VERSION 5.8 ;
BUSBITCHARS "[]" ;
DIVIDERCHAR "/" ;
UNITS
    DATABASE MICRONS 1000 ;
END UNITS

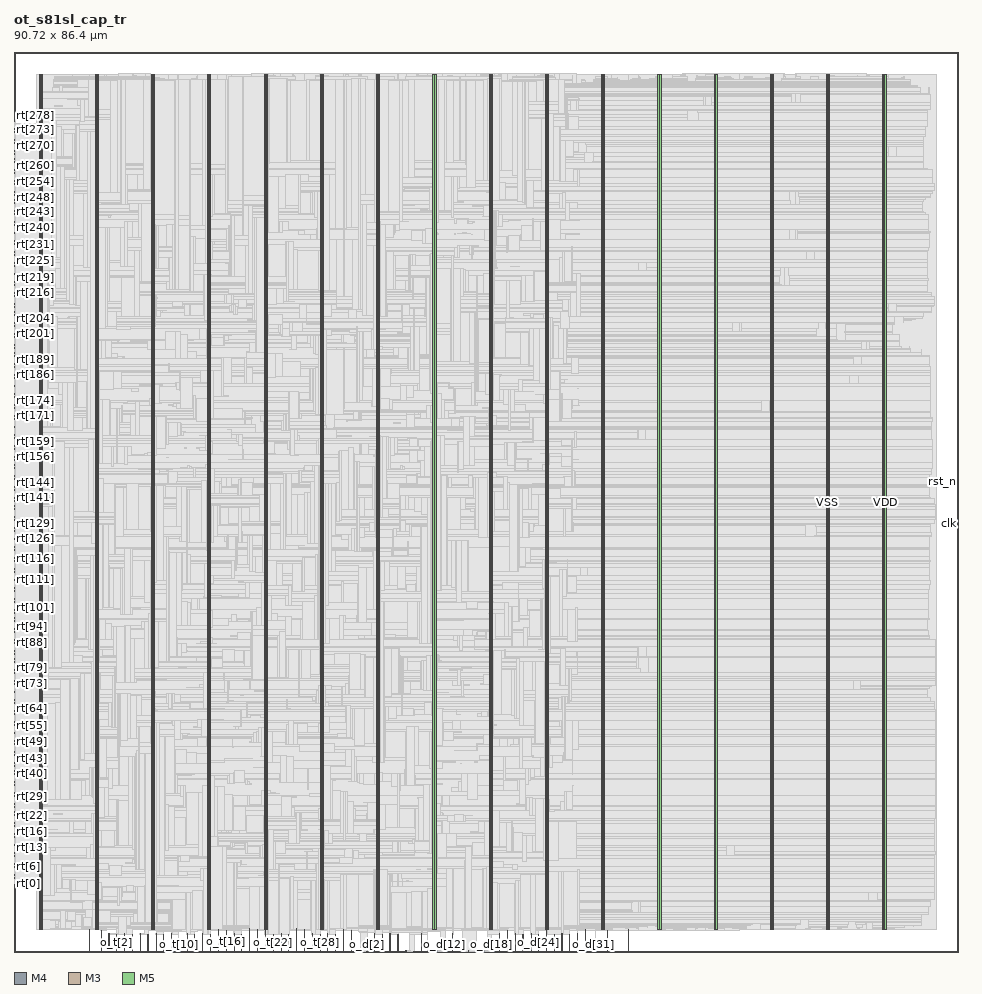
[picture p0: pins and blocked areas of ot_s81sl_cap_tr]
MACRO ot_s81sl_cap_tr
  FOREIGN ot_s81sl_cap_tr 0 0 ;
  CLASS BLOCK ;
  SIZE 90.72 BY 86.4 ;
  PIN clk
    DIRECTION INPUT ;
    USE SIGNAL ;
    PORT
      LAYER M4 ;
        RECT  90.636 41.04 90.72 41.064 ;
    END
    PORT
      LAYER M4 ;
        RECT  90.601 41.04 90.641 41.16 ;
    END
    PORT
      LAYER M4 ;
        RECT  90.641 41.04 90.684 41.064 ;
    END
  END clk
  PIN fault
    DIRECTION OUTPUT ;
    USE SIGNAL ;
    PORT
      LAYER M3 ;
        RECT  59.004 0 59.022 0.038 ;
    END
    PORT
      LAYER M3 ;
        RECT  59.004 0.012 59.022 2.191 ;
    END
  END fault
  PIN o_d[0]
    DIRECTION OUTPUT ;
    USE SIGNAL ;
    PORT
      LAYER M3 ;
        RECT  32.364 0 32.382 0.038 ;
    END
    PORT
      LAYER M3 ;
        RECT  32.364 0.012 32.382 2.029 ;
    END
  END o_d[0]
  PIN o_d[10]
    DIRECTION OUTPUT ;
    USE SIGNAL ;
    PORT
      LAYER M3 ;
        RECT  39.852 0 39.87 0.038 ;
    END
    PORT
      LAYER M3 ;
        RECT  39.852 0.012 39.87 0.031 ;
    END
    PORT
      LAYER M3 ;
        RECT  39.708 0.031 39.87 0.059 ;
    END
  END o_d[10]
  PIN o_d[11]
    DIRECTION OUTPUT ;
    USE SIGNAL ;
    PORT
      LAYER M5 ;
        RECT  40.608 0 40.632 0.084 ;
    END
    PORT
      LAYER M5 ;
        RECT  40.608 0.016 40.632 0.131 ;
    END
  END o_d[11]
  PIN o_d[12]
    DIRECTION OUTPUT ;
    USE SIGNAL ;
    PORT
      LAYER M3 ;
        RECT  41.364 0 41.382 0.038 ;
    END
    PORT
      LAYER M3 ;
        RECT  41.364 0.012 41.382 0.091 ;
    END
  END o_d[12]
  PIN o_d[13]
    DIRECTION OUTPUT ;
    USE SIGNAL ;
    PORT
      LAYER M5 ;
        RECT  42.096 0 42.12 0.084 ;
    END
    PORT
      LAYER M5 ;
        RECT  42.096 0.016 42.12 1.763 ;
    END
  END o_d[13]
  PIN o_d[14]
    DIRECTION OUTPUT ;
    USE SIGNAL ;
    PORT
      LAYER M3 ;
        RECT  42.876 0 42.894 0.038 ;
    END
    PORT
      LAYER M3 ;
        RECT  42.876 0.012 42.894 0.031 ;
    END
    PORT
      LAYER M3 ;
        RECT  42.876 0.031 43.11 0.059 ;
    END
  END o_d[14]
  PIN o_d[15]
    DIRECTION OUTPUT ;
    USE SIGNAL ;
    PORT
      LAYER M5 ;
        RECT  43.632 0 43.656 0.084 ;
    END
    PORT
      LAYER M5 ;
        RECT  43.632 0.016 43.656 0.131 ;
    END
  END o_d[15]
  PIN o_d[16]
    DIRECTION OUTPUT ;
    USE SIGNAL ;
    PORT
      LAYER M3 ;
        RECT  44.352 0 44.37 0.038 ;
    END
    PORT
      LAYER M3 ;
        RECT  44.352 0.012 44.37 0.091 ;
    END
  END o_d[16]
  PIN o_d[17]
    DIRECTION OUTPUT ;
    USE SIGNAL ;
    PORT
      LAYER M5 ;
        RECT  45.12 0 45.144 0.084 ;
    END
    PORT
      LAYER M5 ;
        RECT  45.12 0.016 45.144 0.131 ;
    END
  END o_d[17]
  PIN o_d[18]
    DIRECTION OUTPUT ;
    USE SIGNAL ;
    PORT
      LAYER M3 ;
        RECT  45.864 0 45.882 0.038 ;
    END
    PORT
      LAYER M3 ;
        RECT  45.864 0.012 45.882 0.091 ;
    END
  END o_d[18]
  PIN o_d[19]
    DIRECTION OUTPUT ;
    USE SIGNAL ;
    PORT
      LAYER M5 ;
        RECT  46.608 0 46.632 0.084 ;
    END
    PORT
      LAYER M5 ;
        RECT  46.608 0.016 46.632 1.763 ;
    END
  END o_d[19]
  PIN o_d[1]
    DIRECTION OUTPUT ;
    USE SIGNAL ;
    PORT
      LAYER M5 ;
        RECT  33.12 0 33.144 0.084 ;
    END
    PORT
      LAYER M5 ;
        RECT  33.12 0.016 33.144 0.131 ;
    END
  END o_d[1]
  PIN o_d[20]
    DIRECTION OUTPUT ;
    USE SIGNAL ;
    PORT
      LAYER M3 ;
        RECT  47.376 0 47.394 0.038 ;
    END
    PORT
      LAYER M3 ;
        RECT  47.376 0.012 47.394 2.029 ;
    END
  END o_d[20]
  PIN o_d[21]
    DIRECTION OUTPUT ;
    USE SIGNAL ;
    PORT
      LAYER M5 ;
        RECT  48.096 0 48.12 0.084 ;
    END
    PORT
      LAYER M5 ;
        RECT  48.096 0.016 48.12 1.763 ;
    END
  END o_d[21]
  PIN o_d[22]
    DIRECTION OUTPUT ;
    USE SIGNAL ;
    PORT
      LAYER M3 ;
        RECT  48.852 0 48.87 0.038 ;
    END
    PORT
      LAYER M3 ;
        RECT  48.852 0.012 48.87 1.723 ;
    END
  END o_d[22]
  PIN o_d[23]
    DIRECTION OUTPUT ;
    USE SIGNAL ;
    PORT
      LAYER M5 ;
        RECT  49.632 0 49.656 0.084 ;
    END
    PORT
      LAYER M5 ;
        RECT  49.632 0.016 49.656 1.763 ;
    END
  END o_d[23]
  PIN o_d[24]
    DIRECTION OUTPUT ;
    USE SIGNAL ;
    PORT
      LAYER M3 ;
        RECT  50.364 0 50.382 0.038 ;
    END
    PORT
      LAYER M3 ;
        RECT  50.364 0.012 50.382 1.723 ;
    END
  END o_d[24]
  PIN o_d[25]
    DIRECTION OUTPUT ;
    USE SIGNAL ;
    PORT
      LAYER M5 ;
        RECT  51.12 0 51.144 0.084 ;
    END
    PORT
      LAYER M5 ;
        RECT  51.12 0.016 51.144 2.137 ;
    END
  END o_d[25]
  PIN o_d[26]
    DIRECTION OUTPUT ;
    USE SIGNAL ;
    PORT
      LAYER M3 ;
        RECT  51.876 0 51.894 0.038 ;
    END
    PORT
      LAYER M3 ;
        RECT  51.876 0.012 51.894 1.723 ;
    END
  END o_d[26]
  PIN o_d[27]
    DIRECTION OUTPUT ;
    USE SIGNAL ;
    PORT
      LAYER M5 ;
        RECT  52.608 0 52.632 0.084 ;
    END
    PORT
      LAYER M5 ;
        RECT  52.608 0.016 52.632 1.763 ;
    END
  END o_d[27]
  PIN o_d[28]
    DIRECTION OUTPUT ;
    USE SIGNAL ;
    PORT
      LAYER M3 ;
        RECT  53.352 0 53.37 0.038 ;
    END
    PORT
      LAYER M3 ;
        RECT  53.352 0.012 53.37 1.723 ;
    END
  END o_d[28]
  PIN o_d[29]
    DIRECTION OUTPUT ;
    USE SIGNAL ;
    PORT
      LAYER M5 ;
        RECT  54.096 0 54.12 0.084 ;
    END
    PORT
      LAYER M5 ;
        RECT  54.096 0.016 54.12 1.763 ;
    END
  END o_d[29]
  PIN o_d[2]
    DIRECTION OUTPUT ;
    USE SIGNAL ;
    PORT
      LAYER M3 ;
        RECT  33.876 0 33.894 0.038 ;
    END
    PORT
      LAYER M3 ;
        RECT  33.876 0.012 33.894 0.091 ;
    END
  END o_d[2]
  PIN o_d[30]
    DIRECTION OUTPUT ;
    USE SIGNAL ;
    PORT
      LAYER M3 ;
        RECT  54.864 0 54.882 0.038 ;
    END
    PORT
      LAYER M3 ;
        RECT  54.864 0.012 54.882 2.191 ;
    END
  END o_d[30]
  PIN o_d[31]
    DIRECTION OUTPUT ;
    USE SIGNAL ;
    PORT
      LAYER M5 ;
        RECT  55.632 0 55.656 0.084 ;
    END
    PORT
      LAYER M5 ;
        RECT  55.632 0.016 55.656 0.611 ;
    END
  END o_d[31]
  PIN o_d[3]
    DIRECTION OUTPUT ;
    USE SIGNAL ;
    PORT
      LAYER M5 ;
        RECT  34.608 0 34.632 0.084 ;
    END
    PORT
      LAYER M5 ;
        RECT  34.608 0.016 34.632 1.763 ;
    END
  END o_d[3]
  PIN o_d[4]
    DIRECTION OUTPUT ;
    USE SIGNAL ;
    PORT
      LAYER M3 ;
        RECT  35.352 0 35.37 0.038 ;
    END
    PORT
      LAYER M3 ;
        RECT  35.352 0.012 35.37 1.723 ;
    END
  END o_d[4]
  PIN o_d[5]
    DIRECTION OUTPUT ;
    USE SIGNAL ;
    PORT
      LAYER M5 ;
        RECT  36.096 0 36.12 0.084 ;
    END
    PORT
      LAYER M5 ;
        RECT  36.096 0.016 36.12 1.763 ;
    END
  END o_d[5]
  PIN o_d[6]
    DIRECTION OUTPUT ;
    USE SIGNAL ;
    PORT
      LAYER M3 ;
        RECT  36.864 0 36.882 0.038 ;
    END
    PORT
      LAYER M3 ;
        RECT  36.864 0.012 36.882 1.723 ;
    END
  END o_d[6]
  PIN o_d[7]
    DIRECTION OUTPUT ;
    USE SIGNAL ;
    PORT
      LAYER M5 ;
        RECT  37.632 0 37.656 0.084 ;
    END
    PORT
      LAYER M5 ;
        RECT  37.632 0.016 37.656 0.131 ;
    END
  END o_d[7]
  PIN o_d[8]
    DIRECTION OUTPUT ;
    USE SIGNAL ;
    PORT
      LAYER M3 ;
        RECT  38.376 0 38.394 0.038 ;
    END
    PORT
      LAYER M3 ;
        RECT  38.376 0.012 38.394 0.031 ;
    END
    PORT
      LAYER M3 ;
        RECT  38.376 0.031 38.466 0.091 ;
    END
  END o_d[8]
  PIN o_d[9]
    DIRECTION OUTPUT ;
    USE SIGNAL ;
    PORT
      LAYER M5 ;
        RECT  39.12 0 39.144 0.084 ;
    END
    PORT
      LAYER M5 ;
        RECT  39.12 0.016 39.144 1.763 ;
    END
  END o_d[9]
  PIN o_e
    DIRECTION OUTPUT ;
    USE SIGNAL ;
    PORT
      LAYER M3 ;
        RECT  56.988 0 57.006 0.038 ;
    END
    PORT
      LAYER M3 ;
        RECT  56.988 0.012 57.006 2.029 ;
    END
  END o_e
  PIN o_t[0]
    DIRECTION OUTPUT ;
    USE SIGNAL ;
    PORT
      LAYER M3 ;
        RECT  8.352 0 8.37 0.038 ;
    END
    PORT
      LAYER M3 ;
        RECT  8.352 0.012 8.37 2.101 ;
    END
  END o_t[0]
  PIN o_t[10]
    DIRECTION OUTPUT ;
    USE SIGNAL ;
    PORT
      LAYER M3 ;
        RECT  15.876 0 15.894 0.038 ;
    END
    PORT
      LAYER M3 ;
        RECT  15.876 0.012 15.894 0.031 ;
    END
    PORT
      LAYER M3 ;
        RECT  15.804 0.031 15.894 0.059 ;
    END
  END o_t[10]
  PIN o_t[11]
    DIRECTION OUTPUT ;
    USE SIGNAL ;
    PORT
      LAYER M5 ;
        RECT  16.608 0 16.632 0.084 ;
    END
    PORT
      LAYER M5 ;
        RECT  16.608 0.016 16.632 1.763 ;
    END
  END o_t[11]
  PIN o_t[12]
    DIRECTION OUTPUT ;
    USE SIGNAL ;
    PORT
      LAYER M3 ;
        RECT  17.352 0 17.37 0.038 ;
    END
    PORT
      LAYER M3 ;
        RECT  17.352 0.012 17.37 1.723 ;
    END
  END o_t[12]
  PIN o_t[13]
    DIRECTION OUTPUT ;
    USE SIGNAL ;
    PORT
      LAYER M5 ;
        RECT  18.096 0 18.12 0.084 ;
    END
    PORT
      LAYER M5 ;
        RECT  18.096 0.016 18.12 1.763 ;
    END
  END o_t[13]
  PIN o_t[14]
    DIRECTION OUTPUT ;
    USE SIGNAL ;
    PORT
      LAYER M3 ;
        RECT  18.864 0 18.882 0.038 ;
    END
    PORT
      LAYER M3 ;
        RECT  18.864 0.012 18.882 1.723 ;
    END
  END o_t[14]
  PIN o_t[15]
    DIRECTION OUTPUT ;
    USE SIGNAL ;
    PORT
      LAYER M5 ;
        RECT  19.632 0 19.656 0.084 ;
    END
    PORT
      LAYER M5 ;
        RECT  19.632 0.016 19.656 2.137 ;
    END
  END o_t[15]
  PIN o_t[16]
    DIRECTION OUTPUT ;
    USE SIGNAL ;
    PORT
      LAYER M3 ;
        RECT  20.376 0 20.394 0.038 ;
    END
    PORT
      LAYER M3 ;
        RECT  20.376 0.012 20.394 2.029 ;
    END
  END o_t[16]
  PIN o_t[17]
    DIRECTION OUTPUT ;
    USE SIGNAL ;
    PORT
      LAYER M5 ;
        RECT  21.12 0 21.144 0.084 ;
    END
    PORT
      LAYER M5 ;
        RECT  21.12 0.016 21.144 1.763 ;
    END
  END o_t[17]
  PIN o_t[18]
    DIRECTION OUTPUT ;
    USE SIGNAL ;
    PORT
      LAYER M3 ;
        RECT  21.852 0 21.87 0.038 ;
    END
    PORT
      LAYER M3 ;
        RECT  21.852 0.012 21.87 1.723 ;
    END
  END o_t[18]
  PIN o_t[19]
    DIRECTION OUTPUT ;
    USE SIGNAL ;
    PORT
      LAYER M5 ;
        RECT  22.608 0 22.632 0.084 ;
    END
    PORT
      LAYER M5 ;
        RECT  22.608 0.016 22.632 2.243 ;
    END
  END o_t[19]
  PIN o_t[1]
    DIRECTION OUTPUT ;
    USE SIGNAL ;
    PORT
      LAYER M5 ;
        RECT  9.12 0 9.144 0.084 ;
    END
    PORT
      LAYER M5 ;
        RECT  9.12 0.016 9.144 1.763 ;
    END
  END o_t[1]
  PIN o_t[20]
    DIRECTION OUTPUT ;
    USE SIGNAL ;
    PORT
      LAYER M3 ;
        RECT  23.364 0 23.382 0.038 ;
    END
    PORT
      LAYER M3 ;
        RECT  23.364 0.012 23.382 2.143 ;
    END
  END o_t[20]
  PIN o_t[21]
    DIRECTION OUTPUT ;
    USE SIGNAL ;
    PORT
      LAYER M5 ;
        RECT  24.096 0 24.12 0.084 ;
    END
    PORT
      LAYER M5 ;
        RECT  24.096 0.016 24.12 2.137 ;
    END
  END o_t[21]
  PIN o_t[22]
    DIRECTION OUTPUT ;
    USE SIGNAL ;
    PORT
      LAYER M3 ;
        RECT  24.876 0 24.894 0.038 ;
    END
    PORT
      LAYER M3 ;
        RECT  24.876 0.012 24.894 1.723 ;
    END
  END o_t[22]
  PIN o_t[23]
    DIRECTION OUTPUT ;
    USE SIGNAL ;
    PORT
      LAYER M5 ;
        RECT  25.632 0 25.656 0.084 ;
    END
    PORT
      LAYER M5 ;
        RECT  25.632 0.016 25.656 1.763 ;
    END
  END o_t[23]
  PIN o_t[24]
    DIRECTION OUTPUT ;
    USE SIGNAL ;
    PORT
      LAYER M3 ;
        RECT  26.352 0 26.37 0.038 ;
    END
    PORT
      LAYER M3 ;
        RECT  26.352 0.012 26.37 1.723 ;
    END
  END o_t[24]
  PIN o_t[25]
    DIRECTION OUTPUT ;
    USE SIGNAL ;
    PORT
      LAYER M5 ;
        RECT  27.12 0 27.144 0.084 ;
    END
    PORT
      LAYER M5 ;
        RECT  27.12 0.016 27.144 2.243 ;
    END
  END o_t[25]
  PIN o_t[26]
    DIRECTION OUTPUT ;
    USE SIGNAL ;
    PORT
      LAYER M3 ;
        RECT  27.864 0 27.882 0.038 ;
    END
    PORT
      LAYER M3 ;
        RECT  27.864 0.012 27.882 2.203 ;
    END
  END o_t[26]
  PIN o_t[27]
    DIRECTION OUTPUT ;
    USE SIGNAL ;
    PORT
      LAYER M5 ;
        RECT  28.608 0 28.632 0.084 ;
    END
    PORT
      LAYER M5 ;
        RECT  28.608 0.016 28.632 1.763 ;
    END
  END o_t[27]
  PIN o_t[28]
    DIRECTION OUTPUT ;
    USE SIGNAL ;
    PORT
      LAYER M3 ;
        RECT  29.376 0 29.394 0.038 ;
    END
    PORT
      LAYER M3 ;
        RECT  29.376 0.012 29.394 1.723 ;
    END
  END o_t[28]
  PIN o_t[29]
    DIRECTION OUTPUT ;
    USE SIGNAL ;
    PORT
      LAYER M5 ;
        RECT  30.096 0 30.12 0.084 ;
    END
    PORT
      LAYER M5 ;
        RECT  30.096 0.016 30.12 1.763 ;
    END
  END o_t[29]
  PIN o_t[2]
    DIRECTION OUTPUT ;
    USE SIGNAL ;
    PORT
      LAYER M3 ;
        RECT  9.864 0 9.882 0.038 ;
    END
    PORT
      LAYER M3 ;
        RECT  9.864 0.012 9.882 1.723 ;
    END
  END o_t[2]
  PIN o_t[30]
    DIRECTION OUTPUT ;
    USE SIGNAL ;
    PORT
      LAYER M3 ;
        RECT  30.852 0 30.87 0.038 ;
    END
    PORT
      LAYER M3 ;
        RECT  30.852 0.012 30.87 1.723 ;
    END
  END o_t[30]
  PIN o_t[31]
    DIRECTION OUTPUT ;
    USE SIGNAL ;
    PORT
      LAYER M5 ;
        RECT  31.632 0 31.656 0.084 ;
    END
    PORT
      LAYER M5 ;
        RECT  31.632 0.016 31.656 2.195 ;
    END
  END o_t[31]
  PIN o_t[3]
    DIRECTION OUTPUT ;
    USE SIGNAL ;
    PORT
      LAYER M5 ;
        RECT  10.608 0 10.632 0.084 ;
    END
    PORT
      LAYER M5 ;
        RECT  10.608 0.016 10.632 1.763 ;
    END
  END o_t[3]
  PIN o_t[4]
    DIRECTION OUTPUT ;
    USE SIGNAL ;
    PORT
      LAYER M3 ;
        RECT  11.376 0 11.394 0.038 ;
    END
    PORT
      LAYER M3 ;
        RECT  11.376 0.012 11.394 1.723 ;
    END
  END o_t[4]
  PIN o_t[5]
    DIRECTION OUTPUT ;
    USE SIGNAL ;
    PORT
      LAYER M5 ;
        RECT  12.096 0 12.12 0.084 ;
    END
    PORT
      LAYER M5 ;
        RECT  12.096 0.016 12.12 1.763 ;
    END
  END o_t[5]
  PIN o_t[6]
    DIRECTION OUTPUT ;
    USE SIGNAL ;
    PORT
      LAYER M3 ;
        RECT  12.852 0 12.87 0.038 ;
    END
    PORT
      LAYER M3 ;
        RECT  12.852 0.012 12.87 1.723 ;
    END
  END o_t[6]
  PIN o_t[7]
    DIRECTION OUTPUT ;
    USE SIGNAL ;
    PORT
      LAYER M5 ;
        RECT  13.632 0 13.656 0.084 ;
    END
    PORT
      LAYER M5 ;
        RECT  13.632 0.016 13.656 1.763 ;
    END
  END o_t[7]
  PIN o_t[8]
    DIRECTION OUTPUT ;
    USE SIGNAL ;
    PORT
      LAYER M3 ;
        RECT  14.364 0 14.382 0.038 ;
    END
    PORT
      LAYER M3 ;
        RECT  14.364 0.012 14.382 1.723 ;
    END
  END o_t[8]
  PIN o_t[9]
    DIRECTION OUTPUT ;
    USE SIGNAL ;
    PORT
      LAYER M5 ;
        RECT  15.12 0 15.144 0.084 ;
    END
    PORT
      LAYER M5 ;
        RECT  15.12 0.016 15.144 1.763 ;
    END
  END o_t[9]
  PIN o_v
    DIRECTION OUTPUT ;
    USE SIGNAL ;
    PORT
      LAYER M3 ;
        RECT  7.236 0 7.254 0.038 ;
    END
    PORT
      LAYER M3 ;
        RECT  7.236 0.012 7.254 2.143 ;
    END
  END o_v
  PIN rst_n
    DIRECTION INPUT ;
    USE SIGNAL ;
    PORT
      LAYER M4 ;
        RECT  90.636 45.36 90.72 45.384 ;
    END
    PORT
      LAYER M4 ;
        RECT  90.601 45.024 90.641 45.384 ;
    END
    PORT
      LAYER M4 ;
        RECT  90.641 45.36 90.684 45.384 ;
    END
  END rst_n
  PIN rt[0]
    DIRECTION INPUT ;
    USE SIGNAL ;
    PORT
      LAYER M4 ;
        RECT  0 6.576 0.084 6.6 ;
    END
  END rt[0]
  PIN rt[100]
    DIRECTION INPUT ;
    USE SIGNAL ;
    PORT
      LAYER M4 ;
        RECT  0 32.832 0.084 32.856 ;
    END
  END rt[100]
  PIN rt[101]
    DIRECTION INPUT ;
    USE SIGNAL ;
    PORT
      LAYER M4 ;
        RECT  0 33.072 0.084 33.096 ;
    END
  END rt[101]
  PIN rt[102]
    DIRECTION INPUT ;
    USE SIGNAL ;
    PORT
      LAYER M4 ;
        RECT  0 33.36 0.084 33.384 ;
    END
  END rt[102]
  PIN rt[103]
    DIRECTION INPUT ;
    USE SIGNAL ;
    PORT
      LAYER M4 ;
        RECT  0 33.6 0.084 33.624 ;
    END
  END rt[103]
  PIN rt[104]
    DIRECTION INPUT ;
    USE SIGNAL ;
    PORT
      LAYER M4 ;
        RECT  0 33.888 0.084 33.912 ;
    END
  END rt[104]
  PIN rt[105]
    DIRECTION INPUT ;
    USE SIGNAL ;
    PORT
      LAYER M4 ;
        RECT  0 34.128 0.084 34.152 ;
    END
  END rt[105]
  PIN rt[106]
    DIRECTION INPUT ;
    USE SIGNAL ;
    PORT
      LAYER M4 ;
        RECT  0 34.416 0.084 34.44 ;
    END
  END rt[106]
  PIN rt[107]
    DIRECTION INPUT ;
    USE SIGNAL ;
    PORT
      LAYER M4 ;
        RECT  0 34.656 0.084 34.68 ;
    END
  END rt[107]
  PIN rt[108]
    DIRECTION INPUT ;
    USE SIGNAL ;
    PORT
      LAYER M4 ;
        RECT  0 34.944 0.084 34.968 ;
    END
  END rt[108]
  PIN rt[109]
    DIRECTION INPUT ;
    USE SIGNAL ;
    PORT
      LAYER M4 ;
        RECT  0 35.184 0.084 35.208 ;
    END
  END rt[109]
  PIN rt[10]
    DIRECTION INPUT ;
    USE SIGNAL ;
    PORT
      LAYER M4 ;
        RECT  0 9.216 0.084 9.24 ;
    END
  END rt[10]
  PIN rt[110]
    DIRECTION INPUT ;
    USE SIGNAL ;
    PORT
      LAYER M4 ;
        RECT  0 35.472 0.084 35.496 ;
    END
  END rt[110]
  PIN rt[111]
    DIRECTION INPUT ;
    USE SIGNAL ;
    PORT
      LAYER M4 ;
        RECT  0 35.712 0.084 35.736 ;
    END
  END rt[111]
  PIN rt[112]
    DIRECTION INPUT ;
    USE SIGNAL ;
    PORT
      LAYER M4 ;
        RECT  0 35.952 0.084 35.976 ;
    END
  END rt[112]
  PIN rt[113]
    DIRECTION INPUT ;
    USE SIGNAL ;
    PORT
      LAYER M4 ;
        RECT  0 36.24 0.084 36.264 ;
    END
  END rt[113]
  PIN rt[114]
    DIRECTION INPUT ;
    USE SIGNAL ;
    PORT
      LAYER M4 ;
        RECT  0 36.48 0.084 36.504 ;
    END
  END rt[114]
  PIN rt[115]
    DIRECTION INPUT ;
    USE SIGNAL ;
    PORT
      LAYER M4 ;
        RECT  0 36.768 0.084 36.792 ;
    END
  END rt[115]
  PIN rt[116]
    DIRECTION INPUT ;
    USE SIGNAL ;
    PORT
      LAYER M4 ;
        RECT  0 37.008 0.084 37.032 ;
    END
  END rt[116]
  PIN rt[117]
    DIRECTION INPUT ;
    USE SIGNAL ;
    PORT
      LAYER M4 ;
        RECT  0 37.296 0.084 37.32 ;
    END
  END rt[117]
  PIN rt[118]
    DIRECTION INPUT ;
    USE SIGNAL ;
    PORT
      LAYER M4 ;
        RECT  0 37.536 0.084 37.56 ;
    END
  END rt[118]
  PIN rt[119]
    DIRECTION INPUT ;
    USE SIGNAL ;
    PORT
      LAYER M4 ;
        RECT  0 37.824 0.084 37.848 ;
    END
  END rt[119]
  PIN rt[11]
    DIRECTION INPUT ;
    USE SIGNAL ;
    PORT
      LAYER M4 ;
        RECT  0 9.504 0.084 9.528 ;
    END
  END rt[11]
  PIN rt[120]
    DIRECTION INPUT ;
    USE SIGNAL ;
    PORT
      LAYER M4 ;
        RECT  0 38.064 0.084 38.088 ;
    END
  END rt[120]
  PIN rt[121]
    DIRECTION INPUT ;
    USE SIGNAL ;
    PORT
      LAYER M4 ;
        RECT  0 38.352 0.084 38.376 ;
    END
  END rt[121]
  PIN rt[122]
    DIRECTION INPUT ;
    USE SIGNAL ;
    PORT
      LAYER M4 ;
        RECT  0 38.592 0.084 38.616 ;
    END
  END rt[122]
  PIN rt[123]
    DIRECTION INPUT ;
    USE SIGNAL ;
    PORT
      LAYER M4 ;
        RECT  0 38.88 0.084 38.904 ;
    END
  END rt[123]
  PIN rt[124]
    DIRECTION INPUT ;
    USE SIGNAL ;
    PORT
      LAYER M4 ;
        RECT  0 39.12 0.084 39.144 ;
    END
  END rt[124]
  PIN rt[125]
    DIRECTION INPUT ;
    USE SIGNAL ;
    PORT
      LAYER M4 ;
        RECT  0 39.408 0.084 39.432 ;
    END
  END rt[125]
  PIN rt[126]
    DIRECTION INPUT ;
    USE SIGNAL ;
    PORT
      LAYER M4 ;
        RECT  0 39.648 0.084 39.672 ;
    END
  END rt[126]
  PIN rt[127]
    DIRECTION INPUT ;
    USE SIGNAL ;
    PORT
      LAYER M4 ;
        RECT  0 39.888 0.084 39.912 ;
    END
  END rt[127]
  PIN rt[128]
    DIRECTION INPUT ;
    USE SIGNAL ;
    PORT
      LAYER M4 ;
        RECT  0 40.176 0.084 40.2 ;
    END
  END rt[128]
  PIN rt[129]
    DIRECTION INPUT ;
    USE SIGNAL ;
    PORT
      LAYER M4 ;
        RECT  0 40.416 0.084 40.44 ;
    END
  END rt[129]
  PIN rt[12]
    DIRECTION INPUT ;
    USE SIGNAL ;
    PORT
      LAYER M4 ;
        RECT  0 9.744 0.084 9.768 ;
    END
  END rt[12]
  PIN rt[130]
    DIRECTION INPUT ;
    USE SIGNAL ;
    PORT
      LAYER M4 ;
        RECT  0 40.704 0.084 40.728 ;
    END
  END rt[130]
  PIN rt[131]
    DIRECTION INPUT ;
    USE SIGNAL ;
    PORT
      LAYER M4 ;
        RECT  0 40.944 0.084 40.968 ;
    END
  END rt[131]
  PIN rt[132]
    DIRECTION INPUT ;
    USE SIGNAL ;
    PORT
      LAYER M4 ;
        RECT  0 41.232 0.084 41.256 ;
    END
  END rt[132]
  PIN rt[133]
    DIRECTION INPUT ;
    USE SIGNAL ;
    PORT
      LAYER M4 ;
        RECT  0 41.472 0.084 41.496 ;
    END
  END rt[133]
  PIN rt[134]
    DIRECTION INPUT ;
    USE SIGNAL ;
    PORT
      LAYER M4 ;
        RECT  0 41.76 0.084 41.784 ;
    END
  END rt[134]
  PIN rt[135]
    DIRECTION INPUT ;
    USE SIGNAL ;
    PORT
      LAYER M4 ;
        RECT  0 42 0.084 42.024 ;
    END
  END rt[135]
  PIN rt[136]
    DIRECTION INPUT ;
    USE SIGNAL ;
    PORT
      LAYER M4 ;
        RECT  0 42.288 0.084 42.312 ;
    END
  END rt[136]
  PIN rt[137]
    DIRECTION INPUT ;
    USE SIGNAL ;
    PORT
      LAYER M4 ;
        RECT  0 42.528 0.084 42.552 ;
    END
  END rt[137]
  PIN rt[138]
    DIRECTION INPUT ;
    USE SIGNAL ;
    PORT
      LAYER M4 ;
        RECT  0 42.816 0.084 42.84 ;
    END
  END rt[138]
  PIN rt[139]
    DIRECTION INPUT ;
    USE SIGNAL ;
    PORT
      LAYER M4 ;
        RECT  0 43.056 0.084 43.08 ;
    END
  END rt[139]
  PIN rt[13]
    DIRECTION INPUT ;
    USE SIGNAL ;
    PORT
      LAYER M4 ;
        RECT  0 10.032 0.084 10.056 ;
    END
  END rt[13]
  PIN rt[140]
    DIRECTION INPUT ;
    USE SIGNAL ;
    PORT
      LAYER M4 ;
        RECT  0 43.296 0.084 43.32 ;
    END
  END rt[140]
  PIN rt[141]
    DIRECTION INPUT ;
    USE SIGNAL ;
    PORT
      LAYER M4 ;
        RECT  0 43.584 0.084 43.608 ;
    END
  END rt[141]
  PIN rt[142]
    DIRECTION INPUT ;
    USE SIGNAL ;
    PORT
      LAYER M4 ;
        RECT  0 43.824 0.084 43.848 ;
    END
  END rt[142]
  PIN rt[143]
    DIRECTION INPUT ;
    USE SIGNAL ;
    PORT
      LAYER M4 ;
        RECT  0 44.112 0.084 44.136 ;
    END
  END rt[143]
  PIN rt[144]
    DIRECTION INPUT ;
    USE SIGNAL ;
    PORT
      LAYER M4 ;
        RECT  0 44.352 0.084 44.376 ;
    END
  END rt[144]
  PIN rt[145]
    DIRECTION INPUT ;
    USE SIGNAL ;
    PORT
      LAYER M4 ;
        RECT  0 44.64 0.084 44.664 ;
    END
  END rt[145]
  PIN rt[146]
    DIRECTION INPUT ;
    USE SIGNAL ;
    PORT
      LAYER M4 ;
        RECT  0 44.88 0.084 44.904 ;
    END
  END rt[146]
  PIN rt[147]
    DIRECTION INPUT ;
    USE SIGNAL ;
    PORT
      LAYER M4 ;
        RECT  0 45.168 0.084 45.192 ;
    END
  END rt[147]
  PIN rt[148]
    DIRECTION INPUT ;
    USE SIGNAL ;
    PORT
      LAYER M4 ;
        RECT  0 45.408 0.084 45.432 ;
    END
  END rt[148]
  PIN rt[149]
    DIRECTION INPUT ;
    USE SIGNAL ;
    PORT
      LAYER M4 ;
        RECT  0 45.696 0.084 45.72 ;
    END
  END rt[149]
  PIN rt[14]
    DIRECTION INPUT ;
    USE SIGNAL ;
    PORT
      LAYER M4 ;
        RECT  0 10.272 0.084 10.296 ;
    END
  END rt[14]
  PIN rt[150]
    DIRECTION INPUT ;
    USE SIGNAL ;
    PORT
      LAYER M4 ;
        RECT  0 45.936 0.084 45.96 ;
    END
  END rt[150]
  PIN rt[151]
    DIRECTION INPUT ;
    USE SIGNAL ;
    PORT
      LAYER M4 ;
        RECT  0 46.224 0.084 46.248 ;
    END
  END rt[151]
  PIN rt[152]
    DIRECTION INPUT ;
    USE SIGNAL ;
    PORT
      LAYER M4 ;
        RECT  0 46.464 0.084 46.488 ;
    END
  END rt[152]
  PIN rt[153]
    DIRECTION INPUT ;
    USE SIGNAL ;
    PORT
      LAYER M4 ;
        RECT  0 46.752 0.084 46.776 ;
    END
  END rt[153]
  PIN rt[154]
    DIRECTION INPUT ;
    USE SIGNAL ;
    PORT
      LAYER M4 ;
        RECT  0 46.992 0.084 47.016 ;
    END
  END rt[154]
  PIN rt[155]
    DIRECTION INPUT ;
    USE SIGNAL ;
    PORT
      LAYER M4 ;
        RECT  0 47.232 0.084 47.256 ;
    END
  END rt[155]
  PIN rt[156]
    DIRECTION INPUT ;
    USE SIGNAL ;
    PORT
      LAYER M4 ;
        RECT  0 47.52 0.084 47.544 ;
    END
  END rt[156]
  PIN rt[157]
    DIRECTION INPUT ;
    USE SIGNAL ;
    PORT
      LAYER M4 ;
        RECT  0 47.76 0.084 47.784 ;
    END
  END rt[157]
  PIN rt[158]
    DIRECTION INPUT ;
    USE SIGNAL ;
    PORT
      LAYER M4 ;
        RECT  0 48.048 0.084 48.072 ;
    END
  END rt[158]
  PIN rt[159]
    DIRECTION INPUT ;
    USE SIGNAL ;
    PORT
      LAYER M4 ;
        RECT  0 48.288 0.084 48.312 ;
    END
  END rt[159]
  PIN rt[15]
    DIRECTION INPUT ;
    USE SIGNAL ;
    PORT
      LAYER M4 ;
        RECT  0 10.512 0.084 10.536 ;
    END
  END rt[15]
  PIN rt[160]
    DIRECTION INPUT ;
    USE SIGNAL ;
    PORT
      LAYER M4 ;
        RECT  0 48.576 0.084 48.6 ;
    END
  END rt[160]
  PIN rt[161]
    DIRECTION INPUT ;
    USE SIGNAL ;
    PORT
      LAYER M4 ;
        RECT  0 48.816 0.084 48.84 ;
    END
  END rt[161]
  PIN rt[162]
    DIRECTION INPUT ;
    USE SIGNAL ;
    PORT
      LAYER M4 ;
        RECT  0 49.104 0.084 49.128 ;
    END
  END rt[162]
  PIN rt[163]
    DIRECTION INPUT ;
    USE SIGNAL ;
    PORT
      LAYER M4 ;
        RECT  0 49.344 0.084 49.368 ;
    END
  END rt[163]
  PIN rt[164]
    DIRECTION INPUT ;
    USE SIGNAL ;
    PORT
      LAYER M4 ;
        RECT  0 49.632 0.084 49.656 ;
    END
  END rt[164]
  PIN rt[165]
    DIRECTION INPUT ;
    USE SIGNAL ;
    PORT
      LAYER M4 ;
        RECT  0 49.872 0.084 49.896 ;
    END
  END rt[165]
  PIN rt[166]
    DIRECTION INPUT ;
    USE SIGNAL ;
    PORT
      LAYER M4 ;
        RECT  0 50.16 0.084 50.184 ;
    END
  END rt[166]
  PIN rt[167]
    DIRECTION INPUT ;
    USE SIGNAL ;
    PORT
      LAYER M4 ;
        RECT  0 50.4 0.084 50.424 ;
    END
  END rt[167]
  PIN rt[168]
    DIRECTION INPUT ;
    USE SIGNAL ;
    PORT
      LAYER M4 ;
        RECT  0 50.64 0.084 50.664 ;
    END
  END rt[168]
  PIN rt[169]
    DIRECTION INPUT ;
    USE SIGNAL ;
    PORT
      LAYER M4 ;
        RECT  0 50.928 0.084 50.952 ;
    END
  END rt[169]
  PIN rt[16]
    DIRECTION INPUT ;
    USE SIGNAL ;
    PORT
      LAYER M4 ;
        RECT  0 10.8 0.084 10.824 ;
    END
  END rt[16]
  PIN rt[170]
    DIRECTION INPUT ;
    USE SIGNAL ;
    PORT
      LAYER M4 ;
        RECT  0 51.168 0.084 51.192 ;
    END
  END rt[170]
  PIN rt[171]
    DIRECTION INPUT ;
    USE SIGNAL ;
    PORT
      LAYER M4 ;
        RECT  0 51.456 0.084 51.48 ;
    END
  END rt[171]
  PIN rt[172]
    DIRECTION INPUT ;
    USE SIGNAL ;
    PORT
      LAYER M4 ;
        RECT  0 51.696 0.084 51.72 ;
    END
  END rt[172]
  PIN rt[173]
    DIRECTION INPUT ;
    USE SIGNAL ;
    PORT
      LAYER M4 ;
        RECT  0 51.984 0.084 52.008 ;
    END
  END rt[173]
  PIN rt[174]
    DIRECTION INPUT ;
    USE SIGNAL ;
    PORT
      LAYER M4 ;
        RECT  0 52.224 0.084 52.248 ;
    END
  END rt[174]
  PIN rt[175]
    DIRECTION INPUT ;
    USE SIGNAL ;
    PORT
      LAYER M4 ;
        RECT  0 52.512 0.084 52.536 ;
    END
  END rt[175]
  PIN rt[176]
    DIRECTION INPUT ;
    USE SIGNAL ;
    PORT
      LAYER M4 ;
        RECT  0 52.752 0.084 52.776 ;
    END
  END rt[176]
  PIN rt[177]
    DIRECTION INPUT ;
    USE SIGNAL ;
    PORT
      LAYER M4 ;
        RECT  0 53.04 0.084 53.064 ;
    END
  END rt[177]
  PIN rt[178]
    DIRECTION INPUT ;
    USE SIGNAL ;
    PORT
      LAYER M4 ;
        RECT  0 53.28 0.084 53.304 ;
    END
  END rt[178]
  PIN rt[179]
    DIRECTION INPUT ;
    USE SIGNAL ;
    PORT
      LAYER M4 ;
        RECT  0 53.568 0.084 53.592 ;
    END
  END rt[179]
  PIN rt[17]
    DIRECTION INPUT ;
    USE SIGNAL ;
    PORT
      LAYER M4 ;
        RECT  0 11.04 0.084 11.064 ;
    END
  END rt[17]
  PIN rt[180]
    DIRECTION INPUT ;
    USE SIGNAL ;
    PORT
      LAYER M4 ;
        RECT  0 53.808 0.084 53.832 ;
    END
  END rt[180]
  PIN rt[181]
    DIRECTION INPUT ;
    USE SIGNAL ;
    PORT
      LAYER M4 ;
        RECT  0 54.096 0.084 54.12 ;
    END
  END rt[181]
  PIN rt[182]
    DIRECTION INPUT ;
    USE SIGNAL ;
    PORT
      LAYER M4 ;
        RECT  0 54.336 0.084 54.36 ;
    END
  END rt[182]
  PIN rt[183]
    DIRECTION INPUT ;
    USE SIGNAL ;
    PORT
      LAYER M4 ;
        RECT  0 54.576 0.084 54.6 ;
    END
  END rt[183]
  PIN rt[184]
    DIRECTION INPUT ;
    USE SIGNAL ;
    PORT
      LAYER M4 ;
        RECT  0 54.864 0.084 54.888 ;
    END
  END rt[184]
  PIN rt[185]
    DIRECTION INPUT ;
    USE SIGNAL ;
    PORT
      LAYER M4 ;
        RECT  0 55.104 0.084 55.128 ;
    END
  END rt[185]
  PIN rt[186]
    DIRECTION INPUT ;
    USE SIGNAL ;
    PORT
      LAYER M4 ;
        RECT  0 55.392 0.084 55.416 ;
    END
  END rt[186]
  PIN rt[187]
    DIRECTION INPUT ;
    USE SIGNAL ;
    PORT
      LAYER M4 ;
        RECT  0 55.632 0.084 55.656 ;
    END
  END rt[187]
  PIN rt[188]
    DIRECTION INPUT ;
    USE SIGNAL ;
    PORT
      LAYER M4 ;
        RECT  0 55.92 0.084 55.944 ;
    END
  END rt[188]
  PIN rt[189]
    DIRECTION INPUT ;
    USE SIGNAL ;
    PORT
      LAYER M4 ;
        RECT  0 56.16 0.084 56.184 ;
    END
  END rt[189]
  PIN rt[18]
    DIRECTION INPUT ;
    USE SIGNAL ;
    PORT
      LAYER M4 ;
        RECT  0 11.328 0.084 11.352 ;
    END
  END rt[18]
  PIN rt[190]
    DIRECTION INPUT ;
    USE SIGNAL ;
    PORT
      LAYER M4 ;
        RECT  0 56.448 0.084 56.472 ;
    END
  END rt[190]
  PIN rt[191]
    DIRECTION INPUT ;
    USE SIGNAL ;
    PORT
      LAYER M4 ;
        RECT  0 56.688 0.084 56.712 ;
    END
  END rt[191]
  PIN rt[192]
    DIRECTION INPUT ;
    USE SIGNAL ;
    PORT
      LAYER M4 ;
        RECT  0 56.976 0.084 57 ;
    END
  END rt[192]
  PIN rt[193]
    DIRECTION INPUT ;
    USE SIGNAL ;
    PORT
      LAYER M4 ;
        RECT  0 57.216 0.084 57.24 ;
    END
  END rt[193]
  PIN rt[194]
    DIRECTION INPUT ;
    USE SIGNAL ;
    PORT
      LAYER M4 ;
        RECT  0 57.504 0.084 57.528 ;
    END
  END rt[194]
  PIN rt[195]
    DIRECTION INPUT ;
    USE SIGNAL ;
    PORT
      LAYER M4 ;
        RECT  0 57.744 0.084 57.768 ;
    END
  END rt[195]
  PIN rt[196]
    DIRECTION INPUT ;
    USE SIGNAL ;
    PORT
      LAYER M4 ;
        RECT  0 57.984 0.084 58.008 ;
    END
  END rt[196]
  PIN rt[197]
    DIRECTION INPUT ;
    USE SIGNAL ;
    PORT
      LAYER M4 ;
        RECT  0 58.272 0.084 58.296 ;
    END
  END rt[197]
  PIN rt[198]
    DIRECTION INPUT ;
    USE SIGNAL ;
    PORT
      LAYER M4 ;
        RECT  0 58.512 0.084 58.536 ;
    END
  END rt[198]
  PIN rt[199]
    DIRECTION INPUT ;
    USE SIGNAL ;
    PORT
      LAYER M4 ;
        RECT  0 58.8 0.084 58.824 ;
    END
  END rt[199]
  PIN rt[19]
    DIRECTION INPUT ;
    USE SIGNAL ;
    PORT
      LAYER M4 ;
        RECT  0 11.568 0.084 11.592 ;
    END
  END rt[19]
  PIN rt[1]
    DIRECTION INPUT ;
    USE SIGNAL ;
    PORT
      LAYER M4 ;
        RECT  0 6.864 0.084 6.888 ;
    END
  END rt[1]
  PIN rt[200]
    DIRECTION INPUT ;
    USE SIGNAL ;
    PORT
      LAYER M4 ;
        RECT  0 59.04 0.084 59.064 ;
    END
  END rt[200]
  PIN rt[201]
    DIRECTION INPUT ;
    USE SIGNAL ;
    PORT
      LAYER M4 ;
        RECT  0 59.328 0.084 59.352 ;
    END
  END rt[201]
  PIN rt[202]
    DIRECTION INPUT ;
    USE SIGNAL ;
    PORT
      LAYER M4 ;
        RECT  0 59.568 0.084 59.592 ;
    END
  END rt[202]
  PIN rt[203]
    DIRECTION INPUT ;
    USE SIGNAL ;
    PORT
      LAYER M4 ;
        RECT  0 59.856 0.084 59.88 ;
    END
  END rt[203]
  PIN rt[204]
    DIRECTION INPUT ;
    USE SIGNAL ;
    PORT
      LAYER M4 ;
        RECT  0 60.096 0.084 60.12 ;
    END
  END rt[204]
  PIN rt[205]
    DIRECTION INPUT ;
    USE SIGNAL ;
    PORT
      LAYER M4 ;
        RECT  0 60.384 0.084 60.408 ;
    END
  END rt[205]
  PIN rt[206]
    DIRECTION INPUT ;
    USE SIGNAL ;
    PORT
      LAYER M4 ;
        RECT  0 60.624 0.084 60.648 ;
    END
  END rt[206]
  PIN rt[207]
    DIRECTION INPUT ;
    USE SIGNAL ;
    PORT
      LAYER M4 ;
        RECT  0 60.912 0.084 60.936 ;
    END
  END rt[207]
  PIN rt[208]
    DIRECTION INPUT ;
    USE SIGNAL ;
    PORT
      LAYER M4 ;
        RECT  0 61.152 0.084 61.176 ;
    END
  END rt[208]
  PIN rt[209]
    DIRECTION INPUT ;
    USE SIGNAL ;
    PORT
      LAYER M4 ;
        RECT  0 61.44 0.084 61.464 ;
    END
  END rt[209]
  PIN rt[20]
    DIRECTION INPUT ;
    USE SIGNAL ;
    PORT
      LAYER M4 ;
        RECT  0 11.856 0.084 11.88 ;
    END
  END rt[20]
  PIN rt[210]
    DIRECTION INPUT ;
    USE SIGNAL ;
    PORT
      LAYER M4 ;
        RECT  0 61.68 0.084 61.704 ;
    END
  END rt[210]
  PIN rt[211]
    DIRECTION INPUT ;
    USE SIGNAL ;
    PORT
      LAYER M4 ;
        RECT  0 61.92 0.084 61.944 ;
    END
  END rt[211]
  PIN rt[212]
    DIRECTION INPUT ;
    USE SIGNAL ;
    PORT
      LAYER M4 ;
        RECT  0 62.208 0.084 62.232 ;
    END
  END rt[212]
  PIN rt[213]
    DIRECTION INPUT ;
    USE SIGNAL ;
    PORT
      LAYER M4 ;
        RECT  0 62.448 0.084 62.472 ;
    END
  END rt[213]
  PIN rt[214]
    DIRECTION INPUT ;
    USE SIGNAL ;
    PORT
      LAYER M4 ;
        RECT  0 62.736 0.084 62.76 ;
    END
  END rt[214]
  PIN rt[215]
    DIRECTION INPUT ;
    USE SIGNAL ;
    PORT
      LAYER M4 ;
        RECT  0 62.976 0.084 63 ;
    END
  END rt[215]
  PIN rt[216]
    DIRECTION INPUT ;
    USE SIGNAL ;
    PORT
      LAYER M4 ;
        RECT  0 63.264 0.084 63.288 ;
    END
  END rt[216]
  PIN rt[217]
    DIRECTION INPUT ;
    USE SIGNAL ;
    PORT
      LAYER M4 ;
        RECT  0 63.504 0.084 63.528 ;
    END
  END rt[217]
  PIN rt[218]
    DIRECTION INPUT ;
    USE SIGNAL ;
    PORT
      LAYER M4 ;
        RECT  0 63.792 0.084 63.816 ;
    END
  END rt[218]
  PIN rt[219]
    DIRECTION INPUT ;
    USE SIGNAL ;
    PORT
      LAYER M4 ;
        RECT  0 64.032 0.084 64.056 ;
    END
  END rt[219]
  PIN rt[21]
    DIRECTION INPUT ;
    USE SIGNAL ;
    PORT
      LAYER M4 ;
        RECT  0 12.096 0.084 12.12 ;
    END
  END rt[21]
  PIN rt[220]
    DIRECTION INPUT ;
    USE SIGNAL ;
    PORT
      LAYER M4 ;
        RECT  0 64.32 0.084 64.344 ;
    END
  END rt[220]
  PIN rt[221]
    DIRECTION INPUT ;
    USE SIGNAL ;
    PORT
      LAYER M4 ;
        RECT  0 64.56 0.084 64.584 ;
    END
  END rt[221]
  PIN rt[222]
    DIRECTION INPUT ;
    USE SIGNAL ;
    PORT
      LAYER M4 ;
        RECT  0 64.848 0.084 64.872 ;
    END
  END rt[222]
  PIN rt[223]
    DIRECTION INPUT ;
    USE SIGNAL ;
    PORT
      LAYER M4 ;
        RECT  0 65.088 0.084 65.112 ;
    END
  END rt[223]
  PIN rt[224]
    DIRECTION INPUT ;
    USE SIGNAL ;
    PORT
      LAYER M4 ;
        RECT  0 65.328 0.084 65.352 ;
    END
  END rt[224]
  PIN rt[225]
    DIRECTION INPUT ;
    USE SIGNAL ;
    PORT
      LAYER M4 ;
        RECT  0 65.616 0.084 65.64 ;
    END
  END rt[225]
  PIN rt[226]
    DIRECTION INPUT ;
    USE SIGNAL ;
    PORT
      LAYER M4 ;
        RECT  0 65.856 0.084 65.88 ;
    END
  END rt[226]
  PIN rt[227]
    DIRECTION INPUT ;
    USE SIGNAL ;
    PORT
      LAYER M4 ;
        RECT  0 66.144 0.084 66.168 ;
    END
  END rt[227]
  PIN rt[228]
    DIRECTION INPUT ;
    USE SIGNAL ;
    PORT
      LAYER M4 ;
        RECT  0 66.384 0.084 66.408 ;
    END
  END rt[228]
  PIN rt[229]
    DIRECTION INPUT ;
    USE SIGNAL ;
    PORT
      LAYER M4 ;
        RECT  0 66.672 0.084 66.696 ;
    END
  END rt[229]
  PIN rt[22]
    DIRECTION INPUT ;
    USE SIGNAL ;
    PORT
      LAYER M4 ;
        RECT  0 12.384 0.084 12.408 ;
    END
  END rt[22]
  PIN rt[230]
    DIRECTION INPUT ;
    USE SIGNAL ;
    PORT
      LAYER M4 ;
        RECT  0 66.912 0.084 66.936 ;
    END
  END rt[230]
  PIN rt[231]
    DIRECTION INPUT ;
    USE SIGNAL ;
    PORT
      LAYER M4 ;
        RECT  0 67.2 0.084 67.224 ;
    END
  END rt[231]
  PIN rt[232]
    DIRECTION INPUT ;
    USE SIGNAL ;
    PORT
      LAYER M4 ;
        RECT  0 67.44 0.084 67.464 ;
    END
  END rt[232]
  PIN rt[233]
    DIRECTION INPUT ;
    USE SIGNAL ;
    PORT
      LAYER M4 ;
        RECT  0 67.728 0.084 67.752 ;
    END
  END rt[233]
  PIN rt[234]
    DIRECTION INPUT ;
    USE SIGNAL ;
    PORT
      LAYER M4 ;
        RECT  0 67.968 0.084 67.992 ;
    END
  END rt[234]
  PIN rt[235]
    DIRECTION INPUT ;
    USE SIGNAL ;
    PORT
      LAYER M4 ;
        RECT  0 68.256 0.084 68.28 ;
    END
  END rt[235]
  PIN rt[236]
    DIRECTION INPUT ;
    USE SIGNAL ;
    PORT
      LAYER M4 ;
        RECT  0 68.496 0.084 68.52 ;
    END
  END rt[236]
  PIN rt[237]
    DIRECTION INPUT ;
    USE SIGNAL ;
    PORT
      LAYER M4 ;
        RECT  0 68.784 0.084 68.808 ;
    END
  END rt[237]
  PIN rt[238]
    DIRECTION INPUT ;
    USE SIGNAL ;
    PORT
      LAYER M4 ;
        RECT  0 69.024 0.084 69.048 ;
    END
  END rt[238]
  PIN rt[239]
    DIRECTION INPUT ;
    USE SIGNAL ;
    PORT
      LAYER M4 ;
        RECT  0 69.264 0.084 69.288 ;
    END
  END rt[239]
  PIN rt[23]
    DIRECTION INPUT ;
    USE SIGNAL ;
    PORT
      LAYER M4 ;
        RECT  0 12.624 0.084 12.648 ;
    END
  END rt[23]
  PIN rt[240]
    DIRECTION INPUT ;
    USE SIGNAL ;
    PORT
      LAYER M4 ;
        RECT  0 69.552 0.084 69.576 ;
    END
  END rt[240]
  PIN rt[241]
    DIRECTION INPUT ;
    USE SIGNAL ;
    PORT
      LAYER M4 ;
        RECT  0 69.792 0.084 69.816 ;
    END
  END rt[241]
  PIN rt[242]
    DIRECTION INPUT ;
    USE SIGNAL ;
    PORT
      LAYER M4 ;
        RECT  0 70.08 0.084 70.104 ;
    END
  END rt[242]
  PIN rt[243]
    DIRECTION INPUT ;
    USE SIGNAL ;
    PORT
      LAYER M4 ;
        RECT  0 70.32 0.084 70.344 ;
    END
  END rt[243]
  PIN rt[244]
    DIRECTION INPUT ;
    USE SIGNAL ;
    PORT
      LAYER M4 ;
        RECT  0 70.608 0.084 70.632 ;
    END
  END rt[244]
  PIN rt[245]
    DIRECTION INPUT ;
    USE SIGNAL ;
    PORT
      LAYER M4 ;
        RECT  0 70.848 0.084 70.872 ;
    END
  END rt[245]
  PIN rt[246]
    DIRECTION INPUT ;
    USE SIGNAL ;
    PORT
      LAYER M4 ;
        RECT  0 71.136 0.084 71.16 ;
    END
  END rt[246]
  PIN rt[247]
    DIRECTION INPUT ;
    USE SIGNAL ;
    PORT
      LAYER M4 ;
        RECT  0 71.376 0.084 71.4 ;
    END
  END rt[247]
  PIN rt[248]
    DIRECTION INPUT ;
    USE SIGNAL ;
    PORT
      LAYER M4 ;
        RECT  0 71.664 0.084 71.688 ;
    END
  END rt[248]
  PIN rt[249]
    DIRECTION INPUT ;
    USE SIGNAL ;
    PORT
      LAYER M4 ;
        RECT  0 71.904 0.084 71.928 ;
    END
  END rt[249]
  PIN rt[24]
    DIRECTION INPUT ;
    USE SIGNAL ;
    PORT
      LAYER M4 ;
        RECT  0 12.912 0.084 12.936 ;
    END
  END rt[24]
  PIN rt[250]
    DIRECTION INPUT ;
    USE SIGNAL ;
    PORT
      LAYER M4 ;
        RECT  0 72.192 0.084 72.216 ;
    END
  END rt[250]
  PIN rt[251]
    DIRECTION INPUT ;
    USE SIGNAL ;
    PORT
      LAYER M4 ;
        RECT  0 72.432 0.084 72.456 ;
    END
  END rt[251]
  PIN rt[252]
    DIRECTION INPUT ;
    USE SIGNAL ;
    PORT
      LAYER M4 ;
        RECT  0 72.672 0.084 72.696 ;
    END
  END rt[252]
  PIN rt[253]
    DIRECTION INPUT ;
    USE SIGNAL ;
    PORT
      LAYER M4 ;
        RECT  0 72.96 0.084 72.984 ;
    END
  END rt[253]
  PIN rt[254]
    DIRECTION INPUT ;
    USE SIGNAL ;
    PORT
      LAYER M4 ;
        RECT  0 73.2 0.084 73.224 ;
    END
  END rt[254]
  PIN rt[255]
    DIRECTION INPUT ;
    USE SIGNAL ;
    PORT
      LAYER M4 ;
        RECT  0 73.488 0.084 73.512 ;
    END
  END rt[255]
  PIN rt[256]
    DIRECTION INPUT ;
    USE SIGNAL ;
    PORT
      LAYER M4 ;
        RECT  0 73.728 0.084 73.752 ;
    END
  END rt[256]
  PIN rt[257]
    DIRECTION INPUT ;
    USE SIGNAL ;
    PORT
      LAYER M4 ;
        RECT  0 74.016 0.084 74.04 ;
    END
  END rt[257]
  PIN rt[258]
    DIRECTION INPUT ;
    USE SIGNAL ;
    PORT
      LAYER M4 ;
        RECT  0 74.256 0.084 74.28 ;
    END
  END rt[258]
  PIN rt[259]
    DIRECTION INPUT ;
    USE SIGNAL ;
    PORT
      LAYER M4 ;
        RECT  0 74.544 0.084 74.568 ;
    END
  END rt[259]
  PIN rt[25]
    DIRECTION INPUT ;
    USE SIGNAL ;
    PORT
      LAYER M4 ;
        RECT  0 13.152 0.084 13.176 ;
    END
  END rt[25]
  PIN rt[260]
    DIRECTION INPUT ;
    USE SIGNAL ;
    PORT
      LAYER M4 ;
        RECT  0 74.784 0.084 74.808 ;
    END
  END rt[260]
  PIN rt[261]
    DIRECTION INPUT ;
    USE SIGNAL ;
    PORT
      LAYER M4 ;
        RECT  0 75.072 0.084 75.096 ;
    END
  END rt[261]
  PIN rt[262]
    DIRECTION INPUT ;
    USE SIGNAL ;
    PORT
      LAYER M4 ;
        RECT  0 75.312 0.084 75.336 ;
    END
  END rt[262]
  PIN rt[263]
    DIRECTION INPUT ;
    USE SIGNAL ;
    PORT
      LAYER M4 ;
        RECT  0 75.6 0.084 75.624 ;
    END
  END rt[263]
  PIN rt[264]
    DIRECTION INPUT ;
    USE SIGNAL ;
    PORT
      LAYER M4 ;
        RECT  0 75.84 0.084 75.864 ;
    END
  END rt[264]
  PIN rt[265]
    DIRECTION INPUT ;
    USE SIGNAL ;
    PORT
      LAYER M4 ;
        RECT  0 76.128 0.084 76.152 ;
    END
  END rt[265]
  PIN rt[266]
    DIRECTION INPUT ;
    USE SIGNAL ;
    PORT
      LAYER M4 ;
        RECT  0 76.368 0.084 76.392 ;
    END
  END rt[266]
  PIN rt[267]
    DIRECTION INPUT ;
    USE SIGNAL ;
    PORT
      LAYER M4 ;
        RECT  0 76.608 0.084 76.632 ;
    END
  END rt[267]
  PIN rt[268]
    DIRECTION INPUT ;
    USE SIGNAL ;
    PORT
      LAYER M4 ;
        RECT  0 76.896 0.084 76.92 ;
    END
  END rt[268]
  PIN rt[269]
    DIRECTION INPUT ;
    USE SIGNAL ;
    PORT
      LAYER M4 ;
        RECT  0 77.136 0.084 77.16 ;
    END
  END rt[269]
  PIN rt[26]
    DIRECTION INPUT ;
    USE SIGNAL ;
    PORT
      LAYER M4 ;
        RECT  0 13.44 0.084 13.464 ;
    END
  END rt[26]
  PIN rt[270]
    DIRECTION INPUT ;
    USE SIGNAL ;
    PORT
      LAYER M4 ;
        RECT  0 77.424 0.084 77.448 ;
    END
  END rt[270]
  PIN rt[271]
    DIRECTION INPUT ;
    USE SIGNAL ;
    PORT
      LAYER M4 ;
        RECT  0 77.664 0.084 77.688 ;
    END
  END rt[271]
  PIN rt[272]
    DIRECTION INPUT ;
    USE SIGNAL ;
    PORT
      LAYER M4 ;
        RECT  0 77.952 0.084 77.976 ;
    END
  END rt[272]
  PIN rt[273]
    DIRECTION INPUT ;
    USE SIGNAL ;
    PORT
      LAYER M4 ;
        RECT  0 78.192 0.084 78.216 ;
    END
  END rt[273]
  PIN rt[274]
    DIRECTION INPUT ;
    USE SIGNAL ;
    PORT
      LAYER M4 ;
        RECT  0 78.48 0.084 78.504 ;
    END
  END rt[274]
  PIN rt[275]
    DIRECTION INPUT ;
    USE SIGNAL ;
    PORT
      LAYER M4 ;
        RECT  0 78.72 0.084 78.744 ;
    END
  END rt[275]
  PIN rt[276]
    DIRECTION INPUT ;
    USE SIGNAL ;
    PORT
      LAYER M4 ;
        RECT  0 79.008 0.084 79.032 ;
    END
  END rt[276]
  PIN rt[277]
    DIRECTION INPUT ;
    USE SIGNAL ;
    PORT
      LAYER M4 ;
        RECT  0 79.248 0.084 79.272 ;
    END
  END rt[277]
  PIN rt[278]
    DIRECTION INPUT ;
    USE SIGNAL ;
    PORT
      LAYER M4 ;
        RECT  0 79.536 0.084 79.56 ;
    END
  END rt[278]
  PIN rt[279]
    DIRECTION INPUT ;
    USE SIGNAL ;
    PORT
      LAYER M4 ;
        RECT  0 79.776 0.084 79.8 ;
    END
  END rt[279]
  PIN rt[27]
    DIRECTION INPUT ;
    USE SIGNAL ;
    PORT
      LAYER M4 ;
        RECT  0 13.68 0.084 13.704 ;
    END
  END rt[27]
  PIN rt[28]
    DIRECTION INPUT ;
    USE SIGNAL ;
    PORT
      LAYER M4 ;
        RECT  0 13.92 0.084 13.944 ;
    END
  END rt[28]
  PIN rt[29]
    DIRECTION INPUT ;
    USE SIGNAL ;
    PORT
      LAYER M4 ;
        RECT  0 14.208 0.084 14.232 ;
    END
  END rt[29]
  PIN rt[2]
    DIRECTION INPUT ;
    USE SIGNAL ;
    PORT
      LAYER M4 ;
        RECT  0 7.104 0.084 7.128 ;
    END
  END rt[2]
  PIN rt[30]
    DIRECTION INPUT ;
    USE SIGNAL ;
    PORT
      LAYER M4 ;
        RECT  0 14.448 0.084 14.472 ;
    END
  END rt[30]
  PIN rt[31]
    DIRECTION INPUT ;
    USE SIGNAL ;
    PORT
      LAYER M4 ;
        RECT  0 14.736 0.084 14.76 ;
    END
  END rt[31]
  PIN rt[32]
    DIRECTION INPUT ;
    USE SIGNAL ;
    PORT
      LAYER M4 ;
        RECT  0 14.976 0.084 15 ;
    END
  END rt[32]
  PIN rt[33]
    DIRECTION INPUT ;
    USE SIGNAL ;
    PORT
      LAYER M4 ;
        RECT  0 15.264 0.084 15.288 ;
    END
  END rt[33]
  PIN rt[34]
    DIRECTION INPUT ;
    USE SIGNAL ;
    PORT
      LAYER M4 ;
        RECT  0 15.504 0.084 15.528 ;
    END
  END rt[34]
  PIN rt[35]
    DIRECTION INPUT ;
    USE SIGNAL ;
    PORT
      LAYER M4 ;
        RECT  0 15.792 0.084 15.816 ;
    END
  END rt[35]
  PIN rt[36]
    DIRECTION INPUT ;
    USE SIGNAL ;
    PORT
      LAYER M4 ;
        RECT  0 16.032 0.084 16.056 ;
    END
  END rt[36]
  PIN rt[37]
    DIRECTION INPUT ;
    USE SIGNAL ;
    PORT
      LAYER M4 ;
        RECT  0 16.32 0.084 16.344 ;
    END
  END rt[37]
  PIN rt[38]
    DIRECTION INPUT ;
    USE SIGNAL ;
    PORT
      LAYER M4 ;
        RECT  0 16.56 0.084 16.584 ;
    END
  END rt[38]
  PIN rt[39]
    DIRECTION INPUT ;
    USE SIGNAL ;
    PORT
      LAYER M4 ;
        RECT  0 16.848 0.084 16.872 ;
    END
  END rt[39]
  PIN rt[3]
    DIRECTION INPUT ;
    USE SIGNAL ;
    PORT
      LAYER M4 ;
        RECT  0 7.392 0.084 7.416 ;
    END
  END rt[3]
  PIN rt[40]
    DIRECTION INPUT ;
    USE SIGNAL ;
    PORT
      LAYER M4 ;
        RECT  0 17.088 0.084 17.112 ;
    END
  END rt[40]
  PIN rt[41]
    DIRECTION INPUT ;
    USE SIGNAL ;
    PORT
      LAYER M4 ;
        RECT  0 17.376 0.084 17.4 ;
    END
  END rt[41]
  PIN rt[42]
    DIRECTION INPUT ;
    USE SIGNAL ;
    PORT
      LAYER M4 ;
        RECT  0 17.616 0.084 17.64 ;
    END
  END rt[42]
  PIN rt[43]
    DIRECTION INPUT ;
    USE SIGNAL ;
    PORT
      LAYER M4 ;
        RECT  0 17.856 0.084 17.88 ;
    END
  END rt[43]
  PIN rt[44]
    DIRECTION INPUT ;
    USE SIGNAL ;
    PORT
      LAYER M4 ;
        RECT  0 18.144 0.084 18.168 ;
    END
  END rt[44]
  PIN rt[45]
    DIRECTION INPUT ;
    USE SIGNAL ;
    PORT
      LAYER M4 ;
        RECT  0 18.384 0.084 18.408 ;
    END
  END rt[45]
  PIN rt[46]
    DIRECTION INPUT ;
    USE SIGNAL ;
    PORT
      LAYER M4 ;
        RECT  0 18.672 0.084 18.696 ;
    END
  END rt[46]
  PIN rt[47]
    DIRECTION INPUT ;
    USE SIGNAL ;
    PORT
      LAYER M4 ;
        RECT  0 18.912 0.084 18.936 ;
    END
  END rt[47]
  PIN rt[48]
    DIRECTION INPUT ;
    USE SIGNAL ;
    PORT
      LAYER M4 ;
        RECT  0 19.2 0.084 19.224 ;
    END
  END rt[48]
  PIN rt[49]
    DIRECTION INPUT ;
    USE SIGNAL ;
    PORT
      LAYER M4 ;
        RECT  0 19.44 0.084 19.464 ;
    END
  END rt[49]
  PIN rt[4]
    DIRECTION INPUT ;
    USE SIGNAL ;
    PORT
      LAYER M4 ;
        RECT  0 7.632 0.084 7.656 ;
    END
  END rt[4]
  PIN rt[50]
    DIRECTION INPUT ;
    USE SIGNAL ;
    PORT
      LAYER M4 ;
        RECT  0 19.728 0.084 19.752 ;
    END
  END rt[50]
  PIN rt[51]
    DIRECTION INPUT ;
    USE SIGNAL ;
    PORT
      LAYER M4 ;
        RECT  0 19.968 0.084 19.992 ;
    END
  END rt[51]
  PIN rt[52]
    DIRECTION INPUT ;
    USE SIGNAL ;
    PORT
      LAYER M4 ;
        RECT  0 20.256 0.084 20.28 ;
    END
  END rt[52]
  PIN rt[53]
    DIRECTION INPUT ;
    USE SIGNAL ;
    PORT
      LAYER M4 ;
        RECT  0 20.496 0.084 20.52 ;
    END
  END rt[53]
  PIN rt[54]
    DIRECTION INPUT ;
    USE SIGNAL ;
    PORT
      LAYER M4 ;
        RECT  0 20.784 0.084 20.808 ;
    END
  END rt[54]
  PIN rt[55]
    DIRECTION INPUT ;
    USE SIGNAL ;
    PORT
      LAYER M4 ;
        RECT  0 21.024 0.084 21.048 ;
    END
  END rt[55]
  PIN rt[56]
    DIRECTION INPUT ;
    USE SIGNAL ;
    PORT
      LAYER M4 ;
        RECT  0 21.264 0.084 21.288 ;
    END
  END rt[56]
  PIN rt[57]
    DIRECTION INPUT ;
    USE SIGNAL ;
    PORT
      LAYER M4 ;
        RECT  0 21.552 0.084 21.576 ;
    END
  END rt[57]
  PIN rt[58]
    DIRECTION INPUT ;
    USE SIGNAL ;
    PORT
      LAYER M4 ;
        RECT  0 21.792 0.084 21.816 ;
    END
  END rt[58]
  PIN rt[59]
    DIRECTION INPUT ;
    USE SIGNAL ;
    PORT
      LAYER M4 ;
        RECT  0 22.08 0.084 22.104 ;
    END
  END rt[59]
  PIN rt[5]
    DIRECTION INPUT ;
    USE SIGNAL ;
    PORT
      LAYER M4 ;
        RECT  0 7.92 0.084 7.944 ;
    END
  END rt[5]
  PIN rt[60]
    DIRECTION INPUT ;
    USE SIGNAL ;
    PORT
      LAYER M4 ;
        RECT  0 22.32 0.084 22.344 ;
    END
  END rt[60]
  PIN rt[61]
    DIRECTION INPUT ;
    USE SIGNAL ;
    PORT
      LAYER M4 ;
        RECT  0 22.608 0.084 22.632 ;
    END
  END rt[61]
  PIN rt[62]
    DIRECTION INPUT ;
    USE SIGNAL ;
    PORT
      LAYER M4 ;
        RECT  0 22.848 0.084 22.872 ;
    END
  END rt[62]
  PIN rt[63]
    DIRECTION INPUT ;
    USE SIGNAL ;
    PORT
      LAYER M4 ;
        RECT  0 23.136 0.084 23.16 ;
    END
  END rt[63]
  PIN rt[64]
    DIRECTION INPUT ;
    USE SIGNAL ;
    PORT
      LAYER M4 ;
        RECT  0 23.376 0.084 23.4 ;
    END
  END rt[64]
  PIN rt[65]
    DIRECTION INPUT ;
    USE SIGNAL ;
    PORT
      LAYER M4 ;
        RECT  0 23.664 0.084 23.688 ;
    END
  END rt[65]
  PIN rt[66]
    DIRECTION INPUT ;
    USE SIGNAL ;
    PORT
      LAYER M4 ;
        RECT  0 23.904 0.084 23.928 ;
    END
  END rt[66]
  PIN rt[67]
    DIRECTION INPUT ;
    USE SIGNAL ;
    PORT
      LAYER M4 ;
        RECT  0 24.192 0.084 24.216 ;
    END
  END rt[67]
  PIN rt[68]
    DIRECTION INPUT ;
    USE SIGNAL ;
    PORT
      LAYER M4 ;
        RECT  0 24.432 0.084 24.456 ;
    END
  END rt[68]
  PIN rt[69]
    DIRECTION INPUT ;
    USE SIGNAL ;
    PORT
      LAYER M4 ;
        RECT  0 24.72 0.084 24.744 ;
    END
  END rt[69]
  PIN rt[6]
    DIRECTION INPUT ;
    USE SIGNAL ;
    PORT
      LAYER M4 ;
        RECT  0 8.16 0.084 8.184 ;
    END
  END rt[6]
  PIN rt[70]
    DIRECTION INPUT ;
    USE SIGNAL ;
    PORT
      LAYER M4 ;
        RECT  0 24.96 0.084 24.984 ;
    END
  END rt[70]
  PIN rt[71]
    DIRECTION INPUT ;
    USE SIGNAL ;
    PORT
      LAYER M4 ;
        RECT  0 25.2 0.084 25.224 ;
    END
  END rt[71]
  PIN rt[72]
    DIRECTION INPUT ;
    USE SIGNAL ;
    PORT
      LAYER M4 ;
        RECT  0 25.488 0.084 25.512 ;
    END
  END rt[72]
  PIN rt[73]
    DIRECTION INPUT ;
    USE SIGNAL ;
    PORT
      LAYER M4 ;
        RECT  0 25.728 0.084 25.752 ;
    END
  END rt[73]
  PIN rt[74]
    DIRECTION INPUT ;
    USE SIGNAL ;
    PORT
      LAYER M4 ;
        RECT  0 26.016 0.084 26.04 ;
    END
  END rt[74]
  PIN rt[75]
    DIRECTION INPUT ;
    USE SIGNAL ;
    PORT
      LAYER M4 ;
        RECT  0 26.256 0.084 26.28 ;
    END
  END rt[75]
  PIN rt[76]
    DIRECTION INPUT ;
    USE SIGNAL ;
    PORT
      LAYER M4 ;
        RECT  0 26.544 0.084 26.568 ;
    END
  END rt[76]
  PIN rt[77]
    DIRECTION INPUT ;
    USE SIGNAL ;
    PORT
      LAYER M4 ;
        RECT  0 26.784 0.084 26.808 ;
    END
  END rt[77]
  PIN rt[78]
    DIRECTION INPUT ;
    USE SIGNAL ;
    PORT
      LAYER M4 ;
        RECT  0 27.072 0.084 27.096 ;
    END
  END rt[78]
  PIN rt[79]
    DIRECTION INPUT ;
    USE SIGNAL ;
    PORT
      LAYER M4 ;
        RECT  0 27.312 0.084 27.336 ;
    END
  END rt[79]
  PIN rt[7]
    DIRECTION INPUT ;
    USE SIGNAL ;
    PORT
      LAYER M4 ;
        RECT  0 8.448 0.084 8.472 ;
    END
  END rt[7]
  PIN rt[80]
    DIRECTION INPUT ;
    USE SIGNAL ;
    PORT
      LAYER M4 ;
        RECT  0 27.6 0.084 27.624 ;
    END
  END rt[80]
  PIN rt[81]
    DIRECTION INPUT ;
    USE SIGNAL ;
    PORT
      LAYER M4 ;
        RECT  0 27.84 0.084 27.864 ;
    END
  END rt[81]
  PIN rt[82]
    DIRECTION INPUT ;
    USE SIGNAL ;
    PORT
      LAYER M4 ;
        RECT  0 28.128 0.084 28.152 ;
    END
  END rt[82]
  PIN rt[83]
    DIRECTION INPUT ;
    USE SIGNAL ;
    PORT
      LAYER M4 ;
        RECT  0 28.368 0.084 28.392 ;
    END
  END rt[83]
  PIN rt[84]
    DIRECTION INPUT ;
    USE SIGNAL ;
    PORT
      LAYER M4 ;
        RECT  0 28.608 0.084 28.632 ;
    END
  END rt[84]
  PIN rt[85]
    DIRECTION INPUT ;
    USE SIGNAL ;
    PORT
      LAYER M4 ;
        RECT  0 28.896 0.084 28.92 ;
    END
  END rt[85]
  PIN rt[86]
    DIRECTION INPUT ;
    USE SIGNAL ;
    PORT
      LAYER M4 ;
        RECT  0 29.136 0.084 29.16 ;
    END
  END rt[86]
  PIN rt[87]
    DIRECTION INPUT ;
    USE SIGNAL ;
    PORT
      LAYER M4 ;
        RECT  0 29.424 0.084 29.448 ;
    END
  END rt[87]
  PIN rt[88]
    DIRECTION INPUT ;
    USE SIGNAL ;
    PORT
      LAYER M4 ;
        RECT  0 29.664 0.084 29.688 ;
    END
  END rt[88]
  PIN rt[89]
    DIRECTION INPUT ;
    USE SIGNAL ;
    PORT
      LAYER M4 ;
        RECT  0 29.952 0.084 29.976 ;
    END
  END rt[89]
  PIN rt[8]
    DIRECTION INPUT ;
    USE SIGNAL ;
    PORT
      LAYER M4 ;
        RECT  0 8.688 0.084 8.712 ;
    END
  END rt[8]
  PIN rt[90]
    DIRECTION INPUT ;
    USE SIGNAL ;
    PORT
      LAYER M4 ;
        RECT  0 30.192 0.084 30.216 ;
    END
  END rt[90]
  PIN rt[91]
    DIRECTION INPUT ;
    USE SIGNAL ;
    PORT
      LAYER M4 ;
        RECT  0 30.48 0.084 30.504 ;
    END
  END rt[91]
  PIN rt[92]
    DIRECTION INPUT ;
    USE SIGNAL ;
    PORT
      LAYER M4 ;
        RECT  0 30.72 0.084 30.744 ;
    END
  END rt[92]
  PIN rt[93]
    DIRECTION INPUT ;
    USE SIGNAL ;
    PORT
      LAYER M4 ;
        RECT  0 31.008 0.084 31.032 ;
    END
  END rt[93]
  PIN rt[94]
    DIRECTION INPUT ;
    USE SIGNAL ;
    PORT
      LAYER M4 ;
        RECT  0 31.248 0.084 31.272 ;
    END
  END rt[94]
  PIN rt[95]
    DIRECTION INPUT ;
    USE SIGNAL ;
    PORT
      LAYER M4 ;
        RECT  0 31.536 0.084 31.56 ;
    END
  END rt[95]
  PIN rt[96]
    DIRECTION INPUT ;
    USE SIGNAL ;
    PORT
      LAYER M4 ;
        RECT  0 31.776 0.084 31.8 ;
    END
  END rt[96]
  PIN rt[97]
    DIRECTION INPUT ;
    USE SIGNAL ;
    PORT
      LAYER M4 ;
        RECT  0 32.064 0.084 32.088 ;
    END
  END rt[97]
  PIN rt[98]
    DIRECTION INPUT ;
    USE SIGNAL ;
    PORT
      LAYER M4 ;
        RECT  0 32.304 0.084 32.328 ;
    END
  END rt[98]
  PIN rt[99]
    DIRECTION INPUT ;
    USE SIGNAL ;
    PORT
      LAYER M4 ;
        RECT  0 32.544 0.084 32.568 ;
    END
  END rt[99]
  PIN rt[9]
    DIRECTION INPUT ;
    USE SIGNAL ;
    PORT
      LAYER M4 ;
        RECT  0 8.976 0.084 9 ;
    END
  END rt[9]
  PIN VDD
    DIRECTION INOUT ;
    USE POWER ;
    PORT
      LAYER M5 ;
        RECT  83.592 2.151 83.712 84.249 ;
        RECT  78.192 2.151 78.312 84.249 ;
        RECT  72.792 2.151 72.912 84.249 ;
        RECT  67.392 2.151 67.512 84.249 ;
        RECT  61.992 2.151 62.112 84.249 ;
        RECT  56.592 2.151 56.712 84.249 ;
        RECT  51.192 2.151 51.312 84.249 ;
        RECT  45.792 2.151 45.912 84.249 ;
        RECT  40.392 2.151 40.512 84.249 ;
        RECT  34.992 2.151 35.112 84.249 ;
        RECT  29.592 2.151 29.712 84.249 ;
        RECT  24.192 2.151 24.312 84.249 ;
        RECT  18.792 2.151 18.912 84.249 ;
        RECT  13.392 2.151 13.512 84.249 ;
        RECT  7.992 2.151 8.112 84.249 ;
        RECT  2.592 2.151 2.712 84.249 ;
    END
  END VDD
  PIN VSS
    DIRECTION INOUT ;
    USE GROUND ;
    PORT
      LAYER M5 ;
        RECT  83.4 2.137 83.52 84.263 ;
        RECT  78 2.137 78.12 84.263 ;
        RECT  72.6 2.137 72.72 84.263 ;
        RECT  67.2 2.137 67.32 84.263 ;
        RECT  61.8 2.137 61.92 84.263 ;
        RECT  56.4 2.137 56.52 84.263 ;
        RECT  51 2.137 51.12 84.263 ;
        RECT  45.6 2.137 45.72 84.263 ;
        RECT  40.2 2.137 40.32 84.263 ;
        RECT  34.8 2.137 34.92 84.263 ;
        RECT  29.4 2.137 29.52 84.263 ;
        RECT  24 2.137 24.12 84.263 ;
        RECT  18.6 2.137 18.72 84.263 ;
        RECT  13.2 2.137 13.32 84.263 ;
        RECT  7.8 2.137 7.92 84.263 ;
        RECT  2.4 2.137 2.52 84.263 ;
    END
  END VSS
  # OT_OBS_CLOSED layer=M5 d_um=1.536 added=629
  OBS
    LAYER RVTN ;
     RECT  2.16 2.16 88.56 2.295 ;
     RECT  2.16 2.565 88.56 2.835 ;
     RECT  2.16 3.105 88.56 3.375 ;
     RECT  2.16 3.645 88.56 3.915 ;
     RECT  2.16 4.185 88.56 4.455 ;
     RECT  2.16 4.725 88.56 4.995 ;
     RECT  2.16 5.265 88.56 5.535 ;
     RECT  2.16 5.805 88.56 6.075 ;
     RECT  2.16 6.345 88.56 6.615 ;
     RECT  2.16 6.885 88.56 7.155 ;
     RECT  2.16 7.425 88.56 7.695 ;
     RECT  2.16 7.965 88.56 8.235 ;
     RECT  2.16 8.505 88.56 8.775 ;
     RECT  2.16 9.045 88.56 9.315 ;
     RECT  2.16 9.585 88.56 9.855 ;
     RECT  2.16 10.125 88.56 10.395 ;
     RECT  2.16 10.665 88.56 10.935 ;
     RECT  2.16 11.205 88.56 11.475 ;
     RECT  2.16 11.745 88.56 12.015 ;
     RECT  2.16 12.285 88.56 12.555 ;
     RECT  2.16 12.825 88.56 13.095 ;
     RECT  2.16 13.365 88.56 13.635 ;
     RECT  2.16 13.905 88.56 14.175 ;
     RECT  2.16 14.445 88.56 14.715 ;
     RECT  2.16 14.985 88.56 15.255 ;
     RECT  2.16 15.525 88.56 15.795 ;
     RECT  2.16 16.065 88.56 16.335 ;
     RECT  2.16 16.605 88.56 16.875 ;
     RECT  2.16 17.145 88.56 17.415 ;
     RECT  2.16 17.685 88.56 17.955 ;
     RECT  2.16 18.225 88.56 18.495 ;
     RECT  2.16 18.765 88.56 19.035 ;
     RECT  2.16 19.305 88.56 19.575 ;
     RECT  2.16 19.845 88.56 20.115 ;
     RECT  2.16 20.385 88.56 20.655 ;
     RECT  2.16 20.925 88.56 21.195 ;
     RECT  2.16 21.465 88.56 21.735 ;
     RECT  2.16 22.005 88.56 22.275 ;
     RECT  2.16 22.545 88.56 22.815 ;
     RECT  2.16 23.085 88.56 23.355 ;
     RECT  2.16 23.625 88.56 23.895 ;
     RECT  2.16 24.165 88.56 24.435 ;
     RECT  2.16 24.705 88.56 24.975 ;
     RECT  2.16 25.245 88.56 25.515 ;
     RECT  2.16 25.785 88.56 26.055 ;
     RECT  2.16 26.325 88.56 26.595 ;
     RECT  2.16 26.865 88.56 27.135 ;
     RECT  2.16 27.405 88.56 27.675 ;
     RECT  2.16 27.945 88.56 28.215 ;
     RECT  2.16 28.485 88.56 28.755 ;
     RECT  2.16 29.025 88.56 29.295 ;
     RECT  2.16 29.565 88.56 29.835 ;
     RECT  2.16 30.105 88.56 30.375 ;
     RECT  2.16 30.645 88.56 30.915 ;
     RECT  2.16 31.185 88.56 31.455 ;
     RECT  2.16 31.725 88.56 31.995 ;
     RECT  2.16 32.265 88.56 32.535 ;
     RECT  2.16 32.805 88.56 33.075 ;
     RECT  2.16 33.345 88.56 33.615 ;
     RECT  2.16 33.885 88.56 34.155 ;
     RECT  2.16 34.425 88.56 34.695 ;
     RECT  2.16 34.965 88.56 35.235 ;
     RECT  2.16 35.505 88.56 35.775 ;
     RECT  2.16 36.045 88.56 36.315 ;
     RECT  2.16 36.585 88.56 36.855 ;
     RECT  2.16 37.125 88.56 37.395 ;
     RECT  2.16 37.665 88.56 37.935 ;
     RECT  2.16 38.205 88.56 38.475 ;
     RECT  2.16 38.745 88.56 39.015 ;
     RECT  2.16 39.285 88.56 39.555 ;
     RECT  2.16 39.825 88.56 40.095 ;
     RECT  2.16 40.365 88.56 40.635 ;
     RECT  2.16 40.905 88.56 41.175 ;
     RECT  2.16 41.445 88.56 41.715 ;
     RECT  2.16 41.985 88.56 42.255 ;
     RECT  2.16 42.525 88.56 42.795 ;
     RECT  2.16 43.065 88.56 43.335 ;
     RECT  2.16 43.605 88.56 43.875 ;
     RECT  2.16 44.145 88.56 44.415 ;
     RECT  2.16 44.685 88.56 44.955 ;
     RECT  2.16 45.225 88.56 45.495 ;
     RECT  2.16 45.765 88.56 46.035 ;
     RECT  2.16 46.305 88.56 46.575 ;
     RECT  2.16 46.845 88.56 47.115 ;
     RECT  2.16 47.385 88.56 47.655 ;
     RECT  2.16 47.925 88.56 48.195 ;
     RECT  2.16 48.465 88.56 48.735 ;
     RECT  2.16 49.005 88.56 49.275 ;
     RECT  2.16 49.545 88.56 49.815 ;
     RECT  2.16 50.085 88.56 50.355 ;
     RECT  2.16 50.625 88.56 50.895 ;
     RECT  2.16 51.165 88.56 51.435 ;
     RECT  2.16 51.705 88.56 51.975 ;
     RECT  2.16 52.245 88.56 52.515 ;
     RECT  2.16 52.785 88.56 53.055 ;
     RECT  2.16 53.325 88.56 53.595 ;
     RECT  2.16 53.865 88.56 54.135 ;
     RECT  2.16 54.405 88.56 54.675 ;
     RECT  2.16 54.945 88.56 55.215 ;
     RECT  2.16 55.485 88.56 55.755 ;
     RECT  2.16 56.025 88.56 56.295 ;
     RECT  2.16 56.565 88.56 56.835 ;
     RECT  2.16 57.105 88.56 57.375 ;
     RECT  2.16 57.645 88.56 57.915 ;
     RECT  2.16 58.185 88.56 58.455 ;
     RECT  2.16 58.725 88.56 58.995 ;
     RECT  2.16 59.265 88.56 59.535 ;
     RECT  2.16 59.805 88.56 60.075 ;
     RECT  2.16 60.345 88.56 60.615 ;
     RECT  2.16 60.885 88.56 61.155 ;
     RECT  2.16 61.425 88.56 61.695 ;
     RECT  2.16 61.965 88.56 62.235 ;
     RECT  2.16 62.505 88.56 62.775 ;
     RECT  2.16 63.045 88.56 63.315 ;
     RECT  2.16 63.585 88.56 63.855 ;
     RECT  2.16 64.125 88.56 64.395 ;
     RECT  2.16 64.665 88.56 64.935 ;
     RECT  2.16 65.205 88.56 65.475 ;
     RECT  2.16 65.745 88.56 66.015 ;
     RECT  2.16 66.285 88.56 66.555 ;
     RECT  2.16 66.825 88.56 67.095 ;
     RECT  2.16 67.365 88.56 67.635 ;
     RECT  2.16 67.905 88.56 68.175 ;
     RECT  2.16 68.445 88.56 68.715 ;
     RECT  2.16 68.985 88.56 69.255 ;
     RECT  2.16 69.525 88.56 69.795 ;
     RECT  2.16 70.065 88.56 70.335 ;
     RECT  2.16 70.605 88.56 70.875 ;
     RECT  2.16 71.145 88.56 71.415 ;
     RECT  2.16 71.685 88.56 71.955 ;
     RECT  2.16 72.225 88.56 72.495 ;
     RECT  2.16 72.765 88.56 73.035 ;
     RECT  2.16 73.305 88.56 73.575 ;
     RECT  2.16 73.845 88.56 74.115 ;
     RECT  2.16 74.385 88.56 74.655 ;
     RECT  2.16 74.925 88.56 75.195 ;
     RECT  2.16 75.465 88.56 75.735 ;
     RECT  2.16 76.005 88.56 76.275 ;
     RECT  2.16 76.545 88.56 76.815 ;
     RECT  2.16 77.085 88.56 77.355 ;
     RECT  2.16 77.625 88.56 77.895 ;
     RECT  2.16 78.165 88.56 78.435 ;
     RECT  2.16 78.705 88.56 78.975 ;
     RECT  2.16 79.245 88.56 79.515 ;
     RECT  2.16 79.785 88.56 80.055 ;
     RECT  2.16 80.325 88.56 80.595 ;
     RECT  2.16 80.865 88.56 81.135 ;
     RECT  2.16 81.405 88.56 81.675 ;
     RECT  2.16 81.945 88.56 82.215 ;
     RECT  2.16 82.485 88.56 82.755 ;
     RECT  2.16 83.025 88.56 83.295 ;
     RECT  2.16 83.565 88.56 83.835 ;
     RECT  2.16 84.105 88.56 84.24 ;
    LAYER RVTP ;
     RECT  2.16 2.295 88.56 2.565 ;
     RECT  2.16 2.835 88.56 3.105 ;
     RECT  2.16 3.375 88.56 3.645 ;
     RECT  2.16 3.915 88.56 4.185 ;
     RECT  2.16 4.455 88.56 4.725 ;
     RECT  2.16 4.995 88.56 5.265 ;
     RECT  2.16 5.535 88.56 5.805 ;
     RECT  2.16 6.075 88.56 6.345 ;
     RECT  2.16 6.615 88.56 6.885 ;
     RECT  2.16 7.155 88.56 7.425 ;
     RECT  2.16 7.695 88.56 7.965 ;
     RECT  2.16 8.235 88.56 8.505 ;
     RECT  2.16 8.775 88.56 9.045 ;
     RECT  2.16 9.315 88.56 9.585 ;
     RECT  2.16 9.855 88.56 10.125 ;
     RECT  2.16 10.395 88.56 10.665 ;
     RECT  2.16 10.935 88.56 11.205 ;
     RECT  2.16 11.475 88.56 11.745 ;
     RECT  2.16 12.015 88.56 12.285 ;
     RECT  2.16 12.555 88.56 12.825 ;
     RECT  2.16 13.095 88.56 13.365 ;
     RECT  2.16 13.635 88.56 13.905 ;
     RECT  2.16 14.175 88.56 14.445 ;
     RECT  2.16 14.715 88.56 14.985 ;
     RECT  2.16 15.255 88.56 15.525 ;
     RECT  2.16 15.795 88.56 16.065 ;
     RECT  2.16 16.335 88.56 16.605 ;
     RECT  2.16 16.875 88.56 17.145 ;
     RECT  2.16 17.415 88.56 17.685 ;
     RECT  2.16 17.955 88.56 18.225 ;
     RECT  2.16 18.495 88.56 18.765 ;
     RECT  2.16 19.035 88.56 19.305 ;
     RECT  2.16 19.575 88.56 19.845 ;
     RECT  2.16 20.115 88.56 20.385 ;
     RECT  2.16 20.655 88.56 20.925 ;
     RECT  2.16 21.195 88.56 21.465 ;
     RECT  2.16 21.735 88.56 22.005 ;
     RECT  2.16 22.275 88.56 22.545 ;
     RECT  2.16 22.815 88.56 23.085 ;
     RECT  2.16 23.355 88.56 23.625 ;
     RECT  2.16 23.895 88.56 24.165 ;
     RECT  2.16 24.435 88.56 24.705 ;
     RECT  2.16 24.975 88.56 25.245 ;
     RECT  2.16 25.515 88.56 25.785 ;
     RECT  2.16 26.055 88.56 26.325 ;
     RECT  2.16 26.595 88.56 26.865 ;
     RECT  2.16 27.135 88.56 27.405 ;
     RECT  2.16 27.675 88.56 27.945 ;
     RECT  2.16 28.215 88.56 28.485 ;
     RECT  2.16 28.755 88.56 29.025 ;
     RECT  2.16 29.295 88.56 29.565 ;
     RECT  2.16 29.835 88.56 30.105 ;
     RECT  2.16 30.375 88.56 30.645 ;
     RECT  2.16 30.915 88.56 31.185 ;
     RECT  2.16 31.455 88.56 31.725 ;
     RECT  2.16 31.995 88.56 32.265 ;
     RECT  2.16 32.535 88.56 32.805 ;
     RECT  2.16 33.075 88.56 33.345 ;
     RECT  2.16 33.615 88.56 33.885 ;
     RECT  2.16 34.155 88.56 34.425 ;
     RECT  2.16 34.695 88.56 34.965 ;
     RECT  2.16 35.235 88.56 35.505 ;
     RECT  2.16 35.775 88.56 36.045 ;
     RECT  2.16 36.315 88.56 36.585 ;
     RECT  2.16 36.855 88.56 37.125 ;
     RECT  2.16 37.395 88.56 37.665 ;
     RECT  2.16 37.935 88.56 38.205 ;
     RECT  2.16 38.475 88.56 38.745 ;
     RECT  2.16 39.015 88.56 39.285 ;
     RECT  2.16 39.555 88.56 39.825 ;
     RECT  2.16 40.095 88.56 40.365 ;
     RECT  2.16 40.635 88.56 40.905 ;
     RECT  2.16 41.175 88.56 41.445 ;
     RECT  2.16 41.715 88.56 41.985 ;
     RECT  2.16 42.255 88.56 42.525 ;
     RECT  2.16 42.795 88.56 43.065 ;
     RECT  2.16 43.335 88.56 43.605 ;
     RECT  2.16 43.875 88.56 44.145 ;
     RECT  2.16 44.415 88.56 44.685 ;
     RECT  2.16 44.955 88.56 45.225 ;
     RECT  2.16 45.495 88.56 45.765 ;
     RECT  2.16 46.035 88.56 46.305 ;
     RECT  2.16 46.575 88.56 46.845 ;
     RECT  2.16 47.115 88.56 47.385 ;
     RECT  2.16 47.655 88.56 47.925 ;
     RECT  2.16 48.195 88.56 48.465 ;
     RECT  2.16 48.735 88.56 49.005 ;
     RECT  2.16 49.275 88.56 49.545 ;
     RECT  2.16 49.815 88.56 50.085 ;
     RECT  2.16 50.355 88.56 50.625 ;
     RECT  2.16 50.895 88.56 51.165 ;
     RECT  2.16 51.435 88.56 51.705 ;
     RECT  2.16 51.975 88.56 52.245 ;
     RECT  2.16 52.515 88.56 52.785 ;
     RECT  2.16 53.055 88.56 53.325 ;
     RECT  2.16 53.595 88.56 53.865 ;
     RECT  2.16 54.135 88.56 54.405 ;
     RECT  2.16 54.675 88.56 54.945 ;
     RECT  2.16 55.215 88.56 55.485 ;
     RECT  2.16 55.755 88.56 56.025 ;
     RECT  2.16 56.295 88.56 56.565 ;
     RECT  2.16 56.835 88.56 57.105 ;
     RECT  2.16 57.375 88.56 57.645 ;
     RECT  2.16 57.915 88.56 58.185 ;
     RECT  2.16 58.455 88.56 58.725 ;
     RECT  2.16 58.995 88.56 59.265 ;
     RECT  2.16 59.535 88.56 59.805 ;
     RECT  2.16 60.075 88.56 60.345 ;
     RECT  2.16 60.615 88.56 60.885 ;
     RECT  2.16 61.155 88.56 61.425 ;
     RECT  2.16 61.695 88.56 61.965 ;
     RECT  2.16 62.235 88.56 62.505 ;
     RECT  2.16 62.775 88.56 63.045 ;
     RECT  2.16 63.315 88.56 63.585 ;
     RECT  2.16 63.855 88.56 64.125 ;
     RECT  2.16 64.395 88.56 64.665 ;
     RECT  2.16 64.935 88.56 65.205 ;
     RECT  2.16 65.475 88.56 65.745 ;
     RECT  2.16 66.015 88.56 66.285 ;
     RECT  2.16 66.555 88.56 66.825 ;
     RECT  2.16 67.095 88.56 67.365 ;
     RECT  2.16 67.635 88.56 67.905 ;
     RECT  2.16 68.175 88.56 68.445 ;
     RECT  2.16 68.715 88.56 68.985 ;
     RECT  2.16 69.255 88.56 69.525 ;
     RECT  2.16 69.795 88.56 70.065 ;
     RECT  2.16 70.335 88.56 70.605 ;
     RECT  2.16 70.875 88.56 71.145 ;
     RECT  2.16 71.415 88.56 71.685 ;
     RECT  2.16 71.955 88.56 72.225 ;
     RECT  2.16 72.495 88.56 72.765 ;
     RECT  2.16 73.035 88.56 73.305 ;
     RECT  2.16 73.575 88.56 73.845 ;
     RECT  2.16 74.115 88.56 74.385 ;
     RECT  2.16 74.655 88.56 74.925 ;
     RECT  2.16 75.195 88.56 75.465 ;
     RECT  2.16 75.735 88.56 76.005 ;
     RECT  2.16 76.275 88.56 76.545 ;
     RECT  2.16 76.815 88.56 77.085 ;
     RECT  2.16 77.355 88.56 77.625 ;
     RECT  2.16 77.895 88.56 78.165 ;
     RECT  2.16 78.435 88.56 78.705 ;
     RECT  2.16 78.975 88.56 79.245 ;
     RECT  2.16 79.515 88.56 79.785 ;
     RECT  2.16 80.055 88.56 80.325 ;
     RECT  2.16 80.595 88.56 80.865 ;
     RECT  2.16 81.135 88.56 81.405 ;
     RECT  2.16 81.675 88.56 81.945 ;
     RECT  2.16 82.215 88.56 82.485 ;
     RECT  2.16 82.755 88.56 83.025 ;
     RECT  2.16 83.295 88.56 83.565 ;
     RECT  2.16 83.835 88.56 84.105 ;
    LAYER M1 ;
     RECT  2.16 2.151 88.56 84.249 ;
    LAYER M2 ;
     RECT  0.103 9.09 0.535 9.108 ;
     RECT  0.103 65.412 0.535 65.43 ;
     RECT  0.103 6.822 2.16 6.84 ;
     RECT  0.535 8.442 2.16 9.612 ;
     RECT  0.103 13.032 2.16 13.05 ;
     RECT  0.103 17.622 2.16 17.64 ;
     RECT  0.139 19.89 2.16 19.908 ;
     RECT  0.103 20.7 2.16 20.718 ;
     RECT  0.103 23.832 2.16 23.85 ;
     RECT  0.103 25.56 2.16 25.578 ;
     RECT  0.535 27.918 2.16 27.936 ;
     RECT  0.535 28.692 2.16 28.71 ;
     RECT  0.535 35.28 2.16 35.298 ;
     RECT  0.535 37.872 2.16 37.89 ;
     RECT  0.535 40.644 2.16 40.662 ;
     RECT  0.103 45 2.16 45.018 ;
     RECT  0.103 52.992 2.16 53.55 ;
     RECT  0.103 56.34 2.16 56.358 ;
     RECT  0.103 62.514 2.16 62.532 ;
     RECT  0.535 64.746 2.16 65.43 ;
     RECT  0.103 68.922 2.16 68.94 ;
     RECT  0.535 74.052 2.16 74.07 ;
     RECT  2.16 2.151 8.347 84.249 ;
     RECT  8.347 2.106 8.879 84.249 ;
     RECT  8.879 2.151 10.003 84.249 ;
     RECT  10.003 2.151 12.631 84.294 ;
     RECT  12.631 2.106 13.091 84.294 ;
     RECT  13.091 2.106 14.863 84.249 ;
     RECT  15.799 0.036 15.899 0.054 ;
     RECT  14.863 1.998 17.591 84.249 ;
     RECT  17.591 2.07 18.859 84.249 ;
     RECT  18.859 2.034 19.499 84.249 ;
     RECT  19.499 2.07 20.371 84.249 ;
     RECT  20.371 2.034 20.903 84.249 ;
     RECT  20.903 2.07 22.819 84.249 ;
     RECT  22.819 2.07 24.871 84.294 ;
     RECT  24.871 2.034 25.619 84.294 ;
     RECT  25.619 2.07 26.779 84.294 ;
     RECT  26.779 2.07 27.859 84.366 ;
     RECT  27.859 2.034 29.291 84.366 ;
     RECT  29.291 2.07 31.675 84.366 ;
     RECT  31.675 2.034 33.115 84.366 ;
     RECT  33.115 1.926 33.151 84.366 ;
     RECT  33.151 1.881 33.295 84.366 ;
     RECT  33.295 1.152 33.395 84.366 ;
     RECT  33.395 1.881 34.727 84.366 ;
     RECT  34.727 1.881 36.859 84.294 ;
     RECT  36.859 1.728 36.959 84.294 ;
     RECT  36.959 1.881 37.679 84.294 ;
     RECT  38.371 0.036 38.471 0.054 ;
     RECT  37.679 1.962 38.767 84.294 ;
     RECT  39.703 0.036 39.875 0.054 ;
     RECT  38.767 1.962 41.171 84.366 ;
     RECT  42.871 0.036 43.115 0.054 ;
     RECT  41.171 2.034 44.447 84.366 ;
     RECT  44.447 2.07 45.859 84.366 ;
     RECT  45.859 1.728 46.175 84.366 ;
     RECT  46.175 2.07 47.335 84.366 ;
     RECT  47.335 2.034 49.955 84.366 ;
     RECT  49.955 2.07 50.639 84.366 ;
     RECT  50.639 2.07 51.871 84.294 ;
     RECT  51.871 1.728 52.403 84.294 ;
     RECT  52.403 2.07 53.987 84.294 ;
     RECT  53.987 2.07 57.343 84.249 ;
     RECT  57.343 2.034 59.027 84.249 ;
     RECT  59.027 2.07 59.971 84.249 ;
     RECT  59.971 2.034 64.219 84.249 ;
     RECT  64.219 2.034 66.415 84.294 ;
     RECT  66.415 2.034 69.683 84.33 ;
     RECT  69.683 2.151 73.931 84.33 ;
     RECT  73.931 2.151 75.055 84.249 ;
     RECT  75.055 2.151 81.815 84.294 ;
     RECT  81.815 2.151 88.56 84.249 ;
    LAYER M3 ;
     RECT  43.092 0.059 43.11 0.091 ;
     RECT  15.804 0.059 15.822 1.723 ;
     RECT  38.016 0.091 38.466 1.723 ;
     RECT  39.708 0.059 39.726 1.723 ;
     RECT  45.468 0.091 45.882 1.723 ;
     RECT  33.3 0.091 33.894 1.876 ;
     RECT  36.216 1.723 36.954 1.876 ;
     RECT  38.016 1.723 39.726 1.876 ;
     RECT  33.156 1.876 33.894 1.921 ;
     RECT  13.644 1.723 14.382 1.993 ;
     RECT  15.156 1.723 15.822 1.993 ;
     RECT  16.884 1.723 17.37 1.993 ;
     RECT  18.828 1.723 18.882 2.029 ;
     RECT  21.168 1.723 21.87 2.029 ;
     RECT  24.876 1.723 25.11 2.029 ;
     RECT  36.216 1.876 39.726 2.029 ;
     RECT  40.932 0.091 41.382 2.029 ;
     RECT  43.092 0.091 44.37 2.029 ;
     RECT  45.468 1.723 46.638 2.029 ;
     RECT  50.004 1.723 50.382 2.029 ;
     RECT  13.644 1.993 15.822 2.101 ;
     RECT  8.352 2.101 8.874 2.143 ;
     RECT  12.492 1.723 12.87 2.143 ;
     RECT  13.644 2.101 16.038 2.143 ;
     RECT  18.828 2.029 19.494 2.143 ;
     RECT  28.872 1.723 29.394 2.143 ;
     RECT  49.932 2.029 50.382 2.143 ;
     RECT  51.156 1.723 53.37 2.143 ;
     RECT  55.8 0.571 55.818 2.143 ;
     RECT  56.988 2.029 57.366 2.143 ;
     RECT  18.615 2.143 19.494 2.155 ;
     RECT  20.376 2.029 21.87 2.155 ;
     RECT  23.364 2.143 24.105 2.191 ;
     RECT  28.872 2.143 29.505 2.191 ;
     RECT  30.276 1.723 30.87 2.191 ;
     RECT  34.632 1.723 35.37 2.191 ;
     RECT  36.216 2.029 41.382 2.191 ;
     RECT  43.092 2.029 44.442 2.191 ;
     RECT  45.468 2.029 47.394 2.191 ;
     RECT  48.384 1.723 48.87 2.191 ;
     RECT  54.108 1.723 54.126 2.191 ;
     RECT  55.8 2.143 57.366 2.191 ;
     RECT  61.815 2.143 61.905 2.191 ;
     RECT  63.324 2.065 63.342 2.191 ;
     RECT  72.615 2.143 72.705 2.191 ;
     RECT  83.415 2.143 83.505 2.191 ;
     RECT  76.464 2.191 76.482 2.203 ;
     RECT  9.864 1.723 11.394 2.227 ;
     RECT  16.884 1.993 17.586 2.227 ;
     RECT  61.815 2.191 62.586 2.227 ;
     RECT  65.448 2.101 65.466 2.227 ;
     RECT  79.02 2.191 79.038 2.227 ;
     RECT  83.415 2.191 84.006 2.227 ;
     RECT  7.236 2.143 8.874 2.251 ;
     RECT  27.864 2.203 27.918 2.251 ;
     RECT  42.12 1.723 42.138 2.251 ;
     RECT  42.948 2.191 47.394 2.251 ;
     RECT  58.968 2.191 59.022 2.251 ;
     RECT  59.976 2.029 59.994 2.251 ;
     RECT  67.215 2.143 67.305 2.251 ;
     RECT  68.184 2.191 68.202 2.251 ;
     RECT  69.66 2.029 69.678 2.251 ;
     RECT  75.996 2.203 76.482 2.255 ;
     RECT  3.492 2.227 3.51 2.263 ;
     RECT  4.464 2.227 4.482 2.263 ;
     RECT  9.864 2.227 11.466 2.263 ;
     RECT  12.492 2.143 16.038 2.263 ;
     RECT  16.812 2.227 17.586 2.263 ;
     RECT  18.615 2.155 21.87 2.263 ;
     RECT  22.86 2.191 24.105 2.263 ;
     RECT  24.876 2.029 25.614 2.263 ;
     RECT  26.352 1.723 26.406 2.263 ;
     RECT  31.68 2.029 32.382 2.263 ;
     RECT  33.12 1.921 33.894 2.263 ;
     RECT  34.632 2.191 41.382 2.263 ;
     RECT  42.12 2.251 47.394 2.263 ;
     RECT  48.312 2.191 48.87 2.263 ;
     RECT  49.932 2.143 53.37 2.263 ;
     RECT  54.108 2.191 54.882 2.263 ;
     RECT  55.8 2.191 57.438 2.263 ;
     RECT  61.812 2.227 62.586 2.263 ;
     RECT  63.324 2.191 64.53 2.263 ;
     RECT  65.376 2.227 65.466 2.263 ;
     RECT  74.196 2.191 74.214 2.263 ;
     RECT  78.015 2.143 78.105 2.263 ;
     RECT  82.44 2.227 82.458 2.263 ;
     RECT  83.415 2.227 84.51 2.263 ;
     RECT  3.492 2.263 4.482 2.285 ;
     RECT  3.96 2.285 4.482 2.299 ;
     RECT  28.872 2.191 30.87 2.299 ;
     RECT  31.644 2.263 33.894 2.299 ;
     RECT  34.632 2.263 47.502 2.299 ;
     RECT  66.744 2.251 68.202 2.299 ;
     RECT  72.615 2.191 73.422 2.299 ;
     RECT  74.196 2.263 75.006 2.299 ;
     RECT  24.876 2.263 26.406 2.335 ;
     RECT  27.288 2.251 27.918 2.335 ;
     RECT  28.872 2.299 47.502 2.335 ;
     RECT  48.312 2.263 57.438 2.335 ;
     RECT  58.716 2.251 59.022 2.335 ;
     RECT  61.812 2.263 64.53 2.335 ;
     RECT  65.376 2.263 65.574 2.335 ;
     RECT  3.96 2.299 4.554 2.371 ;
     RECT  6.516 2.251 8.874 2.371 ;
     RECT  9.864 2.263 16.038 2.371 ;
     RECT  16.812 2.263 17.694 2.371 ;
     RECT  18.615 2.263 24.105 2.371 ;
     RECT  24.876 2.335 27.918 2.371 ;
     RECT  28.872 2.335 59.022 2.371 ;
     RECT  59.796 2.251 59.994 2.371 ;
     RECT  61.812 2.335 65.574 2.371 ;
     RECT  66.708 2.299 68.202 2.371 ;
     RECT  68.976 2.251 70.362 2.371 ;
     RECT  76.284 2.255 76.482 2.371 ;
     RECT  77.616 2.263 78.105 2.371 ;
     RECT  79.02 2.227 79.434 2.371 ;
     RECT  81 2.263 81.126 2.371 ;
     RECT  82.44 2.263 84.51 2.371 ;
     RECT  2.415 2.143 2.505 2.413 ;
     RECT  16.812 2.371 24.105 2.413 ;
     RECT  24.876 2.371 59.994 2.413 ;
     RECT  76.284 2.371 78.105 2.413 ;
     RECT  3.96 2.371 4.626 2.461 ;
     RECT  16.812 2.413 59.994 2.461 ;
     RECT  60.84 2.371 60.858 2.461 ;
     RECT  61.812 2.371 70.362 2.461 ;
     RECT  76.284 2.413 78.297 2.461 ;
     RECT  79.02 2.371 79.974 2.461 ;
     RECT  6.516 2.371 16.038 2.489 ;
     RECT  6.516 2.489 6.678 2.491 ;
     RECT  16.812 2.461 60.858 2.497 ;
     RECT  61.632 2.461 70.362 2.497 ;
     RECT  72.615 2.299 75.006 2.497 ;
     RECT  82.44 2.371 85.482 2.497 ;
     RECT  86.364 2.461 86.382 2.497 ;
     RECT  16.812 2.497 70.362 2.569 ;
     RECT  82.44 2.497 86.382 2.569 ;
     RECT  7.452 2.489 16.038 2.605 ;
     RECT  16.812 2.569 70.722 2.605 ;
     RECT  80.856 2.371 81.414 2.605 ;
     RECT  3.96 2.461 4.95 2.641 ;
     RECT  6.408 2.491 6.678 2.641 ;
     RECT  7.452 2.605 70.722 2.641 ;
     RECT  71.64 2.299 71.658 2.641 ;
     RECT  72.615 2.497 75.114 2.641 ;
     RECT  76.284 2.461 79.974 2.641 ;
     RECT  80.856 2.605 81.522 2.641 ;
     RECT  7.452 2.641 70.902 2.731 ;
     RECT  71.64 2.641 75.51 2.731 ;
     RECT  80.82 2.641 81.702 2.875 ;
     RECT  82.44 2.569 87.102 2.875 ;
     RECT  76.284 2.641 80.082 2.971 ;
     RECT  80.82 2.875 87.102 2.971 ;
     RECT  3.96 2.641 6.678 3.029 ;
     RECT  3.96 3.029 5.094 3.037 ;
     RECT  3.492 3.037 5.094 3.073 ;
     RECT  7.452 2.731 75.51 3.109 ;
     RECT  76.284 2.971 87.102 3.109 ;
     RECT  2.415 2.413 2.697 3.145 ;
     RECT  3.42 3.073 5.094 3.145 ;
     RECT  5.904 3.029 6.678 3.355 ;
     RECT  7.452 3.109 87.102 3.355 ;
     RECT  5.904 3.355 87.102 3.643 ;
     RECT  5.904 3.643 87.822 3.773 ;
     RECT  2.415 3.145 5.094 3.847 ;
     RECT  5.904 3.773 59.346 3.847 ;
     RECT  2.415 3.847 59.346 3.947 ;
     RECT  2.415 3.947 59.31 4.061 ;
     RECT  7.452 4.061 59.31 4.109 ;
     RECT  60.156 3.773 87.822 4.387 ;
     RECT  7.488 4.109 59.31 4.765 ;
     RECT  2.415 4.061 6.57 4.801 ;
     RECT  7.488 4.765 59.346 4.801 ;
     RECT  7.488 4.801 59.418 4.891 ;
     RECT  60.156 4.387 88.002 4.891 ;
     RECT  7.488 4.891 88.002 4.955 ;
     RECT  2.415 4.801 6.75 4.963 ;
     RECT  7.488 4.955 82.062 4.963 ;
     RECT  82.872 4.955 88.002 5.071 ;
     RECT  2.415 4.963 82.062 5.707 ;
     RECT  82.872 5.071 88.398 5.707 ;
     RECT  2.415 5.707 88.398 6.269 ;
     RECT  0.108 6.817 0.126 6.893 ;
     RECT  37.26 6.269 88.398 7.087 ;
     RECT  2.415 6.269 36.342 7.195 ;
     RECT  2.412 7.195 36.342 7.501 ;
     RECT  37.188 7.087 88.398 7.501 ;
     RECT  2.412 7.501 88.398 7.735 ;
     RECT  2.304 7.735 88.398 8.195 ;
     RECT  0.54 8.437 0.558 8.717 ;
     RECT  2.415 8.195 88.398 8.971 ;
     RECT  2.304 8.971 88.398 9.011 ;
     RECT  2.304 9.011 52.974 9.113 ;
     RECT  53.748 9.011 88.398 9.239 ;
     RECT  0.108 9.085 0.126 9.245 ;
     RECT  2.304 9.113 31.734 9.275 ;
     RECT  69.192 9.239 88.398 9.391 ;
     RECT  32.544 9.113 52.974 9.509 ;
     RECT  69.192 9.391 88.434 9.653 ;
     RECT  0.54 9.589 0.558 9.773 ;
     RECT  37.116 9.509 52.974 9.779 ;
     RECT  41.508 9.779 52.974 9.787 ;
     RECT  53.748 9.239 68.418 9.787 ;
     RECT  19.8 9.275 31.734 9.859 ;
     RECT  19.8 9.859 31.806 9.931 ;
     RECT  32.544 9.509 36.342 9.931 ;
     RECT  2.415 9.275 19.062 10.027 ;
     RECT  2.304 10.027 19.062 10.049 ;
     RECT  41.508 9.787 68.418 10.049 ;
     RECT  19.8 9.931 36.342 10.201 ;
     RECT  41.832 10.049 68.418 10.267 ;
     RECT  69.192 9.653 88.398 10.267 ;
     RECT  19.656 10.201 36.342 10.603 ;
     RECT  37.116 9.779 40.497 10.603 ;
     RECT  19.656 10.603 40.497 10.741 ;
     RECT  19.656 10.741 40.806 10.891 ;
     RECT  41.832 10.267 88.398 10.891 ;
     RECT  2.304 10.049 18.897 11.083 ;
     RECT  19.656 10.891 88.398 11.083 ;
     RECT  2.304 11.083 88.398 11.399 ;
     RECT  21.636 11.399 88.398 11.405 ;
     RECT  2.304 11.399 20.898 11.435 ;
     RECT  20.628 11.435 20.898 12.187 ;
     RECT  21.636 11.405 41.058 12.187 ;
     RECT  41.832 11.405 88.398 12.361 ;
     RECT  2.304 11.435 19.89 12.517 ;
     RECT  20.628 12.187 41.058 12.517 ;
     RECT  2.304 12.517 41.058 12.631 ;
     RECT  41.796 12.361 88.398 12.631 ;
     RECT  2.304 12.631 88.398 12.829 ;
     RECT  2.304 12.829 88.506 13.595 ;
     RECT  0.108 13.027 0.126 13.709 ;
     RECT  2.412 13.595 88.506 13.973 ;
     RECT  2.415 13.973 88.506 14.099 ;
     RECT  2.415 14.099 41.058 15.061 ;
     RECT  41.796 14.099 88.506 15.061 ;
     RECT  2.415 15.061 88.506 16.555 ;
     RECT  2.304 16.555 88.506 16.673 ;
     RECT  2.412 16.673 88.506 17.117 ;
     RECT  0.108 17.083 0.126 17.885 ;
     RECT  2.415 17.117 88.506 18.379 ;
     RECT  2.304 18.379 88.506 19.769 ;
     RECT  47.628 19.769 88.506 19.877 ;
     RECT  0.108 19.195 0.126 19.885 ;
     RECT  2.304 19.769 17.586 20.491 ;
     RECT  18.504 19.769 46.638 20.539 ;
     RECT  2.268 20.491 17.586 20.587 ;
     RECT  18.504 20.539 46.962 20.587 ;
     RECT  2.268 20.587 46.962 20.731 ;
     RECT  47.916 19.877 88.506 20.731 ;
     RECT  2.268 20.731 88.506 20.885 ;
     RECT  0.108 19.885 0.162 21.053 ;
     RECT  2.34 20.885 88.506 21.389 ;
     RECT  0.108 21.053 0.126 21.581 ;
     RECT  2.34 21.389 42.138 22.075 ;
     RECT  2.304 22.075 42.138 22.235 ;
     RECT  2.34 22.235 42.138 22.243 ;
     RECT  42.876 21.389 88.506 22.243 ;
     RECT  0.108 22.507 0.126 22.637 ;
     RECT  2.34 22.243 88.506 23.131 ;
     RECT  2.304 23.131 88.506 23.279 ;
     RECT  2.304 23.279 88.398 23.585 ;
     RECT  2.415 23.585 88.398 23.819 ;
     RECT  15.732 23.819 88.398 23.891 ;
     RECT  15.948 23.891 88.398 24.089 ;
     RECT  0.108 23.827 0.126 24.221 ;
     RECT  15.948 24.089 87.966 24.395 ;
     RECT  2.415 23.819 14.994 24.403 ;
     RECT  2.34 24.403 14.994 24.673 ;
     RECT  15.948 24.395 87.678 24.673 ;
     RECT  2.34 24.673 87.678 25.169 ;
     RECT  81.288 25.169 87.678 25.321 ;
     RECT  81.288 25.321 87.858 25.483 ;
     RECT  81.288 25.483 88.11 25.555 ;
     RECT  0.108 25.555 0.126 25.757 ;
     RECT  2.34 25.169 80.55 26.023 ;
     RECT  81.288 25.555 88.434 26.023 ;
     RECT  2.34 26.023 88.434 26.248 ;
     RECT  2.304 26.248 88.434 26.285 ;
     RECT  2.34 26.285 88.434 26.429 ;
     RECT  2.415 26.429 88.434 26.789 ;
     RECT  60.948 26.789 88.434 26.797 ;
     RECT  2.415 26.789 60.102 27.239 ;
     RECT  2.415 27.239 59.778 27.409 ;
     RECT  2.376 27.409 59.778 27.835 ;
     RECT  2.304 27.835 59.778 27.905 ;
     RECT  2.415 27.905 59.778 28.255 ;
     RECT  60.948 26.797 88.506 28.255 ;
     RECT  2.415 28.255 88.506 28.409 ;
     RECT  0.54 27.913 0.558 28.507 ;
     RECT  0.108 28.507 0.558 28.637 ;
     RECT  2.415 28.409 59.886 28.891 ;
     RECT  0.54 28.637 0.558 29.165 ;
     RECT  2.304 28.891 59.886 29.263 ;
     RECT  2.304 29.263 59.922 29.371 ;
     RECT  60.732 28.409 88.506 29.371 ;
     RECT  2.304 29.371 88.506 30.029 ;
     RECT  2.304 30.029 87.894 30.065 ;
     RECT  43.992 30.065 87.894 30.335 ;
     RECT  43.992 30.335 87.858 30.407 ;
     RECT  0.108 30.619 0.126 30.749 ;
     RECT  43.992 30.407 87.822 30.839 ;
     RECT  2.304 30.065 43.182 30.991 ;
     RECT  43.992 30.839 87.714 30.991 ;
     RECT  2.304 30.991 87.714 31.927 ;
     RECT  2.304 31.927 87.858 31.955 ;
     RECT  2.34 31.955 87.858 32.027 ;
     RECT  0.108 32.059 0.126 32.237 ;
     RECT  2.34 32.027 87.822 32.837 ;
     RECT  17.784 32.837 87.822 32.909 ;
     RECT  2.34 32.837 17.01 33.067 ;
     RECT  2.304 33.067 17.01 33.925 ;
     RECT  17.784 32.909 87.75 33.925 ;
     RECT  2.304 33.925 87.75 34.393 ;
     RECT  2.304 34.393 87.786 34.771 ;
     RECT  2.304 34.771 87.894 35.275 ;
     RECT  0.54 35.275 0.558 35.501 ;
     RECT  2.304 35.275 88.002 35.699 ;
     RECT  2.304 35.699 87.894 36.149 ;
     RECT  2.304 36.149 54.342 36.931 ;
     RECT  55.08 36.149 87.894 36.931 ;
     RECT  0.108 36.907 0.126 37.037 ;
     RECT  2.304 36.931 87.894 37.291 ;
     RECT  1.98 37.291 87.894 37.469 ;
     RECT  2.304 37.469 87.894 37.471 ;
     RECT  2.304 37.471 88.002 37.589 ;
     RECT  2.304 37.589 87.894 37.625 ;
     RECT  2.304 37.625 87.858 37.949 ;
     RECT  0.54 37.867 0.558 38.381 ;
     RECT  2.34 37.949 87.858 38.677 ;
     RECT  2.34 38.677 87.894 38.749 ;
     RECT  2.34 38.749 87.93 38.875 ;
     RECT  2.304 38.875 87.93 39.901 ;
     RECT  2.304 39.901 88.038 39.917 ;
     RECT  76.86 39.917 88.038 40.019 ;
     RECT  2.304 39.917 76.014 40.061 ;
     RECT  0.108 39.883 0.126 40.109 ;
     RECT  77.04 40.019 88.038 40.289 ;
     RECT  77.04 40.289 88.002 40.801 ;
     RECT  2.34 40.061 76.014 40.936 ;
     RECT  2.304 40.936 76.014 40.973 ;
     RECT  2.415 40.973 76.014 41.071 ;
     RECT  76.896 40.801 88.002 41.071 ;
     RECT  90.612 41.035 90.63 41.165 ;
     RECT  2.415 41.071 88.002 41.179 ;
     RECT  0.54 40.639 0.558 41.261 ;
     RECT  2.415 41.179 88.326 41.521 ;
     RECT  2.415 41.521 88.434 41.755 ;
     RECT  2.304 41.755 88.434 41.792 ;
     RECT  2.34 41.792 88.434 42.523 ;
     RECT  2.304 42.523 88.434 42.755 ;
     RECT  2.34 42.755 88.434 42.989 ;
     RECT  2.34 42.989 88.326 43.097 ;
     RECT  2.376 43.097 88.326 43.529 ;
     RECT  2.376 43.529 87.966 43.601 ;
     RECT  2.376 43.601 87.93 43.799 ;
     RECT  2.412 43.799 87.93 44.635 ;
     RECT  2.304 44.635 87.93 44.681 ;
     RECT  20.916 44.681 87.93 44.761 ;
     RECT  20.916 44.761 87.966 44.879 ;
     RECT  2.304 44.681 19.962 44.915 ;
     RECT  2.415 44.915 19.962 44.951 ;
     RECT  15.588 44.951 19.962 45.149 ;
     RECT  90.612 45.019 90.63 45.389 ;
     RECT  0.108 44.995 0.126 45.533 ;
     RECT  15.66 45.149 19.962 45.535 ;
     RECT  20.916 44.879 87.93 45.535 ;
     RECT  2.415 44.951 14.778 45.841 ;
     RECT  15.66 45.535 87.93 45.841 ;
     RECT  2.415 45.841 14.814 45.931 ;
     RECT  2.304 45.931 14.814 46.111 ;
     RECT  15.66 45.841 88.038 46.111 ;
     RECT  2.304 46.111 88.074 46.381 ;
     RECT  2.304 46.381 88.218 47.039 ;
     RECT  2.304 47.039 37.962 47.759 ;
     RECT  33.984 47.759 37.962 48.199 ;
     RECT  38.772 47.039 88.218 48.199 ;
     RECT  33.984 48.199 88.218 48.497 ;
     RECT  2.304 47.759 33.21 48.775 ;
     RECT  33.984 48.497 37.962 48.775 ;
     RECT  2.304 48.775 37.962 49.099 ;
     RECT  38.808 48.497 88.218 49.199 ;
     RECT  2.268 49.099 37.962 49.307 ;
     RECT  2.304 49.307 37.962 49.315 ;
     RECT  38.808 49.199 59.886 49.315 ;
     RECT  2.304 49.315 59.886 49.919 ;
     RECT  23.94 49.919 59.886 50.125 ;
     RECT  60.66 49.199 88.074 50.125 ;
     RECT  23.94 50.125 88.074 50.279 ;
     RECT  30.708 50.279 88.074 50.315 ;
     RECT  0.108 50.155 0.126 50.333 ;
     RECT  2.304 49.919 23.166 50.387 ;
     RECT  38.448 50.315 88.074 50.459 ;
     RECT  23.94 50.279 29.97 50.549 ;
     RECT  2.34 50.387 23.166 50.621 ;
     RECT  23.94 50.549 29.898 50.935 ;
     RECT  42.768 50.459 88.074 50.935 ;
     RECT  30.78 50.315 37.674 51.161 ;
     RECT  2.34 50.621 22.842 51.163 ;
     RECT  2.304 51.163 22.842 51.233 ;
     RECT  38.448 50.459 42.03 51.241 ;
     RECT  42.768 50.935 88.146 51.241 ;
     RECT  38.448 51.241 88.146 51.359 ;
     RECT  2.376 51.233 22.842 51.475 ;
     RECT  23.616 50.935 29.898 51.475 ;
     RECT  33.336 51.161 37.674 51.475 ;
     RECT  30.78 51.161 32.562 51.643 ;
     RECT  2.376 51.475 29.898 51.673 ;
     RECT  30.744 51.643 32.562 51.673 ;
     RECT  33.336 51.475 37.71 51.745 ;
     RECT  38.448 51.359 87.966 51.745 ;
     RECT  2.376 51.673 32.562 51.907 ;
     RECT  33.336 51.745 87.966 51.907 ;
     RECT  2.376 51.907 87.966 51.935 ;
     RECT  2.376 51.935 71.802 51.979 ;
     RECT  2.304 51.979 71.802 52.745 ;
     RECT  2.415 52.745 71.802 52.987 ;
     RECT  72.576 51.935 87.966 52.987 ;
     RECT  0.108 52.987 0.126 53.597 ;
     RECT  2.415 52.987 87.966 54.331 ;
     RECT  2.34 54.331 87.966 54.571 ;
     RECT  2.304 54.571 87.966 54.599 ;
     RECT  2.304 54.599 80.19 55.381 ;
     RECT  81.072 54.599 87.966 55.381 ;
     RECT  2.304 55.381 87.966 55.627 ;
     RECT  2.268 55.627 87.966 55.787 ;
     RECT  2.304 55.787 87.966 56.219 ;
     RECT  2.304 56.219 87.858 56.399 ;
     RECT  0.108 56.335 0.126 56.477 ;
     RECT  2.304 56.399 80.55 56.957 ;
     RECT  31.716 56.957 80.55 57.029 ;
     RECT  31.716 57.029 33.894 57.065 ;
     RECT  34.632 57.029 80.55 57.181 ;
     RECT  81.324 56.399 87.858 57.181 ;
     RECT  34.632 57.181 87.858 57.299 ;
     RECT  34.632 57.299 87.138 57.569 ;
     RECT  31.716 57.065 33.858 57.835 ;
     RECT  34.632 57.569 86.058 57.835 ;
     RECT  31.716 57.835 86.058 57.839 ;
     RECT  87.12 57.569 87.138 57.839 ;
     RECT  82.152 57.839 86.058 57.947 ;
     RECT  82.152 57.947 85.95 57.983 ;
     RECT  2.304 56.957 30.978 57.991 ;
     RECT  31.716 57.839 81.342 57.991 ;
     RECT  85.932 57.983 85.95 58.109 ;
     RECT  82.152 57.983 85.158 58.157 ;
     RECT  2.304 57.991 81.342 58.451 ;
     RECT  2.304 58.451 31.878 58.487 ;
     RECT  32.688 58.451 81.342 58.621 ;
     RECT  82.152 58.157 84.978 58.621 ;
     RECT  32.688 58.621 84.978 58.685 ;
     RECT  32.688 58.685 79.038 58.757 ;
     RECT  2.304 58.487 31.446 58.829 ;
     RECT  32.688 58.757 78.966 59.063 ;
     RECT  32.688 59.063 77.058 59.197 ;
     RECT  18.504 58.829 31.446 59.233 ;
     RECT  32.328 59.197 77.058 59.233 ;
     RECT  79.812 58.685 84.978 59.261 ;
     RECT  18.504 59.233 77.058 59.297 ;
     RECT  18.504 59.297 25.47 59.459 ;
     RECT  79.812 59.261 84.366 59.459 ;
     RECT  79.812 59.459 84.294 59.467 ;
     RECT  0.108 59.323 0.126 59.501 ;
     RECT  26.424 59.297 77.058 59.531 ;
     RECT  79.776 59.467 84.294 59.567 ;
     RECT  26.424 59.531 26.838 59.603 ;
     RECT  27.648 59.531 77.058 59.603 ;
     RECT  69.804 59.603 77.058 59.809 ;
     RECT  78.012 59.063 78.966 59.809 ;
     RECT  27.648 59.603 68.958 59.837 ;
     RECT  2.304 58.829 17.766 59.845 ;
     RECT  18.504 59.459 25.398 59.845 ;
     RECT  2.304 59.845 25.398 60.235 ;
     RECT  79.812 59.567 84.294 60.277 ;
     RECT  77.94 59.809 78.966 60.379 ;
     RECT  79.812 60.277 84.546 60.379 ;
     RECT  2.304 60.235 25.65 60.385 ;
     RECT  26.424 59.603 26.766 60.385 ;
     RECT  27.648 59.837 52.434 60.385 ;
     RECT  69.804 59.809 77.202 60.385 ;
     RECT  69.732 60.385 77.202 60.421 ;
     RECT  77.94 60.379 84.546 60.421 ;
     RECT  53.316 59.837 68.958 60.475 ;
     RECT  69.732 60.421 84.546 60.475 ;
     RECT  2.304 60.385 52.434 60.575 ;
     RECT  85.392 60.421 85.41 60.619 ;
     RECT  85.392 60.619 85.914 60.655 ;
     RECT  85.392 60.655 86.202 60.691 ;
     RECT  85.392 60.691 86.562 60.781 ;
     RECT  2.412 60.575 52.434 60.809 ;
     RECT  32.868 60.809 52.434 60.817 ;
     RECT  85.392 60.781 87.174 60.853 ;
     RECT  85.392 60.853 87.21 60.961 ;
     RECT  53.316 60.475 84.546 61.003 ;
     RECT  53.244 61.003 84.546 61.051 ;
     RECT  85.392 60.961 87.354 61.051 ;
     RECT  53.244 61.051 87.354 61.393 ;
     RECT  2.412 60.809 32.094 61.429 ;
     RECT  32.868 60.817 52.47 61.465 ;
     RECT  53.244 61.393 88.038 61.465 ;
     RECT  32.868 61.465 88.038 61.529 ;
     RECT  2.34 61.429 32.094 61.735 ;
     RECT  2.304 61.735 32.094 61.771 ;
     RECT  32.868 61.529 83.97 61.771 ;
     RECT  2.304 61.771 83.97 61.889 ;
     RECT  84.708 61.529 88.038 62.005 ;
     RECT  84.708 62.005 88.29 62.041 ;
     RECT  2.304 61.889 21.546 62.267 ;
     RECT  22.32 61.889 83.97 62.275 ;
     RECT  84.708 62.041 88.326 62.275 ;
     RECT  20.916 62.267 21.546 62.303 ;
     RECT  2.304 62.267 20.178 62.477 ;
     RECT  21.096 62.303 21.546 62.671 ;
     RECT  22.32 62.275 88.326 62.671 ;
     RECT  0.108 62.509 0.126 62.765 ;
     RECT  21.096 62.671 88.326 62.969 ;
     RECT  21.096 62.969 88.074 63.085 ;
     RECT  2.376 62.477 20.178 63.121 ;
     RECT  20.916 63.085 88.074 63.121 ;
     RECT  2.376 63.121 88.074 63.275 ;
     RECT  2.376 63.275 87.714 63.383 ;
     RECT  18.615 63.383 87.714 63.959 ;
     RECT  18.615 63.959 73.71 64.085 ;
     RECT  2.376 63.383 17.874 64.201 ;
     RECT  18.615 64.085 73.458 64.201 ;
     RECT  2.376 64.201 73.458 64.315 ;
     RECT  74.448 63.959 87.714 64.471 ;
     RECT  74.448 64.471 87.75 64.661 ;
     RECT  2.304 64.315 73.458 64.843 ;
     RECT  2.268 64.843 73.458 64.967 ;
     RECT  2.304 64.967 73.458 64.975 ;
     RECT  74.448 64.661 87.714 64.975 ;
     RECT  0.54 64.741 0.558 65.117 ;
     RECT  2.304 64.975 73.602 65.435 ;
     RECT  0.108 65.407 0.126 65.645 ;
     RECT  60.696 65.435 73.602 65.713 ;
     RECT  74.376 64.975 87.714 65.713 ;
     RECT  2.304 65.435 59.958 66.181 ;
     RECT  60.696 65.713 87.714 66.181 ;
     RECT  2.304 66.181 87.714 66.479 ;
     RECT  2.304 66.479 76.086 67.243 ;
     RECT  2.304 67.243 76.122 67.261 ;
     RECT  76.86 66.479 87.714 67.261 ;
     RECT  2.304 67.261 87.714 67.297 ;
     RECT  2.304 67.297 87.75 67.369 ;
     RECT  2.304 67.369 87.786 67.603 ;
     RECT  2.304 67.603 87.858 68.369 ;
     RECT  75.24 68.369 87.858 68.989 ;
     RECT  75.24 68.989 87.894 69.025 ;
     RECT  0.108 68.917 0.126 69.053 ;
     RECT  75.24 69.025 87.966 69.179 ;
     RECT  2.304 68.369 74.43 69.331 ;
     RECT  75.24 69.179 87.822 69.331 ;
     RECT  2.304 69.331 87.822 70.349 ;
     RECT  2.415 70.349 87.822 70.799 ;
     RECT  2.415 70.799 87.498 70.979 ;
     RECT  2.415 70.979 87.318 71.069 ;
     RECT  2.415 71.069 87.21 71.347 ;
     RECT  2.304 71.347 87.21 71.405 ;
     RECT  2.415 71.405 87.21 71.753 ;
     RECT  2.415 71.753 74.61 71.789 ;
     RECT  75.384 71.753 87.21 72.031 ;
     RECT  2.415 71.789 74.502 72.149 ;
     RECT  75.384 72.031 87.282 72.265 ;
     RECT  75.384 72.265 87.462 72.463 ;
     RECT  75.384 72.463 88.002 72.571 ;
     RECT  75.348 72.571 88.002 72.805 ;
     RECT  2.415 72.149 74.466 72.967 ;
     RECT  75.348 72.805 88.146 72.967 ;
     RECT  2.415 72.967 88.146 73.075 ;
     RECT  2.415 73.075 88.362 73.483 ;
     RECT  2.304 73.483 88.362 73.769 ;
     RECT  0.54 74.047 0.558 74.285 ;
     RECT  2.304 73.769 88.218 74.309 ;
     RECT  2.304 74.309 88.146 75.119 ;
     RECT  2.304 75.119 15.606 75.197 ;
     RECT  16.344 75.119 87.678 75.263 ;
     RECT  2.304 75.197 15.426 75.461 ;
     RECT  2.304 75.461 15.318 75.505 ;
     RECT  2.268 75.505 15.318 75.629 ;
     RECT  16.344 75.263 87.318 75.839 ;
     RECT  55.512 75.839 87.318 75.929 ;
     RECT  16.344 75.839 54.774 76.045 ;
     RECT  2.304 75.629 15.318 76.207 ;
     RECT  2.304 76.207 15.354 76.309 ;
     RECT  16.272 76.045 54.774 76.309 ;
     RECT  55.656 75.929 87.318 76.379 ;
     RECT  2.304 76.309 54.774 76.603 ;
     RECT  2.268 76.603 54.774 76.747 ;
     RECT  55.656 76.379 83.97 76.747 ;
     RECT  2.268 76.747 83.97 76.775 ;
     RECT  2.268 76.775 54.162 76.847 ;
     RECT  54.936 76.775 83.97 77.359 ;
     RECT  84.708 76.379 87.318 77.359 ;
     RECT  0.108 76.795 0.126 77.453 ;
     RECT  54.936 77.359 87.318 77.557 ;
     RECT  2.415 76.847 54.162 77.755 ;
     RECT  54.9 77.557 87.318 77.755 ;
     RECT  2.415 77.755 87.318 77.947 ;
     RECT  2.412 77.947 87.318 78.241 ;
     RECT  2.412 78.241 87.462 78.475 ;
     RECT  2.304 78.475 87.462 78.989 ;
     RECT  10.152 78.989 87.462 79.213 ;
     RECT  10.152 79.213 87.714 79.229 ;
     RECT  2.304 78.989 9.378 79.475 ;
     RECT  2.415 79.475 9.378 79.789 ;
     RECT  10.152 79.229 53.334 79.789 ;
     RECT  0.144 79.483 0.162 79.805 ;
     RECT  54.144 79.229 87.714 79.853 ;
     RECT  2.415 79.789 53.334 80.131 ;
     RECT  54.144 79.853 64.638 80.131 ;
     RECT  2.415 80.131 64.638 80.381 ;
     RECT  65.664 79.853 87.714 80.635 ;
     RECT  65.628 80.635 87.714 80.779 ;
     RECT  43.092 80.381 64.638 80.797 ;
     RECT  65.484 80.779 87.714 80.797 ;
     RECT  43.092 80.797 87.714 80.825 ;
     RECT  54.144 80.825 87.714 80.833 ;
     RECT  54.144 80.833 87.75 80.905 ;
     RECT  2.415 80.381 42.354 80.933 ;
     RECT  54.144 80.905 88.002 81.239 ;
     RECT  37.476 80.933 42.354 81.373 ;
     RECT  43.092 80.825 53.406 81.373 ;
     RECT  66.924 81.239 88.002 81.599 ;
     RECT  37.476 81.373 53.406 81.751 ;
     RECT  54.144 81.239 66.186 81.751 ;
     RECT  2.415 80.933 36.63 81.917 ;
     RECT  37.476 81.751 66.186 82.111 ;
     RECT  66.924 81.599 74.682 82.111 ;
     RECT  37.476 82.111 74.682 82.255 ;
     RECT  26.892 81.917 36.63 82.291 ;
     RECT  37.404 82.255 74.682 82.291 ;
     RECT  75.528 81.599 88.002 82.319 ;
     RECT  75.528 82.319 87.93 82.409 ;
     RECT  26.892 82.291 74.682 82.453 ;
     RECT  75.528 82.409 86.994 82.453 ;
     RECT  2.415 81.917 26.154 82.553 ;
     RECT  3.564 82.553 26.154 82.637 ;
     RECT  3.672 82.637 26.154 82.651 ;
     RECT  26.892 82.453 86.994 82.651 ;
     RECT  3.672 82.651 86.994 82.949 ;
     RECT  87.768 82.409 87.93 82.949 ;
     RECT  3.816 82.949 86.994 82.985 ;
     RECT  87.768 82.949 87.786 82.985 ;
     RECT  3.816 82.985 86.778 83.057 ;
     RECT  3.816 83.057 86.742 83.219 ;
     RECT  3.816 83.219 86.094 83.255 ;
     RECT  28.116 83.255 86.094 83.399 ;
     RECT  54.468 83.399 86.094 83.489 ;
     RECT  3.816 83.255 27.306 83.525 ;
     RECT  55.62 83.489 86.094 83.549 ;
     RECT  65.412 83.549 86.094 83.561 ;
     RECT  20.556 83.525 27.306 83.597 ;
     RECT  20.556 83.597 27.162 83.633 ;
     RECT  55.62 83.549 64.638 83.633 ;
     RECT  28.116 83.399 53.622 83.669 ;
     RECT  54.468 83.489 54.882 83.669 ;
     RECT  3.816 83.525 19.746 83.693 ;
     RECT  3.816 83.693 17.514 83.759 ;
     RECT  18.252 83.693 19.746 83.759 ;
     RECT  28.116 83.669 46.818 83.759 ;
     RECT  47.556 83.669 53.622 83.759 ;
     RECT  54.468 83.669 54.774 83.759 ;
     RECT  55.62 83.633 58.086 83.759 ;
     RECT  59.148 83.633 64.638 83.759 ;
     RECT  65.412 83.561 72.954 83.759 ;
     RECT  73.692 83.561 86.094 83.759 ;
     RECT  18.252 83.759 19.602 83.789 ;
     RECT  52.848 83.759 53.622 83.789 ;
     RECT  3.816 83.759 14.49 83.795 ;
     RECT  15.48 83.759 15.75 83.795 ;
     RECT  16.632 83.759 17.514 83.795 ;
     RECT  18.615 83.789 19.602 83.795 ;
     RECT  20.556 83.633 27.018 83.795 ;
     RECT  28.98 83.759 46.818 83.795 ;
     RECT  52.848 83.789 52.866 83.795 ;
     RECT  54.468 83.759 54.702 83.795 ;
     RECT  59.328 83.759 64.638 83.795 ;
     RECT  65.412 83.759 72.918 83.795 ;
     RECT  76.248 83.759 85.446 83.795 ;
     RECT  70.02 83.795 72.897 83.837 ;
     RECT  78.015 83.795 85.446 83.84 ;
     RECT  16.992 83.795 17.514 83.867 ;
     RECT  55.836 83.759 57.906 83.867 ;
     RECT  70.128 83.837 72.897 83.867 ;
     RECT  3.888 83.795 14.49 83.903 ;
     RECT  59.328 83.795 60.102 83.903 ;
     RECT  60.984 83.795 64.638 83.903 ;
     RECT  65.412 83.795 69.066 83.903 ;
     RECT  70.128 83.867 71.334 83.903 ;
     RECT  73.692 83.759 75.51 83.903 ;
     RECT  70.128 83.903 70.866 83.905 ;
     RECT  3.888 83.903 13.95 83.939 ;
     RECT  47.844 83.759 52.002 83.939 ;
     RECT  57.888 83.867 57.906 83.939 ;
     RECT  60.012 83.903 60.102 83.939 ;
     RECT  65.556 83.903 68.922 83.939 ;
     RECT  72.18 83.867 72.897 83.939 ;
     RECT  85.176 83.84 85.446 83.939 ;
     RECT  2.415 82.553 2.697 83.987 ;
     RECT  3.888 83.939 13.497 83.987 ;
     RECT  18.615 83.795 18.897 83.987 ;
     RECT  61.56 83.903 62.097 83.987 ;
     RECT  65.556 83.939 68.778 83.987 ;
     RECT  72.615 83.939 72.897 83.987 ;
     RECT  3.888 83.987 13.305 84.029 ;
     RECT  17.496 83.867 17.514 84.029 ;
     RECT  21.96 83.795 27.018 84.029 ;
     RECT  28.98 83.795 33.894 84.029 ;
     RECT  34.668 83.795 36.558 84.029 ;
     RECT  37.62 83.795 46.818 84.029 ;
     RECT  47.844 83.939 51.894 84.029 ;
     RECT  55.836 83.867 56.934 84.029 ;
     RECT  60.012 83.939 60.03 84.029 ;
     RECT  61.56 83.987 61.938 84.029 ;
     RECT  63.216 83.903 64.638 84.029 ;
     RECT  68.184 83.987 68.778 84.029 ;
     RECT  70.164 83.905 70.866 84.029 ;
     RECT  73.908 83.903 74.106 84.029 ;
     RECT  76.464 83.795 77.238 84.029 ;
     RECT  78.015 83.84 83.97 84.029 ;
     RECT  85.428 83.939 85.446 84.029 ;
     RECT  80.244 84.029 82.422 84.035 ;
     RECT  3.888 84.029 5.958 84.065 ;
     RECT  6.876 84.029 11.718 84.065 ;
     RECT  12.888 84.029 13.305 84.065 ;
     RECT  25.956 84.029 26.91 84.065 ;
     RECT  31.068 84.029 32.13 84.065 ;
     RECT  33.732 84.029 33.75 84.065 ;
     RECT  34.704 84.029 35.622 84.065 ;
     RECT  41.4 84.029 43.362 84.065 ;
     RECT  44.136 84.029 46.818 84.065 ;
     RECT  48.132 84.029 48.222 84.065 ;
     RECT  49.068 84.029 49.41 84.065 ;
     RECT  64.008 84.029 64.638 84.065 ;
     RECT  65.556 83.987 67.374 84.065 ;
     RECT  70.848 84.029 70.866 84.065 ;
     RECT  75.06 83.903 75.51 84.065 ;
     RECT  77.148 84.029 77.166 84.065 ;
     RECT  78.015 84.029 79.038 84.065 ;
     RECT  80.928 84.035 82.422 84.065 ;
     RECT  20.556 83.795 20.898 84.077 ;
     RECT  21.96 84.029 21.978 84.077 ;
     RECT  22.788 84.029 23.058 84.077 ;
     RECT  24.012 84.029 25.11 84.101 ;
     RECT  28.98 84.029 30.222 84.101 ;
     RECT  48.204 84.065 48.222 84.101 ;
     RECT  64.008 84.065 64.422 84.101 ;
     RECT  65.556 84.065 65.574 84.101 ;
     RECT  78.015 84.065 78.786 84.101 ;
     RECT  81 84.065 81.018 84.101 ;
     RECT  81.792 84.065 82.098 84.101 ;
     RECT  5.58 84.065 5.598 84.137 ;
     RECT  24.012 84.101 24.462 84.137 ;
     RECT  26.784 84.065 26.91 84.137 ;
     RECT  28.98 84.101 29.934 84.137 ;
     RECT  63.216 84.029 63.234 84.137 ;
     RECT  11.412 84.065 11.718 84.173 ;
     RECT  15.732 83.795 15.75 84.173 ;
     RECT  38.628 84.029 40.374 84.173 ;
     RECT  41.616 84.065 42.138 84.173 ;
     RECT  44.784 84.065 46.818 84.173 ;
     RECT  50.256 84.029 51.714 84.173 ;
     RECT  53.604 83.789 53.622 84.173 ;
     RECT  7.2 84.065 8.73 84.209 ;
     RECT  11.412 84.173 11.43 84.209 ;
     RECT  18.615 83.987 18.81 84.209 ;
     RECT  24.015 84.137 24.462 84.209 ;
     RECT  26.784 84.137 26.874 84.209 ;
     RECT  29.34 84.137 29.505 84.209 ;
     RECT  31.788 84.065 32.13 84.209 ;
     RECT  37.692 84.029 37.71 84.209 ;
     RECT  38.628 84.173 38.79 84.209 ;
     RECT  46.512 84.173 46.818 84.209 ;
     RECT  50.508 84.173 51.174 84.209 ;
     RECT  64.224 84.101 64.422 84.209 ;
     RECT  83.415 84.029 83.97 84.209 ;
     RECT  2.415 83.987 2.505 84.257 ;
     RECT  7.815 84.209 7.905 84.257 ;
     RECT  13.068 84.065 13.305 84.257 ;
     RECT  18.615 84.209 18.705 84.257 ;
     RECT  24.015 84.209 24.105 84.257 ;
     RECT  29.415 84.209 29.505 84.257 ;
     RECT  34.704 84.065 34.905 84.257 ;
     RECT  44.784 84.173 45.705 84.257 ;
     RECT  50.508 84.209 51.105 84.257 ;
     RECT  56.415 84.029 56.505 84.257 ;
     RECT  61.815 84.029 61.905 84.257 ;
     RECT  66.42 84.065 67.305 84.257 ;
     RECT  72.615 83.987 72.705 84.257 ;
     RECT  78.015 84.101 78.105 84.257 ;
     RECT  83.415 84.209 83.505 84.257 ;
     RECT  10.008 84.065 10.026 84.299 ;
     RECT  13.068 84.257 13.086 84.299 ;
     RECT  22.824 84.077 22.842 84.299 ;
     RECT  32.112 84.209 32.13 84.299 ;
     RECT  34.704 84.257 34.794 84.299 ;
     RECT  39.672 84.173 40.374 84.299 ;
     RECT  43.344 84.065 43.362 84.299 ;
     RECT  46.692 84.209 46.818 84.299 ;
     RECT  53.964 84.181 53.982 84.299 ;
     RECT  64.224 84.209 64.242 84.299 ;
     RECT  66.42 84.257 66.798 84.299 ;
     RECT  75.06 84.065 75.078 84.299 ;
     RECT  81.792 84.101 81.81 84.299 ;
     RECT  46.8 84.299 46.818 84.335 ;
     RECT  50.508 84.257 50.634 84.335 ;
     RECT  66.42 84.299 66.438 84.335 ;
     RECT  73.908 84.029 73.926 84.335 ;
     RECT  26.784 84.209 26.802 84.371 ;
     RECT  34.704 84.299 34.722 84.371 ;
     RECT  38.772 84.209 38.79 84.371 ;
     RECT  44.784 84.257 45.054 84.371 ;
     RECT  50.616 84.335 50.634 84.371 ;
    LAYER M4 ;
     RECT  0.084 6.576 0.173 6.6 ;
     RECT  0.06 6.6 0.173 6.864 ;
     RECT  0.084 6.864 0.173 6.888 ;
     RECT  0.06 6.888 0.173 7.104 ;
     RECT  0.084 7.104 0.173 7.128 ;
     RECT  0.06 7.128 0.173 7.392 ;
     RECT  0.084 7.392 0.173 7.416 ;
     RECT  0.06 7.416 0.173 7.632 ;
     RECT  0.084 7.632 0.173 7.656 ;
     RECT  0.06 7.656 0.173 7.92 ;
     RECT  0.084 7.92 0.173 7.944 ;
     RECT  0.06 7.944 0.173 8.16 ;
     RECT  0.084 8.16 0.173 8.184 ;
     RECT  0.06 8.184 0.173 8.448 ;
     RECT  0.084 8.448 0.173 8.472 ;
     RECT  0.06 8.472 0.173 8.688 ;
     RECT  0.084 8.688 0.173 8.712 ;
     RECT  0.06 8.712 0.173 8.976 ;
     RECT  0.084 8.976 0.173 9 ;
     RECT  0.06 9 0.173 9.216 ;
     RECT  0.084 9.216 0.173 9.24 ;
     RECT  0.06 9.24 0.173 9.504 ;
     RECT  0.084 9.504 0.173 9.528 ;
     RECT  0.06 9.528 0.173 9.744 ;
     RECT  0.084 9.744 0.173 9.768 ;
     RECT  0.06 9.768 0.173 10.032 ;
     RECT  0.084 10.032 0.173 10.056 ;
     RECT  0.06 10.056 0.173 10.272 ;
     RECT  0.084 10.272 0.173 10.296 ;
     RECT  0.06 10.296 0.173 10.512 ;
     RECT  0.084 10.512 0.173 10.536 ;
     RECT  0.06 10.536 0.173 10.8 ;
     RECT  0.084 10.8 0.173 10.824 ;
     RECT  0.06 10.824 0.173 11.04 ;
     RECT  0.084 11.04 0.173 11.064 ;
     RECT  0.06 11.064 0.173 11.328 ;
     RECT  0.084 11.328 0.173 11.352 ;
     RECT  0.06 11.352 0.173 11.568 ;
     RECT  0.084 11.568 0.173 11.592 ;
     RECT  0.06 11.592 0.173 11.856 ;
     RECT  0.084 11.856 0.173 11.88 ;
     RECT  0.06 11.88 0.173 12.096 ;
     RECT  0.084 12.096 0.173 12.12 ;
     RECT  0.06 12.12 0.173 12.384 ;
     RECT  0.084 12.384 0.173 12.408 ;
     RECT  0.06 12.408 0.173 12.624 ;
     RECT  0.084 12.624 0.173 12.648 ;
     RECT  0.06 12.648 0.173 12.912 ;
     RECT  0.084 12.912 0.173 12.936 ;
     RECT  0.06 12.936 0.173 13.152 ;
     RECT  0.084 13.152 0.173 13.176 ;
     RECT  0.06 13.176 0.173 13.44 ;
     RECT  0.084 13.44 0.173 13.464 ;
     RECT  0.06 13.464 0.173 13.68 ;
     RECT  0.084 13.68 0.173 13.704 ;
     RECT  0.06 13.704 0.173 13.92 ;
     RECT  0.084 13.92 0.173 13.944 ;
     RECT  0.06 13.944 0.173 14.208 ;
     RECT  0.084 14.208 0.173 14.232 ;
     RECT  0.06 14.232 0.173 14.448 ;
     RECT  0.084 14.448 0.173 14.472 ;
     RECT  0.06 14.472 0.173 14.736 ;
     RECT  0.084 14.736 0.173 14.76 ;
     RECT  0.06 14.76 0.173 14.976 ;
     RECT  0.084 14.976 0.173 15 ;
     RECT  0.06 15 0.173 15.264 ;
     RECT  0.084 15.264 0.173 15.288 ;
     RECT  0.06 15.288 0.173 15.504 ;
     RECT  0.084 15.504 0.173 15.528 ;
     RECT  0.06 15.528 0.173 15.792 ;
     RECT  0.084 15.792 0.173 15.816 ;
     RECT  0.06 15.816 0.173 16.032 ;
     RECT  0.084 16.032 0.173 16.056 ;
     RECT  0.06 16.056 0.173 16.32 ;
     RECT  0.084 16.32 0.173 16.344 ;
     RECT  0.06 16.344 0.173 16.56 ;
     RECT  0.084 16.56 0.173 16.584 ;
     RECT  0.06 16.584 0.173 16.848 ;
     RECT  0.084 16.848 0.173 16.872 ;
     RECT  0.06 16.872 0.173 17.088 ;
     RECT  0.084 17.088 0.173 17.112 ;
     RECT  0.06 17.112 0.173 17.376 ;
     RECT  0.084 17.376 0.173 17.4 ;
     RECT  0.06 17.4 0.173 17.616 ;
     RECT  0.084 17.616 0.173 17.64 ;
     RECT  0.06 17.64 0.173 17.856 ;
     RECT  0.084 17.856 0.173 17.88 ;
     RECT  0.06 17.88 0.173 18.144 ;
     RECT  0.084 18.144 0.173 18.168 ;
     RECT  0.06 18.168 0.173 18.384 ;
     RECT  0.084 18.384 0.173 18.408 ;
     RECT  0.06 18.408 0.173 18.672 ;
     RECT  0.084 18.672 0.173 18.696 ;
     RECT  0.06 18.696 0.173 18.912 ;
     RECT  0.084 18.912 0.173 18.936 ;
     RECT  0.06 18.936 0.173 19.2 ;
     RECT  0.084 19.2 0.173 19.224 ;
     RECT  0.06 19.224 0.173 19.44 ;
     RECT  0.084 19.44 0.173 19.464 ;
     RECT  0.06 19.464 0.173 19.728 ;
     RECT  0.084 19.728 0.173 19.752 ;
     RECT  0.06 19.752 0.173 19.968 ;
     RECT  0.084 19.968 0.173 19.992 ;
     RECT  0.06 19.992 0.173 20.256 ;
     RECT  0.084 20.256 0.173 20.28 ;
     RECT  0.06 20.28 0.173 20.496 ;
     RECT  0.084 20.496 0.173 20.52 ;
     RECT  0.06 20.52 0.173 20.784 ;
     RECT  0.084 20.784 0.173 20.808 ;
     RECT  0.06 20.808 0.173 21.024 ;
     RECT  0.084 21.024 0.173 21.048 ;
     RECT  0.06 21.048 0.173 21.264 ;
     RECT  0.084 21.264 0.173 21.288 ;
     RECT  0.06 21.288 0.173 21.552 ;
     RECT  0.084 21.552 0.173 21.576 ;
     RECT  0.06 21.576 0.173 21.792 ;
     RECT  0.084 21.792 0.173 21.816 ;
     RECT  0.06 21.816 0.173 22.08 ;
     RECT  0.084 22.08 0.173 22.104 ;
     RECT  0.06 22.104 0.173 22.32 ;
     RECT  0.084 22.32 0.173 22.344 ;
     RECT  0.06 22.344 0.173 22.608 ;
     RECT  0.084 22.608 0.173 22.632 ;
     RECT  0.06 22.632 0.173 22.848 ;
     RECT  0.084 22.848 0.173 22.872 ;
     RECT  0.06 22.872 0.173 23.136 ;
     RECT  0.084 23.136 0.173 23.16 ;
     RECT  0.06 23.16 0.173 23.376 ;
     RECT  0.084 23.376 0.173 23.4 ;
     RECT  0.06 23.4 0.173 23.664 ;
     RECT  0.084 23.664 0.173 23.688 ;
     RECT  0.06 23.688 0.173 23.904 ;
     RECT  0.084 23.904 0.173 23.928 ;
     RECT  0.06 23.928 0.173 24.192 ;
     RECT  0.084 24.192 0.173 24.216 ;
     RECT  0.06 24.216 0.173 24.432 ;
     RECT  0.084 24.432 0.173 24.456 ;
     RECT  0.06 24.456 0.173 24.72 ;
     RECT  0.084 24.72 0.173 24.744 ;
     RECT  0.06 24.744 0.173 24.96 ;
     RECT  0.084 24.96 0.173 24.984 ;
     RECT  0.06 24.984 0.173 25.2 ;
     RECT  0.084 25.2 0.173 25.224 ;
     RECT  0.06 25.224 0.173 25.488 ;
     RECT  0.084 25.488 0.173 25.512 ;
     RECT  0.06 25.512 0.173 25.728 ;
     RECT  0.084 25.728 0.173 25.752 ;
     RECT  0.06 25.752 0.173 26.016 ;
     RECT  0.084 26.016 0.173 26.04 ;
     RECT  0.06 26.04 0.173 26.256 ;
     RECT  0.084 26.256 0.173 26.28 ;
     RECT  0.06 26.28 0.173 26.544 ;
     RECT  0.084 26.544 0.173 26.568 ;
     RECT  0.06 26.568 0.173 26.784 ;
     RECT  0.084 26.784 0.173 26.808 ;
     RECT  0.06 26.808 0.173 27.072 ;
     RECT  0.084 27.072 0.173 27.096 ;
     RECT  0.06 27.096 0.173 27.312 ;
     RECT  0.084 27.312 0.173 27.336 ;
     RECT  0.06 27.336 0.173 27.6 ;
     RECT  0.084 27.6 0.173 27.624 ;
     RECT  0.06 27.624 0.173 27.84 ;
     RECT  0.084 27.84 0.173 27.864 ;
     RECT  0.06 27.864 0.173 28.128 ;
     RECT  0.084 28.128 0.173 28.152 ;
     RECT  0.06 28.152 0.173 28.368 ;
     RECT  0.084 28.368 0.173 28.392 ;
     RECT  0.06 28.392 0.173 28.608 ;
     RECT  0.084 28.608 0.173 28.632 ;
     RECT  0.06 28.632 0.173 28.896 ;
     RECT  0.084 28.896 0.173 28.92 ;
     RECT  0.06 28.92 0.173 29.136 ;
     RECT  0.084 29.136 0.173 29.16 ;
     RECT  0.06 29.16 0.173 29.424 ;
     RECT  0.084 29.424 0.173 29.448 ;
     RECT  0.06 29.448 0.173 29.664 ;
     RECT  0.084 29.664 0.173 29.688 ;
     RECT  0.06 29.688 0.173 29.952 ;
     RECT  0.084 29.952 0.173 29.976 ;
     RECT  0.06 29.976 0.173 30.192 ;
     RECT  0.084 30.192 0.173 30.216 ;
     RECT  0.06 30.216 0.173 30.48 ;
     RECT  0.084 30.48 0.173 30.504 ;
     RECT  0.06 30.504 0.173 30.72 ;
     RECT  0.084 30.72 0.173 30.744 ;
     RECT  0.06 30.744 0.173 31.008 ;
     RECT  0.084 31.008 0.173 31.032 ;
     RECT  0.06 31.032 0.173 31.248 ;
     RECT  0.084 31.248 0.173 31.272 ;
     RECT  0.06 31.272 0.173 31.536 ;
     RECT  0.084 31.536 0.173 31.56 ;
     RECT  0.06 31.56 0.173 31.776 ;
     RECT  0.084 31.776 0.173 31.8 ;
     RECT  0.06 31.8 0.173 32.064 ;
     RECT  0.084 32.064 0.173 32.088 ;
     RECT  0.06 32.088 0.173 32.304 ;
     RECT  0.084 32.304 0.173 32.328 ;
     RECT  0.06 32.328 0.173 32.544 ;
     RECT  0.084 32.544 0.173 32.568 ;
     RECT  0.06 32.568 0.173 32.832 ;
     RECT  0.084 32.832 0.173 32.856 ;
     RECT  0.06 32.856 0.173 33.072 ;
     RECT  0.084 33.072 0.173 33.096 ;
     RECT  0.06 33.096 0.173 33.36 ;
     RECT  0.084 33.36 0.173 33.384 ;
     RECT  0.06 33.384 0.173 33.6 ;
     RECT  0.084 33.6 0.173 33.624 ;
     RECT  0.06 33.624 0.173 33.888 ;
     RECT  0.084 33.888 0.173 33.912 ;
     RECT  0.06 33.912 0.173 34.128 ;
     RECT  0.084 34.128 0.173 34.152 ;
     RECT  0.06 34.152 0.173 34.416 ;
     RECT  0.084 34.416 0.173 34.44 ;
     RECT  0.06 34.44 0.173 34.656 ;
     RECT  0.084 34.656 0.173 34.68 ;
     RECT  0.06 34.68 0.173 34.944 ;
     RECT  0.084 34.944 0.173 34.968 ;
     RECT  0.06 34.968 0.173 35.184 ;
     RECT  0.084 35.184 0.173 35.208 ;
     RECT  0.06 35.208 0.173 35.472 ;
     RECT  0.084 35.472 0.173 35.496 ;
     RECT  0.06 35.496 0.173 35.712 ;
     RECT  0.084 35.712 0.173 35.736 ;
     RECT  0.06 35.736 0.173 35.952 ;
     RECT  0.084 35.952 0.173 35.976 ;
     RECT  0.06 35.976 0.173 36.24 ;
     RECT  0.084 36.24 0.173 36.264 ;
     RECT  0.06 36.264 0.173 36.48 ;
     RECT  0.084 36.48 0.173 36.504 ;
     RECT  0.06 36.504 0.173 36.768 ;
     RECT  0.084 36.768 0.173 36.792 ;
     RECT  0.06 36.792 0.173 37.008 ;
     RECT  0.084 37.008 0.173 37.032 ;
     RECT  0.06 37.032 0.173 37.296 ;
     RECT  0.084 37.296 0.173 37.32 ;
     RECT  0.06 37.32 0.173 37.536 ;
     RECT  0.084 37.536 0.173 37.56 ;
     RECT  0.06 37.56 0.173 37.824 ;
     RECT  0.084 37.824 0.173 37.848 ;
     RECT  0.06 37.848 0.173 38.064 ;
     RECT  0.084 38.064 0.173 38.088 ;
     RECT  0.06 38.088 0.173 38.352 ;
     RECT  0.084 38.352 0.173 38.376 ;
     RECT  0.06 38.376 0.173 38.592 ;
     RECT  0.084 38.592 0.173 38.616 ;
     RECT  0.06 38.616 0.173 38.88 ;
     RECT  0.084 38.88 0.173 38.904 ;
     RECT  0.06 38.904 0.173 39.12 ;
     RECT  0.084 39.12 0.173 39.144 ;
     RECT  0.06 39.144 0.173 39.408 ;
     RECT  0.084 39.408 0.173 39.432 ;
     RECT  0.06 39.432 0.173 39.648 ;
     RECT  0.084 39.648 0.173 39.672 ;
     RECT  0.06 39.672 0.173 39.888 ;
     RECT  0.084 39.888 0.173 39.912 ;
     RECT  0.06 39.912 0.173 40.176 ;
     RECT  0.084 40.176 0.173 40.2 ;
     RECT  0.06 40.2 0.173 40.416 ;
     RECT  0.084 40.416 0.173 40.44 ;
     RECT  0.06 40.44 0.173 40.704 ;
     RECT  0.084 40.704 0.173 40.728 ;
     RECT  0.06 40.728 0.173 40.944 ;
     RECT  0.084 40.944 0.173 40.968 ;
     RECT  0.06 40.968 0.173 41.232 ;
     RECT  0.084 41.232 0.173 41.256 ;
     RECT  0.06 41.256 0.173 41.472 ;
     RECT  0.084 41.472 0.173 41.496 ;
     RECT  0.06 41.496 0.173 41.76 ;
     RECT  0.084 41.76 0.173 41.784 ;
     RECT  0.06 41.784 0.173 42 ;
     RECT  0.084 42 0.173 42.024 ;
     RECT  0.06 42.024 0.173 42.288 ;
     RECT  0.084 42.288 0.173 42.312 ;
     RECT  0.06 42.312 0.173 42.528 ;
     RECT  0.084 42.528 0.173 42.552 ;
     RECT  0.06 42.552 0.173 42.816 ;
     RECT  0.084 42.816 0.173 42.84 ;
     RECT  0.06 42.84 0.173 43.056 ;
     RECT  0.084 43.056 0.173 43.08 ;
     RECT  0.06 43.08 0.173 43.296 ;
     RECT  0.084 43.296 0.173 43.32 ;
     RECT  0.06 43.32 0.173 43.584 ;
     RECT  0.084 43.584 0.173 43.608 ;
     RECT  0.06 43.608 0.173 43.824 ;
     RECT  0.084 43.824 0.173 43.848 ;
     RECT  0.06 43.848 0.173 44.112 ;
     RECT  0.084 44.112 0.173 44.136 ;
     RECT  0.06 44.136 0.173 44.352 ;
     RECT  0.084 44.352 0.173 44.376 ;
     RECT  0.06 44.376 0.173 44.64 ;
     RECT  0.084 44.64 0.173 44.664 ;
     RECT  0.06 44.664 0.173 44.88 ;
     RECT  0.084 44.88 0.173 44.904 ;
     RECT  0.06 44.904 0.173 45.168 ;
     RECT  0.084 45.168 0.173 45.192 ;
     RECT  0.06 45.192 0.173 45.408 ;
     RECT  0.084 45.408 0.173 45.432 ;
     RECT  0.06 45.432 0.173 45.696 ;
     RECT  0.084 45.696 0.173 45.72 ;
     RECT  0.06 45.72 0.173 45.936 ;
     RECT  0.084 45.936 0.173 45.96 ;
     RECT  0.06 45.96 0.173 46.224 ;
     RECT  0.084 46.224 0.173 46.248 ;
     RECT  0.06 46.248 0.173 46.464 ;
     RECT  0.084 46.464 0.173 46.488 ;
     RECT  0.06 46.488 0.173 46.752 ;
     RECT  0.084 46.752 0.173 46.776 ;
     RECT  0.06 46.776 0.173 46.992 ;
     RECT  0.084 46.992 0.173 47.016 ;
     RECT  0.06 47.016 0.173 47.232 ;
     RECT  0.084 47.232 0.173 47.256 ;
     RECT  0.06 47.256 0.173 47.52 ;
     RECT  0.084 47.52 0.173 47.544 ;
     RECT  0.06 47.544 0.173 47.76 ;
     RECT  0.084 47.76 0.173 47.784 ;
     RECT  0.06 47.784 0.173 48.048 ;
     RECT  0.084 48.048 0.173 48.072 ;
     RECT  0.06 48.072 0.173 48.288 ;
     RECT  0.084 48.288 0.173 48.312 ;
     RECT  0.06 48.312 0.173 48.576 ;
     RECT  0.084 48.576 0.173 48.6 ;
     RECT  0.06 48.6 0.173 48.816 ;
     RECT  0.084 48.816 0.173 48.84 ;
     RECT  0.06 48.84 0.173 49.104 ;
     RECT  0.084 49.104 0.173 49.128 ;
     RECT  0.06 49.128 0.173 49.344 ;
     RECT  0.084 49.344 0.173 49.368 ;
     RECT  0.06 49.368 0.173 49.632 ;
     RECT  0.084 49.632 0.173 49.656 ;
     RECT  0.06 49.656 0.173 49.872 ;
     RECT  0.084 49.872 0.173 49.896 ;
     RECT  0.06 49.896 0.173 50.16 ;
     RECT  0.084 50.16 0.173 50.184 ;
     RECT  0.06 50.184 0.173 50.4 ;
     RECT  0.084 50.4 0.173 50.424 ;
     RECT  0.06 50.424 0.173 50.64 ;
     RECT  0.084 50.64 0.173 50.664 ;
     RECT  0.06 50.664 0.173 50.928 ;
     RECT  0.084 50.928 0.173 50.952 ;
     RECT  0.06 50.952 0.173 51.168 ;
     RECT  0.084 51.168 0.173 51.192 ;
     RECT  0.06 51.192 0.173 51.456 ;
     RECT  0.084 51.456 0.173 51.48 ;
     RECT  0.06 51.48 0.173 51.696 ;
     RECT  0.084 51.696 0.173 51.72 ;
     RECT  0.06 51.72 0.173 51.984 ;
     RECT  0.084 51.984 0.173 52.008 ;
     RECT  0.06 52.008 0.173 52.224 ;
     RECT  0.084 52.224 0.173 52.248 ;
     RECT  0.06 52.248 0.173 52.512 ;
     RECT  0.084 52.512 0.173 52.536 ;
     RECT  0.06 52.536 0.173 52.752 ;
     RECT  0.084 52.752 0.173 52.776 ;
     RECT  0.06 52.776 0.173 53.04 ;
     RECT  0.084 53.04 0.173 53.064 ;
     RECT  0.06 53.064 0.173 53.28 ;
     RECT  0.084 53.28 0.173 53.304 ;
     RECT  0.06 53.304 0.173 53.568 ;
     RECT  0.084 53.568 0.173 53.592 ;
     RECT  0.06 53.592 0.173 53.808 ;
     RECT  0.084 53.808 0.173 53.832 ;
     RECT  0.06 53.832 0.173 54.096 ;
     RECT  0.084 54.096 0.173 54.12 ;
     RECT  0.06 54.12 0.173 54.336 ;
     RECT  0.084 54.336 0.173 54.36 ;
     RECT  0.06 54.36 0.173 54.576 ;
     RECT  0.084 54.576 0.173 54.6 ;
     RECT  0.06 54.6 0.173 54.864 ;
     RECT  0.084 54.864 0.173 54.888 ;
     RECT  0.06 54.888 0.173 55.104 ;
     RECT  0.084 55.104 0.173 55.128 ;
     RECT  0.06 55.128 0.173 55.392 ;
     RECT  0.084 55.392 0.173 55.416 ;
     RECT  0.06 55.416 0.173 55.632 ;
     RECT  0.084 55.632 0.173 55.656 ;
     RECT  0.06 55.656 0.173 55.92 ;
     RECT  0.084 55.92 0.173 55.944 ;
     RECT  0.06 55.944 0.173 56.16 ;
     RECT  0.084 56.16 0.173 56.184 ;
     RECT  0.06 56.184 0.173 56.448 ;
     RECT  0.084 56.448 0.173 56.472 ;
     RECT  0.06 56.472 0.173 56.688 ;
     RECT  0.084 56.688 0.173 56.712 ;
     RECT  0.06 56.712 0.173 56.976 ;
     RECT  0.084 56.976 0.173 57 ;
     RECT  0.06 57 0.173 57.216 ;
     RECT  0.084 57.216 0.173 57.24 ;
     RECT  0.06 57.24 0.173 57.504 ;
     RECT  0.084 57.504 0.173 57.528 ;
     RECT  0.06 57.528 0.173 57.744 ;
     RECT  0.084 57.744 0.173 57.768 ;
     RECT  0.06 57.768 0.173 57.984 ;
     RECT  0.084 57.984 0.173 58.008 ;
     RECT  0.06 58.008 0.173 58.272 ;
     RECT  0.084 58.272 0.173 58.296 ;
     RECT  0.06 58.296 0.173 58.512 ;
     RECT  0.084 58.512 0.173 58.536 ;
     RECT  0.06 58.536 0.173 58.8 ;
     RECT  0.084 58.8 0.173 58.824 ;
     RECT  0.06 58.824 0.173 59.04 ;
     RECT  0.084 59.04 0.173 59.064 ;
     RECT  0.06 59.064 0.173 59.328 ;
     RECT  0.084 59.328 0.173 59.352 ;
     RECT  0.06 59.352 0.173 59.568 ;
     RECT  0.084 59.568 0.173 59.592 ;
     RECT  0.06 59.592 0.173 59.856 ;
     RECT  0.084 59.856 0.173 59.88 ;
     RECT  0.06 59.88 0.173 60.096 ;
     RECT  0.084 60.096 0.173 60.12 ;
     RECT  0.06 60.12 0.173 60.384 ;
     RECT  0.084 60.384 0.173 60.408 ;
     RECT  0.06 60.408 0.173 60.624 ;
     RECT  0.084 60.624 0.173 60.648 ;
     RECT  0.06 60.648 0.173 60.912 ;
     RECT  0.084 60.912 0.173 60.936 ;
     RECT  0.06 60.936 0.173 61.152 ;
     RECT  0.084 61.152 0.173 61.176 ;
     RECT  0.06 61.176 0.173 61.44 ;
     RECT  0.084 61.44 0.173 61.464 ;
     RECT  0.06 61.464 0.173 61.68 ;
     RECT  0.084 61.68 0.173 61.704 ;
     RECT  0.06 61.704 0.173 61.92 ;
     RECT  0.084 61.92 0.173 61.944 ;
     RECT  0.06 61.944 0.173 62.208 ;
     RECT  0.084 62.208 0.173 62.232 ;
     RECT  0.06 62.232 0.173 62.448 ;
     RECT  0.084 62.448 0.173 62.472 ;
     RECT  0.06 62.472 0.173 62.736 ;
     RECT  0.084 62.736 0.173 62.76 ;
     RECT  0.06 62.76 0.173 62.976 ;
     RECT  0.084 62.976 0.173 63 ;
     RECT  0.06 63 0.173 63.264 ;
     RECT  0.084 63.264 0.173 63.288 ;
     RECT  0.06 63.288 0.173 63.504 ;
     RECT  0.084 63.504 0.173 63.528 ;
     RECT  0.06 63.528 0.173 63.792 ;
     RECT  0.084 63.792 0.173 63.816 ;
     RECT  0.06 63.816 0.173 64.032 ;
     RECT  0.084 64.032 0.173 64.056 ;
     RECT  0.06 64.056 0.173 64.32 ;
     RECT  0.084 64.32 0.173 64.344 ;
     RECT  0.06 64.344 0.173 64.56 ;
     RECT  0.084 64.56 0.173 64.584 ;
     RECT  0.06 64.584 0.173 64.848 ;
     RECT  0.084 64.848 0.173 64.872 ;
     RECT  0.06 64.872 0.173 65.088 ;
     RECT  0.084 65.088 0.173 65.112 ;
     RECT  0.06 65.112 0.173 65.328 ;
     RECT  0.084 65.328 0.173 65.352 ;
     RECT  0.06 65.352 0.173 65.616 ;
     RECT  0.084 65.616 0.173 65.64 ;
     RECT  0.06 65.64 0.173 65.856 ;
     RECT  0.084 65.856 0.173 65.88 ;
     RECT  0.06 65.88 0.173 66.144 ;
     RECT  0.084 66.144 0.173 66.168 ;
     RECT  0.06 66.168 0.173 66.384 ;
     RECT  0.084 66.384 0.173 66.408 ;
     RECT  0.06 66.408 0.173 66.672 ;
     RECT  0.084 66.672 0.173 66.696 ;
     RECT  0.06 66.696 0.173 66.912 ;
     RECT  0.084 66.912 0.173 66.936 ;
     RECT  0.06 66.936 0.173 67.2 ;
     RECT  0.084 67.2 0.173 67.224 ;
     RECT  0.06 67.224 0.173 67.44 ;
     RECT  0.084 67.44 0.173 67.464 ;
     RECT  0.06 67.464 0.173 67.728 ;
     RECT  0.084 67.728 0.173 67.752 ;
     RECT  0.06 67.752 0.173 67.968 ;
     RECT  0.084 67.968 0.173 67.992 ;
     RECT  0.06 67.992 0.173 68.256 ;
     RECT  0.084 68.256 0.173 68.28 ;
     RECT  0.06 68.28 0.173 68.496 ;
     RECT  0.084 68.496 0.173 68.52 ;
     RECT  0.06 68.52 0.173 68.784 ;
     RECT  0.084 68.784 0.173 68.808 ;
     RECT  0.06 68.808 0.173 69.024 ;
     RECT  0.084 69.024 0.173 69.048 ;
     RECT  0.06 69.048 0.173 69.264 ;
     RECT  0.084 69.264 0.173 69.288 ;
     RECT  0.06 69.288 0.173 69.552 ;
     RECT  0.084 69.552 0.173 69.576 ;
     RECT  0.06 69.576 0.173 69.792 ;
     RECT  0.084 69.792 0.173 69.816 ;
     RECT  0.06 69.816 0.173 70.08 ;
     RECT  0.084 70.08 0.173 70.104 ;
     RECT  0.06 70.104 0.173 70.32 ;
     RECT  0.084 70.32 0.173 70.344 ;
     RECT  0.06 70.344 0.173 70.608 ;
     RECT  0.084 70.608 0.173 70.632 ;
     RECT  0.06 70.632 0.173 70.848 ;
     RECT  0.084 70.848 0.173 70.872 ;
     RECT  0.06 70.872 0.173 71.136 ;
     RECT  0.084 71.136 0.173 71.16 ;
     RECT  0.06 71.16 0.173 71.376 ;
     RECT  0.084 71.376 0.173 71.4 ;
     RECT  0.06 71.4 0.173 71.664 ;
     RECT  0.084 71.664 0.173 71.688 ;
     RECT  0.06 71.688 0.173 71.904 ;
     RECT  0.084 71.904 0.173 71.928 ;
     RECT  0.06 71.928 0.173 72.192 ;
     RECT  0.084 72.192 0.173 72.216 ;
     RECT  0.06 72.216 0.173 72.432 ;
     RECT  0.084 72.432 0.173 72.456 ;
     RECT  0.06 72.456 0.173 72.672 ;
     RECT  0.084 72.672 0.173 72.696 ;
     RECT  0.06 72.696 0.173 72.96 ;
     RECT  0.084 72.96 0.173 72.984 ;
     RECT  0.06 72.984 0.173 73.2 ;
     RECT  0.084 73.2 0.173 73.224 ;
     RECT  0.06 73.224 0.173 73.488 ;
     RECT  0.084 73.488 0.173 73.512 ;
     RECT  0.06 73.512 0.173 73.728 ;
     RECT  0.084 73.728 0.173 73.752 ;
     RECT  0.06 73.752 0.173 74.016 ;
     RECT  0.084 74.016 0.173 74.04 ;
     RECT  0.06 74.04 0.173 74.256 ;
     RECT  0.084 74.256 0.173 74.28 ;
     RECT  0.06 74.28 0.173 74.544 ;
     RECT  0.084 74.544 0.173 74.568 ;
     RECT  0.06 74.568 0.173 74.784 ;
     RECT  0.084 74.784 0.173 74.808 ;
     RECT  0.06 74.808 0.173 75.072 ;
     RECT  0.084 75.072 0.173 75.096 ;
     RECT  0.06 75.096 0.173 75.312 ;
     RECT  0.084 75.312 0.173 75.336 ;
     RECT  0.06 75.336 0.173 75.6 ;
     RECT  0.084 75.6 0.173 75.624 ;
     RECT  0.06 75.624 0.173 75.84 ;
     RECT  0.084 75.84 0.173 75.864 ;
     RECT  0.06 75.864 0.173 76.128 ;
     RECT  0.084 76.128 0.173 76.152 ;
     RECT  0.06 76.152 0.173 76.368 ;
     RECT  0.084 76.368 0.173 76.392 ;
     RECT  0.06 76.392 0.173 76.608 ;
     RECT  0.084 76.608 0.173 76.632 ;
     RECT  0.06 76.632 0.173 76.896 ;
     RECT  0.084 76.896 0.173 76.92 ;
     RECT  0.06 76.92 0.173 77.136 ;
     RECT  0.084 77.136 0.173 77.16 ;
     RECT  0.06 77.16 0.173 77.424 ;
     RECT  0.084 77.424 0.173 77.448 ;
     RECT  0.06 77.448 0.173 77.664 ;
     RECT  0.084 77.664 0.173 77.688 ;
     RECT  0.06 77.688 0.173 77.952 ;
     RECT  0.084 77.952 0.173 77.976 ;
     RECT  0.06 77.976 0.173 78.192 ;
     RECT  0.084 78.192 0.173 78.216 ;
     RECT  0.06 78.216 0.173 78.48 ;
     RECT  0.084 78.48 0.173 78.504 ;
     RECT  0.06 78.504 0.173 78.72 ;
     RECT  0.084 78.72 0.173 78.744 ;
     RECT  0.06 78.744 0.173 79.008 ;
     RECT  0.084 79.008 0.173 79.032 ;
     RECT  0.06 79.032 0.173 79.248 ;
     RECT  0.084 79.248 0.173 79.272 ;
     RECT  0.06 79.272 0.173 79.536 ;
     RECT  0.084 79.536 0.173 79.56 ;
     RECT  0.06 79.56 0.173 79.776 ;
     RECT  0.084 79.776 0.173 79.8 ;
     RECT  0.173 6.576 2.408 79.512 ;
     RECT  2.408 2.148 2.512 84.252 ;
     RECT  2.512 2.418 2.704 83.982 ;
     RECT  2.704 13.152 2.801 13.176 ;
     RECT  2.704 11.76 3.089 11.976 ;
     RECT  2.704 14.208 3.197 23.88 ;
     RECT  2.704 50.496 3.197 65.4 ;
     RECT  3.197 50.496 3.233 54.888 ;
     RECT  3.233 54.144 3.269 54.888 ;
     RECT  2.704 25.296 3.305 42.792 ;
     RECT  3.197 55.968 3.305 65.4 ;
     RECT  3.305 56.112 3.413 65.4 ;
     RECT  2.704 5.424 3.521 10.056 ;
     RECT  3.233 50.496 3.539 53.064 ;
     RECT  2.704 66.672 3.593 79.992 ;
     RECT  3.305 27.312 3.697 42.792 ;
     RECT  2.704 44.448 3.697 48.984 ;
     RECT  3.539 50.496 3.697 52.536 ;
     RECT  3.413 62.112 3.809 65.4 ;
     RECT  3.521 5.424 3.845 8.376 ;
     RECT  3.697 27.312 3.881 48.984 ;
     RECT  3.521 9.792 3.953 10.056 ;
     RECT  3.197 14.64 3.985 23.88 ;
     RECT  3.809 62.544 4.021 65.4 ;
     RECT  4.021 62.544 4.025 65.592 ;
     RECT  3.845 5.76 4.097 8.376 ;
     RECT  3.593 66.672 4.097 79.8 ;
     RECT  4.097 66.672 4.105 79.272 ;
     RECT  3.413 56.112 4.141 60.984 ;
     RECT  3.089 11.76 4.169 11.784 ;
     RECT  4.141 60.96 4.205 60.984 ;
     RECT  3.269 54.144 4.268 54.696 ;
     RECT  3.481 2.256 4.309 2.28 ;
     RECT  2.704 82.608 4.381 82.632 ;
     RECT  4.309 2.256 4.417 2.952 ;
     RECT  2.704 3.936 4.417 4.008 ;
     RECT  3.985 14.64 4.417 23.928 ;
     RECT  3.305 25.296 4.417 26.136 ;
     RECT  3.697 50.448 4.453 52.536 ;
     RECT  4.025 63.744 4.453 65.592 ;
     RECT  4.105 66.672 4.453 75.384 ;
     RECT  4.105 76.368 4.529 79.272 ;
     RECT  3.881 27.312 4.565 39 ;
     RECT  4.097 6.144 4.601 8.376 ;
     RECT  4.453 50.352 4.633 52.536 ;
     RECT  4.268 53.52 4.633 54.696 ;
     RECT  3.877 81.216 4.637 81.24 ;
     RECT  4.381 82.608 4.637 83.208 ;
     RECT  4.601 6.144 4.673 7.08 ;
     RECT  3.769 13.248 4.673 13.272 ;
     RECT  4.529 76.368 4.781 78.936 ;
     RECT  3.881 40.032 4.817 48.984 ;
     RECT  4.453 63.744 4.817 75.384 ;
     RECT  4.417 2.256 4.925 4.008 ;
     RECT  4.025 62.544 4.993 62.76 ;
     RECT  4.817 63.744 4.993 74.136 ;
     RECT  4.633 50.352 5.101 54.696 ;
     RECT  5.137 60.864 5.245 60.888 ;
     RECT  4.849 12.528 5.281 12.552 ;
     RECT  4.417 14.64 5.281 26.136 ;
     RECT  4.565 27.792 5.281 39 ;
     RECT  4.817 40.032 5.281 48.456 ;
     RECT  4.673 6.144 5.317 6.984 ;
     RECT  5.281 11.808 5.317 12.552 ;
     RECT  4.993 62.544 5.321 74.136 ;
     RECT  5.245 60.864 5.329 61.032 ;
     RECT  5.321 62.544 5.353 67.8 ;
     RECT  5.281 14.64 5.393 26.232 ;
     RECT  5.389 4.8 5.42 4.824 ;
     RECT  5.317 5.952 5.42 6.984 ;
     RECT  4.925 2.256 5.507 2.952 ;
     RECT  5.42 4.8 5.507 6.984 ;
     RECT  4.817 75.36 5.653 75.384 ;
     RECT  4.781 76.368 5.653 78.552 ;
     RECT  5.281 27.792 5.681 48.456 ;
     RECT  5.101 50.064 5.681 54.696 ;
     RECT  5.353 62.16 5.681 67.8 ;
     RECT  5.681 29.568 5.699 48.456 ;
     RECT  5.321 68.784 5.717 74.136 ;
     RECT  5.699 40.032 5.725 48.456 ;
     RECT  5.317 11.376 5.753 12.552 ;
     RECT  5.653 75.36 5.804 78.552 ;
     RECT  4.141 56.112 5.821 59.88 ;
     RECT  5.699 29.568 5.825 38.664 ;
     RECT  5.681 62.16 5.857 64.872 ;
     RECT  5.804 75.12 5.857 78.552 ;
     RECT  5.507 5.952 5.861 6.984 ;
     RECT  5.825 29.712 5.861 38.664 ;
     RECT  5.507 2.496 5.893 2.952 ;
     RECT  5.681 52.272 5.897 54.696 ;
     RECT  4.601 8.352 5.933 8.376 ;
     RECT  5.821 55.92 5.965 59.88 ;
     RECT  5.329 60.864 5.965 60.984 ;
     RECT  5.717 74.112 5.965 74.136 ;
     RECT  5.857 75.12 5.965 79.32 ;
     RECT  5.897 52.32 5.996 54.696 ;
     RECT  5.965 55.92 5.996 60.984 ;
     RECT  5.861 30.144 6.005 38.664 ;
     RECT  5.857 62.112 6.005 64.872 ;
     RECT  5.101 83.76 6.037 83.784 ;
     RECT  5.996 52.32 6.083 60.984 ;
     RECT  5.101 81.84 6.109 81.864 ;
     RECT  6.037 83.616 6.109 83.784 ;
     RECT  6.005 30.144 6.113 38.088 ;
     RECT  5.725 40.032 6.113 41.256 ;
     RECT  5.393 17.52 6.179 26.232 ;
     RECT  6.179 17.568 6.257 26.232 ;
     RECT  5.965 74.112 6.289 79.32 ;
     RECT  6.289 74.112 6.293 79.848 ;
     RECT  6.257 18.528 6.361 26.232 ;
     RECT  6.083 55.92 6.397 60.984 ;
     RECT  6.005 62.112 6.397 64.392 ;
     RECT  6.293 79.776 6.397 79.848 ;
     RECT  6.109 81.264 6.397 81.864 ;
     RECT  5.393 14.64 6.437 16.44 ;
     RECT  5.893 2.496 6.505 3.624 ;
     RECT  6.505 2.256 6.545 3.624 ;
     RECT  5.681 50.064 6.545 51.288 ;
     RECT  5.507 4.8 6.581 4.824 ;
     RECT  5.681 27.792 6.581 28.488 ;
     RECT  5.681 65.952 6.649 67.8 ;
     RECT  5.717 68.784 6.649 72.792 ;
     RECT  6.361 18.528 6.725 26.76 ;
     RECT  6.725 18.768 6.761 26.76 ;
     RECT  6.397 79.776 6.803 81.864 ;
     RECT  6.113 30.144 6.829 35.88 ;
     RECT  5.753 11.808 6.901 12.552 ;
     RECT  6.437 15.072 6.901 16.44 ;
     RECT  6.545 3.36 6.908 3.624 ;
     RECT  6.685 8.976 6.973 9 ;
     RECT  3.953 10.032 6.973 10.056 ;
     RECT  6.829 30.096 6.973 35.88 ;
     RECT  6.545 50.304 7.004 51.288 ;
     RECT  6.083 52.32 7.004 54.744 ;
     RECT  5.861 5.952 7.009 6.888 ;
     RECT  7.004 50.304 7.081 54.744 ;
     RECT  6.397 55.92 7.081 64.392 ;
     RECT  6.649 65.76 7.081 72.792 ;
     RECT  6.293 74.112 7.081 78.792 ;
     RECT  6.973 30.048 7.117 35.88 ;
     RECT  5.725 42.288 7.117 48.456 ;
     RECT  6.803 80.256 7.153 81.864 ;
     RECT  6.109 83.04 7.153 83.784 ;
     RECT  6.901 15.072 7.225 16.536 ;
     RECT  7.117 29.088 7.333 35.88 ;
     RECT  6.113 37.584 7.333 38.088 ;
     RECT  7.081 50.304 7.34 64.392 ;
     RECT  7.081 65.76 7.34 78.792 ;
     RECT  6.581 27.792 7.361 27.912 ;
     RECT  6.973 8.976 7.369 10.056 ;
     RECT  7.225 15.072 7.405 17.688 ;
     RECT  6.761 19.104 7.405 26.76 ;
     RECT  7.361 27.744 7.405 27.912 ;
     RECT  6.113 40.032 7.441 41.208 ;
     RECT  6.901 11.424 7.477 12.552 ;
     RECT  7.405 14.976 7.513 17.688 ;
     RECT  6.545 2.256 7.549 2.28 ;
     RECT  6.908 3.36 7.549 4.056 ;
     RECT  7.117 42.288 7.621 49.224 ;
     RECT  7.369 8.976 7.657 10.344 ;
     RECT  7.477 11.424 7.657 13.32 ;
     RECT  7.513 14.832 7.669 17.688 ;
     RECT  7.405 19.104 7.669 27.912 ;
     RECT  7.333 29.088 7.669 38.088 ;
     RECT  7.549 2.256 7.808 4.056 ;
     RECT  7.009 5.568 7.808 6.888 ;
     RECT  7.657 8.976 7.808 13.32 ;
     RECT  7.669 14.304 7.808 17.688 ;
     RECT  7.669 19.104 7.808 38.088 ;
     RECT  7.441 39.264 7.808 41.208 ;
     RECT  7.621 42.192 7.808 49.224 ;
     RECT  7.34 50.304 7.808 78.792 ;
     RECT  7.153 80.256 7.808 83.784 ;
     RECT  7.808 2.148 7.912 84.252 ;
     RECT  7.912 2.418 8.104 83.982 ;
     RECT  8.104 16.8 8.201 22.344 ;
     RECT  8.104 23.856 8.201 26.76 ;
     RECT  8.104 27.888 8.201 31.944 ;
     RECT  8.104 46.896 8.201 55.704 ;
     RECT  8.201 27.888 8.243 29.064 ;
     RECT  8.201 25.248 8.345 26.76 ;
     RECT  8.104 5.088 8.381 6.696 ;
     RECT  8.104 71.808 8.381 71.928 ;
     RECT  8.381 5.088 8.387 6.312 ;
     RECT  8.104 10.128 8.417 11.688 ;
     RECT  8.104 56.976 8.435 58.728 ;
     RECT  8.387 5.088 8.489 6.168 ;
     RECT  8.243 28.416 8.489 29.064 ;
     RECT  8.104 32.928 8.489 41.064 ;
     RECT  8.201 46.896 8.489 53.064 ;
     RECT  8.489 33.072 8.561 41.064 ;
     RECT  8.104 42.192 8.561 45.48 ;
     RECT  8.104 12.96 8.723 15.768 ;
     RECT  8.435 56.976 8.741 58.68 ;
     RECT  8.104 59.856 8.771 69.576 ;
     RECT  8.201 30.048 8.785 31.944 ;
     RECT  8.201 16.8 8.921 20.472 ;
     RECT  8.771 60.048 8.993 69.576 ;
     RECT  8.723 13.008 9.065 15.768 ;
     RECT  9.065 15.744 9.097 15.768 ;
     RECT  8.921 16.8 9.097 17.64 ;
     RECT  8.201 21.648 9.097 22.344 ;
     RECT  8.201 23.856 9.097 23.976 ;
     RECT  8.104 70.704 9.097 70.728 ;
     RECT  8.104 7.92 9.101 8.52 ;
     RECT  8.561 33.12 9.107 41.064 ;
     RECT  9.107 33.12 9.137 37.08 ;
     RECT  8.489 49.632 9.173 53.064 ;
     RECT  9.101 7.92 9.205 8.328 ;
     RECT  8.993 62.496 9.209 69.576 ;
     RECT  8.104 72.96 9.241 79.896 ;
     RECT  8.104 2.88 9.245 3.96 ;
     RECT  9.173 49.632 9.245 52.872 ;
     RECT  9.241 72.912 9.277 79.896 ;
     RECT  8.104 80.928 9.277 83.64 ;
     RECT  9.097 70.56 9.281 70.728 ;
     RECT  9.281 70.704 9.317 70.728 ;
     RECT  8.741 57.12 9.353 58.68 ;
     RECT  9.097 21.648 9.385 23.976 ;
     RECT  8.489 46.896 9.385 48.552 ;
     RECT  8.785 30.048 9.389 31.56 ;
     RECT  9.385 21.552 9.445 23.976 ;
     RECT  8.345 25.248 9.445 26.52 ;
     RECT  9.097 15.744 9.497 17.64 ;
     RECT  8.489 28.512 9.529 29.064 ;
     RECT  9.389 30.048 9.529 31.272 ;
     RECT  9.137 33.12 9.529 36.84 ;
     RECT  9.385 46.656 9.569 48.552 ;
     RECT  8.201 54.048 9.569 55.704 ;
     RECT  9.445 21.552 9.637 26.52 ;
     RECT  9.107 38.208 9.637 41.064 ;
     RECT  8.561 42.192 9.637 45 ;
     RECT  8.417 10.176 9.677 11.688 ;
     RECT  9.637 21.552 9.713 27.336 ;
     RECT  9.637 38.208 9.749 45 ;
     RECT  9.749 38.208 9.785 44.616 ;
     RECT  9.713 25.872 9.817 27.336 ;
     RECT  9.529 28.512 9.817 31.272 ;
     RECT  9.677 10.224 9.829 11.688 ;
     RECT  9.065 13.008 9.829 14.616 ;
     RECT  8.993 60.048 9.853 61.512 ;
     RECT  9.853 59.76 9.857 61.512 ;
     RECT  9.569 46.896 9.877 48.552 ;
     RECT  9.245 49.632 9.877 52.2 ;
     RECT  8.489 5.328 9.96 6.168 ;
     RECT  8.921 18.672 9.961 20.472 ;
     RECT  9.713 21.552 9.961 24.792 ;
     RECT  9.353 57.12 9.961 57.48 ;
     RECT  9.353 58.512 9.961 58.68 ;
     RECT  9.277 72.912 9.961 83.64 ;
     RECT  9.877 46.896 9.964 52.2 ;
     RECT  9.829 10.224 9.965 14.616 ;
     RECT  9.961 57.024 9.965 57.48 ;
     RECT  9.965 10.272 10.001 14.616 ;
     RECT  9.497 15.984 10.033 17.64 ;
     RECT  9.961 18.672 10.033 24.792 ;
     RECT  9.109 1.728 10.069 1.752 ;
     RECT  9.245 2.88 10.069 3.432 ;
     RECT  9.961 58.512 10.073 58.728 ;
     RECT  10.073 58.704 10.109 58.728 ;
     RECT  9.96 4.512 10.145 6.168 ;
     RECT  10.033 15.984 10.145 24.792 ;
     RECT  9.964 49.632 10.145 52.2 ;
     RECT  10.145 19.872 10.181 24.792 ;
     RECT  9.529 32.976 10.213 36.84 ;
     RECT  9.209 66.384 10.213 69.576 ;
     RECT  8.381 71.904 10.213 71.928 ;
     RECT  9.961 72.912 10.213 83.784 ;
     RECT  9.205 7.392 10.289 8.328 ;
     RECT  9.569 54.096 10.289 55.704 ;
     RECT  10.145 50.832 10.309 52.2 ;
     RECT  9.857 61.056 10.321 61.512 ;
     RECT  9.209 62.496 10.321 64.728 ;
     RECT  10.145 4.848 10.348 6.168 ;
     RECT  10.213 71.904 10.357 83.784 ;
     RECT  10.348 5.328 10.393 6.168 ;
     RECT  10.309 50.832 10.396 52.488 ;
     RECT  10.393 5.328 10.397 6.264 ;
     RECT  10.289 8.304 10.397 8.328 ;
     RECT  9.965 57.024 10.397 57.144 ;
     RECT  10.213 32.4 10.429 36.84 ;
     RECT  9.785 39.888 10.505 44.616 ;
     RECT  9.817 25.872 10.609 31.272 ;
     RECT  9.964 46.896 10.609 48.552 ;
     RECT  10.213 65.808 10.609 69.576 ;
     RECT  10.397 57.12 10.613 57.144 ;
     RECT  10.429 32.4 10.645 36.936 ;
     RECT  9.785 38.208 10.645 38.76 ;
     RECT  10.609 25.872 10.717 31.32 ;
     RECT  10.357 71.808 10.721 83.784 ;
     RECT  10.069 1.728 10.757 3.432 ;
     RECT  10.505 40.608 10.789 44.616 ;
     RECT  10.397 5.808 10.825 6.264 ;
     RECT  10.537 52.704 10.861 52.728 ;
     RECT  10.609 65.808 10.865 70.104 ;
     RECT  10.721 71.808 10.865 74.664 ;
     RECT  10.181 20.304 10.937 24.792 ;
     RECT  10.609 46.8 10.937 48.552 ;
     RECT  10.001 10.272 10.969 14.568 ;
     RECT  10.969 10.272 11.005 14.712 ;
     RECT  10.145 15.984 11.005 18.744 ;
     RECT  10.865 71.808 11.077 71.88 ;
     RECT  10.145 49.632 11.149 49.656 ;
     RECT  10.396 50.832 11.149 51.576 ;
     RECT  10.717 25.872 11.153 31.368 ;
     RECT  10.757 2.592 11.189 3.432 ;
     RECT  10.937 20.496 11.189 24.792 ;
     RECT  10.645 32.4 11.225 38.76 ;
     RECT  9.857 59.76 11.225 60.072 ;
     RECT  10.289 54.096 11.293 54.12 ;
     RECT  10.937 47.712 11.297 48.552 ;
     RECT  10.717 8.544 11.329 8.568 ;
     RECT  11.005 10.272 11.329 18.744 ;
     RECT  11.329 9.84 11.365 18.744 ;
     RECT  11.225 34.128 11.365 38.76 ;
     RECT  10.865 68.592 11.365 70.104 ;
     RECT  11.225 32.4 11.405 33.048 ;
     RECT  11.365 34.128 11.411 38.808 ;
     RECT  10.825 5.808 11.441 6.408 ;
     RECT  11.189 2.88 11.473 3.432 ;
     RECT  10.321 61.056 11.545 64.728 ;
     RECT  10.865 65.808 11.545 67.32 ;
     RECT  11.329 8.544 11.581 8.856 ;
     RECT  11.365 9.84 11.581 18.792 ;
     RECT  11.153 25.872 11.585 30.072 ;
     RECT  11.581 8.544 11.617 18.792 ;
     RECT  11.149 49.632 11.617 51.576 ;
     RECT  10.861 52.704 11.617 52.824 ;
     RECT  11.441 5.808 11.653 6.264 ;
     RECT  11.617 8.544 11.689 19.032 ;
     RECT  11.689 7.968 11.725 19.032 ;
     RECT  11.585 25.872 11.765 26.232 ;
     RECT  11.189 20.496 11.801 24.6 ;
     RECT  10.865 73.2 11.837 74.664 ;
     RECT  11.473 2.88 11.869 3.72 ;
     RECT  11.653 4.896 11.869 6.264 ;
     RECT  11.411 38.784 11.909 38.808 ;
     RECT  11.293 53.856 11.909 54.12 ;
     RECT  11.725 7.968 11.941 19.368 ;
     RECT  11.801 20.496 11.941 21.672 ;
     RECT  11.365 68.592 11.941 70.152 ;
     RECT  11.077 71.232 11.941 71.88 ;
     RECT  10.789 40.608 11.945 45 ;
     RECT  11.941 7.968 12.053 21.672 ;
     RECT  11.617 49.632 12.053 52.824 ;
     RECT  11.545 61.056 12.053 67.32 ;
     RECT  11.405 33.024 12.161 33.048 ;
     RECT  11.801 22.752 12.197 24.6 ;
     RECT  11.153 31.104 12.265 31.368 ;
     RECT  12.053 64.368 12.265 67.32 ;
     RECT  12.265 64.368 12.284 67.608 ;
     RECT  11.941 68.592 12.284 71.88 ;
     RECT  11.837 73.248 12.421 74.664 ;
     RECT  10.721 75.696 12.421 83.784 ;
     RECT  11.411 34.128 12.481 37.608 ;
     RECT  12.053 7.968 12.517 19.08 ;
     RECT  11.585 27.216 12.517 30.072 ;
     RECT  12.265 31.104 12.517 31.752 ;
     RECT  11.297 47.712 12.517 47.736 ;
     RECT  12.085 1.728 12.521 1.752 ;
     RECT  11.869 2.88 12.553 6.264 ;
     RECT  12.553 2.88 12.581 6.36 ;
     RECT  12.517 7.776 12.581 19.08 ;
     RECT  11.185 58.656 12.769 58.68 ;
     RECT  12.517 47.712 12.805 47.88 ;
     RECT  12.517 27.216 12.877 31.752 ;
     RECT  12.053 52.464 13.021 52.824 ;
     RECT  11.945 40.608 13.057 44.664 ;
     RECT  12.053 20.112 13.093 21.672 ;
     RECT  12.421 73.248 13.093 83.784 ;
     RECT  12.877 27.216 13.129 32.52 ;
     RECT  12.481 33.6 13.129 37.608 ;
     RECT  12.197 22.752 13.165 24.216 ;
     RECT  13.165 22.752 13.201 24.504 ;
     RECT  13.129 27.216 13.201 37.608 ;
     RECT  12.581 2.88 13.208 19.08 ;
     RECT  13.093 20.064 13.208 21.672 ;
     RECT  13.201 22.752 13.208 25.032 ;
     RECT  11.765 26.208 13.208 26.232 ;
     RECT  13.201 27.216 13.208 37.896 ;
     RECT  13.057 40.416 13.208 44.664 ;
     RECT  11.977 46.32 13.208 46.344 ;
     RECT  12.805 47.712 13.208 47.928 ;
     RECT  12.053 49.632 13.208 51.384 ;
     RECT  13.021 52.464 13.208 53.112 ;
     RECT  12.049 54.432 13.208 54.456 ;
     RECT  10.289 55.68 13.208 55.704 ;
     RECT  12.769 57.888 13.208 58.68 ;
     RECT  11.225 60.048 13.208 60.072 ;
     RECT  12.053 61.056 13.208 63.048 ;
     RECT  12.284 64.368 13.208 71.88 ;
     RECT  13.093 73.152 13.208 83.784 ;
     RECT  13.208 2.148 13.312 84.252 ;
     RECT  13.312 2.148 13.504 83.982 ;
     RECT  13.504 65.664 13.529 83.64 ;
     RECT  13.529 65.664 13.601 69.816 ;
     RECT  13.504 23.136 13.619 23.352 ;
     RECT  13.504 24.48 13.619 25.032 ;
     RECT  13.504 60.048 13.619 63.048 ;
     RECT  13.504 47.712 13.637 51.384 ;
     RECT  13.504 2.88 13.667 22.008 ;
     RECT  13.619 61.008 13.667 63.048 ;
     RECT  13.601 65.664 13.667 69.768 ;
     RECT  13.589 1.728 13.673 1.752 ;
     RECT  13.667 6.336 13.673 22.008 ;
     RECT  13.504 35.52 13.709 44.76 ;
     RECT  13.667 62.784 13.709 63.048 ;
     RECT  13.619 23.136 13.781 23.16 ;
     RECT  13.709 62.784 13.781 62.808 ;
     RECT  13.667 2.88 13.817 5.064 ;
     RECT  13.504 27.312 13.859 31.752 ;
     RECT  13.667 65.664 13.889 69.72 ;
     RECT  13.504 45.984 13.925 46.344 ;
     RECT  13.673 7.392 13.997 22.008 ;
     RECT  13.504 52.704 13.997 54.456 ;
     RECT  13.667 61.008 14.033 61.608 ;
     RECT  13.997 52.704 14.141 52.728 ;
     RECT  13.997 54.432 14.249 54.456 ;
     RECT  14.033 61.392 14.285 61.608 ;
     RECT  13.709 35.712 14.321 44.76 ;
     RECT  13.997 7.392 14.429 20.712 ;
     RECT  14.429 9.792 14.501 20.712 ;
     RECT  13.504 57.888 14.533 58.68 ;
     RECT  13.637 48.384 14.537 51.384 ;
     RECT  14.321 43.68 14.573 44.76 ;
     RECT  13.619 24.48 14.605 24.504 ;
     RECT  13.504 26.208 14.645 26.232 ;
     RECT  14.537 48.72 14.645 51.384 ;
     RECT  14.285 61.584 14.675 61.608 ;
     RECT  14.605 24.48 14.677 24.84 ;
     RECT  13.859 27.888 14.677 31.752 ;
     RECT  13.504 33.024 14.677 34.392 ;
     RECT  14.321 35.712 14.677 39.912 ;
     RECT  13.504 64.176 14.677 64.392 ;
     RECT  13.889 67.776 14.677 69.72 ;
     RECT  13.925 46.176 14.684 46.344 ;
     RECT  14.684 46.176 14.753 46.392 ;
     RECT  13.817 2.88 14.785 3.72 ;
     RECT  13.504 55.68 14.785 56.328 ;
     RECT  14.677 47.472 14.789 47.496 ;
     RECT  14.753 46.272 14.809 46.392 ;
     RECT  14.677 23.856 14.821 24.84 ;
     RECT  13.889 65.664 14.821 66.648 ;
     RECT  14.677 27.888 14.825 39.912 ;
     RECT  14.645 48.72 14.825 50.808 ;
     RECT  14.501 9.792 14.861 14.136 ;
     RECT  14.861 10.224 14.867 14.136 ;
     RECT  14.785 2.832 14.929 3.72 ;
     RECT  14.677 63.648 14.929 64.392 ;
     RECT  14.821 65.52 14.929 66.648 ;
     RECT  14.785 55.68 14.933 56.472 ;
     RECT  14.825 27.888 14.969 38.424 ;
     RECT  14.929 2.736 15.037 3.72 ;
     RECT  13.817 4.992 15.037 5.064 ;
     RECT  15.037 2.736 15.073 5.064 ;
     RECT  15.073 2.592 15.101 5.064 ;
     RECT  13.997 21.984 15.145 22.008 ;
     RECT  14.821 23.376 15.164 24.84 ;
     RECT  14.929 63.648 15.181 66.648 ;
     RECT  14.677 67.776 15.181 69.816 ;
     RECT  15.101 1.728 15.185 5.064 ;
     RECT  15.145 21.984 15.217 22.248 ;
     RECT  14.809 46.32 15.221 46.344 ;
     RECT  15.164 23.328 15.251 24.84 ;
     RECT  14.785 52.512 15.253 52.536 ;
     RECT  15.253 52.416 15.289 52.536 ;
     RECT  13.673 6.336 15.361 6.36 ;
     RECT  15.181 63.648 15.361 69.816 ;
     RECT  13.529 70.8 15.361 83.64 ;
     RECT  14.501 15.264 15.433 20.712 ;
     RECT  15.217 21.744 15.433 22.248 ;
     RECT  14.867 10.224 15.437 13.944 ;
     RECT  15.433 15.264 15.437 22.248 ;
     RECT  15.251 23.856 15.437 24.84 ;
     RECT  15.361 63.648 15.469 83.64 ;
     RECT  15.437 15.264 15.509 19.416 ;
     RECT  14.533 57.888 15.541 59.592 ;
     RECT  14.321 40.896 15.613 42.6 ;
     RECT  14.573 43.68 15.613 44.664 ;
     RECT  14.969 28.368 15.635 38.376 ;
     RECT  15.289 52.416 15.637 52.632 ;
     RECT  15.541 54.432 15.637 54.696 ;
     RECT  14.429 7.392 15.649 8.808 ;
     RECT  15.635 28.368 15.653 30.168 ;
     RECT  14.825 49.536 15.683 50.808 ;
     RECT  15.509 15.264 15.725 17.016 ;
     RECT  15.649 7.392 15.761 9.192 ;
     RECT  15.437 23.856 15.761 23.928 ;
     RECT  15.361 6.288 15.797 6.36 ;
     RECT  15.469 63.648 15.797 83.784 ;
     RECT  15.637 54 15.865 54.696 ;
     RECT  14.825 39.744 15.901 39.912 ;
     RECT  15.865 53.952 15.925 54.696 ;
     RECT  14.933 55.68 15.925 55.704 ;
     RECT  15.637 52.176 15.937 52.632 ;
     RECT  15.925 53.952 15.937 55.704 ;
     RECT  15.437 20.448 15.941 22.248 ;
     RECT  15.937 52.176 15.971 55.704 ;
     RECT  15.761 8.736 15.973 9.192 ;
     RECT  15.725 15.264 15.973 16.008 ;
     RECT  15.683 49.632 15.977 50.808 ;
     RECT  15.541 57.024 15.977 59.592 ;
     RECT  15.941 20.448 16.013 21.768 ;
     RECT  15.901 39.456 16.045 39.912 ;
     RECT  15.613 40.896 16.045 44.664 ;
     RECT  15.977 49.632 16.085 50.712 ;
     RECT  15.653 28.368 16.115 29.64 ;
     RECT  15.635 31.392 16.121 38.376 ;
     RECT  15.217 62.016 16.157 62.472 ;
     RECT  16.013 20.448 16.193 21 ;
     RECT  16.121 34.752 16.193 38.376 ;
     RECT  15.437 13.92 16.225 13.944 ;
     RECT  15.973 14.976 16.225 16.008 ;
     RECT  16.085 49.632 16.265 49.992 ;
     RECT  16.157 62.016 16.333 62.136 ;
     RECT  15.185 2.208 16.441 5.064 ;
     RECT  16.225 13.92 16.445 16.008 ;
     RECT  16.265 49.872 16.445 49.992 ;
     RECT  15.437 10.224 16.481 12.888 ;
     RECT  16.193 35.424 16.513 38.376 ;
     RECT  16.045 39.456 16.513 44.664 ;
     RECT  16.115 28.752 16.517 29.64 ;
     RECT  16.481 10.368 16.549 12.888 ;
     RECT  16.445 13.92 16.549 15.336 ;
     RECT  15.509 18.144 16.553 19.416 ;
     RECT  16.513 35.424 16.553 44.664 ;
     RECT  16.333 48.384 16.553 48.408 ;
     RECT  15.829 27.36 16.589 27.384 ;
     RECT  16.441 2.208 16.597 5.688 ;
     RECT  15.937 46.464 16.621 46.488 ;
     RECT  16.193 20.784 16.625 21 ;
     RECT  16.517 28.944 16.625 28.968 ;
     RECT  16.121 31.392 16.625 33.672 ;
     RECT  15.977 57.024 16.625 59.256 ;
     RECT  16.553 35.424 16.661 44.424 ;
     RECT  16.445 49.872 16.661 49.896 ;
     RECT  16.621 46.464 16.693 46.632 ;
     RECT  15.761 7.392 16.697 7.752 ;
     RECT  16.625 58.704 16.697 59.256 ;
     RECT  15.797 63.648 16.801 69.72 ;
     RECT  15.797 70.704 16.801 83.784 ;
     RECT  16.333 61.152 16.837 62.136 ;
     RECT  15.973 8.736 16.841 9.24 ;
     RECT  16.693 46.464 16.841 46.728 ;
     RECT  15.761 23.904 16.844 23.928 ;
     RECT  16.801 63.648 16.873 83.784 ;
     RECT  16.625 20.976 16.877 21 ;
     RECT  16.661 39.312 16.877 44.424 ;
     RECT  16.597 1.728 16.913 5.688 ;
     RECT  16.625 31.392 16.913 33.576 ;
     RECT  16.661 35.424 16.913 38.136 ;
     RECT  16.844 23.328 16.931 23.928 ;
     RECT  16.913 31.392 16.949 32.664 ;
     RECT  16.873 63.456 16.949 83.784 ;
     RECT  16.949 69.744 16.979 83.784 ;
     RECT  16.837 61.104 16.985 62.136 ;
     RECT  16.841 46.464 17.021 46.632 ;
     RECT  15.725 16.992 17.029 17.016 ;
     RECT  17.029 16.992 17.085 17.112 ;
     RECT  16.913 2.208 17.089 5.688 ;
     RECT  15.971 52.176 17.165 55.176 ;
     RECT  17.085 17.04 17.171 17.112 ;
     RECT  17.165 52.176 17.197 53.448 ;
     RECT  16.697 58.704 17.201 58.728 ;
     RECT  16.949 63.456 17.201 68.712 ;
     RECT  17.021 46.464 17.233 46.488 ;
     RECT  17.201 66.048 17.237 68.712 ;
     RECT  17.171 17.088 17.363 17.112 ;
     RECT  17.197 51.264 17.381 53.448 ;
     RECT  17.237 66.144 17.381 68.712 ;
     RECT  17.233 45.552 17.453 46.488 ;
     RECT  17.381 51.264 17.485 53.112 ;
     RECT  16.553 18.144 17.489 19.176 ;
     RECT  16.625 57.024 17.525 57.624 ;
     RECT  17.377 27.888 17.557 27.912 ;
     RECT  17.197 21.552 17.629 21.672 ;
     RECT  16.841 9.168 17.737 9.24 ;
     RECT  16.549 10.368 17.737 15.336 ;
     RECT  17.521 48.384 17.773 48.408 ;
     RECT  16.513 25.392 17.845 25.416 ;
     RECT  17.557 29.616 17.881 29.64 ;
     RECT  16.697 7.44 17.917 7.752 ;
     RECT  17.165 54.672 17.917 55.176 ;
     RECT  17.629 21.552 17.953 22.296 ;
     RECT  16.877 39.312 17.953 44.376 ;
     RECT  17.737 9.168 18.061 15.336 ;
     RECT  17.089 2.208 18.085 5.88 ;
     RECT  16.979 69.744 18.133 74.664 ;
     RECT  16.979 75.696 18.133 83.784 ;
     RECT  18.085 1.728 18.169 5.88 ;
     RECT  17.917 6.864 18.169 7.992 ;
     RECT  16.985 61.152 18.169 62.136 ;
     RECT  17.201 63.456 18.169 65.016 ;
     RECT  17.845 25.392 18.205 25.704 ;
     RECT  16.931 23.376 18.229 23.928 ;
     RECT  18.205 25.392 18.229 26.088 ;
     RECT  18.169 34.08 18.241 34.104 ;
     RECT  16.913 35.424 18.241 37.32 ;
     RECT  18.169 61.152 18.277 65.016 ;
     RECT  17.453 46.464 18.385 46.488 ;
     RECT  17.381 66.144 18.385 68.52 ;
     RECT  18.133 69.744 18.385 83.784 ;
     RECT  17.773 48.192 18.421 48.408 ;
     RECT  17.773 49.584 18.421 49.608 ;
     RECT  17.953 39.312 18.469 45.288 ;
     RECT  17.525 57.024 18.493 57.288 ;
     RECT  18.457 58.752 18.493 58.776 ;
     RECT  18.469 38.544 18.529 45.288 ;
     RECT  18.385 46.464 18.529 46.776 ;
     RECT  18.229 23.376 18.601 26.808 ;
     RECT  17.557 27.888 18.601 28.296 ;
     RECT  18.169 1.728 18.608 7.992 ;
     RECT  18.061 9.168 18.608 16.008 ;
     RECT  17.489 18.144 18.608 19.032 ;
     RECT  17.953 20.688 18.608 22.296 ;
     RECT  18.601 23.376 18.608 28.296 ;
     RECT  17.881 29.616 18.608 29.832 ;
     RECT  16.949 31.392 18.608 32.52 ;
     RECT  18.241 34.08 18.608 37.32 ;
     RECT  18.529 38.544 18.608 46.776 ;
     RECT  18.421 48.192 18.608 49.608 ;
     RECT  17.485 50.928 18.608 53.112 ;
     RECT  17.917 54.672 18.608 55.8 ;
     RECT  18.493 57.024 18.608 58.776 ;
     RECT  18.277 60.624 18.608 65.016 ;
     RECT  18.385 66.144 18.608 83.784 ;
     RECT  18.608 1.728 18.712 84.252 ;
     RECT  18.712 1.728 18.857 83.982 ;
     RECT  18.857 2.16 18.904 83.982 ;
     RECT  18.904 27.312 18.965 28.296 ;
     RECT  18.904 39.312 18.965 43.032 ;
     RECT  18.904 64.944 18.965 65.016 ;
     RECT  18.904 58.224 19.001 59.256 ;
     RECT  18.904 47.856 19.037 49.032 ;
     RECT  18.904 66.48 19.037 68.232 ;
     RECT  18.904 70.656 19.037 74.664 ;
     RECT  18.904 29.616 19.043 30.216 ;
     RECT  18.904 31.2 19.043 32.76 ;
     RECT  19.043 31.2 19.073 32.04 ;
     RECT  19.037 48.384 19.073 48.408 ;
     RECT  19.037 67.248 19.073 68.232 ;
     RECT  18.904 35.424 19.109 36.168 ;
     RECT  18.904 51.216 19.145 55.8 ;
     RECT  18.965 39.312 19.181 42.84 ;
     RECT  18.904 44.064 19.217 46.44 ;
     RECT  19.073 67.92 19.217 68.232 ;
     RECT  18.904 11.088 19.253 16.968 ;
     RECT  19.037 70.8 19.253 74.664 ;
     RECT  19.043 29.616 19.397 29.64 ;
     RECT  19.217 46.416 19.469 46.44 ;
     RECT  19.181 39.888 19.505 42.84 ;
     RECT  19.253 11.088 19.571 15.864 ;
     RECT  19.505 40.944 19.685 42.84 ;
     RECT  19.217 44.064 19.721 45.192 ;
     RECT  19.685 41.04 19.793 42.84 ;
     RECT  18.904 34.08 19.901 34.2 ;
     RECT  19.721 44.064 19.901 44.952 ;
     RECT  19.145 53.376 19.933 55.8 ;
     RECT  18.904 57.024 19.933 57.048 ;
     RECT  18.965 27.312 19.969 28.2 ;
     RECT  18.904 2.16 20.009 10.104 ;
     RECT  19.969 27.312 20.045 29.064 ;
     RECT  18.904 26.064 20.101 26.088 ;
     RECT  19.001 58.224 20.113 59.016 ;
     RECT  18.904 22.32 20.153 22.344 ;
     RECT  19.933 53.376 20.153 57.048 ;
     RECT  18.904 18.192 20.185 18.216 ;
     RECT  19.505 39.888 20.185 39.912 ;
     RECT  19.571 11.712 20.188 15.864 ;
     RECT  20.101 26.064 20.188 26.76 ;
     RECT  18.904 23.376 20.189 23.4 ;
     RECT  20.113 58.224 20.189 59.208 ;
     RECT  18.904 24.912 20.221 24.936 ;
     RECT  20.188 26.064 20.221 26.088 ;
     RECT  20.185 18.192 20.225 18.6 ;
     RECT  19.253 70.896 20.293 74.664 ;
     RECT  18.904 75.648 20.293 83.736 ;
     RECT  20.185 39.456 20.401 39.912 ;
     RECT  19.217 67.968 20.401 68.232 ;
     RECT  18.904 69.456 20.401 69.48 ;
     RECT  20.401 67.968 20.437 69.48 ;
     RECT  20.009 2.544 20.441 10.104 ;
     RECT  20.401 38.784 20.492 39.912 ;
     RECT  19.253 16.944 20.509 16.968 ;
     RECT  20.437 23.904 20.509 23.928 ;
     RECT  20.221 24.912 20.509 26.088 ;
     RECT  20.492 38.784 20.509 40.056 ;
     RECT  20.293 70.896 20.541 83.736 ;
     RECT  18.965 64.944 20.545 64.968 ;
     RECT  20.329 66.144 20.545 66.168 ;
     RECT  20.437 67.344 20.545 69.48 ;
     RECT  20.541 72.144 20.545 83.736 ;
     RECT  20.509 23.904 20.549 26.088 ;
     RECT  20.509 38.736 20.579 40.056 ;
     RECT  19.793 41.04 20.579 42.648 ;
     RECT  20.545 64.944 20.581 66.168 ;
     RECT  20.549 25.2 20.585 26.088 ;
     RECT  20.189 58.752 20.585 59.208 ;
     RECT  20.579 38.736 20.617 39.912 ;
     RECT  18.904 63.648 20.617 63.672 ;
     RECT  19.073 31.392 20.621 32.04 ;
     RECT  20.153 53.376 20.621 53.4 ;
     RECT  18.904 61.968 20.653 61.992 ;
     RECT  20.581 64.896 20.684 66.168 ;
     RECT  20.545 67.344 20.684 69.768 ;
     RECT  20.509 16.224 20.689 16.968 ;
     RECT  20.653 61.536 20.725 61.992 ;
     RECT  20.585 25.2 20.729 25.992 ;
     RECT  20.441 10.08 20.761 10.104 ;
     RECT  18.904 37.44 20.761 37.464 ;
     RECT  20.541 70.896 20.765 70.92 ;
     RECT  20.684 64.896 20.789 69.768 ;
     RECT  20.761 30.336 20.833 30.36 ;
     RECT  20.473 50.16 20.833 50.184 ;
     RECT  20.725 61.536 20.869 62.04 ;
     RECT  20.833 49.344 20.873 50.184 ;
     RECT  20.153 54.576 20.873 57.048 ;
     RECT  20.789 64.896 20.873 70.728 ;
     RECT  20.621 31.728 20.905 32.04 ;
     RECT  19.109 35.856 20.905 36.168 ;
     RECT  20.761 37.44 20.905 37.608 ;
     RECT  20.873 54.576 20.909 55.8 ;
     RECT  20.585 59.184 20.909 59.208 ;
     RECT  20.653 20.544 20.965 20.568 ;
     RECT  20.761 10.08 20.981 10.488 ;
     RECT  20.965 19.632 21.011 20.568 ;
     RECT  20.188 11.712 21.017 15.096 ;
     RECT  21.011 19.632 21.052 19.656 ;
     RECT  20.549 24.096 21.053 24.12 ;
     RECT  20.689 16.224 21.085 17.112 ;
     RECT  20.869 61.536 21.085 62.184 ;
     RECT  21.017 11.712 21.089 14.856 ;
     RECT  20.441 2.544 21.109 8.568 ;
     RECT  20.873 64.896 21.125 70.68 ;
     RECT  21.085 16.224 21.161 17.208 ;
     RECT  20.045 27.888 21.161 29.064 ;
     RECT  21.161 16.272 21.193 17.208 ;
     RECT  21.109 1.728 21.197 8.568 ;
     RECT  20.981 10.176 21.197 10.488 ;
     RECT  20.905 35.856 21.197 37.608 ;
     RECT  21.085 61.2 21.233 62.184 ;
     RECT  21.085 21.648 21.265 21.672 ;
     RECT  21.197 36.624 21.265 37.608 ;
     RECT  20.617 38.688 21.265 39.912 ;
     RECT  20.729 25.2 21.305 25.224 ;
     RECT  21.197 2.544 21.341 8.568 ;
     RECT  21.265 36.624 21.341 39.912 ;
     RECT  20.873 49.344 21.373 49.704 ;
     RECT  20.905 31.728 21.377 32.376 ;
     RECT  20.833 30.336 21.409 30.408 ;
     RECT  19.901 44.064 21.409 44.616 ;
     RECT  21.341 7.104 21.413 8.568 ;
     RECT  21.377 31.728 21.449 32.04 ;
     RECT  21.233 61.2 21.485 61.992 ;
     RECT  21.341 37.2 21.491 39.912 ;
     RECT  21.265 21.36 21.521 21.672 ;
     RECT  21.491 39.312 21.553 39.912 ;
     RECT  20.579 41.184 21.553 42.648 ;
     RECT  21.409 43.872 21.553 44.616 ;
     RECT  21.373 49.008 21.553 49.704 ;
     RECT  19.901 34.08 21.589 34.104 ;
     RECT  21.517 35.52 21.625 35.544 ;
     RECT  21.413 8.208 21.701 8.568 ;
     RECT  21.701 8.4 21.733 8.568 ;
     RECT  21.521 21.648 21.733 21.672 ;
     RECT  21.692 23.28 21.733 23.304 ;
     RECT  21.553 43.872 21.733 45.336 ;
     RECT  21.733 43.872 21.817 45.576 ;
     RECT  21.553 39.312 21.845 42.648 ;
     RECT  21.733 8.4 21.881 8.76 ;
     RECT  21.733 21.648 21.881 23.304 ;
     RECT  19.145 51.216 21.923 52.2 ;
     RECT  20.545 47.28 21.925 47.304 ;
     RECT  21.553 48.672 21.925 49.704 ;
     RECT  21.925 47.28 21.945 49.704 ;
     RECT  21.125 68.832 21.949 70.68 ;
     RECT  20.545 72.144 21.949 84.072 ;
     RECT  21.845 39.312 21.953 40.392 ;
     RECT  21.945 47.28 21.971 49.368 ;
     RECT  21.161 27.888 21.985 28.968 ;
     RECT  21.949 68.832 21.989 84.072 ;
     RECT  21.971 47.28 22.012 48.216 ;
     RECT  21.697 24.624 22.061 24.648 ;
     RECT  21.625 35.472 22.061 35.544 ;
     RECT  21.985 27.696 22.093 28.968 ;
     RECT  21.923 51.216 22.093 51.912 ;
     RECT  21.193 16.272 22.097 17.4 ;
     RECT  21.197 10.464 22.165 10.488 ;
     RECT  20.909 54.576 22.165 55.224 ;
     RECT  20.873 57.024 22.165 57.048 ;
     RECT  22.165 10.032 22.201 10.488 ;
     RECT  22.097 16.272 22.201 16.536 ;
     RECT  21.589 34.08 22.201 34.44 ;
     RECT  22.061 35.472 22.201 35.496 ;
     RECT  20.617 63.264 22.201 63.672 ;
     RECT  21.125 64.896 22.201 67.848 ;
     RECT  22.093 50.736 22.205 51.912 ;
     RECT  22.205 51.264 22.241 51.912 ;
     RECT  21.089 11.712 22.259 13.992 ;
     RECT  22.259 11.712 22.273 13.128 ;
     RECT  21.881 22.56 22.309 23.304 ;
     RECT  22.165 54.576 22.309 57.048 ;
     RECT  21.881 8.4 22.313 8.424 ;
     RECT  22.309 54.576 22.349 57.624 ;
     RECT  22.273 11.664 22.357 13.128 ;
     RECT  22.021 26.208 22.357 26.232 ;
     RECT  22.213 15.024 22.381 15.048 ;
     RECT  22.309 22.56 22.403 23.928 ;
     RECT  22.201 9.504 22.421 10.488 ;
     RECT  21.491 37.2 22.453 38.04 ;
     RECT  21.953 39.312 22.453 40.008 ;
     RECT  22.201 16.128 22.457 16.536 ;
     RECT  21.449 31.728 22.489 31.752 ;
     RECT  22.201 63.264 22.489 67.848 ;
     RECT  21.989 68.832 22.489 71.64 ;
     RECT  21.413 7.104 22.493 7.128 ;
     RECT  22.453 37.2 22.561 40.008 ;
     RECT  21.341 2.544 22.597 6.12 ;
     RECT  22.349 57.6 22.597 57.624 ;
     RECT  22.201 34.08 22.601 35.496 ;
     RECT  22.357 26.208 22.604 26.28 ;
     RECT  21.845 41.376 22.633 42.648 ;
     RECT  22.381 14.112 22.637 15.048 ;
     RECT  22.457 16.128 22.637 16.344 ;
     RECT  22.093 27.408 22.669 28.968 ;
     RECT  21.409 30 22.669 30.696 ;
     RECT  22.489 31.728 22.669 31.848 ;
     RECT  22.403 22.56 22.673 22.776 ;
     RECT  22.604 25.344 22.691 26.28 ;
     RECT  22.561 20.16 22.705 20.184 ;
     RECT  22.705 20.112 22.777 20.184 ;
     RECT  22.691 26.208 22.813 26.28 ;
     RECT  22.669 27.408 22.813 30.696 ;
     RECT  22.669 31.728 22.813 32.664 ;
     RECT  22.637 16.128 22.817 16.152 ;
     RECT  22.381 60.672 22.849 60.696 ;
     RECT  22.345 62.112 22.849 62.136 ;
     RECT  22.241 51.264 22.853 51.288 ;
     RECT  22.489 63.264 22.853 71.64 ;
     RECT  22.561 36.576 22.876 40.008 ;
     RECT  20.225 18.576 22.889 18.6 ;
     RECT  22.813 26.208 22.889 32.664 ;
     RECT  21.817 43.872 22.889 45.048 ;
     RECT  22.349 54.576 22.889 56.088 ;
     RECT  22.777 20.112 22.993 20.664 ;
     RECT  22.889 45.024 23.029 45.048 ;
     RECT  22.849 60.672 23.065 62.136 ;
     RECT  22.853 63.264 23.065 70.536 ;
     RECT  22.876 36.576 23.209 37.992 ;
     RECT  22.597 57.6 23.209 58.536 ;
     RECT  22.525 59.616 23.209 59.64 ;
     RECT  22.889 31.392 23.245 32.664 ;
     RECT  23.209 57.6 23.245 59.64 ;
     RECT  23.065 60.672 23.245 70.536 ;
     RECT  22.993 20.112 23.317 21.096 ;
     RECT  23.317 20.112 23.461 21.144 ;
     RECT  22.597 2.208 23.533 6.264 ;
     RECT  22.421 9.504 23.569 10.152 ;
     RECT  22.633 41.376 23.605 42.792 ;
     RECT  22.889 43.872 23.605 43.896 ;
     RECT  23.569 9.072 23.641 10.152 ;
     RECT  22.673 22.752 23.701 22.776 ;
     RECT  22.637 14.112 23.749 14.136 ;
     RECT  23.677 18.768 23.749 18.792 ;
     RECT  23.461 20.112 23.749 21.528 ;
     RECT  23.245 31.392 23.785 33.096 ;
     RECT  22.601 34.416 23.785 35.496 ;
     RECT  23.641 9.072 23.845 10.2 ;
     RECT  23.209 36.48 23.893 37.992 ;
     RECT  22.876 39.072 23.893 40.008 ;
     RECT  22.357 11.52 23.929 13.128 ;
     RECT  23.425 7.344 23.965 7.368 ;
     RECT  21.971 49.344 23.965 49.368 ;
     RECT  23.533 2.208 24.008 6.312 ;
     RECT  23.965 7.344 24.008 7.752 ;
     RECT  23.845 9.072 24.008 10.344 ;
     RECT  23.929 11.472 24.008 13.128 ;
     RECT  23.749 14.112 24.008 15.48 ;
     RECT  22.957 17.712 24.008 17.736 ;
     RECT  23.749 18.768 24.008 21.528 ;
     RECT  23.701 22.56 24.008 22.776 ;
     RECT  22.403 23.904 24.008 23.928 ;
     RECT  23.125 25.056 24.008 25.08 ;
     RECT  22.889 26.208 24.008 30.408 ;
     RECT  23.785 31.392 24.008 35.496 ;
     RECT  23.893 36.48 24.008 40.008 ;
     RECT  23.605 41.376 24.008 43.896 ;
     RECT  23.029 45.024 24.008 45.576 ;
     RECT  22.012 47.28 24.008 47.304 ;
     RECT  23.965 48.96 24.008 49.368 ;
     RECT  22.889 54.576 24.008 55.512 ;
     RECT  23.245 57.6 24.008 70.536 ;
     RECT  22.853 71.616 24.008 71.64 ;
     RECT  21.989 72.672 24.008 84.072 ;
     RECT  24.008 2.148 24.085 84.252 ;
     RECT  24.085 1.728 24.112 84.252 ;
     RECT  24.112 1.728 24.304 83.982 ;
     RECT  24.304 59.184 24.401 61.176 ;
     RECT  24.304 64.848 24.419 67.944 ;
     RECT  24.304 1.728 24.437 11.784 ;
     RECT  24.304 69.12 24.467 83.832 ;
     RECT  24.467 75.696 24.515 83.832 ;
     RECT  24.304 23.904 24.545 23.928 ;
     RECT  24.304 38.64 24.581 45 ;
     RECT  24.304 15.216 24.653 15.48 ;
     RECT  24.304 31.872 24.761 34.2 ;
     RECT  24.304 18.24 24.833 21.192 ;
     RECT  24.437 7.92 24.905 11.784 ;
     RECT  24.304 47.856 25.013 48.984 ;
     RECT  24.905 11.712 25.085 11.784 ;
     RECT  24.653 15.216 25.121 15.288 ;
     RECT  25.013 47.856 25.121 47.88 ;
     RECT  24.304 55.152 25.121 57.432 ;
     RECT  24.905 7.92 25.139 10.632 ;
     RECT  24.304 62.208 25.193 63.672 ;
     RECT  24.304 35.184 25.235 37.608 ;
     RECT  24.304 26.352 25.333 29.208 ;
     RECT  24.304 30.24 25.333 30.408 ;
     RECT  24.761 31.872 25.337 32.472 ;
     RECT  24.467 69.12 25.373 74.472 ;
     RECT  24.437 1.728 25.405 6.84 ;
     RECT  25.139 7.92 25.405 8.472 ;
     RECT  25.373 69.12 25.441 70.152 ;
     RECT  25.121 15.216 25.445 15.24 ;
     RECT  25.333 26.352 25.477 30.408 ;
     RECT  25.405 1.728 25.481 8.472 ;
     RECT  24.304 16.704 25.513 17.112 ;
     RECT  25.513 16.272 25.549 17.112 ;
     RECT  24.833 18.24 25.549 18.84 ;
     RECT  24.581 38.64 25.549 40.152 ;
     RECT  24.581 41.328 25.549 45 ;
     RECT  24.304 13.008 25.693 14.184 ;
     RECT  24.304 50.976 25.693 51.048 ;
     RECT  24.401 59.184 25.724 59.208 ;
     RECT  25.235 35.184 25.733 37.32 ;
     RECT  25.121 55.248 25.733 57.432 ;
     RECT  25.441 69.072 25.733 70.152 ;
     RECT  25.724 59.136 25.765 59.208 ;
     RECT  24.401 60.24 25.765 61.176 ;
     RECT  24.304 45.984 25.805 46.008 ;
     RECT  25.765 59.136 25.805 61.176 ;
     RECT  25.805 59.136 25.811 61.08 ;
     RECT  25.693 50.112 25.837 51.048 ;
     RECT  25.549 38.64 25.873 45 ;
     RECT  25.193 62.304 25.877 63.672 ;
     RECT  24.833 20.16 26.017 21.192 ;
     RECT  24.761 33.936 26.017 34.2 ;
     RECT  25.373 71.376 26.021 74.472 ;
     RECT  25.477 26.352 26.045 30.792 ;
     RECT  25.837 50.112 26.053 51.624 ;
     RECT  24.419 64.848 26.053 67.896 ;
     RECT  26.045 26.352 26.06 30.84 ;
     RECT  25.337 31.872 26.06 32.232 ;
     RECT  26.021 71.712 26.089 74.472 ;
     RECT  25.139 9.504 26.093 10.632 ;
     RECT  26.06 26.352 26.093 32.232 ;
     RECT  25.873 38.64 26.093 45.912 ;
     RECT  26.093 30.24 26.099 32.232 ;
     RECT  26.017 19.92 26.125 21.192 ;
     RECT  25.877 62.448 26.125 63.672 ;
     RECT  26.053 64.848 26.125 68.184 ;
     RECT  24.515 75.792 26.125 83.832 ;
     RECT  25.549 16.272 26.129 18.84 ;
     RECT  26.053 50.112 26.161 51.672 ;
     RECT  26.093 26.352 26.195 29.208 ;
     RECT  26.125 24.192 26.197 24.216 ;
     RECT  25.013 48.96 26.197 48.984 ;
     RECT  26.093 40.032 26.201 45.912 ;
     RECT  26.125 75.792 26.209 83.88 ;
     RECT  26.197 48.816 26.233 48.984 ;
     RECT  26.209 75.792 26.237 83.832 ;
     RECT  26.197 23.328 26.243 24.216 ;
     RECT  26.237 75.792 26.243 83.784 ;
     RECT  25.085 11.712 26.269 11.736 ;
     RECT  26.233 48.816 26.269 49.128 ;
     RECT  26.125 62.448 26.309 68.184 ;
     RECT  25.733 69.264 26.309 70.152 ;
     RECT  26.125 19.92 26.341 21.816 ;
     RECT  26.195 26.352 26.341 29.064 ;
     RECT  26.017 33.312 26.341 34.2 ;
     RECT  25.733 35.184 26.341 35.208 ;
     RECT  26.161 50.112 26.341 51.72 ;
     RECT  24.304 53.28 26.341 53.832 ;
     RECT  26.309 63.504 26.345 68.184 ;
     RECT  26.093 10.416 26.377 10.632 ;
     RECT  26.269 11.712 26.377 11.784 ;
     RECT  25.481 1.728 26.417 7.08 ;
     RECT  26.341 50.112 26.453 53.832 ;
     RECT  25.811 59.136 26.453 59.832 ;
     RECT  26.269 48.24 26.492 49.128 ;
     RECT  26.417 2.208 26.521 7.08 ;
     RECT  26.243 75.792 26.531 83.64 ;
     RECT  26.492 47.856 26.533 49.128 ;
     RECT  26.533 47.664 26.557 49.128 ;
     RECT  26.453 50.112 26.557 50.184 ;
     RECT  26.243 23.328 26.561 23.352 ;
     RECT  26.453 59.136 26.593 59.208 ;
     RECT  26.449 57.84 26.629 57.864 ;
     RECT  26.593 59.088 26.629 59.208 ;
     RECT  25.693 13.008 26.633 14.904 ;
     RECT  26.099 30.384 26.633 32.232 ;
     RECT  26.341 33.312 26.669 35.208 ;
     RECT  26.201 40.128 26.669 45.912 ;
     RECT  26.669 34.608 26.701 35.208 ;
     RECT  25.733 36.336 26.701 37.32 ;
     RECT  26.345 63.6 26.819 68.184 ;
     RECT  26.521 2.208 26.849 7.224 ;
     RECT  26.129 16.272 26.849 18.792 ;
     RECT  26.341 19.92 26.849 22.248 ;
     RECT  25.481 8.448 26.917 8.472 ;
     RECT  26.309 62.448 26.921 62.472 ;
     RECT  26.633 13.008 26.957 13.848 ;
     RECT  26.557 47.664 26.957 50.184 ;
     RECT  26.957 13.008 26.989 13.368 ;
     RECT  26.629 57.84 27.101 59.208 ;
     RECT  26.377 10.416 27.109 11.784 ;
     RECT  26.989 12.864 27.109 13.368 ;
     RECT  26.633 14.88 27.137 14.904 ;
     RECT  26.849 19.92 27.173 21.96 ;
     RECT  26.819 63.6 27.173 67.464 ;
     RECT  26.849 2.208 27.196 6.84 ;
     RECT  26.957 49.104 27.209 50.184 ;
     RECT  26.669 40.128 27.241 43.896 ;
     RECT  26.089 71.712 27.277 74.616 ;
     RECT  26.341 26.256 27.301 29.064 ;
     RECT  26.669 44.976 27.301 45.912 ;
     RECT  26.309 69.264 27.313 69.288 ;
     RECT  26.957 47.664 27.317 47.688 ;
     RECT  26.453 51.216 27.317 53.832 ;
     RECT  26.093 38.64 27.353 39.048 ;
     RECT  27.209 49.104 27.361 49.608 ;
     RECT  27.301 24.48 27.388 29.064 ;
     RECT  27.301 44.976 27.389 46.248 ;
     RECT  27.361 49.104 27.389 49.56 ;
     RECT  27.317 51.216 27.389 53.688 ;
     RECT  27.173 19.92 27.421 19.944 ;
     RECT  26.989 60.816 27.421 60.84 ;
     RECT  27.109 10.416 27.425 13.368 ;
     RECT  26.633 30.384 27.457 31.944 ;
     RECT  27.425 10.896 27.461 13.368 ;
     RECT  27.277 70.944 27.461 74.616 ;
     RECT  25.733 55.248 27.497 56.664 ;
     RECT  26.701 34.608 27.565 37.32 ;
     RECT  27.461 11.664 27.569 13.368 ;
     RECT  27.389 45.12 27.569 46.248 ;
     RECT  27.389 51.216 27.569 51.72 ;
     RECT  27.388 26.256 27.641 29.064 ;
     RECT  27.457 30.048 27.673 31.944 ;
     RECT  26.669 33.312 27.673 33.624 ;
     RECT  27.565 34.608 27.709 37.608 ;
     RECT  27.569 46.224 27.781 46.248 ;
     RECT  27.241 40.08 27.853 43.896 ;
     RECT  27.709 34.608 27.868 37.896 ;
     RECT  27.781 46.224 27.889 46.536 ;
     RECT  27.353 39.024 27.929 39.048 ;
     RECT  27.313 68.88 27.929 69.288 ;
     RECT  27.421 60.816 28.033 62.184 ;
     RECT  27.569 11.664 28.037 11.736 ;
     RECT  28.033 60.288 28.073 62.184 ;
     RECT  26.917 7.92 28.097 8.472 ;
     RECT  27.853 9.648 28.097 9.672 ;
     RECT  26.531 75.984 28.105 83.64 ;
     RECT  27.853 40.08 28.141 44.136 ;
     RECT  26.849 16.272 28.172 17.64 ;
     RECT  28.097 7.92 28.181 9.672 ;
     RECT  28.037 11.712 28.181 11.736 ;
     RECT  27.173 21.12 28.181 21.96 ;
     RECT  27.101 58.56 28.213 59.208 ;
     RECT  28.172 15.648 28.259 17.64 ;
     RECT  27.461 74.016 28.289 74.616 ;
     RECT  27.389 53.04 28.357 53.688 ;
     RECT  27.497 55.248 28.357 56.04 ;
     RECT  28.105 75.984 28.397 83.736 ;
     RECT  28.357 53.04 28.429 56.04 ;
     RECT  27.641 26.304 28.433 29.064 ;
     RECT  28.213 58.416 28.465 59.208 ;
     RECT  27.196 2.208 28.501 5.064 ;
     RECT  27.196 6.048 28.501 6.84 ;
     RECT  28.141 39.264 28.501 44.136 ;
     RECT  27.569 45.12 28.501 45.144 ;
     RECT  27.929 68.88 28.501 68.904 ;
     RECT  27.461 70.944 28.501 72.888 ;
     RECT  28.501 2.208 28.597 6.84 ;
     RECT  28.181 9.648 28.609 9.672 ;
     RECT  28.429 52.992 28.609 56.04 ;
     RECT  27.388 24.48 28.681 24.504 ;
     RECT  27.889 46.224 28.681 46.728 ;
     RECT  28.501 70.896 28.681 72.888 ;
     RECT  28.465 58.08 28.753 59.208 ;
     RECT  28.609 52.8 28.789 56.04 ;
     RECT  27.673 30.048 28.861 33.624 ;
     RECT  28.501 39.264 28.861 45.144 ;
     RECT  28.681 46.176 28.861 46.728 ;
     RECT  28.681 70.896 28.861 72.984 ;
     RECT  27.868 35.184 28.897 37.896 ;
     RECT  28.789 51.888 28.897 56.04 ;
     RECT  28.597 1.728 28.901 6.84 ;
     RECT  28.181 7.92 28.933 8.52 ;
     RECT  28.681 24.192 28.933 24.504 ;
     RECT  28.753 57.456 28.933 59.208 ;
     RECT  27.389 49.104 29.013 49.128 ;
     RECT  28.933 23.904 29.041 24.504 ;
     RECT  28.901 2.148 29.077 6.84 ;
     RECT  28.933 7.824 29.077 8.52 ;
     RECT  28.177 47.76 29.077 47.784 ;
     RECT  29.013 49.008 29.077 49.128 ;
     RECT  28.501 68.4 29.077 68.904 ;
     RECT  28.861 30.048 29.18 34.2 ;
     RECT  28.897 35.184 29.18 38.184 ;
     RECT  29.077 68.4 29.18 69.48 ;
     RECT  28.861 70.56 29.18 72.984 ;
     RECT  27.173 63.6 29.185 67.32 ;
     RECT  28.181 21.12 29.221 21.672 ;
     RECT  28.897 51.648 29.221 56.088 ;
     RECT  28.933 57.36 29.221 59.208 ;
     RECT  29.041 23.904 29.257 25.08 ;
     RECT  29.077 2.148 29.269 8.52 ;
     RECT  28.609 9.648 29.269 9.912 ;
     RECT  27.569 12.864 29.269 13.368 ;
     RECT  29.18 30.048 29.269 38.184 ;
     RECT  28.861 39.264 29.269 46.728 ;
     RECT  29.077 47.76 29.269 49.128 ;
     RECT  28.433 26.64 29.329 29.064 ;
     RECT  29.269 30.048 29.329 46.728 ;
     RECT  29.269 2.148 29.408 9.912 ;
     RECT  29.185 11.76 29.408 11.784 ;
     RECT  29.269 12.768 29.408 13.8 ;
     RECT  28.393 14.928 29.408 15.24 ;
     RECT  28.259 16.272 29.408 17.64 ;
     RECT  27.421 19.248 29.408 19.944 ;
     RECT  29.221 21.12 29.408 21.96 ;
     RECT  29.257 23.904 29.408 25.56 ;
     RECT  29.329 26.64 29.408 46.728 ;
     RECT  29.269 47.76 29.408 49.32 ;
     RECT  29.221 51.648 29.408 59.208 ;
     RECT  28.073 60.288 29.408 60.312 ;
     RECT  28.073 61.392 29.408 62.184 ;
     RECT  29.185 63.504 29.408 67.32 ;
     RECT  29.18 68.4 29.408 72.984 ;
     RECT  28.289 74.016 29.408 74.472 ;
     RECT  28.397 75.984 29.408 83.64 ;
     RECT  29.408 2.148 29.512 84.252 ;
     RECT  29.512 2.148 29.704 83.982 ;
     RECT  29.704 2.148 29.801 6.936 ;
     RECT  29.704 9.888 29.843 11.688 ;
     RECT  29.704 23.616 29.873 25.56 ;
     RECT  29.704 29.616 29.932 45 ;
     RECT  29.704 51.648 29.981 59.736 ;
     RECT  29.801 2.148 30.085 6.888 ;
     RECT  29.843 10.464 30.197 11.688 ;
     RECT  29.873 23.616 30.197 23.928 ;
     RECT  29.932 33.312 30.197 45 ;
     RECT  30.085 1.728 30.305 6.888 ;
     RECT  29.704 21.12 30.305 22.632 ;
     RECT  29.932 29.616 30.305 32.04 ;
     RECT  29.704 63.504 30.305 74.616 ;
     RECT  29.704 12.768 30.419 17.88 ;
     RECT  30.197 36.576 30.449 45 ;
     RECT  29.981 59.184 30.467 59.736 ;
     RECT  29.704 61.008 30.493 62.184 ;
     RECT  29.873 25.2 30.521 25.56 ;
     RECT  30.197 10.464 30.556 11.4 ;
     RECT  30.419 12.768 30.563 16.536 ;
     RECT  29.704 27.6 30.733 28.536 ;
     RECT  29.704 19.2 30.809 20.04 ;
     RECT  30.449 40.032 30.845 45 ;
     RECT  30.305 69.456 30.849 74.616 ;
     RECT  29.704 75.84 30.849 83.784 ;
     RECT  30.449 36.576 30.851 38.568 ;
     RECT  30.563 16.512 30.881 16.536 ;
     RECT  30.493 61.68 30.913 62.184 ;
     RECT  30.305 63.504 30.913 68.376 ;
     RECT  29.704 49.296 30.917 50.184 ;
     RECT  30.845 41.376 30.949 45 ;
     RECT  30.913 61.68 30.953 68.376 ;
     RECT  30.917 49.536 30.989 50.184 ;
     RECT  29.704 46.224 31.129 47.448 ;
     RECT  29.704 8.544 31.201 8.568 ;
     RECT  30.305 30.048 31.201 32.04 ;
     RECT  31.129 46.224 31.201 48.072 ;
     RECT  30.949 41.376 31.205 45.048 ;
     RECT  31.205 41.472 31.273 45.048 ;
     RECT  31.201 46.224 31.273 48.12 ;
     RECT  30.305 2.304 31.309 6.888 ;
     RECT  30.563 12.768 31.313 15.48 ;
     RECT  30.556 11.376 31.333 11.4 ;
     RECT  31.313 12.768 31.333 15.384 ;
     RECT  30.197 33.6 31.417 35.208 ;
     RECT  30.845 40.032 31.417 40.056 ;
     RECT  30.197 23.616 31.429 23.64 ;
     RECT  30.521 25.2 31.429 25.464 ;
     RECT  31.273 41.472 31.475 48.12 ;
     RECT  31.429 23.616 31.516 25.464 ;
     RECT  31.201 30.048 31.597 32.28 ;
     RECT  31.309 2.304 31.621 7.416 ;
     RECT  30.953 62.976 31.628 68.376 ;
     RECT  30.849 69.456 31.628 83.784 ;
     RECT  31.333 11.376 31.633 15.384 ;
     RECT  31.417 33.6 31.637 35.544 ;
     RECT  29.981 51.648 31.637 57.864 ;
     RECT  31.597 30.048 31.673 32.328 ;
     RECT  31.628 62.976 31.715 83.784 ;
     RECT  31.637 52.176 31.745 57.864 ;
     RECT  30.305 22.08 31.777 22.632 ;
     RECT  31.516 23.616 31.777 23.64 ;
     RECT  30.419 17.856 31.813 17.88 ;
     RECT  30.809 19.2 31.813 19.416 ;
     RECT  31.673 31.632 31.817 32.328 ;
     RECT  31.516 24.768 31.849 25.464 ;
     RECT  31.633 10.752 31.859 15.384 ;
     RECT  31.093 20.64 31.909 20.952 ;
     RECT  31.777 22.08 31.909 23.64 ;
     RECT  31.715 69.456 31.925 83.784 ;
     RECT  31.621 2.16 31.961 7.416 ;
     RECT  31.859 11.376 31.997 15.384 ;
     RECT  31.964 50.928 32.051 51.096 ;
     RECT  31.849 24.768 32.065 25.752 ;
     RECT  30.851 38.544 32.065 38.568 ;
     RECT  31.417 39.6 32.065 40.056 ;
     RECT  31.475 42.528 32.149 48.12 ;
     RECT  32.065 24.768 32.173 26.52 ;
     RECT  30.733 27.6 32.173 28.68 ;
     RECT  30.467 59.712 32.173 59.736 ;
     RECT  32.173 24.768 32.249 28.68 ;
     RECT  31.909 20.64 32.339 23.64 ;
     RECT  32.065 38.544 32.353 40.056 ;
     RECT  30.989 49.536 32.357 49.56 ;
     RECT  32.137 16.368 32.389 16.392 ;
     RECT  31.813 17.856 32.389 19.416 ;
     RECT  31.925 69.552 32.437 83.784 ;
     RECT  30.953 61.68 32.461 61.704 ;
     RECT  31.715 62.976 32.461 68.376 ;
     RECT  32.339 20.64 32.533 23.352 ;
     RECT  31.201 8.544 32.537 9.048 ;
     RECT  32.537 8.976 32.569 9.048 ;
     RECT  31.997 11.376 32.573 14.472 ;
     RECT  32.149 42.528 32.573 48.456 ;
     RECT  32.573 11.376 32.609 13.752 ;
     RECT  32.389 16.368 32.645 19.416 ;
     RECT  32.573 42.528 32.645 47.88 ;
     RECT  32.533 20.4 32.713 23.352 ;
     RECT  32.353 38.544 32.713 40.68 ;
     RECT  32.609 12.768 32.753 13.752 ;
     RECT  32.713 38.496 32.857 40.68 ;
     RECT  32.645 42.528 32.857 47.064 ;
     RECT  31.745 52.752 32.857 57.864 ;
     RECT  32.173 59.52 32.857 59.736 ;
     RECT  32.645 16.368 32.861 18.792 ;
     RECT  31.817 31.632 32.893 32.04 ;
     RECT  32.861 16.368 32.897 18.744 ;
     RECT  32.857 52.752 32.924 59.736 ;
     RECT  32.857 38.496 32.933 47.064 ;
     RECT  32.897 16.368 32.965 17.112 ;
     RECT  32.924 52.752 33.011 60.024 ;
     RECT  32.893 31.632 33.013 32.328 ;
     RECT  31.637 33.6 33.013 35.352 ;
     RECT  33.013 31.632 33.037 35.352 ;
     RECT  30.851 36.576 33.037 37.08 ;
     RECT  32.569 8.976 33.059 9.768 ;
     RECT  32.461 61.68 33.073 68.376 ;
     RECT  32.437 69.552 33.073 83.832 ;
     RECT  31.673 30.048 33.077 30.408 ;
     RECT  31.961 2.352 33.113 7.416 ;
     RECT  33.037 31.632 33.113 37.08 ;
     RECT  32.933 38.496 33.149 43.608 ;
     RECT  32.933 44.88 33.149 47.064 ;
     RECT  33.149 39.84 33.155 43.608 ;
     RECT  33.013 11.328 33.181 11.352 ;
     RECT  32.965 16.272 33.181 17.112 ;
     RECT  33.011 52.752 33.185 59.544 ;
     RECT  32.249 25.2 33.221 28.68 ;
     RECT  33.073 61.68 33.221 83.832 ;
     RECT  33.109 0.096 33.329 0.12 ;
     RECT  33.149 38.496 33.365 38.808 ;
     RECT  32.051 51.072 33.365 51.096 ;
     RECT  33.185 52.944 33.437 59.544 ;
     RECT  33.221 61.68 33.469 71.736 ;
     RECT  33.181 16.224 33.541 17.112 ;
     RECT  33.437 54.336 33.581 59.544 ;
     RECT  32.713 19.872 33.617 23.352 ;
     RECT  33.155 41.856 33.617 43.608 ;
     RECT  33.221 25.2 33.637 28.536 ;
     RECT  33.059 8.976 33.653 9.336 ;
     RECT  33.077 30.144 33.653 30.408 ;
     RECT  33.155 39.84 33.653 40.776 ;
     RECT  33.637 24.48 33.725 28.536 ;
     RECT  33.221 72.72 33.761 83.832 ;
     RECT  33.181 10.656 33.797 11.352 ;
     RECT  33.113 31.632 33.797 36.936 ;
     RECT  33.469 61.104 33.797 71.736 ;
     RECT  33.797 68.928 33.833 71.736 ;
     RECT  32.753 12.768 33.865 13.08 ;
     RECT  33.865 12.768 33.973 13.32 ;
     RECT  33.577 14.352 33.973 14.376 ;
     RECT  33.653 40.416 34.153 40.776 ;
     RECT  33.653 30.384 34.297 30.408 ;
     RECT  33.797 31.632 34.297 31.656 ;
     RECT  33.437 52.944 34.297 52.968 ;
     RECT  33.581 57.84 34.333 59.544 ;
     RECT  33.365 38.496 34.369 38.52 ;
     RECT  33.617 42.528 34.405 43.608 ;
     RECT  33.149 44.88 34.405 46.632 ;
     RECT  34.297 52.416 34.405 52.968 ;
     RECT  33.581 54.336 34.405 56.04 ;
     RECT  32.897 18.384 34.441 18.744 ;
     RECT  33.113 2.544 34.477 7.416 ;
     RECT  33.797 32.88 34.477 36.936 ;
     RECT  34.369 38.112 34.477 38.52 ;
     RECT  34.333 57.84 34.508 59.784 ;
     RECT  33.797 61.104 34.508 67.848 ;
     RECT  34.477 2.544 34.513 7.464 ;
     RECT  33.797 11.328 34.513 11.352 ;
     RECT  33.617 20.064 34.549 23.352 ;
     RECT  33.725 24.48 34.549 28.296 ;
     RECT  34.513 2.544 34.577 7.944 ;
     RECT  34.513 11.328 34.585 11.736 ;
     RECT  33.833 70.08 34.597 71.736 ;
     RECT  33.761 72.72 34.597 83.784 ;
     RECT  34.153 40.416 34.621 41.208 ;
     RECT  34.405 42.528 34.621 46.632 ;
     RECT  33.541 16.128 34.645 17.112 ;
     RECT  34.577 1.728 34.661 7.944 ;
     RECT  34.621 40.416 34.685 46.632 ;
     RECT  34.513 47.616 34.685 47.64 ;
     RECT  34.685 40.416 34.693 47.64 ;
     RECT  34.585 11.328 34.765 11.784 ;
     RECT  33.973 12.768 34.765 14.376 ;
     RECT  34.645 16.128 34.765 17.16 ;
     RECT  34.153 49.488 34.765 49.512 ;
     RECT  34.661 2.148 34.808 7.944 ;
     RECT  33.653 9.072 34.808 9.336 ;
     RECT  34.765 11.328 34.808 14.376 ;
     RECT  34.765 15.744 34.808 17.16 ;
     RECT  34.441 18.192 34.808 18.744 ;
     RECT  34.549 20.064 34.808 28.296 ;
     RECT  34.297 30.384 34.808 31.656 ;
     RECT  34.477 32.88 34.808 38.52 ;
     RECT  34.693 39.84 34.808 48.168 ;
     RECT  34.765 49.488 34.808 49.56 ;
     RECT  34.405 52.416 34.808 56.04 ;
     RECT  34.508 57.84 34.808 67.848 ;
     RECT  33.833 68.928 34.808 68.952 ;
     RECT  34.597 70.08 34.808 83.784 ;
     RECT  34.808 2.148 34.912 84.252 ;
     RECT  34.912 2.418 35.104 83.982 ;
     RECT  35.104 52.128 35.201 56.04 ;
     RECT  35.104 61.056 35.201 70.104 ;
     RECT  35.104 18.192 35.219 37.464 ;
     RECT  35.104 41.712 35.219 49.56 ;
     RECT  35.104 57.888 35.345 58.152 ;
     RECT  35.219 41.712 35.363 49.512 ;
     RECT  35.104 9.312 35.381 9.528 ;
     RECT  35.104 16.368 35.381 17.208 ;
     RECT  35.219 18.192 35.507 33.624 ;
     RECT  35.507 18.192 35.525 29.16 ;
     RECT  35.507 30.192 35.548 33.624 ;
     RECT  35.525 18.192 35.561 23.592 ;
     RECT  35.219 34.752 35.597 37.464 ;
     RECT  35.104 11.808 35.705 14.136 ;
     RECT  35.561 18.72 35.705 23.592 ;
     RECT  35.104 59.76 35.705 59.832 ;
     RECT  35.201 61.056 35.705 69.864 ;
     RECT  35.363 43.584 35.741 49.512 ;
     RECT  35.705 61.056 35.777 67.272 ;
     RECT  35.741 43.584 35.813 45.24 ;
     RECT  35.777 61.056 35.813 62.184 ;
     RECT  35.104 2.544 35.885 7.944 ;
     RECT  35.363 41.712 35.921 42.6 ;
     RECT  35.104 71.088 35.921 83.784 ;
     RECT  35.741 46.32 35.957 49.512 ;
     RECT  35.705 22.272 35.993 23.592 ;
     RECT  35.597 35.184 36.065 37.464 ;
     RECT  35.201 52.128 36.065 53.112 ;
     RECT  35.885 2.544 36.085 7.464 ;
     RECT  36.085 1.728 36.101 7.464 ;
     RECT  35.957 46.32 36.101 49.416 ;
     RECT  35.201 54.336 36.137 56.04 ;
     RECT  35.381 16.368 36.205 17.112 ;
     RECT  36.101 6.768 36.209 7.464 ;
     RECT  35.525 24.576 36.209 29.16 ;
     RECT  36.137 55.584 36.209 56.04 ;
     RECT  35.104 38.496 36.241 38.712 ;
     RECT  36.101 1.728 36.245 5.688 ;
     RECT  36.065 52.128 36.323 53.016 ;
     RECT  36.241 38.112 36.341 38.712 ;
     RECT  35.104 39.84 36.341 40.584 ;
     RECT  35.345 57.888 36.385 58.008 ;
     RECT  36.341 38.112 36.425 40.584 ;
     RECT  36.425 39.936 36.457 40.584 ;
     RECT  35.777 63.6 36.461 67.272 ;
     RECT  35.705 68.64 36.461 69.864 ;
     RECT  36.101 47.664 36.533 49.416 ;
     RECT  36.461 68.928 36.569 69.864 ;
     RECT  35.548 30.192 36.605 30.456 ;
     RECT  36.569 69.072 36.641 69.864 ;
     RECT  36.461 63.6 36.659 66.888 ;
     RECT  36.457 39.936 36.677 40.632 ;
     RECT  35.993 22.464 36.749 23.592 ;
     RECT  36.205 15.888 36.781 17.112 ;
     RECT  36.065 35.184 36.812 37.032 ;
     RECT  36.533 47.856 36.821 49.416 ;
     RECT  35.705 11.952 36.853 14.136 ;
     RECT  36.781 15.504 36.853 17.112 ;
     RECT  36.209 24.864 36.893 29.16 ;
     RECT  36.385 57.264 36.925 58.008 ;
     RECT  36.641 69.312 36.961 69.864 ;
     RECT  35.921 71.088 36.961 83.64 ;
     RECT  36.853 11.952 36.965 17.112 ;
     RECT  36.677 40.368 36.997 40.632 ;
     RECT  35.921 42.048 36.997 42.6 ;
     RECT  35.813 43.584 36.997 45 ;
     RECT  36.961 69.312 37.001 83.64 ;
     RECT  36.893 24.864 37.037 29.112 ;
     RECT  36.965 11.952 37.043 14.136 ;
     RECT  36.997 40.368 37.043 45 ;
     RECT  36.385 50.784 37.073 50.808 ;
     RECT  36.323 52.992 37.105 53.016 ;
     RECT  36.137 54.336 37.105 54.552 ;
     RECT  36.101 46.32 37.141 46.344 ;
     RECT  36.965 15.504 37.145 17.112 ;
     RECT  37.037 24.864 37.145 28.488 ;
     RECT  37.043 40.368 37.145 43.848 ;
     RECT  37.105 52.992 37.145 54.552 ;
     RECT  36.097 60.432 37.177 60.456 ;
     RECT  35.813 61.632 37.177 62.184 ;
     RECT  36.749 22.704 37.244 23.592 ;
     RECT  37.145 24.864 37.244 28.248 ;
     RECT  37.001 70.128 37.283 83.64 ;
     RECT  36.853 59.424 37.321 59.448 ;
     RECT  37.177 60.432 37.321 62.184 ;
     RECT  37.141 46.32 37.325 46.68 ;
     RECT  37.321 59.424 37.325 62.184 ;
     RECT  37.283 71.664 37.325 83.64 ;
     RECT  37.244 22.704 37.331 28.248 ;
     RECT  37.325 71.664 37.361 71.736 ;
     RECT  37.331 24.864 37.397 28.248 ;
     RECT  37.145 15.984 37.465 17.112 ;
     RECT  37.325 73.248 37.469 73.368 ;
     RECT  37.325 46.32 37.505 46.632 ;
     RECT  36.812 34.944 37.541 37.032 ;
     RECT  37.465 15.984 37.573 17.544 ;
     RECT  35.705 18.72 37.573 21.144 ;
     RECT  36.659 63.6 37.573 64.44 ;
     RECT  37.145 40.368 37.613 41.448 ;
     RECT  37.145 42.528 37.613 43.848 ;
     RECT  36.209 6.768 37.645 6.792 ;
     RECT  37.145 52.992 37.649 54.36 ;
     RECT  37.043 44.976 37.676 45 ;
     RECT  37.573 15.984 37.681 21.144 ;
     RECT  37.541 34.944 37.681 35.304 ;
     RECT  36.245 2.304 37.685 5.688 ;
     RECT  37.681 15.984 37.717 21.288 ;
     RECT  36.605 30.192 37.753 30.408 ;
     RECT  35.548 31.632 37.753 33.624 ;
     RECT  36.209 56.016 37.753 56.04 ;
     RECT  36.925 57.024 37.753 58.008 ;
     RECT  37.397 27.024 37.757 28.248 ;
     RECT  36.821 49.248 37.763 49.416 ;
     RECT  36.425 38.112 37.781 38.52 ;
     RECT  37.781 38.112 37.859 39.384 ;
     RECT  36.205 10.608 37.861 10.632 ;
     RECT  37.859 38.16 37.865 39.384 ;
     RECT  37.613 42.528 37.865 43.8 ;
     RECT  37.753 56.016 37.897 58.008 ;
     RECT  37.573 63.504 37.897 64.44 ;
     RECT  36.659 65.664 37.897 66.888 ;
     RECT  37.325 74.4 37.897 83.64 ;
     RECT  37.645 6.768 37.901 6.84 ;
     RECT  37.283 70.128 37.901 70.152 ;
     RECT  37.613 40.368 37.933 41.064 ;
     RECT  37.897 63.504 37.933 66.888 ;
     RECT  36.821 47.856 37.973 48.168 ;
     RECT  37.325 61.104 37.973 62.184 ;
     RECT  37.621 0.096 38.045 0.12 ;
     RECT  37.397 24.864 38.045 25.992 ;
     RECT  37.897 55.872 38.077 58.008 ;
     RECT  37.325 59.424 38.077 60.024 ;
     RECT  37.933 63.504 38.081 66.984 ;
     RECT  38.113 68.304 38.149 68.328 ;
     RECT  37.933 39.888 38.195 41.064 ;
     RECT  37.685 2.496 38.197 5.688 ;
     RECT  38.081 63.504 38.221 64.728 ;
     RECT  37.901 6.768 38.225 6.792 ;
     RECT  37.861 10.416 38.257 10.632 ;
     RECT  38.081 65.904 38.261 66.984 ;
     RECT  38.077 55.872 38.321 60.024 ;
     RECT  37.973 61.104 38.321 61.752 ;
     RECT  37.331 22.704 38.333 23.4 ;
     RECT  37.649 53.232 38.369 54.36 ;
     RECT  38.221 62.784 38.369 64.728 ;
     RECT  37.865 42.528 38.401 43.608 ;
     RECT  37.717 15.984 38.405 21.672 ;
     RECT  38.333 22.704 38.405 23.304 ;
     RECT  38.321 55.872 38.405 61.752 ;
     RECT  35.381 9.312 38.437 9.336 ;
     RECT  38.257 10.416 38.437 10.824 ;
     RECT  37.361 71.664 38.441 71.688 ;
     RECT  38.437 9.312 38.477 10.824 ;
     RECT  37.897 74.4 38.477 83.784 ;
     RECT  38.477 9.312 38.483 9.672 ;
     RECT  37.043 11.952 38.485 13.752 ;
     RECT  38.477 10.752 38.509 10.824 ;
     RECT  38.485 11.856 38.509 13.752 ;
     RECT  38.405 15.984 38.513 16.92 ;
     RECT  38.261 65.904 38.513 66.936 ;
     RECT  38.483 9.648 38.579 9.672 ;
     RECT  37.681 34.608 38.581 35.304 ;
     RECT  38.581 34.608 38.617 35.352 ;
     RECT  37.541 36.384 38.617 37.032 ;
     RECT  37.763 49.392 38.657 49.416 ;
     RECT  37.676 44.976 38.677 45.72 ;
     RECT  37.753 30.192 38.689 33.624 ;
     RECT  38.677 44.976 38.723 45.96 ;
     RECT  38.369 53.904 38.725 54.36 ;
     RECT  37.717 51.6 38.797 51.624 ;
     RECT  38.509 10.752 38.833 13.752 ;
     RECT  38.725 14.784 38.833 14.808 ;
     RECT  38.405 17.952 38.837 21.672 ;
     RECT  38.761 47.136 38.869 47.16 ;
     RECT  37.973 48.144 38.905 48.168 ;
     RECT  38.405 55.872 38.909 60.024 ;
     RECT  38.689 30.048 38.941 33.624 ;
     RECT  38.725 53.904 38.941 54.552 ;
     RECT  38.909 55.872 38.941 56.04 ;
     RECT  38.617 34.608 38.977 37.032 ;
     RECT  37.865 38.16 38.977 38.76 ;
     RECT  38.905 48.144 38.977 48.408 ;
     RECT  38.045 25.2 39.013 25.992 ;
     RECT  37.757 27.024 39.013 27.912 ;
     RECT  38.723 45.696 39.013 45.96 ;
     RECT  38.869 47.088 39.013 47.16 ;
     RECT  38.797 51.6 39.013 51.768 ;
     RECT  38.977 34.608 39.049 38.76 ;
     RECT  38.195 39.888 39.049 40.824 ;
     RECT  38.617 7.92 39.053 7.944 ;
     RECT  38.941 29.616 39.085 33.624 ;
     RECT  39.049 34.608 39.085 40.824 ;
     RECT  38.197 2.496 39.109 5.784 ;
     RECT  39.013 25.2 39.121 27.912 ;
     RECT  38.401 42.288 39.157 43.608 ;
     RECT  38.149 68.304 39.193 69.288 ;
     RECT  39.109 1.728 39.197 5.784 ;
     RECT  39.121 25.2 39.301 28.008 ;
     RECT  38.833 10.752 39.349 14.808 ;
     RECT  38.513 15.984 39.349 16.056 ;
     RECT  38.405 22.8 39.409 23.304 ;
     RECT  39.013 45.696 39.445 47.16 ;
     RECT  38.977 48.144 39.445 48.504 ;
     RECT  38.405 61.104 39.445 61.752 ;
     RECT  39.193 68.064 39.517 69.288 ;
     RECT  39.445 61.008 39.548 61.752 ;
     RECT  38.369 63.264 39.548 64.728 ;
     RECT  39.301 25.152 39.589 28.008 ;
     RECT  39.013 51.216 39.625 51.768 ;
     RECT  38.909 57.36 39.637 60.024 ;
     RECT  39.548 61.008 39.637 64.728 ;
     RECT  39.197 2.256 39.697 5.784 ;
     RECT  38.977 71.232 39.697 71.256 ;
     RECT  39.589 9.552 39.733 9.576 ;
     RECT  39.085 29.616 39.733 40.824 ;
     RECT  39.157 42 39.733 43.608 ;
     RECT  39.733 9.504 39.841 9.576 ;
     RECT  39.349 10.752 39.841 16.056 ;
     RECT  38.513 65.904 39.841 66.888 ;
     RECT  37.469 73.344 39.841 73.368 ;
     RECT  39.697 71.232 39.877 71.4 ;
     RECT  39.841 72.384 39.877 73.368 ;
     RECT  38.837 17.952 39.913 21.144 ;
     RECT  38.941 53.904 39.913 56.04 ;
     RECT  39.637 57.36 39.913 64.728 ;
     RECT  39.913 53.904 39.949 64.728 ;
     RECT  39.841 65.904 39.96 66.936 ;
     RECT  39.445 45.696 39.985 48.504 ;
     RECT  39.589 25.152 40.021 28.488 ;
     RECT  39.733 29.616 40.021 43.608 ;
     RECT  39.985 45.456 40.021 49.032 ;
     RECT  39.949 53.616 40.021 64.728 ;
     RECT  39.96 65.904 40.021 67.08 ;
     RECT  39.625 51.216 40.031 52.44 ;
     RECT  39.409 22.8 40.069 23.928 ;
     RECT  40.021 29.616 40.069 49.032 ;
     RECT  39.841 9.504 40.093 16.056 ;
     RECT  39.913 17.616 40.093 21.144 ;
     RECT  39.697 2.256 40.129 6.12 ;
     RECT  40.093 9.504 40.129 21.144 ;
     RECT  40.069 22.752 40.129 23.928 ;
     RECT  40.031 50.832 40.165 52.44 ;
     RECT  40.021 53.616 40.165 67.08 ;
     RECT  40.129 2.256 40.208 6.312 ;
     RECT  39.733 7.968 40.208 7.992 ;
     RECT  40.129 9.504 40.208 23.928 ;
     RECT  40.021 25.104 40.208 28.488 ;
     RECT  40.069 29.616 40.208 49.32 ;
     RECT  40.165 50.832 40.208 67.08 ;
     RECT  39.517 68.064 40.208 69.48 ;
     RECT  39.877 71.232 40.208 73.368 ;
     RECT  38.477 74.4 40.208 74.424 ;
     RECT  38.477 76.032 40.208 83.784 ;
     RECT  40.208 2.148 40.312 84.252 ;
     RECT  40.312 2.352 40.504 83.982 ;
     RECT  40.504 26.064 40.565 28.824 ;
     RECT  40.504 68.928 40.601 83.784 ;
     RECT  40.504 51.264 40.637 54.696 ;
     RECT  40.601 68.928 40.637 69.048 ;
     RECT  40.504 7.536 40.643 11.4 ;
     RECT  40.565 26.064 40.643 28.536 ;
     RECT  40.504 33.6 40.673 33.672 ;
     RECT  40.601 70.032 40.739 83.784 ;
     RECT  40.643 27.936 40.781 28.536 ;
     RECT  40.637 68.928 40.781 68.952 ;
     RECT  40.739 70.032 40.781 70.056 ;
     RECT  40.781 27.984 40.883 28.488 ;
     RECT  40.643 26.064 40.889 26.28 ;
     RECT  40.504 34.752 40.925 49.608 ;
     RECT  40.597 0.096 40.961 0.12 ;
     RECT  40.504 13.104 40.961 14.232 ;
     RECT  40.925 34.752 40.997 45.72 ;
     RECT  40.637 54.624 40.997 54.696 ;
     RECT  40.637 51.264 41.033 53.64 ;
     RECT  40.883 27.984 41.069 28.008 ;
     RECT  40.504 17.616 41.105 18.264 ;
     RECT  40.961 13.104 41.141 13.368 ;
     RECT  40.504 16.128 41.141 16.152 ;
     RECT  40.504 19.824 41.177 23.352 ;
     RECT  41.141 13.104 41.213 13.32 ;
     RECT  41.177 20.304 41.213 22.056 ;
     RECT  41.177 23.28 41.249 23.352 ;
     RECT  40.504 66.72 41.249 66.888 ;
     RECT  40.739 71.232 41.315 83.784 ;
     RECT  41.033 51.264 41.321 53.064 ;
     RECT  41.315 71.232 41.356 74.616 ;
     RECT  40.925 46.752 41.357 49.608 ;
     RECT  40.643 7.536 41.497 8.04 ;
     RECT  41.315 75.792 41.501 83.784 ;
     RECT  40.997 35.184 41.52 45.72 ;
     RECT  40.643 9.072 41.548 11.4 ;
     RECT  40.504 2.352 41.557 6.312 ;
     RECT  41.497 7.392 41.557 8.04 ;
     RECT  41.52 44.592 41.603 45.72 ;
     RECT  41.213 13.104 41.605 13.128 ;
     RECT  41.52 35.184 41.645 43.608 ;
     RECT  41.603 44.592 41.681 45.576 ;
     RECT  40.997 54.624 41.749 54.648 ;
     RECT  40.504 24.912 41.753 24.936 ;
     RECT  41.321 51.264 41.753 52.008 ;
     RECT  41.749 54.096 41.789 54.648 ;
     RECT  40.504 56.736 41.857 59.304 ;
     RECT  40.504 60.336 41.857 65.64 ;
     RECT  41.356 71.232 41.996 74.424 ;
     RECT  41.645 35.184 42.001 39.528 ;
     RECT  41.681 44.64 42.005 45.576 ;
     RECT  41.857 56.736 42.037 65.64 ;
     RECT  41.249 66.72 42.037 66.84 ;
     RECT  41.557 2.352 42.065 8.04 ;
     RECT  40.889 26.064 42.109 26.088 ;
     RECT  40.504 30 42.145 30.408 ;
     RECT  42.065 1.728 42.149 8.04 ;
     RECT  41.501 75.792 42.179 83.64 ;
     RECT  41.321 52.992 42.181 53.064 ;
     RECT  41.789 54.096 42.181 54.216 ;
     RECT  41.213 20.304 42.185 21.144 ;
     RECT  42.181 52.992 42.221 54.216 ;
     RECT  42.037 56.736 42.221 66.84 ;
     RECT  41.996 70.512 42.221 74.424 ;
     RECT  41.605 12.528 42.289 13.128 ;
     RECT  41.753 51.744 42.289 52.008 ;
     RECT  42.221 52.992 42.289 54.12 ;
     RECT  42.221 66.72 42.289 66.84 ;
     RECT  41.548 9.072 42.293 9.096 ;
     RECT  42.253 68.928 42.337 68.952 ;
     RECT  42.001 34.992 42.38 39.528 ;
     RECT  41.105 18.24 42.401 18.264 ;
     RECT  42.289 51.744 42.401 54.12 ;
     RECT  41.249 23.28 42.469 23.304 ;
     RECT  41.548 10.128 42.473 11.4 ;
     RECT  40.673 33.6 42.505 33.624 ;
     RECT  42.38 34.752 42.505 39.528 ;
     RECT  42.469 22.8 42.509 23.304 ;
     RECT  42.253 69.984 42.509 70.44 ;
     RECT  42.145 29.904 42.541 30.408 ;
     RECT  41.357 46.752 42.565 48.744 ;
     RECT  42.109 25.632 42.577 26.088 ;
     RECT  41.821 27.072 42.577 27.096 ;
     RECT  42.565 46.08 42.577 48.744 ;
     RECT  42.289 66.72 42.613 67.656 ;
     RECT  42.221 72 42.617 74.424 ;
     RECT  42.577 46.08 42.652 48.984 ;
     RECT  42.001 15.456 42.685 15.816 ;
     RECT  42.613 66.72 42.725 67.8 ;
     RECT  42.617 73.296 42.725 74.424 ;
     RECT  42.541 29.328 42.757 30.408 ;
     RECT  42.179 76.032 42.764 83.64 ;
     RECT  41.645 40.608 42.833 43.608 ;
     RECT  42.764 76.032 42.851 84.024 ;
     RECT  42.221 56.736 42.869 65.64 ;
     RECT  42.509 22.8 42.905 22.824 ;
     RECT  42.577 25.632 42.905 27.096 ;
     RECT  42.505 33.6 42.941 39.528 ;
     RECT  42.86 18.096 42.947 18.12 ;
     RECT  42.185 21.12 42.947 21.144 ;
     RECT  42.685 15.456 42.973 16.344 ;
     RECT  42.905 27.072 42.973 27.096 ;
     RECT  41.893 24.528 42.997 24.552 ;
     RECT  42.905 25.632 42.997 26.088 ;
     RECT  42.973 27.072 43.013 27.336 ;
     RECT  42.757 28.992 43.049 30.408 ;
     RECT  42.577 68.976 43.081 69 ;
     RECT  42.473 11.376 43.085 11.4 ;
     RECT  42.652 46.32 43.121 48.984 ;
     RECT  42.289 12.528 43.157 13.176 ;
     RECT  42.869 62.976 43.157 65.64 ;
     RECT  42.997 24.528 43.187 26.088 ;
     RECT  43.1 28.32 43.187 28.344 ;
     RECT  40.504 31.872 43.187 31.896 ;
     RECT  43.121 46.752 43.189 48.984 ;
     RECT  41.641 50.112 43.189 50.136 ;
     RECT  42.865 51.36 43.189 51.384 ;
     RECT  43.187 24.528 43.193 25.656 ;
     RECT  43.157 62.976 43.193 65.496 ;
     RECT  42.617 72 43.193 72.024 ;
     RECT  42.149 2.256 43.261 8.04 ;
     RECT  43.193 24.528 43.265 24.552 ;
     RECT  42.851 76.032 43.297 83.64 ;
     RECT  43.157 12.528 43.301 13.128 ;
     RECT  43.261 2.256 43.333 8.76 ;
     RECT  42.473 10.128 43.333 10.152 ;
     RECT  42.833 42.528 43.337 43.608 ;
     RECT  43.193 63.456 43.373 65.496 ;
     RECT  42.941 33.6 43.405 33.624 ;
     RECT  42.725 73.392 43.441 74.424 ;
     RECT  43.297 75.6 43.441 83.64 ;
     RECT  43.081 68.976 43.481 69.096 ;
     RECT  42.973 15.456 43.505 17.112 ;
     RECT  42.509 70.416 43.513 70.44 ;
     RECT  43.505 14.832 43.525 17.112 ;
     RECT  42.941 34.608 43.553 39.528 ;
     RECT  42.005 44.64 43.621 44.808 ;
     RECT  43.553 34.608 43.625 39.48 ;
     RECT  43.373 63.456 43.625 65.448 ;
     RECT  43.513 69.984 43.661 70.44 ;
     RECT  43.613 0.096 43.697 0.12 ;
     RECT  43.193 25.632 43.697 25.656 ;
     RECT  43.189 46.752 43.697 51.384 ;
     RECT  42.869 56.736 43.729 61.416 ;
     RECT  42.725 67.536 43.765 67.8 ;
     RECT  43.481 68.976 43.805 69 ;
     RECT  43.337 42.528 43.837 42.6 ;
     RECT  42.401 52.512 43.873 54.12 ;
     RECT  43.333 2.256 43.907 10.152 ;
     RECT  43.765 67.008 43.909 67.8 ;
     RECT  43.907 2.256 43.949 7.944 ;
     RECT  43.013 27.312 43.949 27.336 ;
     RECT  43.661 69.984 43.985 70.104 ;
     RECT  43.907 9.312 44.017 10.152 ;
     RECT  43.621 44.64 44.021 45.72 ;
     RECT  43.909 66.624 44.021 67.8 ;
     RECT  43.957 68.88 44.044 68.904 ;
     RECT  43.301 13.104 44.057 13.128 ;
     RECT  44.021 67.008 44.093 67.8 ;
     RECT  43.337 43.584 44.125 43.608 ;
     RECT  44.021 44.64 44.125 45.528 ;
     RECT  43.697 46.752 44.165 48.504 ;
     RECT  43.697 49.536 44.165 51.384 ;
     RECT  43.049 29.904 44.197 30.408 ;
     RECT  43.873 52.512 44.197 54.696 ;
     RECT  43.729 56.496 44.197 61.416 ;
     RECT  43.985 70.08 44.201 70.104 ;
     RECT  42.833 40.608 44.233 41.112 ;
     RECT  43.837 42.288 44.233 42.6 ;
     RECT  44.197 29.04 44.237 30.408 ;
     RECT  44.197 52.512 44.273 61.416 ;
     RECT  43.441 73.392 44.273 83.64 ;
     RECT  44.233 40.608 44.305 42.6 ;
     RECT  44.125 43.584 44.305 45.528 ;
     RECT  44.165 50.736 44.345 51.384 ;
     RECT  44.237 30.384 44.377 30.408 ;
     RECT  44.273 53.808 44.396 61.416 ;
     RECT  42.325 19.344 44.437 19.368 ;
     RECT  44.396 53.808 44.437 62.328 ;
     RECT  43.625 63.456 44.437 64.968 ;
     RECT  44.377 30.384 44.449 30.648 ;
     RECT  43.525 14.688 44.453 17.112 ;
     RECT  43.405 33.024 44.453 33.624 ;
     RECT  44.437 19.344 44.483 19.992 ;
     RECT  44.437 53.808 44.483 64.968 ;
     RECT  44.453 14.688 44.489 14.712 ;
     RECT  44.453 15.696 44.525 17.112 ;
     RECT  44.161 18.24 44.525 18.264 ;
     RECT  44.273 52.512 44.525 52.728 ;
     RECT  43.837 11.52 44.557 11.544 ;
     RECT  44.305 40.608 44.593 45.528 ;
     RECT  44.483 53.808 44.597 60.696 ;
     RECT  44.093 67.776 44.597 67.8 ;
     RECT  44.521 22.608 44.917 22.92 ;
     RECT  43.949 2.352 44.989 7.944 ;
     RECT  44.989 2.352 45.025 7.992 ;
     RECT  44.953 70.608 45.025 70.632 ;
     RECT  43.981 71.616 45.025 71.64 ;
     RECT  44.483 19.968 45.061 19.992 ;
     RECT  44.737 25.728 45.061 25.752 ;
     RECT  44.483 63.264 45.061 64.968 ;
     RECT  44.273 74.064 45.061 83.64 ;
     RECT  45.125 68.352 45.157 68.376 ;
     RECT  44.017 9.312 45.169 10.536 ;
     RECT  44.557 11.52 45.169 12.504 ;
     RECT  45.157 68.352 45.205 69 ;
     RECT  44.449 30.384 45.241 30.744 ;
     RECT  44.237 29.04 45.277 29.064 ;
     RECT  44.597 53.808 45.277 55.56 ;
     RECT  45.025 2.256 45.349 7.992 ;
     RECT  45.241 30.24 45.349 30.744 ;
     RECT  44.345 50.736 45.385 50.76 ;
     RECT  45.061 74.064 45.421 83.784 ;
     RECT  44.593 39.84 45.457 45.528 ;
     RECT  44.917 22.608 45.493 23.064 ;
     RECT  45.109 0.096 45.497 0.12 ;
     RECT  45.493 22.608 45.529 23.112 ;
     RECT  45.385 50.544 45.565 50.76 ;
     RECT  44.989 52.224 45.565 52.248 ;
     RECT  45.061 19.968 45.601 20.904 ;
     RECT  45.349 2.256 45.608 8.184 ;
     RECT  45.169 9.312 45.608 12.504 ;
     RECT  44.525 15.984 45.608 17.112 ;
     RECT  44.665 18.528 45.608 18.84 ;
     RECT  45.601 19.968 45.608 21.24 ;
     RECT  45.529 22.608 45.608 23.304 ;
     RECT  45.061 25.728 45.608 26.616 ;
     RECT  45.277 28.944 45.608 29.064 ;
     RECT  45.349 30.048 45.608 30.744 ;
     RECT  45.565 32.496 45.608 32.52 ;
     RECT  44.453 33.6 45.608 33.624 ;
     RECT  43.625 34.608 45.608 38.808 ;
     RECT  45.457 39.84 45.608 46.008 ;
     RECT  44.165 47.28 45.608 48.504 ;
     RECT  44.165 49.536 45.608 49.56 ;
     RECT  45.565 50.544 45.608 52.248 ;
     RECT  45.277 53.568 45.608 55.56 ;
     RECT  44.597 56.64 45.608 60.696 ;
     RECT  44.483 62.016 45.608 62.04 ;
     RECT  45.061 63.264 45.608 65.16 ;
     RECT  45.205 68.352 45.608 69.384 ;
     RECT  45.025 70.608 45.608 71.64 ;
     RECT  45.385 72.96 45.608 72.984 ;
     RECT  45.421 74.064 45.608 83.832 ;
     RECT  45.608 2.148 45.712 84.252 ;
     RECT  45.712 2.148 45.904 83.982 ;
     RECT  45.904 34.8 45.965 38.904 ;
     RECT  45.904 33.552 46.001 33.624 ;
     RECT  45.904 56.976 46.037 71.208 ;
     RECT  45.904 20.544 46.067 28.968 ;
     RECT  46.037 56.976 46.067 61.128 ;
     RECT  46.067 20.544 46.073 21.816 ;
     RECT  45.904 52.944 46.073 55.56 ;
     RECT  45.904 40.368 46.145 44.184 ;
     RECT  46.067 56.976 46.145 60.312 ;
     RECT  46.037 62.208 46.163 71.208 ;
     RECT  46.163 65.664 46.204 71.208 ;
     RECT  45.904 30.048 46.253 32.52 ;
     RECT  46.073 21.792 46.289 21.816 ;
     RECT  45.904 45.552 46.289 46.008 ;
     RECT  45.904 50.544 46.289 51.48 ;
     RECT  46.204 65.664 46.361 66.504 ;
     RECT  46.204 67.824 46.361 71.208 ;
     RECT  46.361 65.664 46.397 65.688 ;
     RECT  45.904 2.148 46.433 6.648 ;
     RECT  46.361 69.648 46.541 71.208 ;
     RECT  46.433 2.148 46.565 6.6 ;
     RECT  46.073 52.944 46.577 55.464 ;
     RECT  45.904 72.192 46.613 83.832 ;
     RECT  46.565 1.728 46.649 6.6 ;
     RECT  45.904 10.128 46.649 13.608 ;
     RECT  46.577 55.248 46.721 55.464 ;
     RECT  46.613 75.024 46.793 83.832 ;
     RECT  46.067 22.848 46.801 28.968 ;
     RECT  46.721 55.44 46.829 55.464 ;
     RECT  46.541 69.648 46.883 70.824 ;
     RECT  46.883 70.128 46.901 70.824 ;
     RECT  45.965 34.8 46.933 35.208 ;
     RECT  45.904 15.504 46.969 16.008 ;
     RECT  45.904 17.424 46.969 18.744 ;
     RECT  46.145 42.528 46.969 44.184 ;
     RECT  46.289 45.552 46.969 45.672 ;
     RECT  46.577 52.944 46.969 53.976 ;
     RECT  45.904 8.112 46.973 8.712 ;
     RECT  46.969 15.504 47.009 18.744 ;
     RECT  46.801 28.176 47.041 28.968 ;
     RECT  46.253 30.288 47.041 32.52 ;
     RECT  46.001 33.552 47.041 33.576 ;
     RECT  45.904 47.328 47.113 48.696 ;
     RECT  46.145 57.072 47.149 60.312 ;
     RECT  47.009 16.512 47.153 18.744 ;
     RECT  47.041 28.176 47.153 29.064 ;
     RECT  47.149 57.072 47.153 60.888 ;
     RECT  46.613 72.288 47.225 73.848 ;
     RECT  47.113 47.328 47.257 48.936 ;
     RECT  47.153 60.864 47.257 60.888 ;
     RECT  46.163 62.208 47.257 64.44 ;
     RECT  46.649 10.128 47.293 12.456 ;
     RECT  46.361 67.824 47.317 68.664 ;
     RECT  46.969 42.528 47.333 45.672 ;
     RECT  47.257 47.28 47.365 48.936 ;
     RECT  47.317 67.152 47.405 68.664 ;
     RECT  46.289 50.544 47.437 50.568 ;
     RECT  47.041 30.288 47.441 33.576 ;
     RECT  46.969 52.56 47.473 53.976 ;
     RECT  47.437 50.112 47.509 50.568 ;
     RECT  47.473 51.888 47.509 53.976 ;
     RECT  47.405 67.344 47.509 68.664 ;
     RECT  46.901 70.128 47.513 70.296 ;
     RECT  45.965 36.528 47.545 38.904 ;
     RECT  46.145 40.368 47.545 41.448 ;
     RECT  47.333 42.528 47.545 45.048 ;
     RECT  47.545 36.528 47.555 45.048 ;
     RECT  47.257 60.864 47.585 64.44 ;
     RECT  47.509 50.112 47.651 53.976 ;
     RECT  47.651 50.112 47.693 50.856 ;
     RECT  47.441 30.288 47.725 33.192 ;
     RECT  47.293 9.696 47.756 12.456 ;
     RECT  46.801 22.848 47.761 27.096 ;
     RECT  47.756 9.696 47.843 12.552 ;
     RECT  46.793 75.024 47.869 83.592 ;
     RECT  47.725 29.328 47.891 33.192 ;
     RECT  46.973 8.112 47.893 8.424 ;
     RECT  47.843 9.696 47.909 11.976 ;
     RECT  47.585 60.864 47.909 60.888 ;
     RECT  47.651 51.888 48.017 53.976 ;
     RECT  46.649 2.352 48.085 6.6 ;
     RECT  47.761 22.752 48.085 27.096 ;
     RECT  47.365 46.704 48.085 48.936 ;
     RECT  48.085 1.728 48.121 6.6 ;
     RECT  46.649 13.584 48.125 13.608 ;
     RECT  48.085 46.224 48.161 48.936 ;
     RECT  48.161 47.328 48.197 48.936 ;
     RECT  48.085 22.464 48.229 27.096 ;
     RECT  47.153 28.176 48.229 28.2 ;
     RECT  47.555 36.528 48.305 44.904 ;
     RECT  47.893 7.968 48.371 8.424 ;
     RECT  47.009 15.504 48.373 15.528 ;
     RECT  47.153 16.512 48.373 16.536 ;
     RECT  47.225 72.288 48.373 73.416 ;
     RECT  47.869 74.592 48.373 83.592 ;
     RECT  46.073 20.544 48.409 20.568 ;
     RECT  48.017 53.808 48.409 53.976 ;
     RECT  48.121 1.728 48.413 6.84 ;
     RECT  48.305 36.528 48.413 44.472 ;
     RECT  47.891 31.776 48.421 33.192 ;
     RECT  46.933 34.8 48.421 35.448 ;
     RECT  48.421 31.776 48.467 35.448 ;
     RECT  48.265 14.208 48.481 14.28 ;
     RECT  48.373 15.504 48.481 16.536 ;
     RECT  47.509 67.344 48.481 68.808 ;
     RECT  47.617 65.808 48.485 65.832 ;
     RECT  48.413 37.008 48.508 44.472 ;
     RECT  48.229 22.464 48.515 28.2 ;
     RECT  48.481 67.248 48.521 68.808 ;
     RECT  47.153 17.616 48.553 18.744 ;
     RECT  48.409 20.064 48.553 20.568 ;
     RECT  48.515 22.464 48.553 27.912 ;
     RECT  48.467 31.776 48.557 33.912 ;
     RECT  47.153 57.072 48.589 59.496 ;
     RECT  47.585 62.208 48.593 64.44 ;
     RECT  47.513 70.272 48.593 70.296 ;
     RECT  48.413 2.352 48.661 6.84 ;
     RECT  48.521 68.352 48.661 68.808 ;
     RECT  48.593 62.448 48.733 64.44 ;
     RECT  48.661 68.352 48.733 68.904 ;
     RECT  48.197 48.912 48.769 48.936 ;
     RECT  48.373 72.048 48.769 83.592 ;
     RECT  48.553 17.616 48.773 20.568 ;
     RECT  47.909 9.696 48.805 11.496 ;
     RECT  48.805 9.552 48.841 11.496 ;
     RECT  48.841 8.688 48.845 11.496 ;
     RECT  48.508 39.84 48.845 44.472 ;
     RECT  48.409 53.808 48.845 54.936 ;
     RECT  47.891 29.328 48.877 30.696 ;
     RECT  48.553 21.744 48.925 27.912 ;
     RECT  48.877 61.152 48.949 61.176 ;
     RECT  48.769 71.952 48.985 83.592 ;
     RECT  48.481 14.208 49.057 16.536 ;
     RECT  48.773 17.616 49.057 17.64 ;
     RECT  49.057 14.208 49.093 17.64 ;
     RECT  49.093 13.632 49.097 17.64 ;
     RECT  48.017 51.888 49.097 52.584 ;
     RECT  48.733 62.448 49.097 64.968 ;
     RECT  48.508 37.008 49.133 38.808 ;
     RECT  48.985 71.808 49.133 83.592 ;
     RECT  48.845 8.688 49.169 11.208 ;
     RECT  49.097 13.632 49.169 14.856 ;
     RECT  49.133 71.808 49.237 74.04 ;
     RECT  48.161 46.224 49.273 46.248 ;
     RECT  48.197 47.328 49.273 47.352 ;
     RECT  48.877 29.328 49.277 31.176 ;
     RECT  48.557 32.352 49.313 33.912 ;
     RECT  48.589 56.448 49.345 59.496 ;
     RECT  48.845 39.84 49.349 41.256 ;
     RECT  48.845 42.528 49.381 44.472 ;
     RECT  49.097 16.128 49.385 17.64 ;
     RECT  49.273 46.224 49.421 47.352 ;
     RECT  49.133 75.12 49.421 83.592 ;
     RECT  47.693 50.832 49.453 50.856 ;
     RECT  49.349 39.84 49.457 41.16 ;
     RECT  49.453 50.16 49.477 50.856 ;
     RECT  49.097 51.888 49.477 51.912 ;
     RECT  49.477 50.16 49.523 51.912 ;
     RECT  49.169 13.632 49.525 14.808 ;
     RECT  49.277 30.288 49.525 31.176 ;
     RECT  49.313 32.352 49.525 32.808 ;
     RECT  49.345 56.352 49.525 59.496 ;
     RECT  49.385 16.512 49.571 17.64 ;
     RECT  49.133 37.44 49.601 38.808 ;
     RECT  48.661 2.352 49.621 7.464 ;
     RECT  48.949 61.152 49.621 61.272 ;
     RECT  48.773 18.816 49.637 20.568 ;
     RECT  49.421 47.328 49.637 47.352 ;
     RECT  49.381 42.528 49.673 44.616 ;
     RECT  48.769 48.912 49.741 48.984 ;
     RECT  49.523 50.16 49.741 51.288 ;
     RECT  48.733 68.352 49.765 69.768 ;
     RECT  49.525 13.152 49.781 14.808 ;
     RECT  48.925 25.104 49.781 27.912 ;
     RECT  48.521 67.248 49.781 67.368 ;
     RECT  49.637 18.816 49.813 18.84 ;
     RECT  49.169 9.552 49.817 11.208 ;
     RECT  49.097 62.496 49.849 64.968 ;
     RECT  49.765 68.352 49.852 70.44 ;
     RECT  49.621 60.96 49.853 61.272 ;
     RECT  49.237 71.472 49.853 74.04 ;
     RECT  49.457 40.416 49.859 41.16 ;
     RECT  49.741 48.912 49.859 51.288 ;
     RECT  48.845 54.912 49.861 54.936 ;
     RECT  49.525 56.352 49.861 59.832 ;
     RECT  49.813 18.672 49.889 18.84 ;
     RECT  48.845 53.808 49.889 53.832 ;
     RECT  49.637 20.064 49.957 20.568 ;
     RECT  48.925 21.744 49.957 24.12 ;
     RECT  49.571 16.8 49.961 17.64 ;
     RECT  49.859 40.896 49.961 41.16 ;
     RECT  49.849 62.496 50.003 65.352 ;
     RECT  49.817 9.648 50.029 11.208 ;
     RECT  49.621 1.728 50.033 7.464 ;
     RECT  50.029 9.648 50.101 11.88 ;
     RECT  49.781 13.152 50.101 14.76 ;
     RECT  49.957 20.064 50.101 24.12 ;
     RECT  49.781 25.104 50.101 27.864 ;
     RECT  49.421 81.648 50.173 83.592 ;
     RECT  49.961 40.992 50.317 41.16 ;
     RECT  49.673 42.528 50.317 43.896 ;
     RECT  49.861 54.912 50.461 59.832 ;
     RECT  49.781 67.344 50.497 67.368 ;
     RECT  49.852 68.352 50.497 70.104 ;
     RECT  49.525 30.288 50.533 32.808 ;
     RECT  49.313 33.792 50.533 33.912 ;
     RECT  49.961 16.848 50.581 17.64 ;
     RECT  49.889 18.672 50.581 18.696 ;
     RECT  50.533 30.288 50.605 33.912 ;
     RECT  49.853 73.104 50.677 74.04 ;
     RECT  49.421 75.12 50.677 79.992 ;
     RECT  48.467 35.328 50.713 35.448 ;
     RECT  50.713 34.944 50.725 35.448 ;
     RECT  50.605 30.144 50.741 33.912 ;
     RECT  50.317 29.04 50.749 29.064 ;
     RECT  50.741 30.096 50.749 33.912 ;
     RECT  50.725 34.944 50.749 35.928 ;
     RECT  49.601 37.44 50.749 37.656 ;
     RECT  49.601 38.784 50.749 38.808 ;
     RECT  49.421 46.224 50.749 46.248 ;
     RECT  50.029 53.52 50.857 53.544 ;
     RECT  50.173 81.648 50.857 83.64 ;
     RECT  50.101 9.648 50.869 14.76 ;
     RECT  49.853 61.248 50.869 61.272 ;
     RECT  50.581 16.848 50.893 18.696 ;
     RECT  50.101 20.064 50.893 27.864 ;
     RECT  50.749 29.04 50.965 33.912 ;
     RECT  50.749 34.944 50.965 37.656 ;
     RECT  50.033 2.352 51.008 7.464 ;
     RECT  50.869 8.832 51.008 14.76 ;
     RECT  50.893 16.848 51.008 27.864 ;
     RECT  50.965 29.04 51.008 37.656 ;
     RECT  50.749 38.688 51.008 38.808 ;
     RECT  50.317 40.992 51.008 43.896 ;
     RECT  49.813 44.928 51.008 44.952 ;
     RECT  50.749 46.224 51.008 46.824 ;
     RECT  50.569 47.856 51.008 47.88 ;
     RECT  49.859 49.152 51.008 51.288 ;
     RECT  50.857 52.704 51.008 53.544 ;
     RECT  50.461 54.624 51.008 59.832 ;
     RECT  50.869 60.816 51.008 61.272 ;
     RECT  50.003 62.544 51.008 65.352 ;
     RECT  50.497 67.344 51.008 70.104 ;
     RECT  49.853 71.472 51.008 71.976 ;
     RECT  50.677 73.104 51.008 79.992 ;
     RECT  50.857 81.648 51.008 83.784 ;
     RECT  51.008 2.148 51.101 84.252 ;
     RECT  51.101 1.728 51.112 84.252 ;
     RECT  51.112 1.728 51.185 83.982 ;
     RECT  51.185 2.352 51.304 83.982 ;
     RECT  51.304 64.32 51.329 67.368 ;
     RECT  51.304 46.8 51.437 47.88 ;
     RECT  51.304 13.536 51.443 14.616 ;
     RECT  51.304 17.712 51.443 20.616 ;
     RECT  51.304 54.048 51.473 60.888 ;
     RECT  51.443 19.968 51.481 20.616 ;
     RECT  51.304 28.656 51.491 36.024 ;
     RECT  51.443 17.712 51.653 18.84 ;
     RECT  51.473 57.024 51.725 60.888 ;
     RECT  51.304 74.112 51.761 80.52 ;
     RECT  51.725 57.024 51.797 60.552 ;
     RECT  51.443 13.536 51.905 13.704 ;
     RECT  51.304 37.44 52.049 37.464 ;
     RECT  51.304 62.544 52.163 63.336 ;
     RECT  51.797 57.024 52.229 60.12 ;
     RECT  51.304 2.352 52.297 7.704 ;
     RECT  51.304 23.328 52.297 23.352 ;
     RECT  51.304 24.384 52.297 24.408 ;
     RECT  51.761 80.496 52.297 80.52 ;
     RECT  51.304 81.648 52.297 83.784 ;
     RECT  51.304 8.832 52.301 12.504 ;
     RECT  51.304 71.952 52.369 72.84 ;
     RECT  51.761 74.112 52.369 79.272 ;
     RECT  51.304 21.648 52.405 22.104 ;
     RECT  51.304 25.824 52.405 27.624 ;
     RECT  51.491 30.288 52.405 36.024 ;
     RECT  51.304 50.928 52.405 53.016 ;
     RECT  51.473 54.048 52.405 55.704 ;
     RECT  51.329 64.32 52.405 66.504 ;
     RECT  52.405 50.928 52.451 55.704 ;
     RECT  51.304 68.4 52.451 70.296 ;
     RECT  51.905 13.584 52.477 13.704 ;
     RECT  52.405 25.632 52.477 27.624 ;
     RECT  51.491 28.656 52.477 29.112 ;
     RECT  51.304 43.584 52.481 44.52 ;
     RECT  52.369 74.016 52.481 79.272 ;
     RECT  51.481 20.592 52.513 20.616 ;
     RECT  52.405 21.648 52.513 22.2 ;
     RECT  51.437 47.568 52.517 47.88 ;
     RECT  52.451 50.928 52.553 53.592 ;
     RECT  52.297 23.328 52.585 24.408 ;
     RECT  52.517 47.568 52.585 47.592 ;
     RECT  52.297 2.352 52.597 7.752 ;
     RECT  51.304 49.008 52.604 49.224 ;
     RECT  51.653 18.192 52.625 18.84 ;
     RECT  52.553 51.264 52.625 53.592 ;
     RECT  52.513 20.592 52.657 22.2 ;
     RECT  52.585 23.328 52.657 24.504 ;
     RECT  52.369 71.424 52.657 72.84 ;
     RECT  52.405 30.288 52.661 36.744 ;
     RECT  52.163 62.544 52.693 62.664 ;
     RECT  52.405 64.32 52.693 66.696 ;
     RECT  52.229 57.024 52.729 59.832 ;
     RECT  52.597 1.728 52.769 7.752 ;
     RECT  51.304 40.416 52.789 42.6 ;
     RECT  52.625 18.528 52.796 18.84 ;
     RECT  52.477 13.584 52.801 14.472 ;
     RECT  52.729 45.6 52.801 45.624 ;
     RECT  52.297 80.496 52.805 83.784 ;
     RECT  52.796 18.528 52.837 19.128 ;
     RECT  52.657 20.592 52.837 24.504 ;
     RECT  52.451 54.72 52.841 54.984 ;
     RECT  52.693 64.32 52.877 67.272 ;
     RECT  52.805 83.232 52.877 83.784 ;
     RECT  52.657 71.424 52.913 72.936 ;
     RECT  52.877 83.76 52.913 83.784 ;
     RECT  52.451 70.272 52.94 70.296 ;
     RECT  52.913 71.424 52.94 71.976 ;
     RECT  52.837 18.528 52.949 24.504 ;
     RECT  52.477 25.632 52.949 29.112 ;
     RECT  52.481 79.008 52.981 79.272 ;
     RECT  52.805 80.496 52.981 82.104 ;
     RECT  52.949 28.272 52.985 29.112 ;
     RECT  52.789 39.888 52.985 42.6 ;
     RECT  52.451 68.4 52.985 68.952 ;
     RECT  52.481 74.016 52.985 77.928 ;
     RECT  52.801 13.584 53.021 15.384 ;
     RECT  52.661 34.176 53.027 36.744 ;
     RECT  52.981 79.008 53.027 82.104 ;
     RECT  52.729 56.496 53.057 59.832 ;
     RECT  52.949 23.856 53.093 24.504 ;
     RECT  52.841 54.96 53.093 54.984 ;
     RECT  53.027 79.008 53.093 82.008 ;
     RECT  53.027 34.512 53.125 36.744 ;
     RECT  52.661 30.288 53.161 32.856 ;
     RECT  53.125 34.512 53.165 37.656 ;
     RECT  53.057 58.08 53.165 59.832 ;
     RECT  53.093 79.008 53.201 80.52 ;
     RECT  53.093 23.904 53.228 24.504 ;
     RECT  52.949 25.632 53.228 27.192 ;
     RECT  52.693 61.584 53.233 62.664 ;
     RECT  52.94 70.272 53.309 71.976 ;
     RECT  53.228 23.904 53.356 27.192 ;
     RECT  53.233 61.008 53.449 62.664 ;
     RECT  52.585 46.656 53.516 47.592 ;
     RECT  52.604 48.624 53.516 49.224 ;
     RECT  52.877 64.368 53.521 67.272 ;
     RECT  53.356 24.192 53.525 27.192 ;
     RECT  52.985 40.368 53.557 42.6 ;
     RECT  52.481 43.584 53.557 43.608 ;
     RECT  53.057 56.496 53.557 57.048 ;
     RECT  52.625 51.264 53.561 53.064 ;
     RECT  52.801 44.736 53.564 45.624 ;
     RECT  53.516 46.656 53.564 49.224 ;
     RECT  53.561 52.176 53.597 53.064 ;
     RECT  53.564 44.736 53.603 49.224 ;
     RECT  53.021 13.68 53.605 15.384 ;
     RECT  52.949 18.528 53.605 22.248 ;
     RECT  53.605 17.04 53.633 22.248 ;
     RECT  53.521 64.368 53.633 67.752 ;
     RECT  53.605 13.68 53.651 16.008 ;
     RECT  53.557 40.368 53.651 43.608 ;
     RECT  53.651 15.984 53.692 16.008 ;
     RECT  53.651 40.368 53.705 41.256 ;
     RECT  52.985 74.016 53.705 75.24 ;
     RECT  52.985 76.416 53.705 77.928 ;
     RECT  53.603 44.736 53.795 46.2 ;
     RECT  53.603 48.48 53.845 49.224 ;
     RECT  53.795 44.736 53.885 46.152 ;
     RECT  53.161 29.808 53.917 32.856 ;
     RECT  53.165 34.512 53.957 36.024 ;
     RECT  53.881 38.784 53.965 38.808 ;
     RECT  52.985 28.272 53.989 28.296 ;
     RECT  53.651 42.528 53.989 43.608 ;
     RECT  53.885 44.736 53.989 44.76 ;
     RECT  52.301 8.976 53.993 12.504 ;
     RECT  53.845 48.48 53.993 49.992 ;
     RECT  53.449 61.008 54.025 63.336 ;
     RECT  53.633 64.368 54.025 65.16 ;
     RECT  52.769 2.544 54.053 7.752 ;
     RECT  53.525 26.64 54.061 27.192 ;
     RECT  53.989 28.272 54.061 28.824 ;
     RECT  54.061 26.64 54.097 28.824 ;
     RECT  53.917 29.808 54.097 33.048 ;
     RECT  54.053 1.728 54.133 7.752 ;
     RECT  53.309 71.424 54.133 71.976 ;
     RECT  53.705 74.016 54.133 75.144 ;
     RECT  54.133 1.728 54.137 7.944 ;
     RECT  53.633 19.488 54.173 22.248 ;
     RECT  53.597 52.464 54.173 53.064 ;
     RECT  53.201 79.008 54.173 80.184 ;
     RECT  53.603 47.28 54.209 47.304 ;
     RECT  53.093 81.888 54.209 82.008 ;
     RECT  54.061 54.096 54.236 54.12 ;
     RECT  53.557 55.584 54.236 57.048 ;
     RECT  54.209 81.888 54.245 81.912 ;
     RECT  52.985 68.928 54.277 68.952 ;
     RECT  53.309 70.272 54.277 70.296 ;
     RECT  54.173 52.464 54.281 52.488 ;
     RECT  54.137 2.544 54.317 7.944 ;
     RECT  54.133 73.536 54.317 75.144 ;
     RECT  54.025 61.008 54.353 65.16 ;
     RECT  54.277 68.928 54.373 70.296 ;
     RECT  54.133 71.424 54.373 72.36 ;
     RECT  53.525 24.192 54.385 25.656 ;
     RECT  53.633 66.48 54.419 67.752 ;
     RECT  54.173 80.16 54.419 80.184 ;
     RECT  54.236 54.096 54.421 57.048 ;
     RECT  53.993 9.984 54.425 12.504 ;
     RECT  54.097 26.64 54.524 33.048 ;
     RECT  53.957 34.512 54.524 35.88 ;
     RECT  54.173 19.968 54.533 22.248 ;
     RECT  53.993 48.672 54.565 49.992 ;
     RECT  54.421 53.76 54.601 57.048 ;
     RECT  53.165 58.08 54.601 59.16 ;
     RECT  53.705 40.848 54.637 41.256 ;
     RECT  53.989 42.528 54.637 44.76 ;
     RECT  54.637 40.848 54.641 44.76 ;
     RECT  54.317 73.584 54.705 75.144 ;
     RECT  53.633 17.04 54.713 17.832 ;
     RECT  53.165 37.632 54.713 37.656 ;
     RECT  53.705 76.464 54.713 77.928 ;
     RECT  54.373 68.928 54.748 72.36 ;
     RECT  54.601 53.76 54.749 59.16 ;
     RECT  54.353 61.008 54.749 62.568 ;
     RECT  53.885 46.128 54.781 46.152 ;
     RECT  54.385 24.048 54.785 25.656 ;
     RECT  54.713 76.512 54.785 77.928 ;
     RECT  54.457 83.664 54.785 83.688 ;
     RECT  54.637 39.84 54.821 39.864 ;
     RECT  53.993 8.976 54.857 9 ;
     RECT  54.713 17.568 54.997 17.832 ;
     RECT  54.817 80.64 54.997 80.664 ;
     RECT  54.524 26.64 55.037 35.88 ;
     RECT  55.037 30.336 55.069 35.88 ;
     RECT  54.997 80.64 55.069 80.808 ;
     RECT  54.317 7.344 55.105 7.944 ;
     RECT  54.425 9.984 55.105 10.968 ;
     RECT  54.785 76.752 55.105 77.928 ;
     RECT  54.173 79.008 55.105 79.032 ;
     RECT  55.037 26.64 55.145 29.304 ;
     RECT  54.533 19.968 55.253 22.104 ;
     RECT  54.641 40.848 55.253 43.608 ;
     RECT  54.785 24.144 55.283 25.656 ;
     RECT  55.069 30.336 55.283 36.648 ;
     RECT  55.105 7.344 55.325 7.992 ;
     RECT  55.145 26.736 55.325 29.304 ;
     RECT  54.419 66.48 55.325 67.272 ;
     RECT  54.748 68.928 55.325 72.408 ;
     RECT  54.425 12.48 55.357 12.504 ;
     RECT  53.651 13.68 55.357 14.904 ;
     RECT  55.253 19.968 55.397 20.136 ;
     RECT  54.317 2.544 55.429 6.168 ;
     RECT  55.325 7.344 55.429 7.944 ;
     RECT  54.997 17.568 55.43 18.792 ;
     RECT  54.641 44.736 55.433 44.76 ;
     RECT  54.353 63.792 55.433 65.16 ;
     RECT  55.105 9.6 55.465 10.968 ;
     RECT  55.357 12.48 55.465 14.904 ;
     RECT  54.749 61.632 55.465 62.568 ;
     RECT  55.069 80.64 55.537 80.904 ;
     RECT  54.705 74.64 55.645 75.144 ;
     RECT  55.537 80.64 55.717 81.096 ;
     RECT  54.781 46.128 55.82 46.2 ;
     RECT  55.717 80.64 55.825 81.384 ;
     RECT  55.621 0.576 55.829 0.6 ;
     RECT  55.429 2.544 55.861 7.944 ;
     RECT  55.283 24.144 55.861 24.552 ;
     RECT  55.105 76.752 55.897 79.032 ;
     RECT  55.433 64.656 55.933 65.16 ;
     RECT  55.325 66.48 55.933 67.032 ;
     RECT  55.897 76.752 56.041 79.08 ;
     RECT  55.825 80.592 56.041 81.384 ;
     RECT  55.82 44.976 56.077 46.2 ;
     RECT  55.717 53.28 56.077 53.304 ;
     RECT  54.749 54.624 56.077 59.16 ;
     RECT  55.465 61.632 56.077 62.76 ;
     RECT  55.753 38.784 56.113 38.808 ;
     RECT  55.43 17.616 56.149 18.792 ;
     RECT  56.077 61.2 56.185 62.76 ;
     RECT  56.041 80.304 56.185 81.384 ;
     RECT  55.397 20.112 56.293 20.136 ;
     RECT  55.253 21.744 56.293 22.104 ;
     RECT  55.325 26.736 56.293 27.192 ;
     RECT  55.253 42.576 56.293 43.608 ;
     RECT  55.933 64.656 56.293 67.032 ;
     RECT  55.325 69.456 56.293 72.408 ;
     RECT  54.705 73.584 56.293 73.608 ;
     RECT  56.041 76.752 56.293 79.224 ;
     RECT  56.185 80.256 56.293 81.384 ;
     RECT  55.325 28.272 56.401 29.304 ;
     RECT  55.283 30.336 56.401 34.968 ;
     RECT  55.861 2.256 56.408 7.944 ;
     RECT  55.465 9.6 56.408 14.904 ;
     RECT  56.149 17.616 56.408 18.984 ;
     RECT  56.293 20.112 56.408 22.104 ;
     RECT  55.933 23.088 56.408 23.112 ;
     RECT  55.861 24.096 56.408 24.552 ;
     RECT  55.283 25.632 56.408 25.656 ;
     RECT  56.293 26.64 56.408 27.192 ;
     RECT  56.401 28.272 56.408 34.968 ;
     RECT  55.283 36.288 56.408 36.648 ;
     RECT  56.113 38.16 56.408 38.808 ;
     RECT  55.253 40.848 56.408 41.16 ;
     RECT  56.293 42.576 56.408 43.848 ;
     RECT  56.077 44.976 56.408 46.296 ;
     RECT  54.565 48.672 56.408 50.088 ;
     RECT  54.673 51.888 56.408 51.912 ;
     RECT  56.077 53.28 56.408 59.16 ;
     RECT  56.185 61.2 56.408 63.384 ;
     RECT  56.293 64.656 56.408 67.848 ;
     RECT  56.293 69.456 56.408 73.608 ;
     RECT  55.645 74.64 56.408 75.192 ;
     RECT  56.293 76.752 56.408 81.384 ;
     RECT  56.365 83.568 56.408 83.592 ;
     RECT  56.408 2.148 56.512 84.252 ;
     RECT  56.512 2.256 56.704 83.982 ;
     RECT  56.704 57.888 56.765 65.016 ;
     RECT  56.704 34.368 56.837 34.392 ;
     RECT  56.704 53.136 56.837 54.648 ;
     RECT  56.765 57.888 56.837 64.968 ;
     RECT  56.704 42.192 56.867 43.848 ;
     RECT  56.704 14.496 56.873 14.664 ;
     RECT  56.704 76.32 56.963 81.48 ;
     RECT  56.704 68.736 56.981 75.192 ;
     RECT  56.704 83.472 56.981 83.784 ;
     RECT  56.981 73.584 56.989 75.192 ;
     RECT  56.704 28.272 57.053 33 ;
     RECT  56.704 39.936 57.053 41.16 ;
     RECT  56.981 69.552 57.053 72.36 ;
     RECT  56.989 73.584 57.053 75.144 ;
     RECT  56.704 25.488 57.107 25.512 ;
     RECT  56.704 15.888 57.125 19.032 ;
     RECT  57.053 69.552 57.125 70.824 ;
     RECT  56.704 50.736 57.161 50.76 ;
     RECT  56.704 2.256 57.197 8.328 ;
     RECT  57.053 28.368 57.197 33 ;
     RECT  56.704 45.168 57.305 49.704 ;
     RECT  56.704 11.856 57.413 13.032 ;
     RECT  56.837 57.984 57.449 64.968 ;
     RECT  57.197 2.448 57.484 8.328 ;
     RECT  57.305 47.808 57.491 49.704 ;
     RECT  57.449 57.984 57.521 64.104 ;
     RECT  57.125 15.888 57.629 16.536 ;
     RECT  56.704 20.352 57.635 23.304 ;
     RECT  56.704 55.824 57.635 56.904 ;
     RECT  56.867 42.768 57.665 43.848 ;
     RECT  56.981 83.472 57.665 83.496 ;
     RECT  57.305 45.168 57.692 46.536 ;
     RECT  57.665 42.96 57.697 43.848 ;
     RECT  57.692 45.12 57.697 46.536 ;
     RECT  57.484 7.68 57.74 8.328 ;
     RECT  56.704 9.6 57.74 10.152 ;
     RECT  56.873 14.64 57.769 14.664 ;
     RECT  57.629 15.888 57.769 15.96 ;
     RECT  57.74 7.68 57.827 10.152 ;
     RECT  57.635 56.4 57.841 56.904 ;
     RECT  57.521 57.984 57.841 63.384 ;
     RECT  57.769 14.64 57.845 15.96 ;
     RECT  57.413 11.856 57.877 12.84 ;
     RECT  56.837 53.136 57.877 54.312 ;
     RECT  57.841 56.4 57.881 63.384 ;
     RECT  57.053 40.272 57.913 41.16 ;
     RECT  57.197 28.368 57.917 31.416 ;
     RECT  56.704 38.784 57.953 38.808 ;
     RECT  57.877 53.136 57.985 54.6 ;
     RECT  57.841 24.624 58.021 25.368 ;
     RECT  56.704 66.48 58.021 66.888 ;
     RECT  57.053 72.336 58.021 72.36 ;
     RECT  57.877 11.424 58.025 12.84 ;
     RECT  57.877 34.368 58.057 34.392 ;
     RECT  56.963 76.32 58.057 81.336 ;
     RECT  57.635 20.352 58.061 20.376 ;
     RECT  57.881 56.4 58.061 62.808 ;
     RECT  57.125 69.552 58.076 69.576 ;
     RECT  57.845 14.832 58.097 15.96 ;
     RECT  58.021 24.336 58.115 25.368 ;
     RECT  58.076 69.12 58.117 69.576 ;
     RECT  58.021 72.24 58.129 72.36 ;
     RECT  57.053 73.584 58.129 74.856 ;
     RECT  57.635 21.648 58.163 23.304 ;
     RECT  58.115 24.336 58.163 25.032 ;
     RECT  58.057 76.32 58.169 81.96 ;
     RECT  57.125 17.904 58.201 19.032 ;
     RECT  56.704 26.64 58.205 27.192 ;
     RECT  57.917 28.368 58.241 31.128 ;
     RECT  58.061 56.4 58.313 62.712 ;
     RECT  58.021 66.096 58.381 66.888 ;
     RECT  58.201 17.904 58.385 19.416 ;
     RECT  58.313 56.4 58.385 57.672 ;
     RECT  58.381 66.096 58.385 67.272 ;
     RECT  57.913 40.272 58.453 41.4 ;
     RECT  58.163 24.624 58.493 25.032 ;
     RECT  57.125 70.8 58.501 70.824 ;
     RECT  58.129 72.24 58.501 74.856 ;
     RECT  56.704 36.288 58.525 37.128 ;
     RECT  57.697 42.96 58.525 46.536 ;
     RECT  57.491 47.808 58.525 47.832 ;
     RECT  58.46 65.52 58.547 65.544 ;
     RECT  58.241 28.368 58.561 28.392 ;
     RECT  58.057 34.368 58.561 34.824 ;
     RECT  57.985 53.136 58.561 55.224 ;
     RECT  58.525 42.96 58.597 47.832 ;
     RECT  58.117 68.784 58.601 69.576 ;
     RECT  58.597 42.96 58.633 47.88 ;
     RECT  57.491 49.008 58.633 49.032 ;
     RECT  58.561 52.416 58.633 55.224 ;
     RECT  58.205 26.64 58.691 26.76 ;
     RECT  58.561 34.368 58.693 35.112 ;
     RECT  58.525 36.288 58.693 38.04 ;
     RECT  58.453 39.696 58.693 41.4 ;
     RECT  57.484 2.448 58.705 6.408 ;
     RECT  57.197 32.784 58.705 33 ;
     RECT  58.691 26.64 58.709 26.664 ;
     RECT  58.313 58.704 58.737 62.712 ;
     RECT  58.705 32.784 58.741 33.336 ;
     RECT  58.693 34.368 58.741 38.04 ;
     RECT  58.633 42.96 58.741 49.032 ;
     RECT  58.097 15.888 58.813 15.96 ;
     RECT  57.827 7.68 58.817 8.328 ;
     RECT  58.169 80.304 58.849 81.96 ;
     RECT  58.777 82.992 58.849 83.016 ;
     RECT  58.741 32.784 58.853 38.04 ;
     RECT  58.741 42.768 58.853 49.032 ;
     RECT  58.633 52.08 58.853 55.224 ;
     RECT  57.827 9.408 58.889 10.152 ;
     RECT  58.853 32.784 58.921 34.824 ;
     RECT  58.169 76.32 58.921 79.224 ;
     RECT  58.501 70.8 58.925 74.856 ;
     RECT  58.849 80.304 58.993 83.016 ;
     RECT  58.853 36.48 59.029 38.04 ;
     RECT  58.853 52.416 59.033 55.224 ;
     RECT  58.163 21.648 59.137 22.296 ;
     RECT  58.163 23.28 59.137 23.304 ;
     RECT  58.025 11.856 59.173 12.84 ;
     RECT  58.241 29.904 59.173 31.128 ;
     RECT  58.921 32.448 59.173 34.824 ;
     RECT  58.925 72.24 59.173 74.856 ;
     RECT  59.029 36.48 59.221 38.712 ;
     RECT  58.693 39.696 59.221 41.784 ;
     RECT  58.957 14.448 59.245 14.472 ;
     RECT  58.813 15.888 59.245 16.44 ;
     RECT  58.921 76.272 59.245 79.224 ;
     RECT  59.173 11.856 59.269 13.128 ;
     RECT  58.385 66.624 59.317 67.272 ;
     RECT  58.601 68.784 59.317 68.856 ;
     RECT  59.173 72.24 59.317 75.192 ;
     RECT  59.245 76.224 59.317 79.224 ;
     RECT  58.385 19.392 59.321 19.416 ;
     RECT  59.137 21.648 59.393 23.304 ;
     RECT  59.269 11.28 59.413 13.128 ;
     RECT  58.385 17.904 59.425 18.216 ;
     RECT  59.065 20.496 59.425 20.52 ;
     RECT  59.425 17.904 59.459 18.84 ;
     RECT  59.173 70.704 59.461 70.728 ;
     RECT  59.033 52.704 59.465 55.224 ;
     RECT  59.317 66.624 59.465 68.856 ;
     RECT  58.561 27.936 59.537 28.392 ;
     RECT  58.705 2.256 59.573 6.408 ;
     RECT  58.853 43.008 59.573 49.032 ;
     RECT  58.889 10.08 59.605 10.152 ;
     RECT  59.413 11.28 59.605 13.464 ;
     RECT  58.993 80.304 59.609 83.208 ;
     RECT  59.317 72.24 59.641 79.224 ;
     RECT  59.609 80.544 59.677 83.208 ;
     RECT  59.459 18.72 59.681 18.84 ;
     RECT  59.393 21.648 59.717 22.296 ;
     RECT  59.641 72.24 59.717 79.272 ;
     RECT  59.461 70.608 59.753 70.728 ;
     RECT  59.393 23.28 59.785 23.304 ;
     RECT  58.493 24.624 59.785 24.84 ;
     RECT  59.717 74.016 59.785 79.272 ;
     RECT  59.785 74.016 59.789 79.464 ;
     RECT  59.573 2.256 59.825 6.312 ;
     RECT  59.785 23.28 59.825 25.08 ;
     RECT  59.425 20.496 59.857 20.568 ;
     RECT  59.717 21.648 59.857 21.816 ;
     RECT  59.173 29.904 59.929 34.824 ;
     RECT  58.737 58.704 59.929 62.424 ;
     RECT  59.825 24.096 59.933 25.08 ;
     RECT  59.465 67.2 59.933 68.856 ;
     RECT  59.929 29.904 59.965 35.016 ;
     RECT  59.497 64.416 59.965 64.44 ;
     RECT  59.605 10.08 59.969 13.464 ;
     RECT  59.933 24.096 59.969 24.84 ;
     RECT  59.933 68.16 59.969 68.856 ;
     RECT  59.929 58.704 60.005 62.76 ;
     RECT  59.857 20.496 60.041 21.816 ;
     RECT  59.573 43.008 60.041 48.696 ;
     RECT  59.465 53.088 60.077 55.224 ;
     RECT  60.109 26.736 60.181 26.76 ;
     RECT  59.221 36.48 60.185 41.784 ;
     RECT  59.717 72.24 60.217 72.888 ;
     RECT  59.677 80.544 60.217 83.352 ;
     RECT  60.217 80.544 60.221 83.64 ;
     RECT  60.181 26.736 60.227 27.384 ;
     RECT  58.385 56.4 60.253 57.624 ;
     RECT  58.817 7.68 60.289 7.704 ;
     RECT  59.245 14.448 60.293 16.44 ;
     RECT  59.969 11.328 60.325 13.464 ;
     RECT  60.293 14.448 60.325 14.856 ;
     RECT  60.253 56.4 60.325 57.672 ;
     RECT  60.005 58.704 60.325 58.776 ;
     RECT  59.537 28.368 60.329 28.392 ;
     RECT  59.533 9.024 60.361 9.048 ;
     RECT  59.969 10.08 60.361 10.152 ;
     RECT  60.185 36.48 60.361 36.504 ;
     RECT  60.325 56.4 60.361 58.776 ;
     RECT  59.681 18.72 60.398 18.792 ;
     RECT  58.741 50.688 60.437 50.712 ;
     RECT  60.398 18.768 60.509 18.792 ;
     RECT  60.041 43.008 60.541 46.152 ;
     RECT  59.825 2.496 60.581 6.312 ;
     RECT  59.969 24.096 60.581 24.12 ;
     RECT  60.041 47.184 60.613 48.696 ;
     RECT  60.077 53.232 60.613 55.224 ;
     RECT  60.361 56.256 60.613 58.776 ;
     RECT  60.325 11.328 60.617 14.856 ;
     RECT  60.221 81.072 60.617 83.64 ;
     RECT  60.613 53.232 60.653 58.776 ;
     RECT  60.617 82.944 60.725 83.64 ;
     RECT  59.965 64.176 60.757 64.44 ;
     RECT  59.965 29.664 60.761 35.016 ;
     RECT  60.653 54.336 60.797 58.776 ;
     RECT  60.725 82.992 60.797 83.64 ;
     RECT  60.005 60 60.829 62.76 ;
     RECT  60.757 64.176 60.829 64.968 ;
     RECT  60.397 68.88 60.865 68.904 ;
     RECT  59.753 70.656 60.901 70.728 ;
     RECT  60.217 72.048 60.901 72.888 ;
     RECT  60.185 37.632 60.937 41.784 ;
     RECT  60.797 54.672 60.973 58.776 ;
     RECT  60.829 60 60.973 64.968 ;
     RECT  60.716 66.24 60.973 66.888 ;
     RECT  60.937 37.632 60.997 41.928 ;
     RECT  60.541 42.912 60.997 46.152 ;
     RECT  59.789 74.352 60.997 79.464 ;
     RECT  60.041 20.496 61.225 21.144 ;
     RECT  60.721 18.816 61.244 18.84 ;
     RECT  61.225 19.824 61.244 21.144 ;
     RECT  60.289 7.392 61.297 7.704 ;
     RECT  60.361 9.024 61.333 10.152 ;
     RECT  60.617 11.328 61.333 11.4 ;
     RECT  60.797 83.184 61.333 83.64 ;
     RECT  61.244 18.816 61.369 21.144 ;
     RECT  60.973 66.192 61.369 66.888 ;
     RECT  61.369 66.192 61.405 67.416 ;
     RECT  60.613 47.184 61.429 49.032 ;
     RECT  60.761 29.664 61.441 34.92 ;
     RECT  61.405 66.192 61.441 67.752 ;
     RECT  60.865 68.88 61.441 69.192 ;
     RECT  60.581 2.592 61.477 6.312 ;
     RECT  61.297 7.392 61.477 7.992 ;
     RECT  60.617 12.432 61.477 14.856 ;
     RECT  60.293 16.128 61.477 16.44 ;
     RECT  60.361 36.144 61.477 36.504 ;
     RECT  60.997 37.632 61.477 46.152 ;
     RECT  60.617 81.072 61.477 81.96 ;
     RECT  61.441 66.192 61.513 69.192 ;
     RECT  60.901 70.656 61.513 72.984 ;
     RECT  60.937 25.056 61.525 25.08 ;
     RECT  61.429 47.184 61.525 49.176 ;
     RECT  61.525 25.056 61.549 25.944 ;
     RECT  60.653 53.232 61.621 53.256 ;
     RECT  61.477 2.592 61.669 7.992 ;
     RECT  61.669 2.256 61.693 7.992 ;
     RECT  61.693 2.256 61.808 8.04 ;
     RECT  61.333 9.024 61.808 11.4 ;
     RECT  61.477 12.432 61.808 16.44 ;
     RECT  61.657 17.616 61.808 17.64 ;
     RECT  61.369 18.816 61.808 21.432 ;
     RECT  61.333 23.952 61.808 23.976 ;
     RECT  61.549 25.056 61.808 26.04 ;
     RECT  60.227 27.36 61.808 27.384 ;
     RECT  61.441 29.232 61.808 34.92 ;
     RECT  61.477 36.144 61.808 46.152 ;
     RECT  61.525 47.136 61.808 49.176 ;
     RECT  61.117 52.032 61.808 52.056 ;
     RECT  61.621 53.04 61.808 53.256 ;
     RECT  60.973 54.672 61.808 64.968 ;
     RECT  61.513 66.192 61.808 72.984 ;
     RECT  60.997 74.16 61.808 79.464 ;
     RECT  61.477 80.784 61.808 81.96 ;
     RECT  61.333 83.184 61.808 83.784 ;
     RECT  61.808 2.148 61.912 84.252 ;
     RECT  61.912 2.418 62.104 83.982 ;
     RECT  62.104 9.024 62.201 11.016 ;
     RECT  62.104 50.832 62.243 68.232 ;
     RECT  62.104 76.464 62.273 81.96 ;
     RECT  62.104 71.856 62.309 75.48 ;
     RECT  62.104 23.952 62.381 24.744 ;
     RECT  62.243 50.832 62.381 52.056 ;
     RECT  62.104 2.64 62.489 7.992 ;
     RECT  62.273 76.512 62.489 81.96 ;
     RECT  62.104 14.208 62.633 16.296 ;
     RECT  62.104 26.016 62.633 27.72 ;
     RECT  62.381 23.952 62.669 23.976 ;
     RECT  62.104 40.8 62.705 42.792 ;
     RECT  62.104 34.176 62.741 34.776 ;
     RECT  62.243 53.232 62.849 68.232 ;
     RECT  62.104 21.648 62.885 22.776 ;
     RECT  62.489 80.112 62.885 81.96 ;
     RECT  62.885 21.648 62.915 22.44 ;
     RECT  62.849 54.72 62.915 68.232 ;
     RECT  62.104 18.96 62.921 20.328 ;
     RECT  62.104 44.4 62.921 48.504 ;
     RECT  62.921 19.248 62.957 20.328 ;
     RECT  62.489 76.512 62.957 79.032 ;
     RECT  62.957 19.248 63.029 19.896 ;
     RECT  62.201 9.12 63.065 11.016 ;
     RECT  62.921 46.848 63.065 48.504 ;
     RECT  62.104 70.608 63.097 70.632 ;
     RECT  62.915 54.72 63.173 65.016 ;
     RECT  62.885 80.784 63.173 81.96 ;
     RECT  62.633 14.784 63.205 16.296 ;
     RECT  62.104 29.856 63.205 32.472 ;
     RECT  62.104 36.864 63.205 39.72 ;
     RECT  62.921 44.4 63.205 45.864 ;
     RECT  62.957 76.512 63.209 77.64 ;
     RECT  63.173 81.072 63.241 81.96 ;
     RECT  62.104 83.04 63.241 83.784 ;
     RECT  63.205 28.944 63.245 32.472 ;
     RECT  63.209 76.944 63.281 77.64 ;
     RECT  62.381 50.832 63.313 51.384 ;
     RECT  63.173 54.72 63.317 54.984 ;
     RECT  63.205 36.48 63.353 39.72 ;
     RECT  63.353 39.696 63.36 39.72 ;
     RECT  62.104 12.48 63.385 12.504 ;
     RECT  63.205 14.784 63.385 16.872 ;
     RECT  62.849 53.232 63.421 53.256 ;
     RECT  62.309 72.144 63.461 75.48 ;
     RECT  62.104 69.312 63.529 69.336 ;
     RECT  62.705 40.8 63.565 42.312 ;
     RECT  63.097 70.608 63.569 70.68 ;
     RECT  62.633 26.928 63.596 27.72 ;
     RECT  63.353 36.48 63.601 38.712 ;
     RECT  63.245 32.448 63.637 32.472 ;
     RECT  63.596 26.928 63.683 27.912 ;
     RECT  62.741 34.176 63.709 34.2 ;
     RECT  63.637 32.448 63.781 32.568 ;
     RECT  63.709 33.648 63.781 34.2 ;
     RECT  63.385 12.48 63.817 13.128 ;
     RECT  63.683 26.928 63.817 26.952 ;
     RECT  63.029 19.248 63.821 19.848 ;
     RECT  63.601 35.904 63.821 38.712 ;
     RECT  63.205 44.16 63.829 45.864 ;
     RECT  63.173 56.352 63.865 65.016 ;
     RECT  62.915 66.096 63.877 68.232 ;
     RECT  63.529 69.312 63.877 69.528 ;
     RECT  63.385 14.784 63.889 17.592 ;
     RECT  63.421 52.992 63.889 53.256 ;
     RECT  63.065 9.264 63.925 11.016 ;
     RECT  63.817 12 63.925 13.128 ;
     RECT  63.817 26.352 63.961 26.952 ;
     RECT  63.877 66.096 63.964 69.528 ;
     RECT  63.781 32.448 63.98 34.2 ;
     RECT  62.915 21.648 64.033 22.056 ;
     RECT  63.98 32.448 64.033 34.776 ;
     RECT  63.821 35.904 64.033 38.472 ;
     RECT  63.829 43.824 64.069 45.864 ;
     RECT  63.065 46.848 64.069 47.304 ;
     RECT  64.069 43.824 64.153 47.304 ;
     RECT  63.889 52.992 64.213 53.592 ;
     RECT  63.889 14.16 64.253 17.592 ;
     RECT  64.153 43.824 64.253 45.864 ;
     RECT  62.957 78.624 64.285 79.032 ;
     RECT  64.253 43.824 64.325 45.576 ;
     RECT  63.065 48.48 64.325 48.504 ;
     RECT  64.153 46.848 64.357 47.304 ;
     RECT  63.569 70.608 64.361 70.632 ;
     RECT  64.033 21.648 64.367 22.2 ;
     RECT  63.821 19.248 64.393 19.56 ;
     RECT  63.281 77.28 64.393 77.64 ;
     RECT  64.316 20.544 64.403 20.568 ;
     RECT  64.367 21.648 64.405 22.776 ;
     RECT  64.253 15.072 64.433 17.592 ;
     RECT  63.865 56.352 64.433 64.728 ;
     RECT  62.489 2.64 64.453 7.704 ;
     RECT  64.433 15.264 64.469 17.592 ;
     RECT  64.433 56.352 64.469 62.52 ;
     RECT  63.565 39.888 64.501 42.312 ;
     RECT  63.313 50.256 64.501 51.384 ;
     RECT  64.453 2.64 64.54 8.136 ;
     RECT  63.461 72.144 64.549 75 ;
     RECT  64.393 76.944 64.549 77.64 ;
     RECT  64.501 50.256 64.645 51.912 ;
     RECT  64.405 21.552 64.649 22.776 ;
     RECT  63.457 23.904 64.681 23.928 ;
     RECT  63.964 67.776 64.721 69.528 ;
     RECT  64.469 56.352 64.757 56.856 ;
     RECT  64.213 52.992 64.789 53.976 ;
     RECT  63.317 54.96 64.789 54.984 ;
     RECT  63.245 28.944 64.793 31.416 ;
     RECT  64.433 63.792 64.861 64.728 ;
     RECT  63.964 66.096 64.861 66.648 ;
     RECT  63.925 9.264 64.892 13.128 ;
     RECT  64.54 2.64 64.901 7.704 ;
     RECT  64.789 52.992 64.931 54.984 ;
     RECT  64.901 2.64 64.933 7.416 ;
     RECT  63.961 26.208 64.933 26.952 ;
     RECT  63.241 81.072 64.933 83.784 ;
     RECT  64.892 9.12 64.94 13.128 ;
     RECT  64.033 32.448 64.969 38.472 ;
     RECT  64.501 39.888 64.969 42.456 ;
     RECT  64.649 21.696 64.973 22.776 ;
     RECT  64.969 32.448 64.973 42.456 ;
     RECT  64.931 52.992 64.973 53.496 ;
     RECT  64.549 71.808 64.973 77.64 ;
     RECT  64.94 9.12 64.979 13.464 ;
     RECT  64.973 33.024 64.979 42.456 ;
     RECT  64.973 21.984 64.981 22.776 ;
     RECT  64.681 23.904 64.981 24.552 ;
     RECT  64.933 26.208 65.009 27.768 ;
     RECT  64.645 50.112 65.009 51.912 ;
     RECT  64.973 71.808 65.009 74.856 ;
     RECT  64.979 9.408 65.027 13.464 ;
     RECT  64.979 33.6 65.053 42.456 ;
     RECT  64.757 56.736 65.117 56.856 ;
     RECT  65.053 33.6 65.153 38.664 ;
     RECT  65.009 71.808 65.173 72.84 ;
     RECT  65.009 51.888 65.189 51.912 ;
     RECT  64.931 54.672 65.221 54.984 ;
     RECT  64.285 78.624 65.257 79.176 ;
     RECT  64.981 21.984 65.261 24.552 ;
     RECT  65.009 73.968 65.261 74.856 ;
     RECT  64.721 68.928 65.297 69.528 ;
     RECT  64.973 75.84 65.329 77.64 ;
     RECT  65.257 78.624 65.329 79.848 ;
     RECT  65.117 56.832 65.333 56.856 ;
     RECT  64.393 18.816 65.365 19.56 ;
     RECT  64.933 2.256 65.405 7.416 ;
     RECT  64.861 63.792 65.405 66.648 ;
     RECT  65.027 9.408 65.411 13.32 ;
     RECT  65.053 39.888 65.437 42.456 ;
     RECT  64.325 44.112 65.437 45.576 ;
     RECT  64.357 46.848 65.437 48.456 ;
     RECT  65.009 27.744 65.473 27.768 ;
     RECT  64.793 28.944 65.473 31.368 ;
     RECT  65.329 75.84 65.473 79.848 ;
     RECT  64.933 80.928 65.473 83.784 ;
     RECT  65.411 9.408 65.477 12.552 ;
     RECT  65.261 24.48 65.555 24.552 ;
     RECT  65.473 27.744 65.555 31.368 ;
     RECT  64.973 53.232 65.555 53.496 ;
     RECT  65.173 71.28 65.581 72.84 ;
     RECT  65.437 44.112 65.612 48.456 ;
     RECT  65.009 50.112 65.612 50.616 ;
     RECT  65.581 71.088 65.621 72.84 ;
     RECT  65.261 21.984 65.657 23.4 ;
     RECT  65.153 33.6 65.657 33.624 ;
     RECT  65.621 72.096 65.693 72.84 ;
     RECT  65.612 44.112 65.699 50.616 ;
     RECT  65.221 54.672 65.765 55.272 ;
     RECT  65.657 23.088 65.773 23.4 ;
     RECT  65.365 18.816 65.801 20.328 ;
     RECT  65.699 50.112 65.837 50.616 ;
     RECT  65.699 44.112 65.843 48.84 ;
     RECT  65.473 75.84 65.873 83.784 ;
     RECT  65.693 72.432 65.945 72.84 ;
     RECT  65.545 57.072 65.977 57.096 ;
     RECT  64.469 58.08 65.977 62.52 ;
     RECT  65.405 63.792 65.981 66.312 ;
     RECT  65.765 54.864 66.013 55.272 ;
     RECT  65.405 2.544 66.049 7.416 ;
     RECT  65.555 24.528 66.049 24.552 ;
     RECT  65.801 19.536 66.053 20.328 ;
     RECT  65.657 21.984 66.053 22.008 ;
     RECT  65.297 69.312 66.053 69.528 ;
     RECT  66.049 2.544 66.085 8.376 ;
     RECT  65.477 9.408 66.085 10.968 ;
     RECT  65.153 34.848 66.085 38.664 ;
     RECT  65.437 39.888 66.085 42.504 ;
     RECT  65.843 44.112 66.085 45.672 ;
     RECT  65.477 11.952 66.089 12.552 ;
     RECT  65.555 27.744 66.125 30.408 ;
     RECT  66.125 27.744 66.131 27.96 ;
     RECT  64.469 16.8 66.161 17.592 ;
     RECT  66.125 28.992 66.161 30.408 ;
     RECT  65.945 72.48 66.161 72.84 ;
     RECT  66.085 34.848 66.179 42.504 ;
     RECT  65.555 53.472 66.179 53.496 ;
     RECT  66.179 38.016 66.193 42.504 ;
     RECT  66.085 44.064 66.193 45.672 ;
     RECT  65.837 50.592 66.229 50.616 ;
     RECT  65.261 73.968 66.229 74.712 ;
     RECT  65.873 75.84 66.229 77.688 ;
     RECT  66.085 2.544 66.233 10.968 ;
     RECT  65.621 71.088 66.409 71.112 ;
     RECT  64.721 67.776 66.445 67.8 ;
     RECT  66.161 72.816 66.481 72.84 ;
     RECT  66.229 73.968 66.481 77.688 ;
     RECT  64.469 15.264 66.517 15.576 ;
     RECT  66.161 16.8 66.517 17.112 ;
     RECT  66.113 52.416 66.517 52.44 ;
     RECT  66.229 21.744 66.553 21.768 ;
     RECT  66.089 12.48 66.589 12.552 ;
     RECT  65.977 57.072 66.589 62.52 ;
     RECT  65.873 80.88 66.589 83.784 ;
     RECT  66.589 31.92 66.625 31.944 ;
     RECT  66.625 31.92 66.661 32.616 ;
     RECT  66.013 54.864 66.661 55.56 ;
     RECT  66.589 56.592 66.661 62.52 ;
     RECT  66.049 24.528 66.697 25.032 ;
     RECT  66.047 26.208 66.697 26.232 ;
     RECT  66.131 27.744 66.697 27.912 ;
     RECT  66.409 70.656 66.697 71.112 ;
     RECT  66.233 2.544 66.733 6.168 ;
     RECT  66.179 34.848 66.853 36.6 ;
     RECT  65.773 23.088 66.877 23.112 ;
     RECT  66.697 24.528 66.877 26.232 ;
     RECT  66.697 27.312 66.877 27.912 ;
     RECT  66.193 38.016 66.877 45.672 ;
     RECT  65.843 46.704 66.877 48.84 ;
     RECT  66.661 54.864 66.877 62.52 ;
     RECT  66.229 50.592 66.949 51.384 ;
     RECT  66.053 69.312 67.021 69.336 ;
     RECT  66.697 70.464 67.021 71.112 ;
     RECT  66.481 72.816 67.129 77.688 ;
     RECT  65.873 79.008 67.129 79.032 ;
     RECT  66.733 2.256 67.208 6.168 ;
     RECT  66.233 7.392 67.208 10.968 ;
     RECT  66.589 12.48 67.208 13.08 ;
     RECT  66.6 14.112 67.208 14.136 ;
     RECT  66.517 15.264 67.208 17.112 ;
     RECT  67.165 18.24 67.208 18.264 ;
     RECT  66.053 20.304 67.208 20.328 ;
     RECT  66.553 21.408 67.208 21.768 ;
     RECT  66.877 23.088 67.208 23.352 ;
     RECT  66.877 24.528 67.208 27.912 ;
     RECT  66.161 29.856 67.208 30.408 ;
     RECT  66.661 31.44 67.208 32.616 ;
     RECT  66.853 34.176 67.208 36.6 ;
     RECT  66.877 38.016 67.208 48.84 ;
     RECT  66.949 50.016 67.208 51.384 ;
     RECT  66.517 52.416 67.208 53.4 ;
     RECT  66.877 54.864 67.208 63.048 ;
     RECT  65.981 64.656 67.208 66.312 ;
     RECT  66.445 67.776 67.208 67.848 ;
     RECT  67.021 69.312 67.208 71.112 ;
     RECT  67.129 72.816 67.208 79.752 ;
     RECT  66.589 80.88 67.208 83.832 ;
     RECT  67.208 2.148 67.312 84.252 ;
     RECT  67.312 2.256 67.504 83.982 ;
     RECT  67.504 20.496 67.565 22.008 ;
     RECT  67.504 29.856 67.565 31.464 ;
     RECT  67.504 54.864 67.565 55.56 ;
     RECT  67.504 50.016 67.601 51.384 ;
     RECT  67.504 56.976 67.601 67.848 ;
     RECT  67.504 80.544 67.637 83.784 ;
     RECT  67.504 14.112 67.817 18.888 ;
     RECT  67.504 22.992 67.817 23.976 ;
     RECT  67.601 50.256 67.817 51.384 ;
     RECT  67.565 29.856 67.859 31.416 ;
     RECT  67.859 29.856 67.889 31.128 ;
     RECT  67.504 32.592 67.889 49.032 ;
     RECT  67.601 56.976 67.889 67.56 ;
     RECT  67.504 72.144 67.889 79.224 ;
     RECT  67.504 25.008 67.997 25.08 ;
     RECT  67.889 72.144 68.033 79.176 ;
     RECT  67.889 56.976 68.177 64.728 ;
     RECT  67.817 15.888 68.213 18.888 ;
     RECT  67.889 30.048 68.213 31.128 ;
     RECT  67.504 69.312 68.249 71.112 ;
     RECT  67.504 2.256 68.393 10.968 ;
     RECT  68.393 8.976 68.429 10.968 ;
     RECT  67.565 21.984 68.429 22.008 ;
     RECT  68.249 69.312 68.429 70.728 ;
     RECT  68.033 72.144 68.429 77.688 ;
     RECT  67.889 66.144 68.465 67.56 ;
     RECT  67.504 26.112 68.492 27.96 ;
     RECT  67.504 12.048 68.497 12.84 ;
     RECT  68.429 10.128 68.533 10.968 ;
     RECT  68.497 11.952 68.533 12.84 ;
     RECT  68.533 10.128 68.579 12.84 ;
     RECT  67.997 25.008 68.579 25.032 ;
     RECT  67.817 14.112 68.629 14.808 ;
     RECT  68.213 15.888 68.645 17.112 ;
     RECT  67.889 32.592 68.645 47.208 ;
     RECT  68.465 66.144 68.681 67.512 ;
     RECT  68.579 11.184 68.717 12.84 ;
     RECT  67.637 80.88 68.749 83.784 ;
     RECT  68.393 2.256 68.753 7.992 ;
     RECT  68.681 66.144 68.753 66.744 ;
     RECT  68.749 80.832 68.785 83.784 ;
     RECT  68.492 26.112 68.789 28.104 ;
     RECT  67.817 22.992 68.821 23.352 ;
     RECT  68.821 22.992 68.857 24.216 ;
     RECT  67.889 48.24 68.857 49.032 ;
     RECT  67.817 50.256 68.857 50.856 ;
     RECT  68.789 27.024 68.861 28.104 ;
     RECT  67.565 20.496 68.965 20.664 ;
     RECT  68.645 34.752 68.965 47.208 ;
     RECT  68.857 48.24 68.965 50.856 ;
     RECT  68.857 22.704 68.969 24.216 ;
     RECT  68.429 72.384 68.969 77.688 ;
     RECT  68.785 80.736 69.001 83.784 ;
     RECT  68.969 74.976 69.005 77.688 ;
     RECT  68.033 79.008 69.005 79.176 ;
     RECT  68.861 27.552 69.037 28.104 ;
     RECT  68.753 7.92 69.041 7.992 ;
     RECT  68.969 72.384 69.041 73.704 ;
     RECT  68.645 32.592 69.061 33.384 ;
     RECT  68.645 15.888 69.077 16.872 ;
     RECT  68.753 66.144 69.077 66.648 ;
     RECT  69.005 75.264 69.113 77.688 ;
     RECT  69.068 25.872 69.155 25.896 ;
     RECT  69.037 27.552 69.221 28.824 ;
     RECT  68.213 30.048 69.253 30.072 ;
     RECT  68.213 31.104 69.253 31.128 ;
     RECT  68.177 56.976 69.289 63.864 ;
     RECT  68.965 34.752 69.293 50.856 ;
     RECT  69.289 56.976 69.293 64.2 ;
     RECT  68.213 18.24 69.301 18.888 ;
     RECT  68.965 20.496 69.301 21.672 ;
     RECT  69.113 75.936 69.325 77.688 ;
     RECT  69.005 79.008 69.325 79.032 ;
     RECT  68.429 70.56 69.365 70.728 ;
     RECT  69.293 58.464 69.433 64.2 ;
     RECT  69.077 66.144 69.445 66.6 ;
     RECT  68.429 69.312 69.445 69.576 ;
     RECT  69.293 46.656 69.452 50.856 ;
     RECT  67.504 52.416 69.452 52.44 ;
     RECT  69.041 7.968 69.469 7.992 ;
     RECT  68.429 8.976 69.469 9.048 ;
     RECT  68.629 13.824 69.469 14.808 ;
     RECT  69.077 15.888 69.469 16.68 ;
     RECT  69.469 7.968 69.505 9.048 ;
     RECT  68.579 10.128 69.505 10.152 ;
     RECT  69.445 68.88 69.532 69.72 ;
     RECT  69.452 46.656 69.539 53.256 ;
     RECT  69.301 18.24 69.541 21.672 ;
     RECT  67.565 54.864 69.541 54.888 ;
     RECT  69.433 58.464 69.577 64.248 ;
     RECT  69.445 65.472 69.577 66.6 ;
     RECT  69.541 18.096 69.581 21.672 ;
     RECT  69.539 46.656 69.581 50.856 ;
     RECT  69.581 46.656 69.653 49.416 ;
     RECT  69.293 34.752 69.683 45.624 ;
     RECT  68.717 11.184 69.721 12.504 ;
     RECT  69.469 13.824 69.721 16.68 ;
     RECT  69.221 27.552 69.725 28.104 ;
     RECT  69.653 46.656 69.725 49.08 ;
     RECT  69.683 42.816 69.761 45.624 ;
     RECT  69.685 67.632 69.781 67.656 ;
     RECT  69.532 68.88 69.781 69.576 ;
     RECT  68.753 2.256 69.793 6.84 ;
     RECT  69.781 67.632 69.797 69.576 ;
     RECT  69.797 67.632 69.827 69.432 ;
     RECT  69.577 58.464 69.833 66.6 ;
     RECT  69.325 75.936 69.869 79.032 ;
     RECT  69.253 30.048 69.884 31.128 ;
     RECT  69.061 32.352 69.884 33.384 ;
     RECT  69.541 54.72 69.901 54.888 ;
     RECT  69.827 67.632 69.901 68.904 ;
     RECT  69.539 51.888 69.941 52.44 ;
     RECT  69.001 80.256 70.009 83.784 ;
     RECT  69.581 19.536 70.045 21.672 ;
     RECT  68.969 22.752 70.045 24.216 ;
     RECT  69.869 76.176 70.045 79.032 ;
     RECT  70.009 80.256 70.045 83.832 ;
     RECT  69.581 50.832 70.049 50.856 ;
     RECT  69.884 30.048 70.069 33.384 ;
     RECT  69.901 71.28 70.079 71.832 ;
     RECT  69.041 72.816 70.079 73.704 ;
     RECT  69.725 27.6 70.115 28.104 ;
     RECT  70.069 29.712 70.115 33.384 ;
     RECT  69.793 2.256 70.117 6.888 ;
     RECT  70.045 76.176 70.117 83.832 ;
     RECT  69.721 11.184 70.163 16.68 ;
     RECT  70.163 13.68 70.193 16.68 ;
     RECT  69.581 18.096 70.193 18.216 ;
     RECT  70.115 27.6 70.193 27.624 ;
     RECT  69.901 67.584 70.261 68.904 ;
     RECT  69.683 34.752 70.265 41.64 ;
     RECT  70.079 71.28 70.301 73.704 ;
     RECT  69.293 57.456 70.333 57.48 ;
     RECT  69.833 58.464 70.333 66.408 ;
     RECT  70.333 57.456 70.369 66.408 ;
     RECT  70.117 2.256 70.373 6.984 ;
     RECT  70.265 34.752 70.373 41.592 ;
     RECT  70.301 71.28 70.373 71.304 ;
     RECT  70.045 19.536 70.441 24.216 ;
     RECT  70.115 29.712 70.441 31.176 ;
     RECT  70.373 34.752 70.445 39.624 ;
     RECT  70.301 72.432 70.477 73.704 ;
     RECT  70.477 72.432 70.517 74.088 ;
     RECT  70.373 2.64 70.585 6.984 ;
     RECT  69.505 7.968 70.585 10.152 ;
     RECT  70.585 2.64 70.625 10.152 ;
     RECT  70.261 67.392 70.643 68.904 ;
     RECT  70.441 29.232 70.657 31.176 ;
     RECT  70.117 76.176 70.661 83.88 ;
     RECT  70.163 11.184 70.697 12.504 ;
     RECT  70.193 13.824 70.739 16.68 ;
     RECT  70.115 32.592 70.805 33.384 ;
     RECT  69.941 51.888 70.841 51.912 ;
     RECT  70.369 57.264 70.841 66.408 ;
     RECT  69.725 46.656 70.873 49.032 ;
     RECT  70.445 34.8 70.877 39.624 ;
     RECT  70.373 41.136 70.877 41.592 ;
     RECT  70.517 72.432 70.877 72.84 ;
     RECT  70.697 11.184 70.913 11.208 ;
     RECT  70.661 76.368 70.913 83.832 ;
     RECT  70.441 19.536 70.949 25.656 ;
     RECT  70.657 28.944 70.949 31.176 ;
     RECT  70.625 7.776 70.981 10.152 ;
     RECT  70.841 58.464 70.981 66.408 ;
     RECT  70.643 67.392 70.981 68.136 ;
     RECT  70.981 7.776 71.027 10.248 ;
     RECT  70.909 26.784 71.045 26.808 ;
     RECT  71.027 7.776 71.057 8.472 ;
     RECT  71.057 7.968 71.068 8.472 ;
     RECT  70.877 34.8 71.093 34.872 ;
     RECT  71.084 52.848 71.125 52.872 ;
     RECT  69.901 54.288 71.125 54.888 ;
     RECT  70.625 2.64 71.129 6.456 ;
     RECT  70.193 18.096 71.129 18.12 ;
     RECT  71.045 26.736 71.129 26.808 ;
     RECT  71.093 34.848 71.165 34.872 ;
     RECT  70.981 58.464 71.165 68.136 ;
     RECT  71.125 52.848 71.171 54.888 ;
     RECT  70.517 74.064 71.197 74.088 ;
     RECT  70.949 31.152 71.201 31.176 ;
     RECT  71.161 55.872 71.267 55.896 ;
     RECT  70.949 19.536 71.269 24.696 ;
     RECT  71.197 70.176 71.269 70.2 ;
     RECT  71.129 2.64 71.273 6.264 ;
     RECT  71.165 64.944 71.273 68.136 ;
     RECT  71.171 53.568 71.281 54.888 ;
     RECT  71.197 74.064 71.305 74.712 ;
     RECT  71.027 10.128 71.309 10.248 ;
     RECT  70.739 15.36 71.309 16.68 ;
     RECT  70.877 35.856 71.315 39.624 ;
     RECT  71.315 37.008 71.341 39.624 ;
     RECT  70.877 41.136 71.341 41.544 ;
     RECT  70.805 33.072 71.345 33.384 ;
     RECT  71.281 53.568 71.345 53.592 ;
     RECT  71.305 74.064 71.345 75.096 ;
     RECT  71.269 19.344 71.381 24.696 ;
     RECT  70.949 28.944 71.413 29.928 ;
     RECT  69.761 42.816 71.413 45.192 ;
     RECT  70.913 78.336 71.417 83.832 ;
     RECT  71.165 58.464 71.459 63.816 ;
     RECT  71.129 26.784 71.485 26.808 ;
     RECT  71.309 15.36 71.525 16.632 ;
     RECT  71.273 2.64 71.629 6.216 ;
     RECT  70.697 12.48 71.845 12.504 ;
     RECT  70.873 46.656 71.881 49.224 ;
     RECT  71.345 74.4 72.025 75.096 ;
     RECT  71.413 28.032 72.085 29.928 ;
     RECT  71.273 67.056 72.133 68.136 ;
     RECT  71.068 8.448 72.205 8.472 ;
     RECT  71.485 26.784 72.205 26.904 ;
     RECT  72.205 8.448 72.241 8.952 ;
     RECT  71.629 2.304 72.277 6.216 ;
     RECT  71.845 11.952 72.277 12.504 ;
     RECT  70.739 13.824 72.277 13.848 ;
     RECT  72.205 26.64 72.277 26.904 ;
     RECT  72.025 31.92 72.277 31.944 ;
     RECT  72.133 67.056 72.277 68.184 ;
     RECT  70.913 76.368 72.277 77.304 ;
     RECT  71.593 18.192 72.313 18.216 ;
     RECT  71.381 19.344 72.313 23.352 ;
     RECT  71.381 24.624 72.313 24.696 ;
     RECT  72.277 25.68 72.313 26.904 ;
     RECT  72.085 27.888 72.313 29.928 ;
     RECT  72.277 67.056 72.313 68.232 ;
     RECT  72.241 8.016 72.325 8.952 ;
     RECT  71.281 54.864 72.349 54.888 ;
     RECT  70.841 57.264 72.349 57.288 ;
     RECT  71.459 58.464 72.349 63.672 ;
     RECT  71.309 10.128 72.373 10.152 ;
     RECT  72.277 2.304 72.385 6.84 ;
     RECT  71.701 33.84 72.385 33.864 ;
     RECT  72.349 57.264 72.385 63.672 ;
     RECT  71.525 15.552 72.421 16.632 ;
     RECT  72.277 31.92 72.421 32.856 ;
     RECT  72.385 33.84 72.421 34.776 ;
     RECT  72.325 8.016 72.428 9.144 ;
     RECT  72.373 10.128 72.428 10.92 ;
     RECT  72.421 31.92 72.457 34.776 ;
     RECT  72.385 2.304 72.469 6.888 ;
     RECT  72.428 8.016 72.469 10.92 ;
     RECT  72.421 15.552 72.493 16.92 ;
     RECT  72.313 18.192 72.493 23.352 ;
     RECT  72.493 15.552 72.601 23.352 ;
     RECT  72.313 24.624 72.601 29.928 ;
     RECT  71.341 37.008 72.601 41.544 ;
     RECT  72.469 2.304 72.608 10.92 ;
     RECT  72.277 11.952 72.608 13.848 ;
     RECT  72.601 15.552 72.608 29.928 ;
     RECT  72.457 31.488 72.608 34.776 ;
     RECT  72.421 35.808 72.608 35.832 ;
     RECT  72.601 37.008 72.608 41.736 ;
     RECT  71.413 42.768 72.608 45.192 ;
     RECT  71.881 46.176 72.608 49.224 ;
     RECT  71.665 50.736 72.608 51.72 ;
     RECT  72.349 54.096 72.608 54.888 ;
     RECT  72.385 57.024 72.608 63.672 ;
     RECT  71.273 64.944 72.608 65.976 ;
     RECT  72.313 67.056 72.608 69 ;
     RECT  71.269 70.08 72.608 70.2 ;
     RECT  70.877 72.816 72.608 72.84 ;
     RECT  72.025 74.4 72.608 75.24 ;
     RECT  72.277 76.32 72.608 77.304 ;
     RECT  71.417 78.336 72.608 83.784 ;
     RECT  72.608 2.148 72.712 84.252 ;
     RECT  72.712 2.304 72.904 83.982 ;
     RECT  72.904 31.488 72.929 33.624 ;
     RECT  72.904 57.024 72.965 64.152 ;
     RECT  72.904 47.088 73.001 54.888 ;
     RECT  72.904 67.104 73.001 70.104 ;
     RECT  72.904 13.632 73.073 24.12 ;
     RECT  72.904 35.808 73.073 35.832 ;
     RECT  73.001 47.088 73.073 51.192 ;
     RECT  72.965 58.128 73.073 64.152 ;
     RECT  72.904 26.64 73.109 27.432 ;
     RECT  72.904 9.024 73.181 12.504 ;
     RECT  73.001 67.104 73.181 69.288 ;
     RECT  73.181 9.024 73.187 10.728 ;
     RECT  72.904 78.672 73.217 83.832 ;
     RECT  73.073 58.752 73.331 64.152 ;
     RECT  73.073 47.088 73.397 51.144 ;
     RECT  73.397 47.088 73.433 48.312 ;
     RECT  72.904 39.504 73.469 43.704 ;
     RECT  73.073 13.632 73.571 16.632 ;
     RECT  73.109 26.64 73.577 27.384 ;
     RECT  73.331 58.752 73.577 63.624 ;
     RECT  73.073 17.616 73.721 24.12 ;
     RECT  72.904 74.688 73.757 75.24 ;
     RECT  73.187 9.168 73.811 10.728 ;
     RECT  72.904 34.752 73.865 34.776 ;
     RECT  72.904 72.816 73.909 72.84 ;
     RECT  73.757 74.688 73.909 74.712 ;
     RECT  73.001 52.416 73.937 54.888 ;
     RECT  73.909 74.064 73.955 74.712 ;
     RECT  72.904 37.008 73.969 38.424 ;
     RECT  73.469 39.504 73.969 41.496 ;
     RECT  72.929 31.68 73.973 33.624 ;
     RECT  72.965 57.024 73.973 57.048 ;
     RECT  73.955 74.064 73.996 74.088 ;
     RECT  73.933 26.16 74.005 26.184 ;
     RECT  72.904 29.088 74.005 29.784 ;
     RECT  74.005 28.896 74.051 29.784 ;
     RECT  73.811 10.032 74.081 10.728 ;
     RECT  73.571 13.92 74.081 16.632 ;
     RECT  74.005 25.632 74.089 26.184 ;
     RECT  73.937 52.416 74.113 53.592 ;
     RECT  73.433 47.088 74.149 47.304 ;
     RECT  74.081 10.032 74.153 10.152 ;
     RECT  73.721 17.616 74.153 23.976 ;
     RECT  73.469 43.008 74.153 43.704 ;
     RECT  74.153 20.544 74.197 23.976 ;
     RECT  73.181 11.952 74.221 12.504 ;
     RECT  74.153 17.664 74.261 19.56 ;
     RECT  72.904 2.304 74.293 8.04 ;
     RECT  74.197 20.64 74.297 23.976 ;
     RECT  73.217 78.912 74.297 83.832 ;
     RECT  74.185 70.656 74.333 70.68 ;
     RECT  73.577 58.752 74.401 63.576 ;
     RECT  73.577 27.36 74.473 27.384 ;
     RECT  73.397 50.16 74.477 51.144 ;
     RECT  72.904 45.168 74.509 45.192 ;
     RECT  72.904 76.896 74.545 77.304 ;
     RECT  74.297 78.912 74.545 83.784 ;
     RECT  74.477 50.16 74.581 50.952 ;
     RECT  74.545 76.896 74.588 83.784 ;
     RECT  74.081 14.352 74.617 16.632 ;
     RECT  74.509 33.984 74.621 34.008 ;
     RECT  74.293 2.304 74.629 9 ;
     RECT  74.149 46.368 74.653 47.304 ;
     RECT  73.433 48.288 74.653 48.312 ;
     RECT  74.581 49.824 74.653 50.952 ;
     RECT  74.401 71.712 74.657 71.736 ;
     RECT  74.588 76.368 74.675 83.784 ;
     RECT  74.089 25.92 74.677 26.184 ;
     RECT  74.473 27.36 74.677 27.912 ;
     RECT  73.909 72.816 74.677 72.936 ;
     RECT  74.153 10.128 74.693 10.152 ;
     RECT  74.677 72.48 74.723 72.936 ;
     RECT  74.113 52.224 74.725 53.592 ;
     RECT  74.581 35.952 74.761 35.976 ;
     RECT  73.969 37.008 74.761 41.496 ;
     RECT  74.653 46.368 74.765 50.952 ;
     RECT  74.761 65.184 74.797 65.208 ;
     RECT  74.401 57.552 74.869 63.576 ;
     RECT  74.797 64.944 74.869 65.208 ;
     RECT  74.677 25.92 74.941 27.912 ;
     RECT  74.051 28.896 74.941 29.256 ;
     RECT  74.221 11.664 75.049 12.504 ;
     RECT  74.297 21.888 75.089 23.976 ;
     RECT  74.261 17.664 75.125 17.688 ;
     RECT  74.629 2.208 75.157 9 ;
     RECT  74.725 52.08 75.157 53.592 ;
     RECT  74.869 57.552 75.157 65.208 ;
     RECT  74.941 25.92 75.193 29.256 ;
     RECT  75.193 25.92 75.212 29.784 ;
     RECT  74.509 45.024 75.229 45.192 ;
     RECT  75.212 25.92 75.253 29.928 ;
     RECT  73.973 31.68 75.253 33 ;
     RECT  74.761 35.952 75.253 41.496 ;
     RECT  74.153 43.008 75.253 43.032 ;
     RECT  75.157 57.024 75.265 65.208 ;
     RECT  75.253 25.92 75.269 33 ;
     RECT  75.253 35.952 75.269 43.032 ;
     RECT  75.265 56.976 75.269 65.208 ;
     RECT  75.269 25.92 75.299 30.792 ;
     RECT  75.269 37.008 75.299 43.032 ;
     RECT  74.765 46.368 75.301 47.88 ;
     RECT  75.299 25.92 75.305 29.784 ;
     RECT  74.765 49.008 75.341 50.952 ;
     RECT  74.261 18.672 75.373 19.56 ;
     RECT  74.297 20.64 75.373 20.664 ;
     RECT  75.269 64.944 75.373 65.208 ;
     RECT  74.617 14.352 75.409 16.68 ;
     RECT  75.269 56.976 75.409 63.816 ;
     RECT  74.675 77.28 75.413 83.784 ;
     RECT  75.341 49.2 75.445 50.952 ;
     RECT  75.157 52.08 75.445 53.784 ;
     RECT  75.157 2.208 75.491 9.864 ;
     RECT  75.413 80.256 75.521 83.784 ;
     RECT  75.049 11.52 75.553 12.504 ;
     RECT  75.491 2.208 75.629 6.84 ;
     RECT  73.181 67.104 75.629 68.232 ;
     RECT  75.491 7.872 75.665 9.864 ;
     RECT  75.299 37.008 75.665 42.504 ;
     RECT  75.665 7.968 75.673 9.864 ;
     RECT  75.409 56.208 75.697 63.816 ;
     RECT  75.413 77.28 75.701 79.032 ;
     RECT  73.181 69.264 75.805 69.288 ;
     RECT  75.701 77.472 75.809 79.032 ;
     RECT  75.445 49.2 75.841 53.784 ;
     RECT  73.937 54.864 75.841 54.888 ;
     RECT  75.305 26.208 75.845 29.784 ;
     RECT  75.665 37.008 75.845 41.496 ;
     RECT  75.121 74.256 75.845 74.28 ;
     RECT  75.629 2.208 75.881 6.264 ;
     RECT  75.845 41.136 75.881 41.496 ;
     RECT  75.409 13.824 75.917 17.16 ;
     RECT  75.845 26.208 75.917 27.336 ;
     RECT  75.805 34.752 75.917 34.776 ;
     RECT  75.845 37.008 75.917 39.912 ;
     RECT  75.841 49.2 75.917 54.888 ;
     RECT  75.917 37.008 75.953 38.184 ;
     RECT  75.301 46.176 75.989 47.88 ;
     RECT  75.517 70.8 75.989 70.824 ;
     RECT  75.805 69.264 76.021 69.384 ;
     RECT  75.881 2.208 76.025 6.12 ;
     RECT  75.553 11.232 76.057 12.504 ;
     RECT  75.917 15.36 76.061 17.16 ;
     RECT  76.021 69.264 76.093 69.48 ;
     RECT  75.665 42.48 76.097 42.504 ;
     RECT  75.629 67.248 76.133 68.232 ;
     RECT  76.025 2.64 76.169 6.12 ;
     RECT  75.089 21.888 76.201 23.928 ;
     RECT  75.697 55.92 76.205 63.816 ;
     RECT  75.809 77.472 76.205 78.648 ;
     RECT  76.205 55.968 76.237 63.816 ;
     RECT  75.373 64.944 76.237 65.592 ;
     RECT  76.093 69.264 76.237 69.576 ;
     RECT  76.057 10.992 76.241 12.504 ;
     RECT  75.373 18.672 76.241 20.664 ;
     RECT  76.237 55.968 76.241 65.592 ;
     RECT  75.269 35.952 76.273 35.976 ;
     RECT  75.299 30.768 76.309 30.792 ;
     RECT  75.269 32.208 76.309 33 ;
     RECT  75.917 26.208 76.345 27.144 ;
     RECT  76.241 57.696 76.349 65.592 ;
     RECT  76.133 67.296 76.385 68.232 ;
     RECT  76.237 69.264 76.405 70.056 ;
     RECT  76.241 18.672 76.421 18.696 ;
     RECT  76.381 66.096 76.465 66.12 ;
     RECT  76.201 21.888 76.493 24.504 ;
     RECT  75.845 28.416 76.529 29.784 ;
     RECT  76.273 35.328 76.529 35.976 ;
     RECT  76.309 30.768 76.633 33 ;
     RECT  76.493 21.888 76.705 22.776 ;
     RECT  75.673 8.208 76.709 9.864 ;
     RECT  76.493 23.856 76.709 24.504 ;
     RECT  76.405 69.216 76.709 70.056 ;
     RECT  76.529 28.8 76.741 29.784 ;
     RECT  76.633 30.768 76.741 33.624 ;
     RECT  75.917 50.976 76.741 54.888 ;
     RECT  75.917 39.888 76.745 39.912 ;
     RECT  76.205 77.472 76.745 78.168 ;
     RECT  75.917 13.824 76.781 14.376 ;
     RECT  75.521 80.256 76.813 80.664 ;
     RECT  76.349 57.696 76.817 64.632 ;
     RECT  76.709 8.208 76.849 9.768 ;
     RECT  75.521 81.696 76.853 83.784 ;
     RECT  76.061 15.36 76.885 16.392 ;
     RECT  76.741 28.8 76.885 33.624 ;
     RECT  75.881 41.136 76.885 41.16 ;
     RECT  76.885 28.8 76.931 34.344 ;
     RECT  75.989 47.808 76.933 47.88 ;
     RECT  75.917 49.2 76.933 49.608 ;
     RECT  76.849 7.488 76.997 9.768 ;
     RECT  76.931 28.8 76.997 33 ;
     RECT  75.229 44.64 77.029 45.192 ;
     RECT  76.345 25.824 77.077 27.144 ;
     RECT  76.813 79.824 77.101 80.664 ;
     RECT  76.169 2.64 77.125 6.072 ;
     RECT  77.077 25.824 77.173 27.432 ;
     RECT  77.125 2.592 77.245 6.072 ;
     RECT  76.241 11.232 77.245 12.504 ;
     RECT  76.885 42.768 77.245 42.792 ;
     RECT  77.029 44.448 77.245 45.192 ;
     RECT  75.989 46.176 77.245 46.728 ;
     RECT  77.245 44.448 77.317 46.728 ;
     RECT  76.933 47.808 77.317 49.608 ;
     RECT  76.241 20.304 77.353 20.664 ;
     RECT  76.709 69.552 77.353 70.056 ;
     RECT  76.997 7.488 77.389 9.048 ;
     RECT  76.931 34.32 77.425 34.344 ;
     RECT  76.529 35.952 77.461 35.976 ;
     RECT  75.953 37.008 77.461 37.944 ;
     RECT  76.885 40.848 77.461 41.16 ;
     RECT  77.245 42.72 77.461 42.792 ;
     RECT  76.741 74.592 77.461 74.616 ;
     RECT  77.245 11.232 77.497 12.744 ;
     RECT  77.461 74.592 77.497 75.24 ;
     RECT  77.317 44.448 77.533 49.608 ;
     RECT  76.741 50.976 77.533 54.936 ;
     RECT  77.245 2.592 77.605 6.312 ;
     RECT  77.533 44.448 77.641 54.936 ;
     RECT  77.029 18 77.677 18.024 ;
     RECT  76.385 67.344 77.677 68.232 ;
     RECT  77.353 69.552 77.677 70.392 ;
     RECT  77.497 73.632 77.677 75.24 ;
     RECT  77.353 20.16 77.713 20.664 ;
     RECT  77.497 11.136 77.749 13.128 ;
     RECT  77.173 25.008 77.749 27.432 ;
     RECT  76.997 28.8 77.749 32.856 ;
     RECT  77.713 19.536 77.785 20.664 ;
     RECT  76.705 21.696 77.785 22.776 ;
     RECT  76.241 55.968 77.785 56.376 ;
     RECT  76.817 57.696 77.785 64.392 ;
     RECT  77.677 17.424 77.821 18.024 ;
     RECT  77.785 19.536 77.821 22.776 ;
     RECT  77.749 10.848 77.893 13.128 ;
     RECT  77.821 17.424 77.893 22.776 ;
     RECT  76.709 23.856 77.893 23.88 ;
     RECT  77.749 25.008 77.893 32.856 ;
     RECT  77.461 35.952 77.893 37.944 ;
     RECT  77.785 55.968 77.893 64.392 ;
     RECT  77.677 65.424 77.893 65.448 ;
     RECT  77.605 2.304 78.008 6.312 ;
     RECT  77.389 7.344 78.008 9.048 ;
     RECT  77.893 10.032 78.008 13.128 ;
     RECT  76.885 14.688 78.008 16.392 ;
     RECT  77.893 17.424 78.008 32.856 ;
     RECT  77.425 34.32 78.008 34.968 ;
     RECT  77.893 35.952 78.008 39.768 ;
     RECT  77.461 40.848 78.008 42.792 ;
     RECT  77.641 44.112 78.008 54.936 ;
     RECT  77.893 55.968 78.008 65.448 ;
     RECT  77.677 67.344 78.008 70.392 ;
     RECT  74.723 72.48 78.008 72.504 ;
     RECT  77.677 73.632 78.008 76.056 ;
     RECT  76.745 77.472 78.008 78.12 ;
     RECT  77.101 79.536 78.008 80.664 ;
     RECT  76.853 81.936 78.008 83.784 ;
     RECT  78.008 2.148 78.112 84.252 ;
     RECT  78.112 2.304 78.304 83.982 ;
     RECT  78.304 42.864 78.329 47.112 ;
     RECT  78.304 78.48 78.365 83.784 ;
     RECT  78.304 15.744 78.401 23.88 ;
     RECT  78.304 36.864 78.401 39.768 ;
     RECT  78.304 24.912 78.419 32.856 ;
     RECT  78.329 44.352 78.419 47.112 ;
     RECT  78.304 2.304 78.467 12.84 ;
     RECT  78.419 45.024 78.467 47.112 ;
     RECT  78.401 39.744 78.473 39.768 ;
     RECT  78.304 51.936 78.509 68.232 ;
     RECT  78.304 48.192 78.581 49.032 ;
     RECT  78.304 75.216 78.581 75.24 ;
     RECT  78.509 51.984 78.617 68.232 ;
     RECT  78.401 36.864 78.659 38.712 ;
     RECT  78.617 51.984 78.659 58.344 ;
     RECT  78.304 34.944 78.689 34.968 ;
     RECT  78.304 50.064 78.689 50.088 ;
     RECT  78.659 51.984 78.689 52.824 ;
     RECT  78.659 53.808 78.689 58.344 ;
     RECT  78.419 31.776 78.725 32.856 ;
     RECT  78.467 46.032 78.761 47.112 ;
     RECT  78.304 69.504 78.761 74.04 ;
     RECT  78.761 70.56 78.797 74.04 ;
     RECT  78.761 69.504 78.841 69.528 ;
     RECT  78.401 15.744 78.869 22.104 ;
     RECT  78.689 53.904 78.869 58.344 ;
     RECT  78.365 78.72 78.947 83.784 ;
     RECT  78.869 15.744 79.049 21 ;
     RECT  78.869 54.096 79.121 58.344 ;
     RECT  78.947 79.776 79.121 83.784 ;
     RECT  78.659 37.968 79.154 38.712 ;
     RECT  78.419 24.912 79.193 30.792 ;
     RECT  78.304 40.848 79.193 41.16 ;
     RECT  78.797 70.56 79.229 73.656 ;
     RECT  79.229 70.56 79.235 72.504 ;
     RECT  79.049 19.776 79.301 20.952 ;
     RECT  79.235 70.56 79.301 72.408 ;
     RECT  78.467 2.304 79.337 10.152 ;
     RECT  79.154 37.968 79.337 38.664 ;
     RECT  79.121 54.336 79.337 58.344 ;
     RECT  79.337 54.384 79.373 58.344 ;
     RECT  79.301 70.56 79.373 72.168 ;
     RECT  79.337 2.304 79.388 9.864 ;
     RECT  78.329 42.864 79.405 43.368 ;
     RECT  79.373 54.384 79.409 57.864 ;
     RECT  78.401 23.328 79.429 23.88 ;
     RECT  79.193 24.912 79.429 30.36 ;
     RECT  78.467 11.136 79.441 12.84 ;
     RECT  79.388 2.256 79.475 9.864 ;
     RECT  79.429 23.328 79.475 30.36 ;
     RECT  79.441 11.136 79.477 13.272 ;
     RECT  79.049 15.744 79.517 18.696 ;
     RECT  78.617 60.384 79.549 68.232 ;
     RECT  79.475 23.856 79.553 30.36 ;
     RECT  79.337 38.208 79.553 38.664 ;
     RECT  79.405 42.672 79.573 43.368 ;
     RECT  79.477 10.848 79.589 13.272 ;
     RECT  79.409 54.624 79.589 57.864 ;
     RECT  79.549 60.384 79.589 68.664 ;
     RECT  78.689 52.176 79.625 52.824 ;
     RECT  78.725 32.208 79.657 32.856 ;
     RECT  79.625 52.176 79.657 52.776 ;
     RECT  79.553 24.048 79.667 30.36 ;
     RECT  78.581 48.192 79.693 48.216 ;
     RECT  79.657 51.264 79.697 52.776 ;
     RECT  79.693 48.192 79.765 48.552 ;
     RECT  79.301 19.776 79.769 20.664 ;
     RECT  78.761 46.128 79.769 47.112 ;
     RECT  79.477 78.576 79.805 78.6 ;
     RECT  79.475 2.736 79.841 9.864 ;
     RECT  79.765 48.192 79.873 48.936 ;
     RECT  79.841 5.664 79.907 9.864 ;
     RECT  79.657 32.208 79.916 34.2 ;
     RECT  79.229 73.488 79.949 73.656 ;
     RECT  79.589 54.624 79.985 57.144 ;
     RECT  79.916 32.208 80.003 34.248 ;
     RECT  78.869 21.984 80.053 22.104 ;
     RECT  79.517 16.08 80.057 18.696 ;
     RECT  80.057 17.472 80.093 18.696 ;
     RECT  79.667 24.096 80.093 30.36 ;
     RECT  79.873 48.192 80.129 49.368 ;
     RECT  80.053 21.648 80.137 22.104 ;
     RECT  80.137 21.984 80.197 22.104 ;
     RECT  79.121 82.08 80.201 83.784 ;
     RECT  80.201 82.992 80.204 83.784 ;
     RECT  79.553 38.208 80.237 38.232 ;
     RECT  79.193 40.992 80.269 41.16 ;
     RECT  79.573 42.576 80.269 43.368 ;
     RECT  80.204 82.992 80.291 84.024 ;
     RECT  79.589 11.808 80.293 13.272 ;
     RECT  79.589 60.816 80.3 68.664 ;
     RECT  80.003 32.208 80.309 34.2 ;
     RECT  79.697 51.264 80.309 51.288 ;
     RECT  79.985 56.016 80.309 57.144 ;
     RECT  79.121 79.776 80.309 80.568 ;
     RECT  80.293 11.808 80.341 13.8 ;
     RECT  79.801 14.832 80.341 14.856 ;
     RECT  80.3 60.816 80.341 69.528 ;
     RECT  79.373 70.56 80.341 70.584 ;
     RECT  79.373 72.144 80.341 72.168 ;
     RECT  80.341 60.816 80.381 72.168 ;
     RECT  80.381 62.736 80.387 71.256 ;
     RECT  79.769 19.776 80.417 20.568 ;
     RECT  80.197 21.984 80.417 22.2 ;
     RECT  80.309 34.08 80.417 34.2 ;
     RECT  80.309 56.304 80.417 57.144 ;
     RECT  80.269 40.992 80.483 43.368 ;
     RECT  80.093 18.192 80.525 18.696 ;
     RECT  80.417 20.544 80.525 20.568 ;
     RECT  80.381 60.816 80.588 61.752 ;
     RECT  80.557 30.816 80.593 30.84 ;
     RECT  78.659 36.864 80.593 36.936 ;
     RECT  79.985 54.624 80.593 54.888 ;
     RECT  80.593 30.816 80.629 31.176 ;
     RECT  80.309 32.208 80.629 32.904 ;
     RECT  80.593 54.144 80.629 54.888 ;
     RECT  80.588 60.672 80.629 61.752 ;
     RECT  79.907 6.384 80.633 9.864 ;
     RECT  80.417 56.304 80.633 57.048 ;
     RECT  79.769 46.128 80.669 46.536 ;
     RECT  80.629 54.096 80.675 54.888 ;
     RECT  80.093 24.096 80.701 29.784 ;
     RECT  80.341 11.808 80.737 14.856 ;
     RECT  80.525 18.672 80.773 18.696 ;
     RECT  78.467 45.024 80.773 45.048 ;
     RECT  80.633 9.6 80.881 9.864 ;
     RECT  80.633 6.384 80.917 8.52 ;
     RECT  80.881 9.6 80.917 9.912 ;
     RECT  80.773 18.672 80.951 18.744 ;
     RECT  80.701 23.952 80.963 29.784 ;
     RECT  80.917 5.76 80.993 8.52 ;
     RECT  80.417 34.176 80.993 34.2 ;
     RECT  80.417 22.032 81.013 22.2 ;
     RECT  80.963 23.952 81.013 24.696 ;
     RECT  80.483 40.992 81.013 43.032 ;
     RECT  80.737 11.712 81.061 14.856 ;
     RECT  80.309 79.776 81.065 80.04 ;
     RECT  81.025 77.088 81.097 77.112 ;
     RECT  81.013 22.032 81.1 24.696 ;
     RECT  81.013 40.8 81.1 43.032 ;
     RECT  80.963 26.208 81.101 29.784 ;
     RECT  79.697 52.752 81.101 52.776 ;
     RECT  80.629 60.288 81.169 61.752 ;
     RECT  80.129 48.528 81.173 49.368 ;
     RECT  80.993 5.76 81.209 7.224 ;
     RECT  80.917 9.6 81.301 10.392 ;
     RECT  81.061 11.664 81.301 14.856 ;
     RECT  81.173 49.344 81.313 49.368 ;
     RECT  81.061 58.704 81.313 58.728 ;
     RECT  81.169 60 81.313 61.752 ;
     RECT  80.291 82.992 81.313 83.592 ;
     RECT  80.993 8.208 81.347 8.52 ;
     RECT  81.313 49.344 81.349 50.184 ;
     RECT  80.387 62.736 81.349 68.616 ;
     RECT  80.387 69.648 81.349 71.256 ;
     RECT  81.097 77.088 81.349 77.304 ;
     RECT  80.989 46.704 81.395 46.728 ;
     RECT  81.349 49.344 81.433 50.76 ;
     RECT  80.917 39.744 81.457 39.768 ;
     RECT  79.949 73.488 81.457 73.512 ;
     RECT  81.101 26.304 81.461 29.784 ;
     RECT  80.773 44.16 81.461 45.048 ;
     RECT  81.313 82.8 81.493 83.592 ;
     RECT  81.313 58.704 81.497 61.752 ;
     RECT  81.349 62.736 81.497 71.256 ;
     RECT  80.675 54.096 81.541 54.168 ;
     RECT  81.349 76.944 81.565 77.304 ;
     RECT  81.1 41.04 81.569 43.032 ;
     RECT  81.493 52.56 81.587 52.584 ;
     RECT  80.951 18.672 81.601 18.792 ;
     RECT  79.841 2.736 81.605 4.68 ;
     RECT  81.569 41.04 81.605 42.84 ;
     RECT  81.541 53.76 81.628 54.168 ;
     RECT  81.628 53.904 81.637 54.168 ;
     RECT  81.457 72.96 81.637 73.512 ;
     RECT  80.629 30.816 81.673 32.904 ;
     RECT  81.065 80.016 81.677 80.04 ;
     RECT  81.637 72 81.683 73.512 ;
     RECT  81.433 49.344 81.713 49.896 ;
     RECT  81.683 72 81.724 72.024 ;
     RECT  81.637 53.904 81.749 54.552 ;
     RECT  80.057 16.08 81.781 16.104 ;
     RECT  81.565 76.944 81.785 77.448 ;
     RECT  81.673 30.816 81.817 33 ;
     RECT  81.301 9.6 81.821 14.856 ;
     RECT  81.785 77.04 81.821 77.448 ;
     RECT  81.821 9.6 81.827 14.808 ;
     RECT  81.497 59.616 81.889 61.752 ;
     RECT  81.497 62.736 81.889 70.968 ;
     RECT  81.821 77.04 81.893 77.304 ;
     RECT  81.853 46.752 81.965 46.776 ;
     RECT  81.749 53.904 81.965 54.12 ;
     RECT  80.633 56.976 82.033 57.048 ;
     RECT  81.683 73.488 82.033 73.512 ;
     RECT  81.277 74.688 82.033 74.712 ;
     RECT  81.601 18.24 82.069 18.792 ;
     RECT  81.637 43.92 82.073 43.944 ;
     RECT  81.827 10.704 82.109 14.808 ;
     RECT  81.1 23.952 82.109 24.696 ;
     RECT  81.493 82.416 82.109 83.688 ;
     RECT  81.817 30.816 82.141 33.048 ;
     RECT  82.109 10.704 82.145 11.832 ;
     RECT  82.033 73.488 82.181 74.712 ;
     RECT  81.347 8.208 82.397 8.472 ;
     RECT  81.605 2.736 82.429 4.44 ;
     RECT  82.069 17.424 82.429 18.792 ;
     RECT  81.349 47.856 82.429 47.88 ;
     RECT  82.429 47.328 82.465 47.88 ;
     RECT  82.429 17.424 82.573 19.368 ;
     RECT  81.605 42.72 82.573 42.84 ;
     RECT  81.209 5.76 82.584 7.176 ;
     RECT  82.573 17.184 82.597 19.368 ;
     RECT  81.745 20.88 82.597 20.904 ;
     RECT  82.573 35.76 82.609 35.784 ;
     RECT  81.461 26.304 82.645 26.328 ;
     RECT  81.461 27.36 82.645 29.784 ;
     RECT  82.141 30.816 82.681 33.096 ;
     RECT  82.465 47.328 82.717 47.928 ;
     RECT  82.109 24.096 82.741 24.696 ;
     RECT  82.645 26.304 82.741 29.784 ;
     RECT  82.609 35.472 82.789 35.784 ;
     RECT  81.461 45.024 82.789 45.048 ;
     RECT  82.717 72.192 82.789 72.216 ;
     RECT  82.789 45.024 82.825 45.24 ;
     RECT  82.789 72.192 82.825 72.312 ;
     RECT  82.597 17.184 82.837 20.904 ;
     RECT  81.1 22.032 82.837 22.344 ;
     RECT  82.825 45.024 82.897 45.528 ;
     RECT  82.789 34.992 82.969 35.784 ;
     RECT  81.605 41.04 82.969 41.16 ;
     RECT  82.573 42.72 82.969 43.704 ;
     RECT  82.969 34.896 83.005 35.784 ;
     RECT  81.457 39.744 83.005 39.912 ;
     RECT  81.827 9.6 83.077 9.624 ;
     RECT  82.145 10.704 83.077 10.728 ;
     RECT  82.837 17.184 83.113 22.344 ;
     RECT  83.005 34.8 83.113 35.784 ;
     RECT  80.593 36.816 83.113 36.936 ;
     RECT  82.109 82.416 83.113 82.44 ;
     RECT  82.897 44.976 83.125 45.528 ;
     RECT  82.429 2.256 83.185 4.44 ;
     RECT  82.584 5.712 83.185 7.176 ;
     RECT  82.741 24.096 83.185 29.784 ;
     RECT  82.145 11.808 83.221 11.832 ;
     RECT  82.109 12.96 83.221 14.808 ;
     RECT  83.041 38.496 83.221 38.52 ;
     RECT  81.889 59.616 83.269 70.968 ;
     RECT  82.825 71.952 83.269 72.312 ;
     RECT  82.181 73.488 83.269 73.8 ;
     RECT  82.609 74.88 83.269 74.904 ;
     RECT  82.717 47.328 83.329 48.888 ;
     RECT  83.269 73.488 83.401 74.904 ;
     RECT  83.185 2.256 83.408 7.176 ;
     RECT  82.397 8.208 83.408 8.232 ;
     RECT  83.077 9.6 83.408 10.728 ;
     RECT  83.221 11.808 83.408 14.808 ;
     RECT  81.781 15.936 83.408 16.104 ;
     RECT  83.113 17.088 83.408 22.344 ;
     RECT  83.185 23.328 83.408 29.784 ;
     RECT  82.681 30.816 83.408 33.624 ;
     RECT  83.113 34.8 83.408 36.936 ;
     RECT  83.221 38.256 83.408 38.52 ;
     RECT  83.005 39.552 83.408 39.912 ;
     RECT  82.969 41.04 83.408 43.704 ;
     RECT  83.125 44.976 83.408 45.624 ;
     RECT  83.329 46.8 83.408 48.888 ;
     RECT  81.713 49.872 83.408 49.896 ;
     RECT  83.113 52.512 83.408 52.536 ;
     RECT  81.965 53.904 83.408 53.928 ;
     RECT  82.357 55.248 83.408 55.272 ;
     RECT  82.033 56.88 83.408 57.048 ;
     RECT  82.501 58.128 83.408 58.152 ;
     RECT  83.269 59.616 83.408 72.312 ;
     RECT  83.401 73.488 83.408 75.816 ;
     RECT  81.893 77.04 83.408 77.112 ;
     RECT  82.897 78.672 83.408 78.696 ;
     RECT  82.393 80.592 83.408 80.664 ;
     RECT  83.113 82.176 83.408 82.44 ;
     RECT  82.109 83.568 83.408 83.688 ;
     RECT  83.408 2.148 83.512 84.252 ;
     RECT  83.512 2.256 83.704 83.982 ;
     RECT  83.704 45.024 83.729 45.48 ;
     RECT  83.704 12.528 83.765 14.52 ;
     RECT  83.704 66.24 83.765 71.4 ;
     RECT  83.704 32.064 83.801 38.184 ;
     RECT  83.704 60.288 83.801 65.208 ;
     RECT  83.704 18.72 83.873 18.792 ;
     RECT  83.704 26.016 83.873 29.784 ;
     RECT  83.704 39.552 83.873 42.84 ;
     RECT  83.765 12.528 83.891 14.232 ;
     RECT  83.873 18.768 83.891 18.792 ;
     RECT  83.801 35.76 83.909 38.184 ;
     RECT  83.729 45.024 83.909 45.24 ;
     RECT  83.704 53.904 83.987 55.272 ;
     RECT  83.987 53.904 84.028 55.128 ;
     RECT  83.909 38.16 84.083 38.184 ;
     RECT  83.891 12.528 84.089 14.088 ;
     RECT  83.704 19.968 84.089 24.216 ;
     RECT  83.909 35.76 84.089 36.936 ;
     RECT  83.704 82.224 84.089 83.832 ;
     RECT  83.873 39.552 84.124 42.792 ;
     RECT  83.873 26.016 84.125 29.688 ;
     RECT  84.028 53.904 84.125 54.936 ;
     RECT  84.125 53.904 84.233 54.456 ;
     RECT  84.124 39.6 84.269 42.792 ;
     RECT  84.089 12.528 84.305 12.552 ;
     RECT  83.704 2.256 84.341 9.624 ;
     RECT  83.704 10.704 84.341 10.728 ;
     RECT  84.089 21.072 84.341 24.216 ;
     RECT  83.704 75.696 84.341 75.816 ;
     RECT  84.089 82.416 84.371 83.832 ;
     RECT  83.801 32.064 84.377 34.104 ;
     RECT  83.704 46.752 84.377 50.808 ;
     RECT  84.377 32.064 84.413 32.52 ;
     RECT  83.704 52.464 84.413 52.728 ;
     RECT  83.704 58.128 84.419 59.064 ;
     RECT  84.089 36.624 84.449 36.936 ;
     RECT  84.341 2.256 84.521 8.664 ;
     RECT  84.269 39.6 84.521 42.744 ;
     RECT  83.801 60.288 84.521 64.92 ;
     RECT  84.413 52.464 84.557 52.536 ;
     RECT  84.521 60.288 84.557 62.232 ;
     RECT  84.341 75.792 84.557 75.816 ;
     RECT  83.704 16.08 84.629 17.64 ;
     RECT  84.413 32.064 84.665 32.328 ;
     RECT  84.371 83.184 84.665 83.832 ;
     RECT  84.125 26.016 84.697 27.192 ;
     RECT  84.377 46.752 84.773 50.28 ;
     RECT  84.773 49.872 84.809 50.28 ;
     RECT  84.665 83.184 84.809 83.208 ;
     RECT  84.125 28.56 84.845 29.688 ;
     RECT  84.809 49.872 84.845 49.896 ;
     RECT  84.089 19.968 84.917 20.088 ;
     RECT  84.377 33.552 84.917 34.104 ;
     RECT  84.697 25.632 84.949 27.192 ;
     RECT  84.845 28.704 84.953 29.688 ;
     RECT  84.917 33.552 84.953 34.056 ;
     RECT  84.521 63.744 84.953 64.92 ;
     RECT  83.765 70.56 84.985 70.584 ;
     RECT  83.704 74.16 84.985 74.184 ;
     RECT  84.521 3.024 84.989 8.664 ;
     RECT  84.341 21.168 84.989 24.216 ;
     RECT  84.953 34.032 84.989 34.056 ;
     RECT  84.521 41.136 84.989 42.744 ;
     RECT  83.765 66.24 84.989 69.528 ;
     RECT  84.985 70.56 85.021 71.112 ;
     RECT  84.697 31.776 85.025 31.8 ;
     RECT  84.521 39.6 85.025 39.912 ;
     RECT  85.021 70.56 85.093 71.928 ;
     RECT  84.989 21.168 85.169 22.2 ;
     RECT  84.419 58.128 85.169 58.152 ;
     RECT  85.093 18.816 85.177 18.84 ;
     RECT  84.557 52.464 85.205 52.488 ;
     RECT  85.093 70.56 85.273 72.456 ;
     RECT  84.233 53.904 85.277 53.928 ;
     RECT  84.953 63.792 85.277 64.92 ;
     RECT  84.949 9.744 85.385 10.2 ;
     RECT  83.909 45.024 85.417 45.048 ;
     RECT  84.773 46.752 85.417 48.216 ;
     RECT  85.385 9.744 85.421 9.768 ;
     RECT  84.953 28.8 85.453 29.688 ;
     RECT  85.025 39.6 85.453 39.864 ;
     RECT  85.277 64.896 85.453 64.92 ;
     RECT  84.989 66.24 85.453 68.808 ;
     RECT  84.989 23.328 85.477 24.216 ;
     RECT  85.453 28.8 85.493 30.216 ;
     RECT  85.477 23.328 85.523 24.312 ;
     RECT  84.989 7.2 85.529 8.664 ;
     RECT  85.169 21.168 85.529 22.056 ;
     RECT  85.273 70.56 85.565 72.648 ;
     RECT  85.523 23.568 85.597 24.312 ;
     RECT  84.949 25.392 85.597 27.192 ;
     RECT  85.417 38.16 85.597 38.184 ;
     RECT  85.453 39.168 85.597 39.864 ;
     RECT  85.597 23.568 85.601 27.192 ;
     RECT  85.417 45.024 85.601 48.216 ;
     RECT  85.565 70.56 85.637 71.112 ;
     RECT  85.529 21.168 85.669 22.008 ;
     RECT  85.453 64.896 85.673 68.808 ;
     RECT  84.089 13.776 85.709 14.088 ;
     RECT  85.601 24.288 85.709 27.192 ;
     RECT  85.601 45.024 85.709 47.88 ;
     RECT  85.561 11.952 85.741 12.6 ;
     RECT  84.917 20.064 85.741 20.088 ;
     RECT  85.669 21.072 85.741 22.008 ;
     RECT  85.709 46.752 85.763 47.88 ;
     RECT  84.989 3.024 85.781 6.024 ;
     RECT  85.637 70.56 85.781 70.92 ;
     RECT  85.717 15.072 85.804 15.096 ;
     RECT  84.985 74.064 85.813 74.184 ;
     RECT  85.529 8.448 85.817 8.664 ;
     RECT  85.741 11.424 85.849 12.6 ;
     RECT  85.717 43.536 85.849 43.56 ;
     RECT  85.813 74.064 85.859 74.664 ;
     RECT  85.597 38.16 85.889 39.864 ;
     RECT  84.449 36.912 85.907 36.936 ;
     RECT  85.849 10.8 85.933 12.6 ;
     RECT  85.933 11.424 85.993 12.6 ;
     RECT  85.709 14.064 85.993 14.088 ;
     RECT  85.777 35.712 85.993 35.736 ;
     RECT  85.741 20.064 85.997 22.008 ;
     RECT  85.993 35.664 86.065 35.736 ;
     RECT  85.781 3.072 86.105 6.024 ;
     RECT  85.997 20.112 86.105 22.008 ;
     RECT  85.709 24.288 86.105 26.808 ;
     RECT  86.149 72.912 86.173 72.936 ;
     RECT  85.781 70.56 86.195 70.584 ;
     RECT  84.557 60.816 86.209 62.232 ;
     RECT  85.921 9.216 86.213 9.24 ;
     RECT  85.763 46.752 86.213 47.064 ;
     RECT  84.989 41.136 86.281 42.552 ;
     RECT  85.849 43.536 86.281 43.944 ;
     RECT  85.493 28.8 86.353 28.824 ;
     RECT  86.065 35.664 86.357 35.976 ;
     RECT  86.213 46.848 86.393 47.064 ;
     RECT  84.629 16.224 86.396 17.64 ;
     RECT  86.396 15.936 86.483 17.64 ;
     RECT  85.493 30.192 86.497 30.216 ;
     RECT  86.209 60.816 86.537 62.472 ;
     RECT  85.889 38.16 86.605 38.76 ;
     RECT  86.281 41.136 86.605 43.944 ;
     RECT  85.709 45.024 86.605 45.048 ;
     RECT  85.673 65.328 86.605 68.808 ;
     RECT  86.173 72.912 86.605 73.56 ;
     RECT  85.705 80.304 86.605 80.328 ;
     RECT  86.537 60.816 86.609 61.272 ;
     RECT  86.353 28.272 86.629 28.824 ;
     RECT  86.497 30.192 86.629 30.648 ;
     RECT  86.605 38.064 86.629 38.76 ;
     RECT  85.277 63.792 86.641 63.816 ;
     RECT  86.605 65.328 86.641 68.952 ;
     RECT  85.993 11.424 86.645 12.888 ;
     RECT  86.105 24.72 86.645 26.808 ;
     RECT  86.393 46.848 86.645 46.92 ;
     RECT  86.569 33.072 86.681 33.096 ;
     RECT  86.641 63.792 86.681 68.952 ;
     RECT  86.605 72.336 86.681 73.56 ;
     RECT  86.605 80.304 86.713 80.808 ;
     RECT  86.629 28.272 86.716 30.648 ;
     RECT  86.681 64.416 86.857 68.952 ;
     RECT  85.889 39.744 86.861 39.864 ;
     RECT  86.609 60.816 86.861 60.84 ;
     RECT  85.859 74.64 86.897 74.664 ;
     RECT  86.645 46.848 86.933 46.872 ;
     RECT  86.629 37.008 86.965 38.76 ;
     RECT  86.861 39.744 86.965 39.768 ;
     RECT  86.857 64.416 86.969 69.336 ;
     RECT  86.641 35.04 87.001 35.064 ;
     RECT  86.713 79.872 87.005 80.808 ;
     RECT  86.497 51.6 87.037 51.624 ;
     RECT  86.105 3.072 87.041 5.736 ;
     RECT  85.993 14.064 87.041 14.808 ;
     RECT  87.001 34.704 87.041 35.064 ;
     RECT  86.716 28.272 87.049 29.064 ;
     RECT  86.969 67.536 87.068 69.336 ;
     RECT  86.969 64.416 87.077 66.36 ;
     RECT  86.483 16.224 87.145 17.64 ;
     RECT  86.245 18.768 87.145 18.792 ;
     RECT  86.105 20.112 87.149 21.768 ;
     RECT  87.049 28.272 87.149 28.296 ;
     RECT  86.716 30.192 87.149 30.648 ;
     RECT  86.965 37.008 87.149 39.768 ;
     RECT  87.149 30.624 87.155 30.648 ;
     RECT  86.645 11.424 87.185 11.976 ;
     RECT  87.037 51.408 87.185 51.624 ;
     RECT  86.537 62.448 87.185 62.472 ;
     RECT  87.145 16.224 87.221 18.792 ;
     RECT  87.149 37.008 87.221 37.032 ;
     RECT  86.605 41.136 87.221 45.048 ;
     RECT  87.068 67.536 87.253 69.72 ;
     RECT  87.253 67.536 87.257 69.816 ;
     RECT  86.681 72.336 87.257 72.936 ;
     RECT  87.005 79.872 87.257 80.328 ;
     RECT  86.645 25.68 87.293 26.808 ;
     RECT  87.257 67.536 87.293 67.56 ;
     RECT  87.041 3.648 87.301 5.736 ;
     RECT  87.293 26.016 87.337 26.808 ;
     RECT  87.221 43.296 87.365 45.048 ;
     RECT  87.257 72.816 87.365 72.936 ;
     RECT  87.301 3.648 87.388 5.88 ;
     RECT  87.221 16.56 87.397 18.792 ;
     RECT  87.149 20.112 87.397 21 ;
     RECT  87.397 16.56 87.401 21 ;
     RECT  87.337 26.016 87.401 26.04 ;
     RECT  87.185 51.408 87.401 51.432 ;
     RECT  87.257 68.64 87.401 69.816 ;
     RECT  87.388 3.648 87.409 5.736 ;
     RECT  87.409 3.648 87.436 4.824 ;
     RECT  87.401 16.56 87.437 19.464 ;
     RECT  87.365 43.296 87.437 43.608 ;
     RECT  87.401 68.64 87.437 69.528 ;
     RECT  87.437 16.56 87.443 17.64 ;
     RECT  87.433 8.688 87.445 8.712 ;
     RECT  87.041 14.784 87.473 14.808 ;
     RECT  87.401 20.976 87.473 21 ;
     RECT  86.857 50.4 87.473 50.424 ;
     RECT  87.077 64.416 87.473 66.024 ;
     RECT  86.065 7.056 87.509 7.08 ;
     RECT  87.437 18.768 87.509 19.464 ;
     RECT  87.149 38.064 87.509 39.768 ;
     RECT  87.221 41.136 87.509 41.736 ;
     RECT  87.473 64.416 87.509 64.872 ;
     RECT  87.473 66 87.509 66.024 ;
     RECT  87.445 8.688 87.532 9.432 ;
     RECT  87.185 11.424 87.537 11.448 ;
     RECT  87.509 18.768 87.545 18.792 ;
     RECT  87.509 39.744 87.545 39.768 ;
     RECT  87.437 43.296 87.545 43.368 ;
     RECT  87.433 46.752 87.545 46.776 ;
     RECT  87.365 72.912 87.545 72.936 ;
     RECT  87.443 16.56 87.581 16.584 ;
     RECT  87.041 34.704 87.617 34.728 ;
     RECT  87.509 64.416 87.653 64.44 ;
     RECT  87.532 8.688 87.797 8.712 ;
     RECT  87.436 3.648 87.833 4.44 ;
     RECT  87.437 68.688 87.833 69.384 ;
     RECT  87.833 68.688 87.869 68.712 ;
     RECT  87.649 46.608 87.905 46.728 ;
     RECT  87.545 43.344 87.977 43.368 ;
     RECT  87.833 4.416 88.013 4.44 ;
     RECT  87.509 41.136 90.601 41.16 ;
     RECT  87.365 45.024 90.601 45.048 ;
    LAYER M5 ;
     RECT  2.4 2.137 2.52 2.151 ;
     RECT  7.8 2.137 7.92 2.151 ;
     RECT  24 2.137 24.12 2.151 ;
     RECT  34.8 2.137 34.92 2.151 ;
     RECT  40.2 2.137 40.32 2.151 ;
     RECT  51 2.137 51.144 2.151 ;
     RECT  56.4 2.137 56.52 2.151 ;
     RECT  61.8 2.137 61.92 2.151 ;
     RECT  67.2 2.137 67.32 2.151 ;
     RECT  72.6 2.137 72.72 2.151 ;
     RECT  78 2.137 78.12 2.151 ;
     RECT  83.4 2.137 83.52 2.151 ;
     RECT  18.6 2.137 19.656 2.195 ;
     RECT  40.2 2.151 40.512 2.245 ;
     RECT  45.6 2.137 45.912 2.245 ;
     RECT  56.4 2.151 56.712 2.245 ;
     RECT  61.8 2.151 62.112 2.245 ;
     RECT  83.4 2.151 83.712 2.245 ;
     RECT  74.64 2.197 74.664 2.339 ;
     RECT  78 2.151 78.312 2.581 ;
     RECT  82.512 2.245 84.504 2.725 ;
     RECT  45.216 2.245 45.912 2.773 ;
     RECT  77.136 2.581 78.312 2.773 ;
     RECT  34.8 2.151 35.112 2.821 ;
     RECT  61.68 2.245 62.112 2.821 ;
     RECT  72.6 2.151 72.912 2.821 ;
     RECT  79.44 2.245 79.464 2.867 ;
     RECT  81.6 2.725 84.504 2.867 ;
     RECT  69.936 2.821 69.96 2.917 ;
     RECT  29.28 2.137 29.712 2.965 ;
     RECT  72.6 2.821 73.848 3.109 ;
     RECT  13.2 2.137 13.512 3.301 ;
     RECT  29.28 2.965 29.832 3.301 ;
     RECT  49.152 2.677 49.176 3.301 ;
     RECT  49.008 3.301 49.176 3.347 ;
     RECT  55.872 2.245 56.856 3.347 ;
     RECT  22.8 2.917 22.824 3.395 ;
     RECT  40.08 2.245 40.512 3.443 ;
     RECT  77.136 2.773 78.408 3.443 ;
     RECT  82.416 2.867 84.504 3.443 ;
     RECT  34.8 2.821 35.496 3.587 ;
     RECT  28.608 3.301 29.832 3.683 ;
     RECT  61.248 2.821 62.112 3.685 ;
     RECT  83.4 3.443 84.504 3.731 ;
     RECT  59.28 2.245 59.304 3.733 ;
     RECT  27.264 2.245 27.288 3.779 ;
     RECT  59.28 3.733 59.784 3.779 ;
     RECT  71.808 3.109 73.848 3.827 ;
     RECT  64.944 2.245 64.968 3.829 ;
     RECT  44.448 2.773 45.912 3.875 ;
     RECT  71.808 3.827 73.176 3.875 ;
     RECT  33.504 2.629 33.528 4.019 ;
     RECT  49.008 3.347 49.032 4.019 ;
     RECT  71.808 3.875 72.912 4.019 ;
     RECT  7.8 2.151 8.112 4.021 ;
     RECT  24 2.151 24.312 4.117 ;
     RECT  75.072 3.397 75.096 4.213 ;
     RECT  18.6 2.195 18.912 4.261 ;
     RECT  64.512 3.829 64.968 4.357 ;
     RECT  69.936 2.917 70.68 4.357 ;
     RECT  61.248 3.685 62.664 4.499 ;
     RECT  68.976 4.357 70.68 4.499 ;
     RECT  10.272 3.397 10.296 4.501 ;
     RECT  78 3.443 78.312 4.501 ;
     RECT  64.512 4.357 65.16 4.595 ;
     RECT  69.936 4.499 70.68 4.643 ;
     RECT  18.6 4.261 19.56 4.645 ;
     RECT  86.928 3.109 86.952 4.789 ;
     RECT  86.928 4.789 87.384 4.837 ;
     RECT  10.032 4.501 10.296 4.883 ;
     RECT  40.2 3.443 40.512 4.885 ;
     RECT  6.96 4.021 8.112 5.077 ;
     RECT  83.4 3.731 83.712 5.077 ;
     RECT  64.512 4.595 64.536 5.171 ;
     RECT  59.76 3.779 59.784 5.219 ;
     RECT  24 4.117 24.408 5.269 ;
     RECT  5.472 2.245 5.496 5.459 ;
     RECT  18.24 4.645 19.56 5.459 ;
     RECT  12.24 3.301 13.512 5.461 ;
     RECT  67.2 2.151 67.512 5.509 ;
     RECT  12.24 5.461 13.608 5.557 ;
     RECT  72.384 4.019 72.912 5.605 ;
     RECT  69.936 4.643 69.96 5.651 ;
     RECT  51 2.151 51.312 5.653 ;
     RECT  78 4.501 79.08 5.653 ;
     RECT  29.4 3.683 29.712 5.701 ;
     RECT  39.36 4.885 40.512 5.747 ;
     RECT  45.12 3.875 45.912 5.747 ;
     RECT  85.968 4.837 87.384 5.747 ;
     RECT  38.208 5.653 38.232 5.749 ;
     RECT  38.208 5.749 38.472 5.795 ;
     RECT  70.992 5.605 71.016 5.845 ;
     RECT  24 5.269 24.456 6.179 ;
     RECT  72.288 5.605 72.912 6.227 ;
     RECT  43.776 5.701 43.8 6.229 ;
     RECT  56.4 3.347 56.856 6.229 ;
     RECT  75.072 4.213 75.624 6.229 ;
     RECT  12.24 5.557 13.656 6.275 ;
     RECT  83.4 5.077 84.072 6.277 ;
     RECT  6.96 5.077 8.376 6.323 ;
     RECT  15.504 3.925 15.528 6.323 ;
     RECT  51 5.653 51.864 6.515 ;
     RECT  78 5.653 79.896 6.563 ;
     RECT  27.12 5.317 27.144 6.803 ;
     RECT  53.856 5.749 53.88 6.851 ;
     RECT  74.688 6.229 75.624 6.851 ;
     RECT  70.128 5.845 71.016 6.995 ;
     RECT  41.568 6.229 41.592 7.091 ;
     RECT  87.312 5.747 87.336 7.091 ;
     RECT  55.872 6.229 56.856 7.187 ;
     RECT  56.4 7.187 56.856 7.189 ;
     RECT  32.304 6.709 32.328 7.381 ;
     RECT  51 6.515 51.312 7.381 ;
     RECT  67.2 5.509 67.608 7.381 ;
     RECT  72.384 6.227 72.912 7.381 ;
     RECT  32.304 7.381 32.472 7.427 ;
     RECT  72.384 7.381 73.176 7.621 ;
     RECT  43.776 6.229 44.616 7.859 ;
     RECT  24 6.179 24.312 7.909 ;
     RECT  67.056 7.381 67.608 7.909 ;
     RECT  68.736 4.885 68.76 7.909 ;
     RECT  20.544 5.605 20.568 7.955 ;
     RECT  12.288 6.275 13.656 7.957 ;
     RECT  48.336 4.357 48.36 7.957 ;
     RECT  75.408 6.851 75.624 7.957 ;
     RECT  47.904 7.957 48.36 8.003 ;
     RECT  67.056 7.909 68.76 8.003 ;
     RECT  75.264 7.957 75.624 8.003 ;
     RECT  64.464 6.181 64.488 8.147 ;
     RECT  78 6.563 79.8 8.243 ;
     RECT  56.4 7.189 57.432 8.293 ;
     RECT  43.776 7.859 43.896 8.389 ;
     RECT  43.344 8.389 43.896 8.435 ;
     RECT  40.2 5.747 40.512 8.437 ;
     RECT  75.264 8.003 75.576 8.483 ;
     RECT  78 8.243 78.408 8.483 ;
     RECT  83.4 6.277 84.648 8.483 ;
     RECT  6.96 6.323 8.112 8.485 ;
     RECT  70.992 6.995 71.016 8.485 ;
     RECT  81.792 8.197 81.816 8.485 ;
     RECT  32.448 7.427 32.472 8.579 ;
     RECT  79.776 8.243 79.8 8.723 ;
     RECT  78 8.483 78.312 8.821 ;
     RECT  50.88 7.381 51.312 8.867 ;
     RECT  72.384 7.621 73.8 9.013 ;
     RECT  75.264 8.483 75.432 9.059 ;
     RECT  24 7.909 25.128 9.061 ;
     RECT  28.512 5.701 29.712 9.061 ;
     RECT  67.056 8.003 67.512 9.061 ;
     RECT  72.336 9.013 73.8 9.155 ;
     RECT  75.264 9.059 75.288 9.155 ;
     RECT  15.696 8.245 15.72 9.203 ;
     RECT  23.856 9.061 25.128 9.203 ;
     RECT  43.344 8.435 43.368 9.203 ;
     RECT  56.4 8.293 57.816 9.203 ;
     RECT  72.384 9.155 73.8 9.203 ;
     RECT  70.608 8.485 71.016 9.299 ;
     RECT  40.2 8.437 40.632 9.493 ;
     RECT  38.448 5.795 38.472 9.637 ;
     RECT  28.128 9.061 29.712 9.683 ;
     RECT  38.448 9.637 38.568 9.683 ;
     RECT  64.944 9.109 64.968 9.731 ;
     RECT  66.624 9.061 67.512 9.731 ;
     RECT  70.608 9.299 70.632 9.779 ;
     RECT  28.512 9.683 29.712 9.877 ;
     RECT  39.84 9.493 40.632 9.925 ;
     RECT  77.76 8.821 78.312 10.213 ;
     RECT  68.544 8.003 68.76 10.307 ;
     RECT  72.384 9.203 73.176 10.307 ;
     RECT  18.6 5.459 19.56 10.453 ;
     RECT  28.512 9.877 29.832 10.453 ;
     RECT  51 8.867 51.312 10.453 ;
     RECT  39.84 9.925 41.496 10.597 ;
     RECT  50.112 10.453 51.312 10.597 ;
     RECT  25.392 10.069 25.416 10.643 ;
     RECT  81.312 8.485 81.816 10.693 ;
     RECT  81.312 10.693 82.056 10.883 ;
     RECT  39.84 10.597 42.408 10.931 ;
     RECT  72.384 10.307 72.912 10.931 ;
     RECT  17.712 10.453 19.56 11.123 ;
     RECT  72.432 10.931 72.912 11.317 ;
     RECT  33.024 9.733 33.048 11.363 ;
     RECT  41.616 10.931 42.408 11.365 ;
     RECT  68.736 10.307 68.76 11.365 ;
     RECT  28.512 10.453 30.504 11.411 ;
     RECT  31.824 10.741 31.848 11.411 ;
     RECT  41.616 11.365 42.936 11.411 ;
     RECT  47.904 8.003 47.928 11.411 ;
     RECT  68.64 11.365 68.76 11.411 ;
     RECT  38.544 9.683 38.568 11.459 ;
     RECT  50.112 10.597 51.432 11.459 ;
     RECT  85.872 10.789 85.896 11.459 ;
     RECT  87.456 9.397 87.48 11.459 ;
     RECT  34.8 3.587 35.112 11.797 ;
     RECT  77.76 10.213 78.456 11.797 ;
     RECT  11.76 7.957 13.656 11.845 ;
     RECT  56.4 9.203 56.856 11.845 ;
     RECT  59.28 11.269 59.304 11.891 ;
     RECT  23.856 9.203 24.312 11.939 ;
     RECT  17.712 11.123 18.912 11.941 ;
     RECT  38.496 11.845 38.52 11.941 ;
     RECT  27.12 11.269 27.144 12.035 ;
     RECT  67.2 9.731 67.512 12.037 ;
     RECT  6.96 8.485 9.048 12.179 ;
     RECT  22.368 11.509 22.392 12.227 ;
     RECT  50.112 11.459 51.312 12.227 ;
     RECT  72.432 11.317 73.128 12.373 ;
     RECT  61.248 4.499 62.112 12.421 ;
     RECT  53.76 11.365 53.784 12.467 ;
     RECT  81.792 10.883 82.056 12.467 ;
     RECT  7.68 12.179 9.048 12.517 ;
     RECT  10.032 4.883 10.056 12.517 ;
     RECT  65.088 11.941 65.112 12.517 ;
     RECT  15.36 11.317 15.384 12.563 ;
     RECT  34.8 11.797 35.352 12.563 ;
     RECT  41.616 11.411 41.64 12.563 ;
     RECT  50.496 12.227 51.312 12.755 ;
     RECT  16.656 11.653 16.68 12.757 ;
     RECT  17.664 11.941 18.912 12.757 ;
     RECT  16.656 12.757 18.912 12.803 ;
     RECT  77.76 11.797 78.648 12.803 ;
     RECT  56.4 11.845 57.048 12.805 ;
     RECT  28.512 11.411 29.712 12.853 ;
     RECT  17.04 12.803 18.912 12.899 ;
     RECT  28.512 12.853 30.264 12.899 ;
     RECT  55.584 12.805 57.048 13.043 ;
     RECT  34.8 12.563 35.112 13.045 ;
     RECT  67.2 12.037 67.656 13.045 ;
     RECT  72.432 12.373 73.416 13.045 ;
     RECT  59.424 12.325 59.448 13.093 ;
     RECT  26.976 13.045 27 13.285 ;
     RECT  37.632 11.941 38.52 13.285 ;
     RECT  7.68 12.517 10.056 13.331 ;
     RECT  26.88 13.285 27 13.331 ;
     RECT  37.008 13.285 38.52 13.331 ;
     RECT  65.088 12.517 65.4 13.331 ;
     RECT  65.088 13.331 65.112 13.429 ;
     RECT  50.592 12.755 51.312 13.525 ;
     RECT  47.808 12.517 47.832 13.619 ;
     RECT  72.288 13.045 73.416 13.621 ;
     RECT  37.008 13.331 37.656 13.715 ;
     RECT  70.128 11.173 70.152 13.715 ;
     RECT  29.28 12.899 30.264 13.811 ;
     RECT  80.304 12.517 80.328 13.811 ;
     RECT  26.88 13.331 26.904 13.859 ;
     RECT  20.496 12.517 20.52 14.003 ;
     RECT  31.344 11.941 31.368 14.099 ;
     RECT  34.704 13.045 35.112 14.099 ;
     RECT  82.032 12.467 82.056 14.099 ;
     RECT  86.64 11.941 86.664 14.099 ;
     RECT  24 11.939 24.312 14.101 ;
     RECT  66.672 13.045 67.656 14.147 ;
     RECT  17.664 12.899 18.912 14.149 ;
     RECT  17.04 14.149 18.912 14.195 ;
     RECT  39.84 10.931 40.512 14.197 ;
     RECT  83.4 8.483 83.712 14.197 ;
     RECT  61.008 12.421 62.112 14.339 ;
     RECT  72.288 13.621 73.56 14.341 ;
     RECT  50.592 13.525 51.432 14.627 ;
     RECT  55.584 13.043 56.856 14.629 ;
     RECT  59.424 13.093 59.688 14.675 ;
     RECT  42.912 11.411 42.936 14.677 ;
     RECT  77.76 12.803 78.312 14.677 ;
     RECT  29.28 13.811 30.12 14.773 ;
     RECT  23.904 14.101 24.312 14.867 ;
     RECT  42.912 14.677 43.56 14.867 ;
     RECT  22.224 12.757 22.248 15.059 ;
     RECT  7.68 13.331 9.048 15.107 ;
     RECT  11.424 11.845 13.656 15.203 ;
     RECT  63.792 14.773 63.816 15.203 ;
     RECT  67.2 14.147 67.656 15.253 ;
     RECT  68.64 11.411 68.664 15.253 ;
     RECT  64.992 13.429 65.112 15.349 ;
     RECT  76.896 14.677 78.312 15.395 ;
     RECT  11.616 15.203 13.656 15.445 ;
     RECT  70.704 14.773 70.728 15.491 ;
     RECT  39.36 14.197 40.512 15.635 ;
     RECT  59.424 14.675 59.448 15.877 ;
     RECT  67.2 15.253 68.664 15.877 ;
     RECT  67.2 15.877 68.952 15.923 ;
     RECT  85.728 15.061 85.752 15.925 ;
     RECT  10.032 13.331 10.056 16.019 ;
     RECT  15.936 15.349 15.96 16.019 ;
     RECT  29.28 14.773 30.552 16.019 ;
     RECT  55.584 14.629 57 16.019 ;
     RECT  34.8 14.099 35.112 16.117 ;
     RECT  72.288 14.341 74.184 16.211 ;
     RECT  2.4 2.151 2.712 16.213 ;
     RECT  85.728 15.925 86.472 16.259 ;
     RECT  61.68 14.339 62.112 16.307 ;
     RECT  5.712 15.061 5.736 16.501 ;
     RECT  7.8 15.107 9.048 16.501 ;
     RECT  11.616 15.445 13.8 16.501 ;
     RECT  83.4 14.197 83.88 16.501 ;
     RECT  28.224 15.637 28.248 16.595 ;
     RECT  7.68 16.501 9.048 16.597 ;
     RECT  67.2 15.923 67.8 16.643 ;
     RECT  24 14.867 24.312 16.933 ;
     RECT  20.112 15.829 20.136 16.979 ;
     RECT  83.4 16.501 84.072 16.981 ;
     RECT  17.04 14.195 17.064 17.029 ;
     RECT  17.04 17.029 17.16 17.077 ;
     RECT  29.28 16.019 30.36 17.077 ;
     RECT  55.584 16.019 56.856 17.077 ;
     RECT  77.76 15.395 78.312 17.077 ;
     RECT  17.04 17.077 17.352 17.123 ;
     RECT  49.536 16.501 49.56 17.123 ;
     RECT  83.4 16.981 84.936 17.123 ;
     RECT  34.656 16.117 35.112 17.171 ;
     RECT  10.704 16.501 13.8 17.267 ;
     RECT  2.4 16.213 3.288 17.365 ;
     RECT  7.68 16.597 9.72 17.507 ;
     RECT  5.04 16.501 5.736 17.509 ;
     RECT  5.04 17.509 6.168 17.555 ;
     RECT  67.2 16.643 67.656 17.605 ;
     RECT  72.288 16.211 72.912 17.605 ;
     RECT  74.16 16.211 74.184 17.605 ;
     RECT  11.616 17.267 13.8 17.651 ;
     RECT  83.4 17.123 84.072 17.651 ;
     RECT  7.68 17.507 9.048 17.699 ;
     RECT  53.616 15.349 53.64 17.843 ;
     RECT  29.28 17.077 30.408 17.891 ;
     RECT  5.04 17.555 5.064 17.893 ;
     RECT  55.584 17.077 56.904 17.893 ;
     RECT  59.424 15.877 59.496 17.939 ;
     RECT  55.392 17.893 56.904 17.989 ;
     RECT  17.136 17.123 17.352 18.179 ;
     RECT  34.8 17.171 35.112 18.181 ;
     RECT  24 16.933 25.128 18.229 ;
     RECT  24 18.229 25.656 18.275 ;
     RECT  67.2 17.605 67.848 18.275 ;
     RECT  68.928 15.923 68.952 18.275 ;
     RECT  32.592 17.845 32.616 18.277 ;
     RECT  26.736 16.981 26.76 18.371 ;
     RECT  47.328 17.653 47.352 18.419 ;
     RECT  55.056 17.989 56.904 18.419 ;
     RECT  2.4 17.365 3.72 18.515 ;
     RECT  50.592 14.627 51.312 18.563 ;
     RECT  3.696 18.515 3.72 18.613 ;
     RECT  4.752 17.893 5.064 18.613 ;
     RECT  32.592 18.277 32.712 18.659 ;
     RECT  32.592 18.659 32.616 18.755 ;
     RECT  3.696 18.613 5.064 18.757 ;
     RECT  6.144 17.555 6.168 18.757 ;
     RECT  3.696 18.757 5.112 18.851 ;
     RECT  25.632 18.275 25.656 18.851 ;
     RECT  37.008 13.715 37.032 18.851 ;
     RECT  85.104 17.605 85.128 18.851 ;
     RECT  61.8 16.307 62.112 19.093 ;
     RECT  6.144 18.757 6.744 19.139 ;
     RECT  29.28 17.891 30.36 19.235 ;
     RECT  64.992 15.349 65.736 19.237 ;
     RECT  51 18.563 51.312 19.333 ;
     RECT  83.4 17.651 83.88 19.333 ;
     RECT  87.408 17.461 87.432 19.475 ;
     RECT  7.8 17.699 9.048 19.477 ;
     RECT  77.76 17.077 78.408 19.525 ;
     RECT  7.68 19.477 9.048 19.619 ;
     RECT  61.296 19.093 62.112 19.669 ;
     RECT  4.512 18.851 5.112 19.861 ;
     RECT  6.144 19.139 6.264 19.861 ;
     RECT  52.848 19.093 52.872 19.909 ;
     RECT  69.312 19.525 69.336 19.909 ;
     RECT  52.848 19.909 53.592 19.955 ;
     RECT  44.448 19.333 44.472 20.003 ;
     RECT  51 19.333 51.432 20.003 ;
     RECT  55.056 18.419 56.856 20.003 ;
     RECT  71.28 19.333 71.304 20.003 ;
     RECT  72.288 17.605 74.184 20.003 ;
     RECT  14.832 14.101 14.856 20.053 ;
     RECT  24 18.275 24.312 20.149 ;
     RECT  34.8 18.181 35.352 20.149 ;
     RECT  4.512 19.861 6.264 20.197 ;
     RECT  82.608 19.333 83.88 20.291 ;
     RECT  61.296 19.669 62.664 20.339 ;
     RECT  53.04 19.955 53.592 20.437 ;
     RECT  11.616 17.651 13.608 20.485 ;
     RECT  14.784 20.053 14.856 20.485 ;
     RECT  23.472 20.149 25.08 20.485 ;
     RECT  20.976 19.621 21 20.579 ;
     RECT  48.96 17.605 48.984 20.579 ;
     RECT  59.472 17.939 59.496 20.579 ;
     RECT  64.368 19.237 65.736 20.579 ;
     RECT  69.312 19.909 69.528 20.579 ;
     RECT  74.16 20.003 74.184 20.579 ;
     RECT  82.848 20.291 83.88 20.579 ;
     RECT  67.2 18.275 67.656 20.629 ;
     RECT  55.392 20.003 56.856 20.725 ;
     RECT  45.6 5.747 45.912 20.773 ;
     RECT  39.84 15.635 40.512 20.963 ;
     RECT  53.04 20.437 53.976 20.965 ;
     RECT  55.392 20.725 57.624 20.965 ;
     RECT  11.616 20.485 14.856 21.155 ;
     RECT  23.328 20.485 25.08 21.155 ;
     RECT  29.28 19.235 30.264 21.155 ;
     RECT  42.912 14.867 42.936 21.155 ;
     RECT  77.76 19.525 78.648 21.155 ;
     RECT  23.472 21.155 25.08 21.203 ;
     RECT  53.04 20.965 57.624 21.299 ;
     RECT  29.28 21.155 29.712 21.493 ;
     RECT  10.272 20.485 10.296 21.541 ;
     RECT  64.992 20.579 65.736 21.541 ;
     RECT  9.648 21.541 10.296 21.589 ;
     RECT  34.8 20.149 35.448 21.635 ;
     RECT  61.8 20.339 62.112 21.637 ;
     RECT  69.312 20.579 69.336 21.637 ;
     RECT  9.552 21.589 10.296 21.683 ;
     RECT  11.76 21.155 13.512 21.683 ;
     RECT  15.936 20.773 15.96 21.683 ;
     RECT  53.952 21.299 54.168 21.683 ;
     RECT  55.392 21.299 57.624 21.683 ;
     RECT  77.76 21.155 78.408 21.683 ;
     RECT  80.064 20.533 80.088 21.683 ;
     RECT  45.6 20.773 46.008 21.781 ;
     RECT  4.512 20.197 6.312 21.971 ;
     RECT  29.232 21.493 29.712 21.971 ;
     RECT  31.92 20.821 31.944 22.069 ;
     RECT  45.6 21.781 46.056 22.163 ;
     RECT  31.296 22.069 31.944 22.211 ;
     RECT  82.848 20.579 83.712 22.211 ;
     RECT  11.76 21.683 11.784 22.259 ;
     RECT  26.688 18.757 26.712 22.259 ;
     RECT  54.144 21.683 54.168 22.259 ;
     RECT  4.512 21.971 6.264 22.309 ;
     RECT  61.8 21.637 62.904 22.451 ;
     RECT  24 21.203 24.312 22.549 ;
     RECT  45.6 22.163 46.008 22.597 ;
     RECT  69.12 21.637 69.336 22.597 ;
     RECT  31.296 22.211 31.32 22.643 ;
     RECT  4.08 22.309 6.264 22.693 ;
     RECT  44.88 22.597 46.008 22.739 ;
     RECT  64.416 21.541 65.736 22.787 ;
     RECT  9.552 21.683 9.672 23.125 ;
     RECT  34.8 21.635 35.112 23.125 ;
     RECT  9.456 23.125 9.672 23.315 ;
     RECT  21.744 21.637 21.768 23.315 ;
     RECT  13.2 21.683 13.512 23.317 ;
     RECT  14.832 21.155 14.856 23.317 ;
     RECT  17.328 18.179 17.352 23.317 ;
     RECT  51 20.003 51.312 23.317 ;
     RECT  67.2 20.629 67.8 23.317 ;
     RECT  69.12 22.597 70.248 23.317 ;
     RECT  14.832 23.317 15.24 23.411 ;
     RECT  16.896 23.317 17.352 23.411 ;
     RECT  64.992 22.787 65.736 23.411 ;
     RECT  67.2 23.317 70.248 23.459 ;
     RECT  64.992 23.411 65.112 23.555 ;
     RECT  32.304 23.317 32.328 23.605 ;
     RECT  31.44 23.605 32.328 23.651 ;
     RECT  22.368 23.653 22.392 23.893 ;
     RECT  23.712 22.549 24.312 23.893 ;
     RECT  16.896 23.411 16.92 23.939 ;
     RECT  81.024 23.029 81.048 23.987 ;
     RECT  79.44 23.317 79.464 24.037 ;
     RECT  31.44 23.651 31.464 24.371 ;
     RECT  58.128 22.741 58.152 24.371 ;
     RECT  18.6 14.195 18.912 24.373 ;
     RECT  55.392 21.683 56.856 24.469 ;
     RECT  65.088 23.555 65.112 24.469 ;
     RECT  10.848 23.269 10.872 24.515 ;
     RECT  9.456 23.315 9.576 24.563 ;
     RECT  34.8 23.125 35.448 24.563 ;
     RECT  55.248 24.469 56.856 24.563 ;
     RECT  3.984 22.693 6.264 24.659 ;
     RECT  5.328 24.659 6.264 24.757 ;
     RECT  7.8 19.619 8.112 24.757 ;
     RECT  37.296 23.269 37.32 24.899 ;
     RECT  29.28 21.971 29.712 24.997 ;
     RECT  61.8 22.451 62.112 25.045 ;
     RECT  79.44 24.037 79.656 25.091 ;
     RECT  55.248 24.563 55.272 25.093 ;
     RECT  40.032 20.963 40.512 25.139 ;
     RECT  53.28 23.893 53.304 25.139 ;
     RECT  54.816 25.093 55.272 25.139 ;
     RECT  83.4 22.211 83.712 25.189 ;
     RECT  27.312 24.469 27.336 25.427 ;
     RECT  56.4 24.563 56.856 25.477 ;
     RECT  3.984 24.659 4.008 25.523 ;
     RECT  83.136 25.189 83.712 25.573 ;
     RECT  33.648 24.469 33.672 25.667 ;
     RECT  54.816 25.139 54.84 25.667 ;
     RECT  48.864 24.469 48.888 25.715 ;
     RECT  61.536 25.045 62.112 25.955 ;
     RECT  5.328 24.757 8.112 26.003 ;
     RECT  7.056 26.003 8.112 26.053 ;
     RECT  43.008 25.045 43.032 26.053 ;
     RECT  43.008 26.053 43.176 26.099 ;
     RECT  74.016 25.621 74.04 26.149 ;
     RECT  22.368 23.893 24.312 26.197 ;
     RECT  65.088 24.469 65.544 26.197 ;
     RECT  85.488 23.317 85.512 26.197 ;
     RECT  5.328 26.003 5.736 26.243 ;
     RECT  13.2 23.317 13.608 26.243 ;
     RECT  22.176 26.197 24.312 26.243 ;
     RECT  85.488 26.197 85.608 26.243 ;
     RECT  79.44 25.091 79.464 26.293 ;
     RECT  80.928 25.573 80.952 26.293 ;
     RECT  82.752 25.573 83.712 26.339 ;
     RECT  26.208 23.317 26.232 26.341 ;
     RECT  34.8 24.563 35.256 26.627 ;
     RECT  50.352 23.317 51.312 26.629 ;
     RECT  77.76 21.683 78.312 26.629 ;
     RECT  26.208 26.341 26.664 26.677 ;
     RECT  58.08 25.333 58.104 26.725 ;
     RECT  74.016 26.149 74.712 26.771 ;
     RECT  18.24 24.373 18.912 26.819 ;
     RECT  85.584 26.243 85.608 26.819 ;
     RECT  87.264 26.005 87.288 26.819 ;
     RECT  79.44 26.293 80.952 27.059 ;
     RECT  50.352 26.629 51.864 27.061 ;
     RECT  40.2 25.139 40.512 27.157 ;
     RECT  56.4 25.477 57.096 27.203 ;
     RECT  13.2 26.243 13.512 27.301 ;
     RECT  79.44 27.059 79.752 27.347 ;
     RECT  60.192 26.725 60.216 27.395 ;
     RECT  83.136 26.339 83.712 27.395 ;
     RECT  5.472 26.243 5.496 27.877 ;
     RECT  45.6 22.739 46.008 27.877 ;
     RECT  64.08 23.893 64.104 27.877 ;
     RECT  72.288 20.003 72.912 27.877 ;
     RECT  13.2 27.301 13.848 27.923 ;
     RECT  20.112 26.725 20.136 27.923 ;
     RECT  22.176 26.243 22.68 27.923 ;
     RECT  58.08 26.725 58.68 27.971 ;
     RECT  65.088 26.197 66.12 27.971 ;
     RECT  67.2 23.459 69.336 28.069 ;
     RECT  67.2 28.069 70.104 28.115 ;
     RECT  48.48 27.877 48.504 28.211 ;
     RECT  77.088 26.629 78.408 28.307 ;
     RECT  15.216 23.411 15.24 28.357 ;
     RECT  15.216 28.357 16.104 28.403 ;
     RECT  40.2 27.157 40.632 28.453 ;
     RECT  5.472 27.877 5.976 28.499 ;
     RECT  5.472 28.499 5.496 28.547 ;
     RECT  29.088 24.997 29.712 28.547 ;
     RECT  33.6 26.485 33.624 28.547 ;
     RECT  26.16 26.677 26.664 28.691 ;
     RECT  50.16 27.061 51.864 28.691 ;
     RECT  80.928 27.059 80.952 28.787 ;
     RECT  45.6 27.877 46.776 28.979 ;
     RECT  77.088 28.307 78.312 28.979 ;
     RECT  43.152 26.099 43.176 28.981 ;
     RECT  54.96 28.117 54.984 29.027 ;
     RECT  13.2 27.923 13.512 29.029 ;
     RECT  56.4 27.203 56.856 29.077 ;
     RECT  9.552 24.563 9.576 29.123 ;
     RECT  72.096 27.877 72.912 29.123 ;
     RECT  26.16 28.691 26.184 29.219 ;
     RECT  75.36 28.261 75.384 29.221 ;
     RECT  42.768 28.981 43.176 29.363 ;
     RECT  75.36 29.221 76.152 29.363 ;
     RECT  86.976 29.029 87 29.557 ;
     RECT  4.416 29.557 4.44 29.605 ;
     RECT  12.624 29.029 13.512 29.605 ;
     RECT  16.08 28.403 16.104 29.605 ;
     RECT  34.8 26.627 35.112 29.605 ;
     RECT  63.648 27.877 64.104 29.699 ;
     RECT  10.8 27.877 10.824 29.747 ;
     RECT  79.44 27.347 79.464 29.749 ;
     RECT  74.016 26.771 74.04 29.795 ;
     RECT  79.44 29.749 80.04 29.795 ;
     RECT  61.8 25.955 62.112 29.845 ;
     RECT  58.08 27.971 58.104 29.939 ;
     RECT  22.176 27.923 22.2 30.035 ;
     RECT  40.2 28.453 40.872 30.035 ;
     RECT  15.6 29.605 16.104 30.037 ;
     RECT  50.16 28.691 51.312 30.037 ;
     RECT  7.056 26.053 8.568 30.133 ;
     RECT  4.416 29.605 4.536 30.181 ;
     RECT  6.384 30.133 8.568 30.181 ;
     RECT  18.6 26.819 18.912 30.181 ;
     RECT  12.528 29.605 13.512 30.275 ;
     RECT  50.16 30.037 51.48 30.469 ;
     RECT  50.16 30.469 52.248 30.517 ;
     RECT  45.6 28.979 46.008 30.565 ;
     RECT  26.064 30.229 26.088 30.613 ;
     RECT  67.2 28.115 67.8 30.613 ;
     RECT  86.64 29.557 87 30.613 ;
     RECT  2.4 18.515 2.712 30.661 ;
     RECT  50.16 30.517 53.064 30.709 ;
     RECT  77.664 28.979 78.312 30.757 ;
     RECT  2.4 30.661 3 30.803 ;
     RECT  26.064 30.613 26.808 30.803 ;
     RECT  45.6 30.565 46.728 30.803 ;
     RECT  50.16 30.709 53.16 30.803 ;
     RECT  75.264 29.893 75.288 30.803 ;
     RECT  59.856 29.893 59.88 30.805 ;
     RECT  61.104 29.845 62.112 30.805 ;
     RECT  26.064 30.803 26.136 30.851 ;
     RECT  53.136 30.803 53.16 30.851 ;
     RECT  59.856 30.805 62.112 30.851 ;
     RECT  2.4 30.803 2.904 30.899 ;
     RECT  45.6 30.803 46.008 30.899 ;
     RECT  56.4 29.077 56.952 31.091 ;
     RECT  47.856 30.325 47.88 31.283 ;
     RECT  29.184 28.547 29.712 31.285 ;
     RECT  77.664 30.757 78.408 31.285 ;
     RECT  34.8 29.605 35.496 31.379 ;
     RECT  65.088 27.971 65.544 31.379 ;
     RECT  67.2 30.613 67.848 31.427 ;
     RECT  77.472 31.285 78.408 31.427 ;
     RECT  67.2 31.427 67.8 31.429 ;
     RECT  13.104 30.275 13.512 31.477 ;
     RECT  6.384 30.181 8.76 31.525 ;
     RECT  28.848 31.285 29.712 31.621 ;
     RECT  6.384 31.525 8.952 31.667 ;
     RECT  28.848 31.621 30.216 31.763 ;
     RECT  50.16 30.803 51.48 31.763 ;
     RECT  24 26.243 24.312 31.813 ;
     RECT  4.416 30.181 4.824 31.861 ;
     RECT  43.152 29.363 43.176 31.861 ;
     RECT  42.432 31.861 43.176 31.907 ;
     RECT  69.12 28.115 70.104 31.907 ;
     RECT  45.6 30.899 45.912 31.909 ;
     RECT  13.056 31.477 13.512 31.955 ;
     RECT  50.544 31.763 51.48 31.955 ;
     RECT  53.184 31.669 53.208 31.955 ;
     RECT  66.672 31.429 67.8 31.955 ;
     RECT  77.856 31.427 78.312 32.051 ;
     RECT  15.072 30.037 16.104 32.195 ;
     RECT  28.848 31.763 29.88 32.195 ;
     RECT  60.384 30.851 62.112 32.195 ;
     RECT  26.112 30.851 26.136 32.243 ;
     RECT  83.4 27.395 83.712 32.245 ;
     RECT  69.12 31.907 69.96 32.341 ;
     RECT  45.6 31.909 46.008 32.435 ;
     RECT  83.4 32.245 83.832 32.675 ;
     RECT  18.6 30.181 19.032 32.771 ;
     RECT  72.288 29.123 72.912 32.867 ;
     RECT  38.304 31.669 38.328 32.869 ;
     RECT  40.2 30.035 40.512 32.869 ;
     RECT  29.232 32.195 29.88 32.963 ;
     RECT  48.672 32.341 48.696 32.965 ;
     RECT  37.056 32.437 37.08 33.011 ;
     RECT  50.544 31.955 51.312 33.011 ;
     RECT  61.104 32.195 62.112 33.011 ;
     RECT  4.416 31.861 5.112 33.013 ;
     RECT  10.704 30.757 10.728 33.013 ;
     RECT  64.08 29.699 64.104 33.013 ;
     RECT  65.088 31.379 65.112 33.013 ;
     RECT  48.672 32.965 49.272 33.251 ;
     RECT  67.2 31.955 67.8 33.397 ;
     RECT  2.4 30.899 2.712 33.589 ;
     RECT  4.416 33.013 5.736 33.589 ;
     RECT  54.576 33.109 54.6 33.589 ;
     RECT  50.736 33.011 51.312 33.683 ;
     RECT  80.016 29.795 80.04 33.733 ;
     RECT  7.056 31.667 8.952 33.925 ;
     RECT  34.8 31.379 35.112 33.973 ;
     RECT  4.368 33.589 5.736 34.117 ;
     RECT  72.432 32.867 72.912 34.163 ;
     RECT  67.2 33.397 67.848 34.165 ;
     RECT  64.08 33.013 65.112 34.211 ;
     RECT  4.128 34.117 5.736 34.259 ;
     RECT  64.08 34.211 64.104 34.259 ;
     RECT  65.088 34.211 65.112 34.259 ;
     RECT  79.968 33.733 80.04 34.259 ;
     RECT  2.4 33.589 2.904 34.355 ;
     RECT  76.896 33.589 76.92 34.355 ;
     RECT  15.072 32.195 15.096 34.357 ;
     RECT  52.992 34.165 53.016 34.597 ;
     RECT  27.792 33.013 27.816 34.643 ;
     RECT  30.912 33.829 30.936 34.643 ;
     RECT  54.576 33.589 55.272 34.691 ;
     RECT  10.704 33.013 10.824 34.739 ;
     RECT  4.128 34.259 4.824 34.787 ;
     RECT  16.08 32.195 16.104 34.787 ;
     RECT  14.784 34.357 15.096 34.835 ;
     RECT  48.432 33.829 48.456 34.835 ;
     RECT  69.072 32.341 69.96 34.837 ;
     RECT  71.088 26.725 71.112 34.837 ;
     RECT  69.072 34.837 71.112 34.883 ;
     RECT  12 34.741 12.024 34.931 ;
     RECT  52.416 34.597 53.016 34.979 ;
     RECT  66.864 34.165 67.848 34.981 ;
     RECT  34.8 33.973 35.208 35.027 ;
     RECT  14.784 34.835 14.856 35.317 ;
     RECT  50.832 33.683 51.312 35.317 ;
     RECT  6.768 33.925 8.952 35.363 ;
     RECT  33.024 31.861 33.048 35.363 ;
     RECT  65.904 34.981 67.848 35.363 ;
     RECT  52.416 34.979 52.44 35.411 ;
     RECT  14.688 35.317 14.856 35.459 ;
     RECT  4.368 34.787 4.824 35.603 ;
     RECT  59.04 34.357 59.064 35.749 ;
     RECT  72.48 34.163 72.912 35.797 ;
     RECT  64.032 34.741 64.056 35.845 ;
     RECT  70.704 34.883 71.112 35.845 ;
     RECT  36.864 34.933 36.888 35.891 ;
     RECT  43.776 34.981 43.8 35.891 ;
     RECT  55.248 34.691 55.272 35.891 ;
     RECT  50.736 35.317 51.312 35.939 ;
     RECT  50.832 35.939 51.312 36.035 ;
     RECT  67.2 35.363 67.848 36.133 ;
     RECT  69.072 34.883 69.336 36.133 ;
     RECT  70.704 35.845 71.304 36.179 ;
     RECT  4.368 35.603 4.584 36.275 ;
     RECT  38.304 32.869 40.512 36.323 ;
     RECT  64.032 35.845 64.776 36.469 ;
     RECT  65.904 35.363 66.168 36.469 ;
     RECT  58.704 35.749 59.064 36.515 ;
     RECT  70.752 36.179 71.304 36.515 ;
     RECT  39.456 36.323 40.512 36.517 ;
     RECT  29.232 32.963 29.712 36.853 ;
     RECT  80.016 34.259 80.04 36.853 ;
     RECT  70.752 36.515 71.256 36.899 ;
     RECT  79.824 36.853 80.04 36.899 ;
     RECT  86.64 30.613 87.144 36.901 ;
     RECT  46.944 35.413 46.968 36.949 ;
     RECT  38.304 36.323 38.328 37.043 ;
     RECT  7.056 35.363 8.952 37.045 ;
     RECT  39.456 36.517 41.112 37.091 ;
     RECT  42.432 31.907 42.456 37.091 ;
     RECT  7.056 37.045 9.096 37.571 ;
     RECT  2.4 34.355 2.712 37.573 ;
     RECT  7.056 37.571 8.952 37.573 ;
     RECT  23.616 31.813 24.312 37.573 ;
     RECT  61.632 33.011 62.112 37.573 ;
     RECT  40.2 37.091 41.112 37.619 ;
     RECT  78 32.051 78.312 37.621 ;
     RECT  85.872 36.901 87.144 37.667 ;
     RECT  46.944 36.949 47.928 37.861 ;
     RECT  46.944 37.861 48.456 37.907 ;
     RECT  71.088 36.899 71.256 37.957 ;
     RECT  64.032 36.469 66.168 38.051 ;
     RECT  16.08 37.477 16.104 38.101 ;
     RECT  16.08 38.101 16.584 38.147 ;
     RECT  87.12 37.667 87.144 38.147 ;
     RECT  10.8 34.739 10.824 38.149 ;
     RECT  36.576 36.997 36.6 38.149 ;
     RECT  56.4 31.091 56.856 38.149 ;
     RECT  61.632 37.573 62.856 38.149 ;
     RECT  83.4 32.675 83.712 38.149 ;
     RECT  64.032 38.051 65.352 38.243 ;
     RECT  78 37.621 78.648 38.435 ;
     RECT  60.816 38.149 62.856 38.437 ;
     RECT  4.416 36.275 4.584 38.485 ;
     RECT  70.656 37.957 71.256 38.485 ;
     RECT  72.432 35.797 72.912 38.485 ;
     RECT  2.4 37.573 3.192 38.531 ;
     RECT  18.6 32.771 18.912 38.533 ;
     RECT  30.816 36.901 30.84 38.579 ;
     RECT  23.616 37.573 25.224 38.675 ;
     RECT  65.328 38.243 65.352 38.675 ;
     RECT  23.616 38.675 25.08 38.677 ;
     RECT  4.416 38.485 5.256 38.723 ;
     RECT  59.04 36.515 59.064 38.723 ;
     RECT  60.768 38.437 62.856 38.725 ;
     RECT  64.032 38.243 64.104 38.725 ;
     RECT  10.8 38.149 11.4 38.819 ;
     RECT  16.56 38.147 16.584 38.819 ;
     RECT  46.944 37.907 46.968 38.819 ;
     RECT  53.904 37.621 53.928 38.819 ;
     RECT  56.304 38.149 56.856 38.819 ;
     RECT  60.768 38.725 64.104 38.819 ;
     RECT  60.768 38.819 62.28 38.867 ;
     RECT  48.432 37.907 48.456 38.915 ;
     RECT  29.136 36.853 29.712 39.301 ;
     RECT  63.264 38.819 64.104 39.301 ;
     RECT  18.48 38.533 18.912 39.347 ;
     RECT  21.456 37.573 21.48 39.347 ;
     RECT  22.8 38.677 25.08 39.347 ;
     RECT  70.656 38.485 72.912 39.349 ;
     RECT  36.384 38.149 36.6 39.395 ;
     RECT  37.824 38.101 37.848 39.395 ;
     RECT  23.616 39.347 25.08 39.443 ;
     RECT  70.56 39.349 72.912 39.491 ;
     RECT  71.088 39.491 72.912 39.539 ;
     RECT  67.2 36.133 69.336 39.589 ;
     RECT  63.264 39.301 65.016 39.731 ;
     RECT  60.768 38.867 62.112 39.829 ;
     RECT  67.104 39.589 69.336 39.829 ;
     RECT  18.6 39.347 18.912 39.877 ;
     RECT  64.032 39.731 65.016 39.923 ;
     RECT  6.864 37.573 8.952 40.067 ;
     RECT  28.608 39.301 29.712 40.115 ;
     RECT  17.424 39.301 17.448 40.211 ;
     RECT  56.4 38.819 56.856 40.261 ;
     RECT  13.104 31.955 13.512 40.405 ;
     RECT  60.624 39.829 62.112 40.451 ;
     RECT  59.232 38.773 59.256 40.499 ;
     RECT  64.032 39.923 64.056 40.499 ;
     RECT  66.336 39.829 69.336 40.499 ;
     RECT  18.6 39.877 19.512 40.549 ;
     RECT  45.6 32.435 45.912 41.029 ;
     RECT  7.008 40.067 8.952 41.075 ;
     RECT  10.8 38.819 10.824 41.075 ;
     RECT  13.104 40.405 13.656 41.075 ;
     RECT  20.544 40.021 20.568 41.075 ;
     RECT  38.16 40.405 38.184 41.075 ;
     RECT  52.8 39.877 52.824 41.075 ;
     RECT  66.336 40.499 69.24 41.075 ;
     RECT  18.48 40.549 19.512 41.123 ;
     RECT  13.104 41.075 13.512 41.125 ;
     RECT  45.6 41.029 46.056 41.125 ;
     RECT  74.256 41.029 74.28 41.171 ;
     RECT  14.832 35.459 14.856 41.173 ;
     RECT  34.8 35.027 35.112 41.173 ;
     RECT  14.832 41.173 15.384 41.219 ;
     RECT  41.568 40.309 41.592 41.315 ;
     RECT  29.136 40.115 29.712 41.411 ;
     RECT  36.576 39.395 36.6 41.413 ;
     RECT  25.632 40.981 25.656 41.651 ;
     RECT  33.12 40.741 33.144 41.651 ;
     RECT  44.976 41.125 46.056 41.651 ;
     RECT  75.456 39.877 75.48 41.653 ;
     RECT  75.264 41.653 75.48 41.699 ;
     RECT  61.392 40.451 62.112 41.701 ;
     RECT  23.616 39.443 24.312 41.749 ;
     RECT  56.4 40.261 57.768 41.749 ;
     RECT  59.184 41.701 59.208 41.749 ;
     RECT  78 38.435 78.312 41.749 ;
     RECT  15.36 41.219 15.384 41.939 ;
     RECT  18.6 41.123 19.512 41.939 ;
     RECT  61.392 41.701 62.712 41.941 ;
     RECT  12.912 41.125 13.512 42.083 ;
     RECT  61.008 41.941 62.712 42.131 ;
     RECT  5.664 39.493 5.688 42.227 ;
     RECT  36.576 41.413 37.032 42.227 ;
     RECT  56.4 41.749 59.208 42.227 ;
     RECT  7.008 41.075 8.112 42.277 ;
     RECT  79.824 36.899 79.848 42.277 ;
     RECT  81.024 39.733 81.048 42.277 ;
     RECT  66.336 41.075 67.8 42.419 ;
     RECT  64.704 41.605 64.728 42.467 ;
     RECT  69.072 41.075 69.24 42.469 ;
     RECT  34.416 41.173 35.112 42.517 ;
     RECT  4.416 38.723 4.44 42.565 ;
     RECT  79.824 42.277 81.048 42.565 ;
     RECT  34.08 42.517 35.112 42.659 ;
     RECT  29.4 41.411 29.712 42.709 ;
     RECT  53.616 41.557 53.64 42.709 ;
     RECT  79.584 42.565 81.048 42.755 ;
     RECT  23.136 41.749 24.312 42.803 ;
     RECT  34.416 42.659 35.112 42.803 ;
     RECT  37.008 42.227 37.032 42.803 ;
     RECT  61.008 42.131 62.52 42.803 ;
     RECT  77.472 41.749 78.312 42.803 ;
     RECT  83.4 38.149 84.072 42.803 ;
     RECT  31.44 41.461 31.464 42.899 ;
     RECT  80.448 42.755 81.048 42.899 ;
     RECT  4.32 42.565 4.44 42.949 ;
     RECT  61.008 42.803 62.112 42.997 ;
     RECT  60.384 42.997 62.112 43.043 ;
     RECT  75.264 41.699 75.288 43.043 ;
     RECT  4.32 42.949 5.304 43.141 ;
     RECT  83.4 42.803 83.712 43.141 ;
     RECT  3.984 43.141 5.304 43.187 ;
     RECT  34.8 42.803 35.112 43.285 ;
     RECT  40.2 37.619 40.512 43.285 ;
     RECT  41.568 42.709 41.592 43.285 ;
     RECT  28.656 42.709 29.712 43.379 ;
     RECT  44.976 41.651 45.912 43.379 ;
     RECT  71.088 39.539 71.112 43.379 ;
     RECT  80.448 42.899 80.472 43.379 ;
     RECT  87.024 42.517 87.048 43.379 ;
     RECT  57.744 42.227 59.208 43.477 ;
     RECT  32.64 42.613 32.664 43.523 ;
     RECT  57.744 43.477 59.256 43.523 ;
     RECT  85.872 37.667 85.896 43.525 ;
     RECT  23.616 42.803 24.312 43.861 ;
     RECT  3.984 43.187 4.008 43.955 ;
     RECT  85.728 43.525 85.896 43.955 ;
     RECT  47.856 42.133 47.88 44.053 ;
     RECT  47.52 44.053 47.88 44.099 ;
     RECT  63.84 43.813 63.864 44.149 ;
     RECT  78 42.803 78.312 44.341 ;
     RECT  2.4 38.531 2.712 44.437 ;
     RECT  28.32 43.861 28.344 44.437 ;
     RECT  29.4 43.379 29.712 44.437 ;
     RECT  60.384 43.043 60.408 44.437 ;
     RECT  69.072 42.469 69.672 44.437 ;
     RECT  66.72 42.419 67.8 44.483 ;
     RECT  66.72 44.483 67.752 44.579 ;
     RECT  37.008 43.813 37.032 44.675 ;
     RECT  72.432 39.539 72.912 44.675 ;
     RECT  66.72 44.579 67.512 44.723 ;
     RECT  68.976 44.437 69.672 44.917 ;
     RECT  44.352 43.861 44.376 44.963 ;
     RECT  5.232 43.187 5.304 44.965 ;
     RECT  56.4 42.227 56.712 44.965 ;
     RECT  28.32 44.437 29.712 45.011 ;
     RECT  78 44.341 78.408 45.013 ;
     RECT  47.52 44.099 47.544 45.059 ;
     RECT  63.216 44.149 63.864 45.059 ;
     RECT  28.32 45.011 28.344 45.155 ;
     RECT  59.232 43.523 59.256 45.155 ;
     RECT  34.8 43.285 35.352 45.203 ;
     RECT  78 45.013 78.456 45.203 ;
     RECT  60.288 44.437 60.408 45.205 ;
     RECT  59.376 45.205 60.408 45.251 ;
     RECT  2.4 44.437 3.432 45.301 ;
     RECT  59.376 45.251 60.312 45.443 ;
     RECT  40.2 43.285 41.592 45.493 ;
     RECT  55.872 44.965 56.712 45.541 ;
     RECT  57.744 43.523 57.768 45.541 ;
     RECT  40.08 45.493 41.592 45.587 ;
     RECT  53.568 42.709 53.64 45.589 ;
     RECT  63.216 45.059 63.24 45.635 ;
     RECT  83.136 43.141 83.712 45.635 ;
     RECT  68.976 44.917 69.72 45.637 ;
     RECT  38.688 44.965 38.712 45.685 ;
     RECT  34.8 45.203 35.112 45.781 ;
     RECT  4.608 44.965 5.304 45.829 ;
     RECT  37.728 45.685 38.712 45.971 ;
     RECT  40.08 45.587 40.512 45.973 ;
     RECT  4.608 45.829 5.4 46.115 ;
     RECT  2.4 45.301 3.624 46.117 ;
     RECT  78 45.203 78.408 46.117 ;
     RECT  53.568 45.589 53.784 46.211 ;
     RECT  55.872 45.541 57.768 46.211 ;
     RECT  34.704 45.781 35.112 46.309 ;
     RECT  36.672 44.917 36.696 46.309 ;
     RECT  34.704 46.309 36.696 46.355 ;
     RECT  14.736 46.261 14.76 46.403 ;
     RECT  65.52 44.725 65.544 46.405 ;
     RECT  49.824 40.405 49.848 46.453 ;
     RECT  76.32 46.165 76.344 46.501 ;
     RECT  77.328 46.117 78.408 46.501 ;
     RECT  49.344 46.453 49.848 46.643 ;
     RECT  53.568 46.211 53.592 46.645 ;
     RECT  59.376 45.443 59.4 46.739 ;
     RECT  76.32 46.501 78.408 46.739 ;
     RECT  34.704 46.355 35.928 46.787 ;
     RECT  41.568 45.587 41.592 46.787 ;
     RECT  61.632 43.043 62.112 46.837 ;
     RECT  61.632 46.837 62.232 47.125 ;
     RECT  67.2 44.723 67.512 47.125 ;
     RECT  68.544 45.637 69.72 47.125 ;
     RECT  21.744 45.541 21.768 47.269 ;
     RECT  57.744 46.211 57.768 47.269 ;
     RECT  42.576 46.069 42.6 47.315 ;
     RECT  39.792 45.973 40.512 47.363 ;
     RECT  65.52 46.405 65.832 47.363 ;
     RECT  65.52 47.363 65.544 47.411 ;
     RECT  27.312 45.541 27.336 47.653 ;
     RECT  40.2 47.363 40.512 47.701 ;
     RECT  56.4 46.211 56.712 47.797 ;
     RECT  57.744 47.269 58.68 47.797 ;
     RECT  77.184 46.739 78.408 47.797 ;
     RECT  56.4 47.797 58.68 47.843 ;
     RECT  64.08 46.645 64.104 47.845 ;
     RECT  67.2 47.125 69.72 47.891 ;
     RECT  85.728 43.955 85.752 47.891 ;
     RECT  34.704 46.787 35.112 48.179 ;
     RECT  61.536 47.125 62.232 48.179 ;
     RECT  58.656 47.843 58.68 48.229 ;
     RECT  60.048 47.701 60.072 48.229 ;
     RECT  72.6 44.675 72.912 48.277 ;
     RECT  29.4 45.011 29.712 48.421 ;
     RECT  61.536 48.179 62.112 48.421 ;
     RECT  9.408 47.845 9.432 48.467 ;
     RECT  67.2 47.891 69.672 48.467 ;
     RECT  52.656 46.645 53.592 48.515 ;
     RECT  52.656 48.515 52.68 48.659 ;
     RECT  21.744 47.269 21.96 48.707 ;
     RECT  58.656 48.229 60.072 48.707 ;
     RECT  67.2 48.467 69.528 48.805 ;
     RECT  76.944 47.797 78.408 48.851 ;
     RECT  6.48 42.277 8.112 48.901 ;
     RECT  61.44 48.421 62.112 48.901 ;
     RECT  6.48 48.901 8.376 48.949 ;
     RECT  26.544 47.653 27.336 48.995 ;
     RECT  29.28 48.421 29.712 48.997 ;
     RECT  40.2 47.701 41.208 48.997 ;
     RECT  58.656 48.707 58.68 49.043 ;
     RECT  61.008 48.901 62.112 49.043 ;
     RECT  66.528 48.805 69.528 49.043 ;
     RECT  29.04 48.997 29.712 49.139 ;
     RECT  49.824 46.643 49.848 49.141 ;
     RECT  51 36.035 51.312 49.141 ;
     RECT  49.824 49.141 51.312 49.187 ;
     RECT  61.44 49.043 62.112 49.187 ;
     RECT  29.28 49.139 29.712 49.331 ;
     RECT  54.72 48.997 54.744 49.379 ;
     RECT  66.528 49.043 67.512 49.381 ;
     RECT  32.16 46.213 32.184 49.525 ;
     RECT  34.8 48.179 35.112 49.525 ;
     RECT  27.312 48.995 27.336 49.619 ;
     RECT  40.08 48.997 41.208 49.619 ;
     RECT  43.296 48.949 43.32 49.619 ;
     RECT  21.744 48.707 21.768 49.669 ;
     RECT  21.744 49.669 21.912 49.715 ;
     RECT  72.6 48.277 73.8 50.101 ;
     RECT  75.216 49.477 75.24 50.101 ;
     RECT  9.888 48.805 9.912 50.147 ;
     RECT  65.664 49.381 67.512 50.147 ;
     RECT  72.6 50.101 75.24 50.195 ;
     RECT  68.544 49.043 69.528 50.291 ;
     RECT  74.688 50.195 75.24 50.435 ;
     RECT  6.48 48.949 8.472 50.437 ;
     RECT  66.528 50.147 67.512 50.677 ;
     RECT  64.08 47.845 64.392 50.723 ;
     RECT  81.36 46.693 81.384 50.771 ;
     RECT  32.016 49.525 32.184 50.963 ;
     RECT  74.688 50.435 74.808 50.963 ;
     RECT  6.48 50.437 9 51.011 ;
     RECT  50.112 49.187 51.312 51.157 ;
     RECT  21.888 49.715 21.912 51.205 ;
     RECT  50.112 51.157 52.248 51.253 ;
     RECT  49.488 51.253 52.248 51.299 ;
     RECT  47.616 50.101 47.64 51.347 ;
     RECT  64.272 50.723 64.392 51.347 ;
     RECT  13.2 42.083 13.512 51.349 ;
     RECT  66.528 50.677 67.8 51.395 ;
     RECT  37.728 45.971 37.752 51.635 ;
     RECT  40.08 49.619 40.512 51.733 ;
     RECT  21.648 51.205 21.912 51.923 ;
     RECT  49.488 51.299 49.512 51.923 ;
     RECT  77.184 48.851 78.408 52.021 ;
     RECT  36.288 48.421 36.312 52.163 ;
     RECT  21.888 51.923 21.912 52.211 ;
     RECT  66.528 51.395 67.512 52.405 ;
     RECT  10.32 51.541 10.344 52.499 ;
     RECT  12.24 51.349 13.512 52.499 ;
     RECT  5.28 46.115 5.4 52.837 ;
     RECT  31.008 52.693 31.032 52.981 ;
     RECT  32.16 50.963 32.184 52.981 ;
     RECT  51 51.299 52.248 52.981 ;
     RECT  61.632 49.187 62.112 52.981 ;
     RECT  31.008 52.981 32.184 53.027 ;
     RECT  34.8 49.525 35.208 53.075 ;
     RECT  61.632 52.981 62.232 53.075 ;
     RECT  64.896 52.981 64.92 53.221 ;
     RECT  66.144 52.405 67.512 53.221 ;
     RECT  69.504 50.291 69.528 53.267 ;
     RECT  64.896 53.221 67.512 53.507 ;
     RECT  2.4 46.117 4.104 53.509 ;
     RECT  5.136 52.837 5.4 53.509 ;
     RECT  51 52.981 52.296 53.557 ;
     RECT  64.896 53.507 65.544 53.557 ;
     RECT  71.136 52.837 71.16 53.603 ;
     RECT  77.184 52.021 78.456 53.701 ;
     RECT  39.936 51.733 40.512 53.893 ;
     RECT  31.008 53.027 31.896 53.987 ;
     RECT  15.648 49.525 15.672 54.037 ;
     RECT  81.552 52.549 81.576 54.085 ;
     RECT  56.4 47.843 57.48 54.133 ;
     RECT  80.64 54.085 81.576 54.179 ;
     RECT  77.184 53.701 78.648 54.227 ;
     RECT  6.48 51.011 8.472 54.373 ;
     RECT  39.888 53.893 40.512 54.467 ;
     RECT  77.184 54.227 78.408 54.563 ;
     RECT  15.648 54.037 15.96 54.661 ;
     RECT  56.4 54.133 57.576 54.661 ;
     RECT  6.48 54.373 9.192 54.707 ;
     RECT  61.8 53.075 62.232 54.707 ;
     RECT  23.52 43.861 24.312 54.755 ;
     RECT  51 53.557 52.44 54.757 ;
     RECT  64.224 53.557 65.544 54.803 ;
     RECT  64.224 54.803 64.248 54.995 ;
     RECT  83.4 45.635 83.712 55.093 ;
     RECT  2.4 53.509 5.4 55.237 ;
     RECT  6.48 54.707 8.472 55.237 ;
     RECT  45.6 43.379 45.912 55.237 ;
     RECT  50.64 54.757 52.44 55.237 ;
     RECT  56.064 54.661 57.576 55.237 ;
     RECT  61.8 54.707 62.112 55.237 ;
     RECT  31.008 53.987 31.608 55.283 ;
     RECT  65.232 54.803 65.544 55.283 ;
     RECT  83.4 55.093 83.976 55.283 ;
     RECT  54.288 54.661 54.312 55.619 ;
     RECT  15.552 54.661 15.96 55.715 ;
     RECT  49.872 55.237 52.44 55.715 ;
     RECT  55.872 55.237 57.576 55.813 ;
     RECT  55.872 55.813 57.624 55.907 ;
     RECT  71.232 54.085 71.256 55.907 ;
     RECT  2.4 55.237 8.472 56.483 ;
     RECT  77.904 54.563 78.408 56.771 ;
     RECT  56.064 55.907 57.624 56.915 ;
     RECT  60.96 55.237 62.112 56.915 ;
     RECT  45.504 55.237 45.912 56.917 ;
     RECT  66.528 53.507 67.512 56.965 ;
     RECT  56.064 56.915 57.576 57.059 ;
     RECT  78 56.771 78.408 57.059 ;
     RECT  5.28 56.483 8.472 57.107 ;
     RECT  65.232 55.283 65.256 57.685 ;
     RECT  29.4 49.331 29.712 57.829 ;
     RECT  31.584 55.283 31.608 57.875 ;
     RECT  61.8 56.915 62.112 57.877 ;
     RECT  15.552 55.715 15.672 57.923 ;
     RECT  59.952 57.013 59.976 57.925 ;
     RECT  66.528 56.965 67.704 58.115 ;
     RECT  61.8 57.877 62.664 58.163 ;
     RECT  49.872 55.715 52.248 58.211 ;
     RECT  5.28 57.107 8.424 58.403 ;
     RECT  49.872 58.211 51.864 58.403 ;
     RECT  34.8 53.075 35.112 58.645 ;
     RECT  61.8 58.163 62.424 58.645 ;
     RECT  72.6 50.195 72.912 58.645 ;
     RECT  6.48 58.403 8.424 58.739 ;
     RECT  48.144 58.069 48.168 58.739 ;
     RECT  49.872 58.403 49.896 58.739 ;
     RECT  56.4 57.059 57.576 58.739 ;
     RECT  59.952 57.925 60.36 58.739 ;
     RECT  83.4 55.283 83.712 59.029 ;
     RECT  44.832 56.917 45.912 59.077 ;
     RECT  61.632 58.645 62.424 59.221 ;
     RECT  6.48 58.739 8.232 59.315 ;
     RECT  39.936 54.467 40.512 59.315 ;
     RECT  61.584 59.221 62.424 59.413 ;
     RECT  38.448 58.021 38.472 59.459 ;
     RECT  44.832 59.077 46.44 59.461 ;
     RECT  44.448 59.461 46.44 59.507 ;
     RECT  14.544 58.117 14.568 59.557 ;
     RECT  14.544 59.557 14.664 59.603 ;
     RECT  6.768 59.315 8.232 59.845 ;
     RECT  61.584 59.413 62.616 59.891 ;
     RECT  32.976 58.645 33 60.035 ;
     RECT  13.2 52.499 13.512 60.037 ;
     RECT  51 58.403 51.864 60.085 ;
     RECT  52.992 59.797 53.016 60.085 ;
     RECT  34.56 58.645 35.112 60.275 ;
     RECT  45.6 59.507 46.44 60.323 ;
     RECT  40.08 59.315 40.512 60.325 ;
     RECT  83.4 59.029 84.408 60.419 ;
     RECT  2.4 56.483 4.104 60.467 ;
     RECT  67.2 58.115 67.704 60.467 ;
     RECT  68.976 59.749 69 60.515 ;
     RECT  64.368 57.685 65.256 60.563 ;
     RECT  72.432 58.645 72.912 60.611 ;
     RECT  51 60.085 53.016 60.805 ;
     RECT  83.4 60.419 83.712 60.805 ;
     RECT  78 57.059 78.312 60.853 ;
     RECT  40.032 60.325 40.512 60.949 ;
     RECT  80.64 54.179 80.664 60.949 ;
     RECT  75.024 59.221 75.048 60.995 ;
     RECT  5.28 58.403 5.4 61.043 ;
     RECT  29.4 57.829 30.456 61.043 ;
     RECT  77.904 60.853 78.408 61.043 ;
     RECT  13.2 60.037 13.608 61.045 ;
     RECT  25.776 53.653 25.8 61.091 ;
     RECT  39.648 60.949 41.016 61.091 ;
     RECT  57.696 60.277 57.72 61.091 ;
     RECT  45.6 60.323 46.056 61.139 ;
     RECT  39.648 61.091 40.512 61.237 ;
     RECT  83.28 60.805 83.712 61.237 ;
     RECT  38.352 60.373 38.376 61.283 ;
     RECT  80.592 60.949 80.664 61.381 ;
     RECT  82.656 61.237 83.712 61.427 ;
     RECT  6.768 59.845 8.76 61.525 ;
     RECT  80.592 61.381 80.712 61.571 ;
     RECT  56.4 58.739 56.712 61.573 ;
     RECT  14.64 59.603 14.664 61.619 ;
     RECT  42.192 60.949 42.216 61.619 ;
     RECT  50.88 60.805 53.016 61.619 ;
     RECT  60.336 58.739 60.36 61.619 ;
     RECT  67.2 60.467 67.512 61.621 ;
     RECT  72.6 60.611 72.912 61.621 ;
     RECT  83.28 61.427 83.712 61.667 ;
     RECT  61.584 59.891 62.112 61.859 ;
     RECT  68.64 61.189 68.664 62.003 ;
     RECT  18.6 41.939 18.912 62.005 ;
     RECT  22.8 60.661 22.824 62.147 ;
     RECT  5.376 61.043 5.4 62.195 ;
     RECT  27.936 60.805 27.96 62.195 ;
     RECT  72.6 61.621 73.608 62.195 ;
     RECT  13.104 61.045 13.608 62.197 ;
     RECT  34.8 60.275 35.112 62.437 ;
     RECT  49.632 60.949 49.656 62.437 ;
     RECT  48.96 62.437 49.656 62.485 ;
     RECT  50.88 61.619 52.152 62.485 ;
     RECT  70.704 61.525 70.728 62.533 ;
     RECT  48.96 62.485 52.152 62.579 ;
     RECT  6.432 61.525 8.76 62.629 ;
     RECT  48.96 62.579 49.992 62.723 ;
     RECT  58.656 62.149 58.68 62.723 ;
     RECT  2.4 60.467 3.912 62.725 ;
     RECT  74.688 61.429 74.712 62.771 ;
     RECT  34.8 62.437 35.448 62.819 ;
     RECT  69.168 62.005 69.192 62.965 ;
     RECT  68.976 62.965 69.192 63.011 ;
     RECT  5.712 62.629 8.76 63.205 ;
     RECT  39.6 61.237 40.512 63.299 ;
     RECT  44.448 59.507 44.472 63.299 ;
     RECT  68.976 63.011 69 63.491 ;
     RECT  26.208 62.437 26.232 63.539 ;
     RECT  31.344 62.965 31.368 63.539 ;
     RECT  56.4 61.573 56.808 63.635 ;
     RECT  49.632 62.723 49.992 63.733 ;
     RECT  10.272 63.733 10.296 63.875 ;
     RECT  70.704 62.533 71.448 63.925 ;
     RECT  5.712 63.205 8.808 64.019 ;
     RECT  40.032 63.299 40.512 64.069 ;
     RECT  72.6 62.195 73.32 64.163 ;
     RECT  5.856 64.019 8.808 64.309 ;
     RECT  33.312 62.533 33.336 64.357 ;
     RECT  61.8 61.859 62.112 64.357 ;
     RECT  15.648 57.923 15.672 64.405 ;
     RECT  36.624 64.357 36.648 64.405 ;
     RECT  49.248 63.733 49.992 64.451 ;
     RECT  5.856 64.309 9.672 64.595 ;
     RECT  33.312 64.357 33.624 64.595 ;
     RECT  40.032 64.069 41.4 64.693 ;
     RECT  17.616 62.005 18.912 64.883 ;
     RECT  21.12 63.253 21.144 64.933 ;
     RECT  83.4 61.667 83.712 64.933 ;
     RECT  20.352 64.933 21.144 64.979 ;
     RECT  56.4 63.635 56.712 64.981 ;
     RECT  61.8 64.357 63.816 65.027 ;
     RECT  45.6 61.139 45.912 65.125 ;
     RECT  70.128 63.925 71.448 65.173 ;
     RECT  72.6 64.163 72.912 65.173 ;
     RECT  70.128 65.173 72.912 65.219 ;
     RECT  61.8 65.027 62.904 65.267 ;
     RECT  70.128 65.219 70.488 65.461 ;
     RECT  36.624 64.405 36.744 65.509 ;
     RECT  15.36 64.405 15.672 65.555 ;
     RECT  53.568 64.357 53.592 65.555 ;
     RECT  27.264 63.781 27.288 65.603 ;
     RECT  24 54.755 24.312 65.653 ;
     RECT  26.208 65.125 26.232 65.749 ;
     RECT  33.6 64.595 33.624 65.843 ;
     RECT  71.76 65.219 72.912 65.939 ;
     RECT  69.456 65.461 70.488 65.987 ;
     RECT  20.352 64.979 20.952 65.989 ;
     RECT  58.512 65.509 58.536 66.085 ;
     RECT  65.232 60.563 65.256 66.085 ;
     RECT  20.352 65.989 21.672 66.179 ;
     RECT  39.216 64.693 41.4 66.179 ;
     RECT  69.456 65.987 70.152 66.179 ;
     RECT  60.768 64.933 60.792 66.275 ;
     RECT  40.032 66.179 41.4 66.277 ;
     RECT  61.8 65.267 62.712 66.323 ;
     RECT  2.4 62.725 3.96 66.373 ;
     RECT  51 62.579 52.152 66.515 ;
     RECT  85.968 66.277 85.992 66.611 ;
     RECT  15.648 65.555 15.672 66.613 ;
     RECT  61.8 66.323 62.52 66.613 ;
     RECT  2.4 66.373 4.488 66.709 ;
     RECT  66.816 61.621 67.512 66.709 ;
     RECT  40.032 66.277 42.072 66.755 ;
     RECT  58.128 66.085 58.536 66.899 ;
     RECT  26.16 65.749 26.232 66.949 ;
     RECT  40.032 66.755 40.512 67.091 ;
     RECT  83.28 64.933 83.712 67.139 ;
     RECT  2.4 66.709 4.68 67.187 ;
     RECT  18.6 64.883 18.912 67.237 ;
     RECT  6 64.595 9.672 67.283 ;
     RECT  20.736 66.179 21.672 67.283 ;
     RECT  26.16 66.949 26.472 67.283 ;
     RECT  53.472 66.613 53.496 67.283 ;
     RECT  61.536 66.613 62.52 67.283 ;
     RECT  66.816 66.709 67.848 67.283 ;
     RECT  45.6 65.125 46.152 67.331 ;
     RECT  64.416 66.085 65.256 67.381 ;
     RECT  26.448 67.283 26.472 67.429 ;
     RECT  80.928 65.989 80.952 67.475 ;
     RECT  20.736 67.283 21.096 67.571 ;
     RECT  66.816 67.283 67.512 67.811 ;
     RECT  13.104 62.197 13.656 67.813 ;
     RECT  47.328 67.141 47.352 67.859 ;
     RECT  56.304 64.981 56.712 67.859 ;
     RECT  61.536 67.283 62.112 67.859 ;
     RECT  20.928 67.571 21.096 67.907 ;
     RECT  24 65.653 24.408 67.955 ;
     RECT  26.448 67.429 26.808 68.195 ;
     RECT  2.4 67.187 4.488 68.341 ;
     RECT  6 67.283 8.112 68.341 ;
     RECT  30.816 64.933 30.84 68.341 ;
     RECT  45.6 67.331 45.912 68.341 ;
     RECT  69.456 66.179 69.48 68.341 ;
     RECT  70.608 68.101 70.632 68.341 ;
     RECT  63.888 67.381 65.256 68.435 ;
     RECT  45.168 68.341 45.912 68.581 ;
     RECT  49.248 64.451 49.272 68.629 ;
     RECT  22.992 67.237 23.016 68.675 ;
     RECT  9.312 67.283 9.672 68.723 ;
     RECT  2.4 68.341 8.112 68.725 ;
     RECT  58.512 66.899 58.536 68.773 ;
     RECT  43.968 67.765 43.992 68.915 ;
     RECT  69.456 68.341 70.632 68.915 ;
     RECT  42.048 66.755 42.072 68.917 ;
     RECT  2.4 68.725 8.232 68.963 ;
     RECT  45.168 68.581 46.872 69.011 ;
     RECT  58.128 68.773 58.536 69.155 ;
     RECT  12.336 67.813 13.656 69.205 ;
     RECT  6 68.963 8.232 69.299 ;
     RECT  30.72 68.341 30.84 69.301 ;
     RECT  49.104 68.629 49.272 69.301 ;
     RECT  69.456 68.915 69.816 69.301 ;
     RECT  9.648 68.723 9.672 69.347 ;
     RECT  68.976 69.301 69.816 69.443 ;
     RECT  20.928 67.907 20.952 69.445 ;
     RECT  18.6 67.237 19.032 69.491 ;
     RECT  24 67.955 24.312 69.493 ;
     RECT  78 61.043 78.312 69.493 ;
     RECT  15.36 66.613 15.672 69.539 ;
     RECT  64.416 68.435 65.256 69.539 ;
     RECT  45.216 69.011 46.872 69.683 ;
     RECT  68.976 69.443 69.48 69.731 ;
     RECT  87.12 68.533 87.144 69.731 ;
     RECT  33.456 68.245 33.48 69.923 ;
     RECT  40.2 67.091 40.512 70.021 ;
     RECT  76.416 66.085 76.44 70.067 ;
     RECT  29.4 61.043 29.712 70.069 ;
     RECT  61.68 67.859 62.112 70.069 ;
     RECT  23.184 69.493 24.312 70.259 ;
     RECT  52.416 68.389 52.44 70.261 ;
     RECT  52.416 70.261 53.016 70.307 ;
     RECT  42.048 68.917 42.312 70.451 ;
     RECT  80.352 69.493 80.376 70.595 ;
     RECT  54.384 67.717 54.408 70.645 ;
     RECT  78 69.493 78.792 70.693 ;
     RECT  40.2 70.021 40.728 70.739 ;
     RECT  45.216 69.683 45.912 70.739 ;
     RECT  52.992 70.307 53.016 70.739 ;
     RECT  68.976 69.731 69 70.739 ;
     RECT  15.648 69.539 15.672 70.789 ;
     RECT  30.72 69.301 31.704 70.835 ;
     RECT  54.384 70.645 55.224 70.835 ;
     RECT  15.504 70.789 15.672 70.931 ;
     RECT  29.232 70.069 29.712 70.931 ;
     RECT  36.432 65.509 36.744 71.077 ;
     RECT  83.4 67.139 83.712 71.077 ;
     RECT  36.432 71.077 37.272 71.123 ;
     RECT  12.336 69.205 13.704 71.171 ;
     RECT  45.6 70.739 45.912 71.173 ;
     RECT  2.4 68.963 4.488 71.221 ;
     RECT  58.512 69.155 58.536 71.315 ;
     RECT  64.656 69.539 65.256 71.315 ;
     RECT  61.536 70.069 62.112 71.461 ;
     RECT  49.104 69.301 49.8 71.507 ;
     RECT  20.448 69.445 20.952 71.797 ;
     RECT  64.656 71.315 65.208 71.797 ;
     RECT  49.104 71.507 49.128 71.843 ;
     RECT  26.448 68.195 26.472 71.891 ;
     RECT  13.2 71.171 13.704 71.939 ;
     RECT  54.624 70.835 55.224 71.941 ;
     RECT  34.8 62.819 35.112 71.989 ;
     RECT  64.56 71.797 65.208 72.133 ;
     RECT  29.28 70.931 29.712 72.325 ;
     RECT  30.72 70.835 30.744 72.325 ;
     RECT  56.4 67.859 56.712 72.325 ;
     RECT  54.144 71.941 55.224 72.419 ;
     RECT  74.784 65.173 74.808 72.469 ;
     RECT  74.688 72.469 74.808 72.515 ;
     RECT  15.648 70.931 15.672 72.565 ;
     RECT  16.944 66.085 16.968 72.565 ;
     RECT  45.6 71.173 46.44 72.659 ;
     RECT  60.912 71.461 62.112 72.659 ;
     RECT  15.648 72.565 16.968 72.661 ;
     RECT  18.6 69.491 18.912 72.661 ;
     RECT  34.608 71.989 35.112 72.755 ;
     RECT  24 70.259 24.312 72.757 ;
     RECT  64.464 72.133 65.208 72.851 ;
     RECT  2.4 71.221 4.584 72.853 ;
     RECT  6 69.299 8.112 72.853 ;
     RECT  29.28 72.325 30.744 72.853 ;
     RECT  28.416 72.853 30.744 72.901 ;
     RECT  40.2 70.739 40.512 72.901 ;
     RECT  74.688 72.515 74.712 72.901 ;
     RECT  70.128 72.421 70.152 72.947 ;
     RECT  73.92 72.901 74.712 72.947 ;
     RECT  86.16 70.549 86.184 72.947 ;
     RECT  67.2 67.811 67.512 72.949 ;
     RECT  56.304 72.325 56.712 72.995 ;
     RECT  81.648 71.989 81.672 72.995 ;
     RECT  49.008 72.901 49.032 73.043 ;
     RECT  64.464 72.851 64.584 73.091 ;
     RECT  10.368 71.797 10.392 73.285 ;
     RECT  9.888 73.285 10.392 73.331 ;
     RECT  13.2 71.939 13.608 73.333 ;
     RECT  36.72 71.123 37.272 73.333 ;
     RECT  40.2 72.901 41.016 73.477 ;
     RECT  42.048 70.451 42.072 73.477 ;
     RECT  28.416 72.901 30.936 73.523 ;
     RECT  78 70.693 79.224 73.523 ;
     RECT  2.4 72.853 8.112 73.571 ;
     RECT  54.144 72.419 54.648 73.571 ;
     RECT  15.648 72.661 18.912 73.573 ;
     RECT  61.632 72.659 62.112 73.621 ;
     RECT  15.36 73.573 18.912 73.811 ;
     RECT  3.744 73.571 8.112 73.909 ;
     RECT  9.888 73.331 9.912 73.909 ;
     RECT  54.384 73.571 54.648 74.003 ;
     RECT  18.6 73.811 18.912 74.053 ;
     RECT  13.104 73.333 13.608 74.099 ;
     RECT  20.208 71.797 20.952 74.099 ;
     RECT  28.416 73.523 29.712 74.147 ;
     RECT  83.28 71.077 83.712 74.147 ;
     RECT  61.632 73.621 63.096 74.149 ;
     RECT  15.36 73.811 16.968 74.195 ;
     RECT  13.2 74.099 13.608 74.389 ;
     RECT  3.744 73.909 9.912 74.485 ;
     RECT  13.2 74.389 13.656 74.531 ;
     RECT  36.72 73.333 37.656 74.579 ;
     RECT  43.92 73.477 43.944 74.579 ;
     RECT  30.72 73.523 30.936 74.581 ;
     RECT  67.2 72.949 67.608 74.627 ;
     RECT  45.6 72.659 45.912 74.629 ;
     RECT  3.744 74.485 10.152 74.675 ;
     RECT  15.984 74.195 16.968 74.675 ;
     RECT  85.824 74.053 85.848 74.675 ;
     RECT  23.328 72.757 24.312 74.723 ;
     RECT  30.72 74.581 31.224 74.723 ;
     RECT  61.008 74.149 63.096 74.723 ;
     RECT  73.92 72.947 73.944 74.723 ;
     RECT  30.72 74.723 30.936 75.059 ;
     RECT  24 74.723 24.312 75.157 ;
     RECT  45.6 74.629 46.152 75.251 ;
     RECT  16.56 74.675 16.968 75.299 ;
     RECT  13.2 74.531 13.608 75.443 ;
     RECT  40.2 73.477 42.072 75.443 ;
     RECT  16.56 75.299 16.584 75.539 ;
     RECT  13.2 75.443 13.512 75.541 ;
     RECT  36.72 74.579 37.032 75.683 ;
     RECT  24 75.157 24.456 75.685 ;
     RECT  18.6 74.053 19.032 75.781 ;
     RECT  41.856 75.443 42.072 75.781 ;
     RECT  51 66.515 51.312 75.781 ;
     RECT  67.2 74.627 67.512 75.781 ;
     RECT  47.568 73.381 47.592 75.829 ;
     RECT  30.72 75.059 30.744 75.875 ;
     RECT  20.208 74.099 20.232 75.971 ;
     RECT  64.56 73.091 64.584 76.165 ;
     RECT  64.56 76.165 64.872 76.211 ;
     RECT  67.2 75.781 67.944 76.259 ;
     RECT  61.632 74.723 62.112 76.261 ;
     RECT  24 75.685 24.504 76.307 ;
     RECT  72.6 65.939 72.912 76.309 ;
     RECT  5.472 74.675 10.152 76.355 ;
     RECT  61.2 76.261 62.112 76.405 ;
     RECT  29.4 74.147 29.712 76.501 ;
     RECT  61.008 76.405 62.112 76.595 ;
     RECT  54.384 74.003 54.408 76.645 ;
     RECT  3.744 74.675 4.44 76.691 ;
     RECT  12.432 75.541 13.512 76.691 ;
     RECT  67.2 76.259 67.512 76.741 ;
     RECT  18.384 75.781 19.032 76.835 ;
     RECT  29.4 76.501 30.648 76.835 ;
     RECT  5.472 76.355 8.808 76.883 ;
     RECT  12.48 76.691 13.512 76.885 ;
     RECT  14.784 76.309 14.808 76.885 ;
     RECT  74.64 76.357 74.664 76.885 ;
     RECT  26.112 75.781 26.52 76.931 ;
     RECT  61.104 76.595 62.112 76.931 ;
     RECT  38.208 76.069 38.232 76.979 ;
     RECT  54.384 76.645 54.696 76.979 ;
     RECT  72.288 76.309 72.912 76.979 ;
     RECT  9.888 76.355 10.152 77.075 ;
     RECT  40.2 75.443 40.512 77.125 ;
     RECT  66.96 76.741 67.512 77.317 ;
     RECT  3.984 76.691 4.44 77.363 ;
     RECT  50.88 75.781 51.312 77.411 ;
     RECT  74.112 76.885 74.664 77.411 ;
     RECT  56.4 72.995 56.712 77.413 ;
     RECT  5.664 76.883 8.808 77.555 ;
     RECT  44.304 76.693 44.328 77.555 ;
     RECT  40.08 77.125 40.512 77.557 ;
     RECT  6 77.555 8.808 77.603 ;
     RECT  12.48 76.885 14.808 77.603 ;
     RECT  24 76.307 24.456 77.603 ;
     RECT  36.72 75.683 36.744 77.603 ;
     RECT  41.856 75.781 42.168 77.653 ;
     RECT  56.4 77.413 56.952 77.843 ;
     RECT  41.856 77.653 42.216 77.891 ;
     RECT  12.48 77.603 13.608 78.083 ;
     RECT  18.6 76.835 19.032 78.083 ;
     RECT  59.52 77.941 59.544 78.083 ;
     RECT  6 77.603 8.472 78.131 ;
     RECT  12.48 78.083 13.512 78.131 ;
     RECT  14.832 77.989 14.856 78.131 ;
     RECT  46.896 75.829 47.592 78.227 ;
     RECT  56.4 77.843 56.808 78.227 ;
     RECT  61.2 76.931 62.112 78.277 ;
     RECT  61.008 78.277 62.112 78.467 ;
     RECT  3.984 77.363 4.008 78.565 ;
     RECT  9.888 77.075 9.912 78.613 ;
     RECT  16.512 77.989 16.536 78.613 ;
     RECT  24 77.603 24.312 78.613 ;
     RECT  34.8 72.755 35.112 78.613 ;
     RECT  51 77.411 51.312 78.613 ;
     RECT  12.768 78.131 13.512 78.659 ;
     RECT  27.744 77.461 27.768 78.659 ;
     RECT  6.192 78.131 8.112 78.707 ;
     RECT  61.2 78.467 62.112 78.707 ;
     RECT  3.984 78.565 4.2 78.755 ;
     RECT  39.936 77.557 40.512 78.803 ;
     RECT  26.496 76.931 26.52 78.853 ;
     RECT  22.8 78.901 22.824 79.043 ;
     RECT  26.256 78.853 26.52 79.043 ;
     RECT  26.496 79.043 26.52 79.045 ;
     RECT  45.6 75.251 45.912 79.045 ;
     RECT  61.632 78.707 62.112 79.091 ;
     RECT  66.96 77.317 67.608 79.187 ;
     RECT  13.056 78.659 13.512 79.189 ;
     RECT  72.6 76.979 72.912 79.189 ;
     RECT  3.984 78.755 4.008 79.235 ;
     RECT  41.856 77.891 41.88 79.237 ;
     RECT  30.768 78.037 30.792 79.283 ;
     RECT  9.216 78.613 9.912 79.331 ;
     RECT  26.496 79.045 27.384 79.475 ;
     RECT  41.616 79.237 41.88 79.475 ;
     RECT  78 73.523 78.936 79.571 ;
     RECT  9.648 79.331 9.912 79.621 ;
     RECT  31.968 75.013 31.992 79.621 ;
     RECT  33.264 78.613 33.288 79.667 ;
     RECT  29.4 76.835 29.712 79.717 ;
     RECT  72.48 79.189 72.912 79.763 ;
     RECT  14.784 79.045 14.808 79.765 ;
     RECT  16.512 78.613 17.064 79.765 ;
     RECT  6.336 78.707 8.112 79.859 ;
     RECT  47.568 78.227 47.592 79.909 ;
     RECT  47.472 79.909 47.592 79.955 ;
     RECT  50.352 78.613 51.312 80.003 ;
     RECT  13.056 79.189 13.608 80.053 ;
     RECT  14.784 79.765 15.24 80.053 ;
     RECT  54.384 76.979 54.408 80.195 ;
     RECT  34.704 78.613 35.112 80.291 ;
     RECT  40.2 78.803 40.512 80.293 ;
     RECT  37.056 79.957 37.08 80.341 ;
     RECT  56.4 78.227 56.712 80.341 ;
     RECT  31.968 79.621 32.184 80.435 ;
     RECT  56.4 80.341 56.904 80.437 ;
     RECT  80.112 79.765 80.136 80.531 ;
     RECT  74.112 77.411 74.136 80.533 ;
     RECT  18.6 78.083 18.912 80.773 ;
     RECT  18.6 80.773 19.848 80.915 ;
     RECT  29.28 79.717 29.712 80.915 ;
     RECT  68.88 80.821 68.904 80.917 ;
     RECT  49.056 80.821 49.08 80.963 ;
     RECT  68.88 80.917 69 80.963 ;
     RECT  9.648 79.621 10.536 81.011 ;
     RECT  41.856 79.475 41.88 81.011 ;
     RECT  74.112 80.533 74.376 81.011 ;
     RECT  13.056 80.053 15.24 81.059 ;
     RECT  68.976 80.963 69 81.059 ;
     RECT  56.4 80.437 56.952 81.061 ;
     RECT  38.688 80.293 38.712 81.107 ;
     RECT  45.072 79.045 45.912 81.107 ;
     RECT  14.784 81.059 15.24 81.203 ;
     RECT  56.4 81.061 57 81.203 ;
     RECT  16.224 79.765 17.064 81.347 ;
     RECT  56.4 81.203 56.952 81.491 ;
     RECT  74.112 81.011 74.136 81.491 ;
     RECT  6.96 79.859 8.112 81.539 ;
     RECT  14.784 81.203 14.808 81.539 ;
     RECT  64.848 76.211 64.872 81.539 ;
     RECT  21.552 76.117 21.576 81.541 ;
     RECT  26.496 79.475 26.52 81.541 ;
     RECT  17.04 81.347 17.064 81.587 ;
     RECT  21.312 81.541 21.576 81.587 ;
     RECT  36.624 80.341 37.08 81.587 ;
     RECT  39.888 80.293 40.512 81.587 ;
     RECT  25.776 81.541 26.52 81.589 ;
     RECT  25.776 81.589 26.76 81.731 ;
     RECT  32.16 80.435 32.184 81.779 ;
     RECT  9.648 81.011 10.296 81.827 ;
     RECT  45.6 81.107 45.912 81.877 ;
     RECT  47.472 79.955 47.496 82.021 ;
     RECT  25.776 81.731 26.52 82.115 ;
     RECT  47.472 82.021 48.072 82.115 ;
     RECT  52.992 80.149 53.016 82.115 ;
     RECT  78 79.571 78.648 82.115 ;
     RECT  24 78.613 24.408 82.163 ;
     RECT  25.776 82.115 25.8 82.163 ;
     RECT  72.6 79.763 72.912 82.309 ;
     RECT  83.4 74.147 83.712 82.405 ;
     RECT  72.6 82.309 73.032 82.451 ;
     RECT  34.8 80.291 35.112 82.501 ;
     RECT  66.96 79.187 67.512 82.501 ;
     RECT  10.272 81.827 10.296 82.691 ;
     RECT  34.8 82.501 35.592 82.691 ;
     RECT  28.224 81.301 28.248 82.739 ;
     RECT  49.296 82.117 49.32 82.741 ;
     RECT  45.6 81.877 46.152 82.787 ;
     RECT  66.96 82.501 67.896 82.931 ;
     RECT  21.312 81.587 21.336 82.979 ;
     RECT  49.104 82.741 49.32 83.027 ;
     RECT  49.296 83.027 49.32 83.075 ;
     RECT  74.976 82.501 75 83.219 ;
     RECT  76.368 81.877 76.392 83.219 ;
     RECT  37.056 81.587 37.08 83.267 ;
     RECT  38.784 82.645 38.808 83.267 ;
     RECT  48.048 82.115 48.072 83.315 ;
     RECT  26.16 83.269 26.184 83.509 ;
     RECT  13.056 81.059 13.512 83.795 ;
     RECT  26.16 83.509 26.232 83.795 ;
     RECT  32.448 82.837 32.472 83.843 ;
     RECT  66.96 82.931 67.512 83.843 ;
     RECT  83.4 82.405 84.36 83.843 ;
     RECT  26.16 83.795 26.184 83.891 ;
     RECT  42.816 83.509 42.84 84.035 ;
     RECT  80.256 83.317 80.28 84.035 ;
     RECT  2.4 73.571 2.712 84.249 ;
     RECT  7.8 81.539 8.112 84.249 ;
     RECT  13.2 83.795 13.512 84.249 ;
     RECT  18.6 80.915 18.912 84.249 ;
     RECT  24 82.163 24.312 84.249 ;
     RECT  29.4 80.915 29.712 84.249 ;
     RECT  34.8 82.691 35.112 84.249 ;
     RECT  40.2 81.587 40.512 84.249 ;
     RECT  45.6 82.787 45.912 84.249 ;
     RECT  51 80.003 51.312 84.249 ;
     RECT  56.4 81.491 56.712 84.249 ;
     RECT  61.8 79.091 62.112 84.249 ;
     RECT  67.2 83.843 67.512 84.249 ;
     RECT  72.6 82.451 72.912 84.249 ;
     RECT  78 82.115 78.312 84.249 ;
     RECT  83.4 83.843 83.712 84.249 ;
     RECT  2.4 84.249 2.52 84.263 ;
     RECT  7.8 84.249 7.92 84.263 ;
     RECT  13.2 84.249 13.32 84.263 ;
     RECT  18.6 84.249 18.72 84.263 ;
     RECT  24 84.249 24.12 84.263 ;
     RECT  29.4 84.249 29.52 84.263 ;
     RECT  34.8 84.249 34.92 84.263 ;
     RECT  40.2 84.249 40.32 84.263 ;
     RECT  45.6 84.249 45.72 84.263 ;
     RECT  51 84.249 51.12 84.263 ;
     RECT  56.4 84.249 56.52 84.263 ;
     RECT  61.8 84.249 61.92 84.263 ;
     RECT  67.2 84.249 67.32 84.263 ;
     RECT  72.6 84.249 72.72 84.263 ;
     RECT  78 84.249 78.12 84.263 ;
     RECT  83.4 84.249 83.52 84.263 ;
     RECT  78.312 2.245 79.44 2.773 ;
     RECT  74.64 2.339 74.664 2.821 ;
     RECT  33.528 2.629 34.8 4.019 ;
     RECT  78.408 2.773 79.44 2.867 ;
     RECT  73.848 2.821 74.664 3.397 ;
     RECT  22.824 2.917 24 3.395 ;
     RECT  70.68 3.109 71.808 4.019 ;
     RECT  27.288 3.301 28.608 3.683 ;
     RECT  73.848 3.397 75.072 3.827 ;
     RECT  40.08 3.443 40.2 4.885 ;
     RECT  78.312 3.443 78.408 4.501 ;
     RECT  83.712 3.731 84.072 5.077 ;
     RECT  59.784 3.733 61.248 5.219 ;
     RECT  5.496 4.021 6.96 5.459 ;
     RECT  67.512 4.357 68.976 4.499 ;
     RECT  67.512 4.499 69.936 4.885 ;
     RECT  69.96 4.643 70.68 5.605 ;
     RECT  67.512 4.885 68.736 5.509 ;
     RECT  68.76 4.885 69.936 5.651 ;
     RECT  67.608 5.509 68.736 7.909 ;
     RECT  19.56 5.605 20.544 7.955 ;
     RECT  69.96 5.605 70.992 5.651 ;
     RECT  71.016 5.605 72.288 6.227 ;
     RECT  68.76 5.651 70.992 5.845 ;
     RECT  38.232 5.653 39.36 5.747 ;
     RECT  27.144 5.701 28.512 6.803 ;
     RECT  43.8 5.701 45.12 5.747 ;
     RECT  38.232 5.747 38.472 5.749 ;
     RECT  43.8 5.747 45.6 6.229 ;
     RECT  68.76 5.845 70.128 6.995 ;
     RECT  71.016 6.227 72.384 9.013 ;
     RECT  40.512 6.229 41.568 7.091 ;
     RECT  44.616 6.229 45.6 7.859 ;
     RECT  74.688 6.851 75.408 7.381 ;
     RECT  70.608 6.995 70.992 8.485 ;
     RECT  40.512 7.091 40.632 8.437 ;
     RECT  73.176 7.381 75.408 7.621 ;
     RECT  73.8 7.621 75.408 7.957 ;
     RECT  73.8 7.957 75.264 9.155 ;
     RECT  67.512 8.003 68.544 10.307 ;
     RECT  78.408 8.243 79.776 8.483 ;
     RECT  78.312 8.483 79.776 8.723 ;
     RECT  9.048 8.485 10.032 12.517 ;
     RECT  79.8 8.485 81.312 8.723 ;
     RECT  78.312 8.723 78.456 10.213 ;
     RECT  71.016 9.013 72.336 9.155 ;
     RECT  71.016 9.155 72.384 9.299 ;
     RECT  24.312 9.203 25.128 10.069 ;
     RECT  38.472 9.493 39.84 9.637 ;
     RECT  38.568 9.637 39.84 11.459 ;
     RECT  24.312 10.069 25.392 10.643 ;
     RECT  67.512 10.307 68.736 11.365 ;
     RECT  72.912 10.307 73.128 11.317 ;
     RECT  82.056 10.693 83.4 14.099 ;
     RECT  30.504 10.741 31.824 11.411 ;
     RECT  31.848 10.741 33.024 11.363 ;
     RECT  40.512 10.931 41.616 12.563 ;
     RECT  68.76 11.173 70.128 11.411 ;
     RECT  27.144 11.269 28.512 12.035 ;
     RECT  67.512 11.365 68.64 12.037 ;
     RECT  29.712 11.411 31.368 11.941 ;
     RECT  41.64 11.411 42.912 12.563 ;
     RECT  68.664 11.411 70.128 13.715 ;
     RECT  38.544 11.459 39.84 11.845 ;
     RECT  22.392 11.509 23.856 11.939 ;
     RECT  15.384 11.653 16.656 12.563 ;
     RECT  16.68 11.653 17.712 11.941 ;
     RECT  10.056 11.845 11.424 15.203 ;
     RECT  38.52 11.845 39.84 13.331 ;
     RECT  16.68 11.941 17.664 12.757 ;
     RECT  29.712 11.941 31.344 12.853 ;
     RECT  67.656 12.037 68.64 15.253 ;
     RECT  30.264 12.853 31.344 13.811 ;
     RECT  17.04 12.899 17.664 14.149 ;
     RECT  65.4 13.045 66.672 13.331 ;
     RECT  59.688 13.093 61.008 14.339 ;
     RECT  9.048 13.331 10.032 16.019 ;
     RECT  39.36 13.331 39.84 14.197 ;
     RECT  30.12 13.811 31.344 14.099 ;
     RECT  30.12 14.099 30.552 14.773 ;
     RECT  13.656 14.101 14.832 15.445 ;
     RECT  66.672 14.147 67.2 15.349 ;
     RECT  59.448 14.675 59.496 15.877 ;
     RECT  63.816 14.773 64.992 15.203 ;
     RECT  7.68 15.107 7.8 16.501 ;
     RECT  10.056 15.203 11.616 16.019 ;
     RECT  14.856 15.349 15.936 16.019 ;
     RECT  15.96 15.349 17.04 16.019 ;
     RECT  65.736 15.349 67.2 23.411 ;
     RECT  13.8 15.445 14.832 17.651 ;
     RECT  28.248 15.637 29.28 16.595 ;
     RECT  18.912 15.829 20.112 16.979 ;
     RECT  67.8 15.923 68.928 16.643 ;
     RECT  9.048 16.019 11.616 16.501 ;
     RECT  30.36 16.019 30.408 17.077 ;
     RECT  56.856 16.019 56.904 17.077 ;
     RECT  72.912 16.211 74.16 17.605 ;
     RECT  9.048 16.501 10.704 16.597 ;
     RECT  49.56 16.501 50.592 17.123 ;
     RECT  9.72 16.597 10.704 17.267 ;
     RECT  67.656 16.643 68.928 17.605 ;
     RECT  17.16 17.029 18.6 17.077 ;
     RECT  17.352 17.077 18.6 23.411 ;
     RECT  84.072 17.123 84.936 17.605 ;
     RECT  3.72 17.365 5.04 17.893 ;
     RECT  6.168 17.509 7.68 17.699 ;
     RECT  5.064 17.555 6.144 18.757 ;
     RECT  67.848 17.605 68.928 18.275 ;
     RECT  84.072 17.605 85.104 17.651 ;
     RECT  13.608 17.651 14.832 20.053 ;
     RECT  83.88 17.651 85.104 18.851 ;
     RECT  45.912 17.653 47.328 18.419 ;
     RECT  6.168 17.699 7.8 18.757 ;
     RECT  3.72 17.893 4.752 18.613 ;
     RECT  25.656 18.229 26.736 18.371 ;
     RECT  24.312 18.275 25.632 18.851 ;
     RECT  25.656 18.371 26.712 18.757 ;
     RECT  2.712 18.515 3.696 18.851 ;
     RECT  5.112 18.757 6.144 19.861 ;
     RECT  6.744 18.757 7.8 19.139 ;
     RECT  25.656 18.757 26.688 18.851 ;
     RECT  24.312 18.851 25.08 20.149 ;
     RECT  6.264 19.139 7.8 19.477 ;
     RECT  42.936 19.333 44.448 20.003 ;
     RECT  44.472 19.333 45.6 20.003 ;
     RECT  51.432 19.333 52.848 19.955 ;
     RECT  71.304 19.333 72.288 20.003 ;
     RECT  6.264 19.477 7.68 19.619 ;
     RECT  6.264 19.619 7.8 20.197 ;
     RECT  53.592 19.909 55.056 20.003 ;
     RECT  53.592 20.003 55.392 20.437 ;
     RECT  72.912 20.003 74.16 20.579 ;
     RECT  13.608 20.053 14.784 20.485 ;
     RECT  6.312 20.197 7.8 21.971 ;
     RECT  62.112 20.339 62.664 21.637 ;
     RECT  53.976 20.437 55.392 20.965 ;
     RECT  10.296 20.485 11.616 21.155 ;
     RECT  78.648 20.533 80.064 21.155 ;
     RECT  64.368 20.579 64.992 21.541 ;
     RECT  67.8 20.629 69.312 21.637 ;
     RECT  14.856 20.773 15.936 21.683 ;
     RECT  15.96 20.773 17.328 21.683 ;
     RECT  10.296 21.155 11.76 21.683 ;
     RECT  13.512 21.155 14.832 23.317 ;
     RECT  23.712 21.203 24 22.549 ;
     RECT  54.168 21.299 55.392 22.259 ;
     RECT  64.368 21.541 64.416 21.637 ;
     RECT  8.112 21.589 9.552 23.125 ;
     RECT  35.112 21.635 35.448 23.125 ;
     RECT  62.904 21.637 64.416 22.451 ;
     RECT  67.8 21.637 69.12 23.317 ;
     RECT  11.784 21.683 13.2 22.259 ;
     RECT  56.856 21.683 57.624 22.741 ;
     RECT  31.32 22.211 31.944 22.643 ;
     RECT  2.712 22.309 4.08 22.693 ;
     RECT  64.08 22.451 64.416 22.787 ;
     RECT  31.44 22.643 31.944 23.317 ;
     RECT  2.712 22.693 3.984 25.523 ;
     RECT  56.856 22.741 58.128 24.371 ;
     RECT  64.08 22.787 64.992 23.555 ;
     RECT  8.112 23.125 9.456 24.563 ;
     RECT  9.672 23.269 10.848 23.315 ;
     RECT  9.576 23.315 10.848 24.515 ;
     RECT  13.608 23.317 14.832 23.411 ;
     RECT  31.44 23.317 32.304 23.605 ;
     RECT  78.312 23.317 79.44 26.629 ;
     RECT  16.92 23.411 18.6 23.939 ;
     RECT  65.112 23.411 65.544 24.469 ;
     RECT  64.08 23.555 65.088 23.893 ;
     RECT  22.392 23.653 23.712 23.893 ;
     RECT  64.104 23.893 65.088 33.013 ;
     RECT  18.24 23.939 18.6 24.373 ;
     RECT  56.856 24.371 58.104 25.333 ;
     RECT  26.232 24.469 27.312 25.427 ;
     RECT  33.672 24.469 34.8 25.667 ;
     RECT  48.888 24.469 50.352 25.715 ;
     RECT  8.112 24.563 9.552 26.053 ;
     RECT  55.272 24.563 56.4 25.139 ;
     RECT  4.008 24.659 5.328 25.523 ;
     RECT  79.464 25.091 79.656 25.573 ;
     RECT  53.304 25.093 54.816 25.139 ;
     RECT  56.856 25.333 58.08 25.477 ;
     RECT  26.232 25.427 26.664 26.341 ;
     RECT  57.096 25.477 58.08 27.203 ;
     RECT  79.464 25.573 80.928 26.293 ;
     RECT  72.912 25.621 74.016 29.795 ;
     RECT  33.648 25.667 34.8 26.485 ;
     RECT  50.16 25.715 50.352 27.061 ;
     RECT  5.736 26.003 7.056 26.243 ;
     RECT  8.568 26.053 9.552 29.123 ;
     RECT  66.12 26.197 67.2 27.971 ;
     RECT  13.512 26.243 13.608 27.301 ;
     RECT  22.68 26.243 24 27.923 ;
     RECT  33.624 26.485 34.8 28.547 ;
     RECT  78.408 26.629 79.44 28.307 ;
     RECT  18.912 26.725 20.112 27.923 ;
     RECT  58.68 26.725 60.192 27.395 ;
     RECT  71.112 26.725 72.288 27.877 ;
     RECT  74.04 26.771 74.712 28.261 ;
     RECT  79.752 27.059 80.928 27.347 ;
     RECT  56.856 27.203 58.08 29.077 ;
     RECT  13.848 27.301 15.216 27.923 ;
     RECT  79.464 27.347 80.928 28.787 ;
     RECT  5.976 27.877 7.056 28.499 ;
     RECT  9.576 27.877 10.8 29.123 ;
     RECT  71.112 27.877 72.096 29.123 ;
     RECT  70.104 28.069 71.088 31.907 ;
     RECT  67.8 28.115 69.12 30.613 ;
     RECT  54.984 28.117 56.4 29.027 ;
     RECT  74.04 28.261 75.36 29.363 ;
     RECT  78.312 28.307 79.44 29.795 ;
     RECT  15.6 28.403 16.08 29.605 ;
     RECT  51.312 28.691 51.48 30.037 ;
     RECT  79.464 28.787 80.04 29.749 ;
     RECT  77.088 28.979 77.664 29.221 ;
     RECT  56.952 29.077 58.08 29.939 ;
     RECT  8.568 29.123 8.76 30.181 ;
     RECT  71.112 29.123 72.288 32.867 ;
     RECT  26.16 29.219 26.184 30.229 ;
     RECT  76.152 29.221 77.664 29.363 ;
     RECT  74.04 29.363 75.288 29.795 ;
     RECT  75.264 29.795 75.288 29.893 ;
     RECT  78.312 29.795 78.408 30.757 ;
     RECT  59.88 29.893 61.104 30.805 ;
     RECT  26.088 30.229 26.184 30.613 ;
     RECT  13.056 30.275 13.104 31.477 ;
     RECT  46.728 30.565 47.856 30.803 ;
     RECT  67.848 30.613 69.12 31.427 ;
     RECT  3 30.661 4.416 30.803 ;
     RECT  2.904 30.803 4.416 30.899 ;
     RECT  45.912 30.899 46.008 31.909 ;
     RECT  67.8 31.427 69.12 32.341 ;
     RECT  6.384 31.667 7.056 31.861 ;
     RECT  50.16 31.763 50.544 32.341 ;
     RECT  5.112 31.861 7.056 33.013 ;
     RECT  69.96 31.907 71.088 34.837 ;
     RECT  15.096 32.195 16.08 34.787 ;
     RECT  28.848 32.195 29.232 33.013 ;
     RECT  48.696 32.341 50.544 32.965 ;
     RECT  67.8 32.341 69.072 33.397 ;
     RECT  37.08 32.437 38.304 33.011 ;
     RECT  71.112 32.867 72.432 34.163 ;
     RECT  29.712 32.963 29.88 33.829 ;
     RECT  49.272 32.965 50.544 33.011 ;
     RECT  49.272 33.011 50.736 33.251 ;
     RECT  5.736 33.013 7.056 33.925 ;
     RECT  27.816 33.013 29.232 34.643 ;
     RECT  67.848 33.397 69.072 36.133 ;
     RECT  2.904 33.589 4.368 34.117 ;
     RECT  55.272 33.589 56.4 35.891 ;
     RECT  76.92 33.589 78 34.355 ;
     RECT  29.712 33.829 30.912 34.643 ;
     RECT  5.736 33.925 6.768 34.259 ;
     RECT  2.904 34.117 4.128 34.355 ;
     RECT  71.112 34.163 72.48 35.797 ;
     RECT  64.104 34.211 65.088 34.259 ;
     RECT  2.712 34.355 4.128 34.787 ;
     RECT  13.512 34.357 14.784 35.317 ;
     RECT  51.312 34.597 52.416 35.411 ;
     RECT  10.824 34.741 12 34.931 ;
     RECT  12.024 34.741 13.104 34.931 ;
     RECT  69.336 34.883 70.704 36.179 ;
     RECT  36.888 34.933 38.304 35.891 ;
     RECT  42.456 34.981 43.776 35.891 ;
     RECT  13.512 35.317 14.688 35.459 ;
     RECT  66.168 35.363 67.2 38.051 ;
     RECT  45.912 35.413 46.944 38.819 ;
     RECT  13.512 35.459 14.832 40.405 ;
     RECT  71.112 35.797 72.432 35.845 ;
     RECT  64.776 35.845 65.904 36.469 ;
     RECT  71.304 35.845 72.432 36.515 ;
     RECT  69.336 36.179 70.752 36.899 ;
     RECT  4.368 36.275 4.416 37.573 ;
     RECT  38.328 36.323 39.456 37.043 ;
     RECT  71.256 36.515 72.432 38.485 ;
     RECT  41.112 36.517 42.432 37.091 ;
     RECT  78.312 36.853 79.824 37.621 ;
     RECT  69.336 36.899 71.088 37.957 ;
     RECT  29.712 36.901 30.816 38.579 ;
     RECT  35.112 36.997 36.576 38.149 ;
     RECT  14.856 37.477 16.08 38.147 ;
     RECT  3.192 37.573 4.416 38.531 ;
     RECT  62.856 37.573 64.032 38.725 ;
     RECT  78.648 37.621 79.824 38.435 ;
     RECT  85.896 37.667 87.12 38.147 ;
     RECT  46.968 37.907 48.432 38.819 ;
     RECT  69.336 37.957 70.656 39.349 ;
     RECT  36.6 38.101 37.824 39.395 ;
     RECT  35.112 38.149 36.384 39.395 ;
     RECT  64.104 38.243 65.328 38.675 ;
     RECT  78.312 38.435 79.824 42.565 ;
     RECT  64.104 38.675 65.352 39.301 ;
     RECT  21.48 38.677 22.8 39.347 ;
     RECT  4.44 38.723 5.256 39.493 ;
     RECT  59.256 38.773 60.768 39.829 ;
     RECT  62.28 38.819 63.264 38.867 ;
     RECT  62.112 38.867 63.264 39.731 ;
     RECT  17.448 39.301 18.48 39.347 ;
     RECT  65.016 39.301 65.352 39.829 ;
     RECT  17.448 39.347 18.6 40.211 ;
     RECT  69.336 39.349 70.56 39.491 ;
     RECT  35.112 39.395 36.576 42.227 ;
     RECT  4.44 39.493 5.664 42.227 ;
     RECT  5.688 39.493 6.864 40.067 ;
     RECT  71.112 39.539 72.432 43.379 ;
     RECT  79.848 39.733 81.024 42.277 ;
     RECT  59.256 39.829 60.624 40.451 ;
     RECT  65.016 39.829 66.336 39.923 ;
     RECT  51.312 39.877 52.8 41.075 ;
     RECT  19.512 40.021 20.544 41.075 ;
     RECT  5.688 40.067 7.008 42.227 ;
     RECT  18.48 40.211 18.6 40.549 ;
     RECT  57.768 40.261 59.232 40.499 ;
     RECT  40.512 40.309 41.568 41.315 ;
     RECT  13.656 40.405 14.832 41.075 ;
     RECT  49.848 40.405 51 49.141 ;
     RECT  61.008 40.451 61.392 41.941 ;
     RECT  57.768 40.499 59.208 41.701 ;
     RECT  24.312 40.981 25.632 41.651 ;
     RECT  72.912 41.029 74.256 41.171 ;
     RECT  74.28 41.029 75.456 41.171 ;
     RECT  13.512 41.075 14.832 41.219 ;
     RECT  67.8 41.075 69.072 44.437 ;
     RECT  75.264 41.171 75.456 41.653 ;
     RECT  33.144 41.173 34.416 41.651 ;
     RECT  40.512 41.315 41.592 42.709 ;
     RECT  29.136 41.411 29.4 42.709 ;
     RECT  33.12 41.651 34.416 42.517 ;
     RECT  57.768 41.701 59.184 41.749 ;
     RECT  4.44 42.227 7.008 42.277 ;
     RECT  35.112 42.227 35.352 43.285 ;
     RECT  56.712 42.227 57.744 45.541 ;
     RECT  4.44 42.277 6.48 42.949 ;
     RECT  69.672 42.469 71.088 43.379 ;
     RECT  33.12 42.517 34.08 42.613 ;
     RECT  85.896 42.517 87.024 43.379 ;
     RECT  78.312 42.565 79.584 42.755 ;
     RECT  31.464 42.613 32.64 42.899 ;
     RECT  32.664 42.613 34.08 42.659 ;
     RECT  40.512 42.709 41.568 43.285 ;
     RECT  23.52 42.803 23.616 43.861 ;
     RECT  37.008 42.803 37.032 43.813 ;
     RECT  62.112 42.803 62.52 43.813 ;
     RECT  5.304 42.949 6.48 45.829 ;
     RECT  59.208 42.997 60.384 43.477 ;
     RECT  60.408 43.043 61.632 45.251 ;
     RECT  2.712 43.141 3.984 43.955 ;
     RECT  4.008 43.187 5.232 43.955 ;
     RECT  28.656 43.379 29.4 43.861 ;
     RECT  44.976 43.379 45.6 43.861 ;
     RECT  59.256 43.477 60.384 44.437 ;
     RECT  57.768 43.523 59.232 45.155 ;
     RECT  62.112 43.813 63.84 44.149 ;
     RECT  28.344 43.861 29.4 44.437 ;
     RECT  44.376 43.861 45.6 44.963 ;
     RECT  2.712 43.955 5.232 44.437 ;
     RECT  62.112 44.149 63.216 45.635 ;
     RECT  3.432 44.437 5.232 44.965 ;
     RECT  59.256 44.437 60.288 45.155 ;
     RECT  67.8 44.437 68.976 44.483 ;
     RECT  67.752 44.483 68.976 44.579 ;
     RECT  67.512 44.579 68.976 45.637 ;
     RECT  37.008 44.675 37.032 44.917 ;
     RECT  35.352 44.917 36.672 45.203 ;
     RECT  36.696 44.917 37.032 45.685 ;
     RECT  3.432 44.965 4.608 45.301 ;
     RECT  38.712 44.965 40.2 45.493 ;
     RECT  28.344 45.011 29.4 45.155 ;
     RECT  59.376 45.155 60.288 45.205 ;
     RECT  35.112 45.203 36.672 46.309 ;
     RECT  60.312 45.251 61.632 45.443 ;
     RECT  3.624 45.301 4.608 46.115 ;
     RECT  38.712 45.493 40.08 45.971 ;
     RECT  40.512 45.587 41.568 46.787 ;
     RECT  62.112 45.635 62.232 46.837 ;
     RECT  67.512 45.637 68.544 47.125 ;
     RECT  36.696 45.685 37.728 46.355 ;
     RECT  5.4 45.829 6.48 55.237 ;
     RECT  39.792 45.971 40.08 45.973 ;
     RECT  41.592 46.069 42.576 46.787 ;
     RECT  3.624 46.115 5.28 46.117 ;
     RECT  4.104 46.117 5.28 52.837 ;
     RECT  76.344 46.165 77.328 46.501 ;
     RECT  56.712 46.211 57.744 47.797 ;
     RECT  13.512 46.261 14.736 46.403 ;
     RECT  65.832 46.405 67.2 47.363 ;
     RECT  51.312 46.645 52.656 48.659 ;
     RECT  64.104 46.645 65.52 47.411 ;
     RECT  59.376 46.739 59.4 47.269 ;
     RECT  76.944 46.739 77.184 47.797 ;
     RECT  40.512 46.787 42.576 47.315 ;
     RECT  58.68 47.269 59.4 47.701 ;
     RECT  40.512 47.315 41.208 47.701 ;
     RECT  65.544 47.363 67.2 47.411 ;
     RECT  64.104 47.411 64.392 47.845 ;
     RECT  66.528 47.411 67.2 48.805 ;
     RECT  58.68 47.701 60.048 48.229 ;
     RECT  60.072 47.701 61.536 48.421 ;
     RECT  57.48 47.843 58.656 49.043 ;
     RECT  8.112 47.845 9.408 48.467 ;
     RECT  35.112 48.421 36.288 49.525 ;
     RECT  36.312 48.421 37.728 51.635 ;
     RECT  60.072 48.421 61.44 48.707 ;
     RECT  8.112 48.467 9.432 48.805 ;
     RECT  21.768 48.707 21.912 49.669 ;
     RECT  61.008 48.707 61.44 48.901 ;
     RECT  8.112 48.805 9.888 48.901 ;
     RECT  8.376 48.901 9.888 48.949 ;
     RECT  8.472 48.949 9.888 50.147 ;
     RECT  67.512 49.043 68.544 50.291 ;
     RECT  64.392 49.381 65.664 50.147 ;
     RECT  73.8 49.477 75.216 50.101 ;
     RECT  35.208 49.525 36.288 52.163 ;
     RECT  21.744 49.715 21.888 51.205 ;
     RECT  8.472 50.147 9 50.437 ;
     RECT  67.512 50.291 67.8 50.677 ;
     RECT  49.512 51.299 51 51.923 ;
     RECT  29.712 52.693 31.008 55.283 ;
     RECT  31.032 52.693 32.16 52.981 ;
     RECT  4.104 52.837 5.136 53.509 ;
     RECT  71.16 52.837 72.6 53.603 ;
     RECT  64.92 52.981 66.144 53.221 ;
     RECT  65.544 53.507 66.528 55.283 ;
     RECT  71.232 53.603 72.6 54.085 ;
     RECT  24.312 53.653 25.776 61.091 ;
     RECT  71.256 54.085 72.6 55.907 ;
     RECT  64.248 54.803 65.232 54.995 ;
     RECT  65.256 55.283 66.528 58.115 ;
     RECT  4.104 56.483 5.28 60.467 ;
     RECT  60.96 56.915 61.8 57.013 ;
     RECT  59.976 57.013 61.8 57.925 ;
     RECT  30.456 57.829 31.584 57.875 ;
     RECT  15.552 57.923 15.648 58.117 ;
     RECT  60.36 57.925 61.8 58.645 ;
     RECT  38.472 58.021 39.936 59.315 ;
     RECT  13.512 58.117 14.544 59.603 ;
     RECT  14.568 58.117 15.648 59.557 ;
     RECT  62.424 58.163 62.616 59.413 ;
     RECT  5.4 58.403 6.48 59.315 ;
     RECT  49.896 58.403 51 58.739 ;
     RECT  60.36 58.645 61.632 59.221 ;
     RECT  8.232 58.739 8.424 59.845 ;
     RECT  60.36 59.221 61.584 61.619 ;
     RECT  5.4 59.315 6.768 61.525 ;
     RECT  40.032 59.315 40.08 60.325 ;
     RECT  38.448 59.459 38.472 60.373 ;
     RECT  44.472 59.507 45.6 63.299 ;
     RECT  14.664 59.557 15.648 61.619 ;
     RECT  13.512 59.603 14.64 60.037 ;
     RECT  67.704 59.749 68.976 60.467 ;
     RECT  51.864 59.797 52.992 60.085 ;
     RECT  13.608 60.037 14.64 61.619 ;
     RECT  56.712 60.277 57.696 61.091 ;
     RECT  38.376 60.373 38.472 60.949 ;
     RECT  3.912 60.467 5.28 61.043 ;
     RECT  67.512 60.467 68.976 60.515 ;
     RECT  67.512 60.515 69 61.189 ;
     RECT  22.824 60.661 24 62.147 ;
     RECT  27.96 60.805 29.4 62.195 ;
     RECT  38.376 60.949 39.648 61.237 ;
     RECT  41.016 60.949 42.192 61.091 ;
     RECT  49.656 60.949 50.88 62.485 ;
     RECT  3.912 61.043 5.376 62.195 ;
     RECT  56.712 61.091 56.808 61.573 ;
     RECT  67.512 61.189 68.64 62.003 ;
     RECT  68.664 61.189 69 62.003 ;
     RECT  38.376 61.237 39.6 61.283 ;
     RECT  5.4 61.525 6.432 62.195 ;
     RECT  13.608 61.619 13.656 62.197 ;
     RECT  73.608 61.621 74.688 62.195 ;
     RECT  67.512 62.003 69 62.005 ;
     RECT  67.512 62.005 69.168 62.965 ;
     RECT  69.192 62.005 70.704 63.011 ;
     RECT  3.912 62.195 3.96 62.725 ;
     RECT  5.712 62.195 6.432 62.629 ;
     RECT  73.32 62.195 74.688 62.771 ;
     RECT  33.336 62.533 34.8 64.357 ;
     RECT  71.448 62.533 72.6 65.173 ;
     RECT  49.992 62.579 51 64.451 ;
     RECT  49.248 62.723 49.632 63.733 ;
     RECT  67.512 62.965 68.976 63.491 ;
     RECT  69 63.011 70.704 63.491 ;
     RECT  39.6 63.299 40.032 64.693 ;
     RECT  70.128 63.491 70.704 63.925 ;
     RECT  8.808 63.733 10.272 63.875 ;
     RECT  8.808 63.875 9.672 64.309 ;
     RECT  33.624 64.357 34.8 65.843 ;
     RECT  35.112 64.357 36.624 65.509 ;
     RECT  52.152 64.357 53.568 65.555 ;
     RECT  63.816 64.357 65.232 65.027 ;
     RECT  18.912 64.933 20.352 66.179 ;
     RECT  29.712 64.933 30.816 68.341 ;
     RECT  60.792 64.933 61.8 66.275 ;
     RECT  20.952 64.979 21.144 65.989 ;
     RECT  62.904 65.027 65.232 65.267 ;
     RECT  26.232 65.125 27.264 65.603 ;
     RECT  70.488 65.219 71.76 65.939 ;
     RECT  64.416 65.267 65.232 66.085 ;
     RECT  35.112 65.509 36.432 71.123 ;
     RECT  15.36 65.555 15.648 66.613 ;
     RECT  52.152 65.555 53.496 66.515 ;
     RECT  26.232 65.603 26.472 66.949 ;
     RECT  15.672 66.085 16.944 72.565 ;
     RECT  56.712 66.085 58.128 66.899 ;
     RECT  18.912 66.179 19.032 67.237 ;
     RECT  61.536 66.275 61.8 66.613 ;
     RECT  4.488 66.373 6 66.709 ;
     RECT  53.472 66.515 53.496 66.613 ;
     RECT  4.68 66.709 6 67.187 ;
     RECT  46.152 67.141 47.328 67.331 ;
     RECT  4.488 67.187 6 68.341 ;
     RECT  21.672 67.237 22.992 67.283 ;
     RECT  23.016 67.237 24 68.675 ;
     RECT  8.112 67.283 9.312 68.723 ;
     RECT  45.912 67.331 47.328 67.859 ;
     RECT  45.912 67.859 46.872 68.581 ;
     RECT  69.48 68.101 70.608 68.341 ;
     RECT  33.48 68.245 34.8 69.923 ;
     RECT  29.712 68.341 30.72 72.325 ;
     RECT  43.992 68.341 45.168 68.915 ;
     RECT  51.312 68.389 52.416 70.307 ;
     RECT  23.184 68.675 24 69.493 ;
     RECT  8.112 68.723 9.648 68.725 ;
     RECT  8.232 68.725 9.648 69.299 ;
     RECT  56.712 68.773 58.128 69.155 ;
     RECT  4.488 68.963 6 71.221 ;
     RECT  49.8 69.301 51 71.507 ;
     RECT  67.512 69.301 68.976 70.739 ;
     RECT  19.032 69.445 20.448 69.491 ;
     RECT  15.504 69.539 15.648 70.789 ;
     RECT  45.912 69.683 46.44 71.173 ;
     RECT  40.728 70.021 42.048 70.739 ;
     RECT  53.016 70.261 54.384 70.739 ;
     RECT  55.224 70.645 56.4 72.325 ;
     RECT  54.144 70.739 54.384 70.835 ;
     RECT  54.144 70.835 54.624 71.941 ;
     RECT  4.584 71.221 6 72.853 ;
     RECT  18.912 71.797 20.208 74.053 ;
     RECT  55.224 72.325 56.304 72.419 ;
     RECT  61.008 72.659 61.632 74.149 ;
     RECT  41.016 72.901 42.048 73.477 ;
     RECT  72.912 72.901 73.92 74.723 ;
     RECT  64.464 73.091 64.56 73.621 ;
     RECT  9.912 73.331 10.152 74.485 ;
     RECT  29.712 73.523 30.72 75.875 ;
     RECT  2.712 73.571 3.744 76.691 ;
     RECT  63.096 73.621 64.56 74.723 ;
     RECT  19.032 74.053 20.208 75.971 ;
     RECT  13.104 74.099 13.2 75.541 ;
     RECT  37.032 74.579 37.656 75.683 ;
     RECT  67.512 74.627 67.608 75.781 ;
     RECT  46.152 74.629 47.568 75.251 ;
     RECT  4.44 74.675 5.472 76.883 ;
     RECT  30.936 74.723 31.224 75.013 ;
     RECT  30.936 75.013 31.968 75.059 ;
     RECT  30.744 75.059 31.968 75.875 ;
     RECT  45.912 75.251 47.568 75.829 ;
     RECT  13.512 75.443 13.608 76.309 ;
     RECT  40.512 75.443 41.856 79.237 ;
     RECT  36.744 75.683 37.656 76.069 ;
     RECT  45.912 75.829 46.896 78.227 ;
     RECT  29.712 75.875 31.968 76.501 ;
     RECT  36.744 76.069 38.208 76.979 ;
     RECT  67.512 76.259 67.608 77.317 ;
     RECT  13.512 76.309 14.784 76.885 ;
     RECT  8.808 76.355 9.888 77.603 ;
     RECT  30.648 76.501 31.968 76.835 ;
     RECT  2.712 76.691 3.984 79.235 ;
     RECT  44.328 76.693 45.6 77.555 ;
     RECT  29.712 76.835 31.968 78.037 ;
     RECT  4.44 76.883 5.664 77.363 ;
     RECT  72.912 76.885 74.112 81.491 ;
     RECT  61.104 76.931 61.2 78.277 ;
     RECT  4.008 77.363 5.664 77.555 ;
     RECT  50.88 77.411 51 78.613 ;
     RECT  26.52 77.461 27.744 78.659 ;
     RECT  4.008 77.555 4.2 78.565 ;
     RECT  45.072 77.555 45.6 79.045 ;
     RECT  8.472 77.603 9.888 78.131 ;
     RECT  13.608 77.603 14.808 77.989 ;
     RECT  24.312 77.603 24.408 78.613 ;
     RECT  13.608 77.989 14.832 78.083 ;
     RECT  29.712 78.037 30.768 79.283 ;
     RECT  30.792 78.037 31.968 79.283 ;
     RECT  13.512 78.083 14.832 78.131 ;
     RECT  8.112 78.131 9.888 78.613 ;
     RECT  13.512 78.131 14.808 79.045 ;
     RECT  8.112 78.613 9.216 79.331 ;
     RECT  31.992 78.613 33.264 79.621 ;
     RECT  33.288 78.613 34.704 79.667 ;
     RECT  26.52 78.659 27.384 79.045 ;
     RECT  39.936 78.803 40.2 80.293 ;
     RECT  21.576 78.901 22.8 79.043 ;
     RECT  22.824 78.901 24 79.043 ;
     RECT  13.512 79.045 14.784 79.189 ;
     RECT  13.608 79.189 14.784 80.053 ;
     RECT  40.512 79.237 41.616 79.475 ;
     RECT  40.512 79.475 41.856 81.011 ;
     RECT  78.648 79.571 78.936 79.765 ;
     RECT  32.184 79.621 33.264 79.667 ;
     RECT  15.24 79.765 16.224 81.203 ;
     RECT  78.648 79.765 80.112 80.531 ;
     RECT  53.016 80.149 54.384 80.195 ;
     RECT  38.712 80.293 39.888 81.107 ;
     RECT  35.112 80.341 36.624 81.587 ;
     RECT  67.512 80.821 68.88 80.963 ;
     RECT  29.28 80.915 29.4 81.301 ;
     RECT  49.056 80.963 49.08 82.021 ;
     RECT  67.512 80.963 68.976 81.059 ;
     RECT  13.512 81.059 14.784 81.539 ;
     RECT  67.512 81.059 67.896 82.501 ;
     RECT  14.808 81.203 16.224 81.347 ;
     RECT  28.248 81.301 29.4 82.739 ;
     RECT  72.912 81.491 73.032 82.309 ;
     RECT  24.408 81.541 25.776 82.163 ;
     RECT  35.112 81.587 37.056 82.501 ;
     RECT  39.888 81.587 40.2 82.645 ;
     RECT  26.76 81.589 28.224 81.731 ;
     RECT  46.152 81.877 47.472 82.115 ;
     RECT  48.072 82.021 49.08 82.117 ;
     RECT  25.8 82.115 26.232 82.163 ;
     RECT  48.072 82.117 49.296 82.741 ;
     RECT  26.16 82.163 26.232 83.269 ;
     RECT  35.592 82.501 37.056 82.691 ;
     RECT  75 82.501 76.368 83.219 ;
     RECT  38.808 82.645 40.2 83.267 ;
     RECT  48.072 82.741 49.104 83.027 ;
     RECT  48.072 83.027 49.296 83.075 ;
     RECT  26.184 83.269 26.232 83.509 ;
  END
END ot_s81sl_cap_tr
END LIBRARY
